VERSION 5.8 ;
BUSBITCHARS "[]" ;
DIVIDERCHAR "/" ;
UNITS
    DATABASE MICRONS 1000 ;
END UNITS

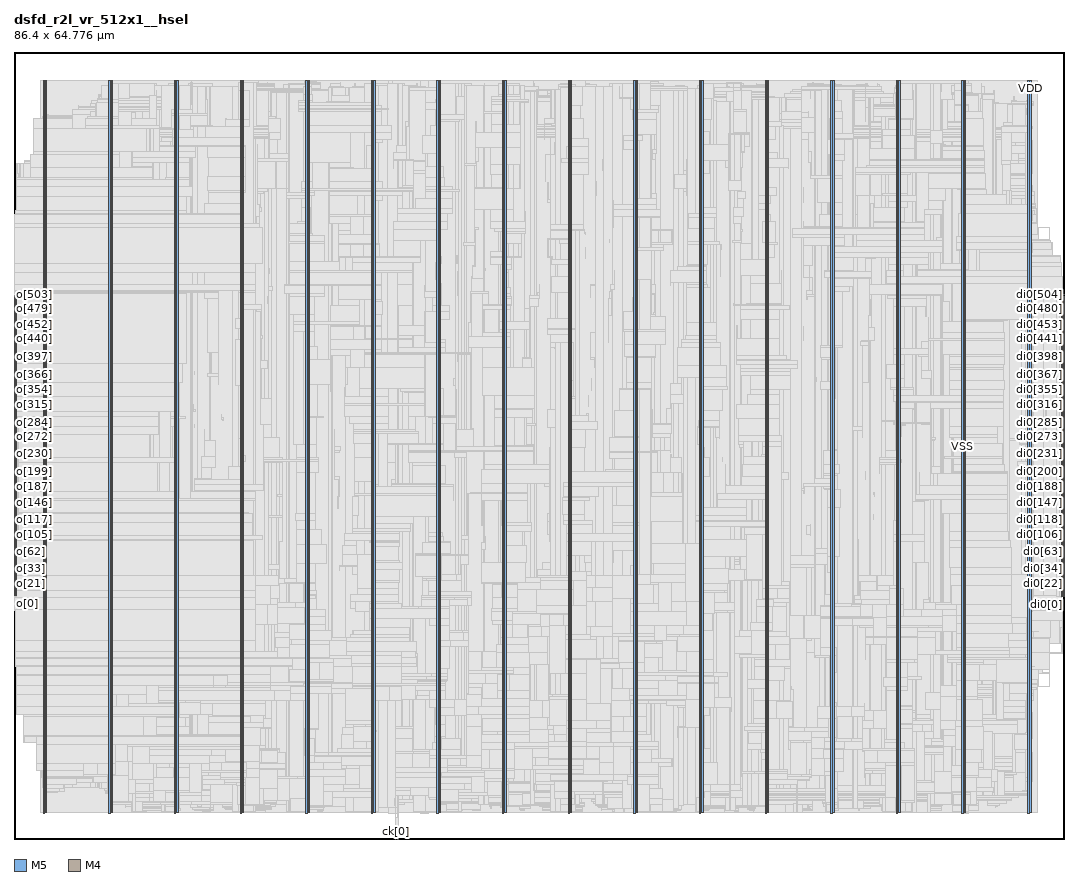
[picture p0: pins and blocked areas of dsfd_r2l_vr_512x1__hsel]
MACRO dsfd_r2l_vr_512x1__hsel
  FOREIGN dsfd_r2l_vr_512x1__hsel 0 0 ;
  CLASS BLOCK ;
  SIZE 86.4 BY 64.776 ;
  PIN ck[0]
    DIRECTION INPUT ;
    USE SIGNAL ;
    PORT
      LAYER M5 ;
        RECT  31.392 0 31.416 0.192 ;
    END
  END ck[0]
  PIN di0[0]
    DIRECTION INPUT ;
    USE SIGNAL ;
    PORT
      LAYER M4 ;
        RECT  86.208 19.968 86.4 19.992 ;
    END
  END di0[0]
  PIN di0[100]
    DIRECTION INPUT ;
    USE SIGNAL ;
    PORT
      LAYER M4 ;
        RECT  86.208 24.768 86.4 24.792 ;
    END
  END di0[100]
  PIN di0[101]
    DIRECTION INPUT ;
    USE SIGNAL ;
    PORT
      LAYER M4 ;
        RECT  86.208 24.816 86.4 24.84 ;
    END
  END di0[101]
  PIN di0[102]
    DIRECTION INPUT ;
    USE SIGNAL ;
    PORT
      LAYER M4 ;
        RECT  86.208 24.864 86.4 24.888 ;
    END
  END di0[102]
  PIN di0[103]
    DIRECTION INPUT ;
    USE SIGNAL ;
    PORT
      LAYER M4 ;
        RECT  86.208 24.912 86.4 24.936 ;
    END
  END di0[103]
  PIN di0[104]
    DIRECTION INPUT ;
    USE SIGNAL ;
    PORT
      LAYER M4 ;
        RECT  86.208 24.96 86.4 24.984 ;
    END
  END di0[104]
  PIN di0[105]
    DIRECTION INPUT ;
    USE SIGNAL ;
    PORT
      LAYER M4 ;
        RECT  86.208 25.008 86.4 25.032 ;
    END
  END di0[105]
  PIN di0[106]
    DIRECTION INPUT ;
    USE SIGNAL ;
    PORT
      LAYER M4 ;
        RECT  86.208 25.056 86.4 25.08 ;
    END
  END di0[106]
  PIN di0[107]
    DIRECTION INPUT ;
    USE SIGNAL ;
    PORT
      LAYER M4 ;
        RECT  86.208 25.104 86.4 25.128 ;
    END
  END di0[107]
  PIN di0[108]
    DIRECTION INPUT ;
    USE SIGNAL ;
    PORT
      LAYER M4 ;
        RECT  86.208 25.152 86.4 25.176 ;
    END
  END di0[108]
  PIN di0[109]
    DIRECTION INPUT ;
    USE SIGNAL ;
    PORT
      LAYER M4 ;
        RECT  86.208 25.2 86.4 25.224 ;
    END
  END di0[109]
  PIN di0[10]
    DIRECTION INPUT ;
    USE SIGNAL ;
    PORT
      LAYER M4 ;
        RECT  86.208 20.448 86.4 20.472 ;
    END
  END di0[10]
  PIN di0[110]
    DIRECTION INPUT ;
    USE SIGNAL ;
    PORT
      LAYER M4 ;
        RECT  86.208 25.248 86.4 25.272 ;
    END
  END di0[110]
  PIN di0[111]
    DIRECTION INPUT ;
    USE SIGNAL ;
    PORT
      LAYER M4 ;
        RECT  86.208 25.296 86.4 25.32 ;
    END
  END di0[111]
  PIN di0[112]
    DIRECTION INPUT ;
    USE SIGNAL ;
    PORT
      LAYER M4 ;
        RECT  86.208 25.344 86.4 25.368 ;
    END
  END di0[112]
  PIN di0[113]
    DIRECTION INPUT ;
    USE SIGNAL ;
    PORT
      LAYER M4 ;
        RECT  86.208 25.392 86.4 25.416 ;
    END
  END di0[113]
  PIN di0[114]
    DIRECTION INPUT ;
    USE SIGNAL ;
    PORT
      LAYER M4 ;
        RECT  86.208 25.44 86.4 25.464 ;
    END
  END di0[114]
  PIN di0[115]
    DIRECTION INPUT ;
    USE SIGNAL ;
    PORT
      LAYER M4 ;
        RECT  86.208 25.488 86.4 25.512 ;
    END
  END di0[115]
  PIN di0[116]
    DIRECTION INPUT ;
    USE SIGNAL ;
    PORT
      LAYER M4 ;
        RECT  86.208 25.536 86.4 25.56 ;
    END
  END di0[116]
  PIN di0[117]
    DIRECTION INPUT ;
    USE SIGNAL ;
    PORT
      LAYER M4 ;
        RECT  86.208 25.584 86.4 25.608 ;
    END
  END di0[117]
  PIN di0[118]
    DIRECTION INPUT ;
    USE SIGNAL ;
    PORT
      LAYER M4 ;
        RECT  86.208 25.632 86.4 25.656 ;
    END
  END di0[118]
  PIN di0[119]
    DIRECTION INPUT ;
    USE SIGNAL ;
    PORT
      LAYER M4 ;
        RECT  86.208 25.68 86.4 25.704 ;
    END
  END di0[119]
  PIN di0[11]
    DIRECTION INPUT ;
    USE SIGNAL ;
    PORT
      LAYER M4 ;
        RECT  86.208 20.496 86.4 20.52 ;
    END
  END di0[11]
  PIN di0[120]
    DIRECTION INPUT ;
    USE SIGNAL ;
    PORT
      LAYER M4 ;
        RECT  86.208 25.728 86.4 25.752 ;
    END
  END di0[120]
  PIN di0[121]
    DIRECTION INPUT ;
    USE SIGNAL ;
    PORT
      LAYER M4 ;
        RECT  86.208 25.776 86.4 25.8 ;
    END
  END di0[121]
  PIN di0[122]
    DIRECTION INPUT ;
    USE SIGNAL ;
    PORT
      LAYER M4 ;
        RECT  86.208 25.824 86.4 25.848 ;
    END
  END di0[122]
  PIN di0[123]
    DIRECTION INPUT ;
    USE SIGNAL ;
    PORT
      LAYER M4 ;
        RECT  86.208 25.872 86.4 25.896 ;
    END
  END di0[123]
  PIN di0[124]
    DIRECTION INPUT ;
    USE SIGNAL ;
    PORT
      LAYER M4 ;
        RECT  86.208 25.92 86.4 25.944 ;
    END
  END di0[124]
  PIN di0[125]
    DIRECTION INPUT ;
    USE SIGNAL ;
    PORT
      LAYER M4 ;
        RECT  86.208 25.968 86.4 25.992 ;
    END
  END di0[125]
  PIN di0[126]
    DIRECTION INPUT ;
    USE SIGNAL ;
    PORT
      LAYER M4 ;
        RECT  86.208 26.016 86.4 26.04 ;
    END
  END di0[126]
  PIN di0[127]
    DIRECTION INPUT ;
    USE SIGNAL ;
    PORT
      LAYER M4 ;
        RECT  86.208 26.064 86.4 26.088 ;
    END
  END di0[127]
  PIN di0[128]
    DIRECTION INPUT ;
    USE SIGNAL ;
    PORT
      LAYER M4 ;
        RECT  86.208 26.112 86.4 26.136 ;
    END
  END di0[128]
  PIN di0[129]
    DIRECTION INPUT ;
    USE SIGNAL ;
    PORT
      LAYER M4 ;
        RECT  86.208 26.16 86.4 26.184 ;
    END
  END di0[129]
  PIN di0[12]
    DIRECTION INPUT ;
    USE SIGNAL ;
    PORT
      LAYER M4 ;
        RECT  86.208 20.544 86.4 20.568 ;
    END
  END di0[12]
  PIN di0[130]
    DIRECTION INPUT ;
    USE SIGNAL ;
    PORT
      LAYER M4 ;
        RECT  86.208 26.208 86.4 26.232 ;
    END
  END di0[130]
  PIN di0[131]
    DIRECTION INPUT ;
    USE SIGNAL ;
    PORT
      LAYER M4 ;
        RECT  86.208 26.256 86.4 26.28 ;
    END
  END di0[131]
  PIN di0[132]
    DIRECTION INPUT ;
    USE SIGNAL ;
    PORT
      LAYER M4 ;
        RECT  86.208 26.304 86.4 26.328 ;
    END
  END di0[132]
  PIN di0[133]
    DIRECTION INPUT ;
    USE SIGNAL ;
    PORT
      LAYER M4 ;
        RECT  86.208 26.352 86.4 26.376 ;
    END
  END di0[133]
  PIN di0[134]
    DIRECTION INPUT ;
    USE SIGNAL ;
    PORT
      LAYER M4 ;
        RECT  86.208 26.4 86.4 26.424 ;
    END
  END di0[134]
  PIN di0[135]
    DIRECTION INPUT ;
    USE SIGNAL ;
    PORT
      LAYER M4 ;
        RECT  86.208 26.448 86.4 26.472 ;
    END
  END di0[135]
  PIN di0[136]
    DIRECTION INPUT ;
    USE SIGNAL ;
    PORT
      LAYER M4 ;
        RECT  86.208 26.496 86.4 26.52 ;
    END
  END di0[136]
  PIN di0[137]
    DIRECTION INPUT ;
    USE SIGNAL ;
    PORT
      LAYER M4 ;
        RECT  86.208 26.544 86.4 26.568 ;
    END
  END di0[137]
  PIN di0[138]
    DIRECTION INPUT ;
    USE SIGNAL ;
    PORT
      LAYER M4 ;
        RECT  86.208 26.592 86.4 26.616 ;
    END
  END di0[138]
  PIN di0[139]
    DIRECTION INPUT ;
    USE SIGNAL ;
    PORT
      LAYER M4 ;
        RECT  86.208 26.64 86.4 26.664 ;
    END
  END di0[139]
  PIN di0[13]
    DIRECTION INPUT ;
    USE SIGNAL ;
    PORT
      LAYER M4 ;
        RECT  86.208 20.592 86.4 20.616 ;
    END
  END di0[13]
  PIN di0[140]
    DIRECTION INPUT ;
    USE SIGNAL ;
    PORT
      LAYER M4 ;
        RECT  86.208 26.688 86.4 26.712 ;
    END
  END di0[140]
  PIN di0[141]
    DIRECTION INPUT ;
    USE SIGNAL ;
    PORT
      LAYER M4 ;
        RECT  86.208 26.736 86.4 26.76 ;
    END
  END di0[141]
  PIN di0[142]
    DIRECTION INPUT ;
    USE SIGNAL ;
    PORT
      LAYER M4 ;
        RECT  86.208 26.784 86.4 26.808 ;
    END
  END di0[142]
  PIN di0[143]
    DIRECTION INPUT ;
    USE SIGNAL ;
    PORT
      LAYER M4 ;
        RECT  86.208 26.832 86.4 26.856 ;
    END
  END di0[143]
  PIN di0[144]
    DIRECTION INPUT ;
    USE SIGNAL ;
    PORT
      LAYER M4 ;
        RECT  86.208 26.88 86.4 26.904 ;
    END
  END di0[144]
  PIN di0[145]
    DIRECTION INPUT ;
    USE SIGNAL ;
    PORT
      LAYER M4 ;
        RECT  86.208 26.928 86.4 26.952 ;
    END
  END di0[145]
  PIN di0[146]
    DIRECTION INPUT ;
    USE SIGNAL ;
    PORT
      LAYER M4 ;
        RECT  86.208 26.976 86.4 27 ;
    END
  END di0[146]
  PIN di0[147]
    DIRECTION INPUT ;
    USE SIGNAL ;
    PORT
      LAYER M4 ;
        RECT  86.208 27.024 86.4 27.048 ;
    END
  END di0[147]
  PIN di0[148]
    DIRECTION INPUT ;
    USE SIGNAL ;
    PORT
      LAYER M4 ;
        RECT  86.208 27.072 86.4 27.096 ;
    END
  END di0[148]
  PIN di0[149]
    DIRECTION INPUT ;
    USE SIGNAL ;
    PORT
      LAYER M4 ;
        RECT  86.208 27.12 86.4 27.144 ;
    END
  END di0[149]
  PIN di0[14]
    DIRECTION INPUT ;
    USE SIGNAL ;
    PORT
      LAYER M4 ;
        RECT  86.208 20.64 86.4 20.664 ;
    END
  END di0[14]
  PIN di0[150]
    DIRECTION INPUT ;
    USE SIGNAL ;
    PORT
      LAYER M4 ;
        RECT  86.208 27.168 86.4 27.192 ;
    END
  END di0[150]
  PIN di0[151]
    DIRECTION INPUT ;
    USE SIGNAL ;
    PORT
      LAYER M4 ;
        RECT  86.208 27.216 86.4 27.24 ;
    END
  END di0[151]
  PIN di0[152]
    DIRECTION INPUT ;
    USE SIGNAL ;
    PORT
      LAYER M4 ;
        RECT  86.208 27.264 86.4 27.288 ;
    END
  END di0[152]
  PIN di0[153]
    DIRECTION INPUT ;
    USE SIGNAL ;
    PORT
      LAYER M4 ;
        RECT  86.208 27.312 86.4 27.336 ;
    END
  END di0[153]
  PIN di0[154]
    DIRECTION INPUT ;
    USE SIGNAL ;
    PORT
      LAYER M4 ;
        RECT  86.208 27.36 86.4 27.384 ;
    END
  END di0[154]
  PIN di0[155]
    DIRECTION INPUT ;
    USE SIGNAL ;
    PORT
      LAYER M4 ;
        RECT  86.208 27.408 86.4 27.432 ;
    END
  END di0[155]
  PIN di0[156]
    DIRECTION INPUT ;
    USE SIGNAL ;
    PORT
      LAYER M4 ;
        RECT  86.208 27.456 86.4 27.48 ;
    END
  END di0[156]
  PIN di0[157]
    DIRECTION INPUT ;
    USE SIGNAL ;
    PORT
      LAYER M4 ;
        RECT  86.208 27.504 86.4 27.528 ;
    END
  END di0[157]
  PIN di0[158]
    DIRECTION INPUT ;
    USE SIGNAL ;
    PORT
      LAYER M4 ;
        RECT  86.208 27.552 86.4 27.576 ;
    END
  END di0[158]
  PIN di0[159]
    DIRECTION INPUT ;
    USE SIGNAL ;
    PORT
      LAYER M4 ;
        RECT  86.208 27.6 86.4 27.624 ;
    END
  END di0[159]
  PIN di0[15]
    DIRECTION INPUT ;
    USE SIGNAL ;
    PORT
      LAYER M4 ;
        RECT  86.208 20.688 86.4 20.712 ;
    END
  END di0[15]
  PIN di0[160]
    DIRECTION INPUT ;
    USE SIGNAL ;
    PORT
      LAYER M4 ;
        RECT  86.208 27.648 86.4 27.672 ;
    END
  END di0[160]
  PIN di0[161]
    DIRECTION INPUT ;
    USE SIGNAL ;
    PORT
      LAYER M4 ;
        RECT  86.208 27.696 86.4 27.72 ;
    END
  END di0[161]
  PIN di0[162]
    DIRECTION INPUT ;
    USE SIGNAL ;
    PORT
      LAYER M4 ;
        RECT  86.208 27.744 86.4 27.768 ;
    END
  END di0[162]
  PIN di0[163]
    DIRECTION INPUT ;
    USE SIGNAL ;
    PORT
      LAYER M4 ;
        RECT  86.208 27.792 86.4 27.816 ;
    END
  END di0[163]
  PIN di0[164]
    DIRECTION INPUT ;
    USE SIGNAL ;
    PORT
      LAYER M4 ;
        RECT  86.208 27.84 86.4 27.864 ;
    END
  END di0[164]
  PIN di0[165]
    DIRECTION INPUT ;
    USE SIGNAL ;
    PORT
      LAYER M4 ;
        RECT  86.208 27.888 86.4 27.912 ;
    END
  END di0[165]
  PIN di0[166]
    DIRECTION INPUT ;
    USE SIGNAL ;
    PORT
      LAYER M4 ;
        RECT  86.208 27.936 86.4 27.96 ;
    END
  END di0[166]
  PIN di0[167]
    DIRECTION INPUT ;
    USE SIGNAL ;
    PORT
      LAYER M4 ;
        RECT  86.208 27.984 86.4 28.008 ;
    END
  END di0[167]
  PIN di0[168]
    DIRECTION INPUT ;
    USE SIGNAL ;
    PORT
      LAYER M4 ;
        RECT  86.208 28.032 86.4 28.056 ;
    END
  END di0[168]
  PIN di0[169]
    DIRECTION INPUT ;
    USE SIGNAL ;
    PORT
      LAYER M4 ;
        RECT  86.208 28.08 86.4 28.104 ;
    END
  END di0[169]
  PIN di0[16]
    DIRECTION INPUT ;
    USE SIGNAL ;
    PORT
      LAYER M4 ;
        RECT  86.208 20.736 86.4 20.76 ;
    END
  END di0[16]
  PIN di0[170]
    DIRECTION INPUT ;
    USE SIGNAL ;
    PORT
      LAYER M4 ;
        RECT  86.208 28.128 86.4 28.152 ;
    END
  END di0[170]
  PIN di0[171]
    DIRECTION INPUT ;
    USE SIGNAL ;
    PORT
      LAYER M4 ;
        RECT  86.208 28.176 86.4 28.2 ;
    END
  END di0[171]
  PIN di0[172]
    DIRECTION INPUT ;
    USE SIGNAL ;
    PORT
      LAYER M4 ;
        RECT  86.208 28.224 86.4 28.248 ;
    END
  END di0[172]
  PIN di0[173]
    DIRECTION INPUT ;
    USE SIGNAL ;
    PORT
      LAYER M4 ;
        RECT  86.208 28.272 86.4 28.296 ;
    END
  END di0[173]
  PIN di0[174]
    DIRECTION INPUT ;
    USE SIGNAL ;
    PORT
      LAYER M4 ;
        RECT  86.208 28.32 86.4 28.344 ;
    END
  END di0[174]
  PIN di0[175]
    DIRECTION INPUT ;
    USE SIGNAL ;
    PORT
      LAYER M4 ;
        RECT  86.208 28.368 86.4 28.392 ;
    END
  END di0[175]
  PIN di0[176]
    DIRECTION INPUT ;
    USE SIGNAL ;
    PORT
      LAYER M4 ;
        RECT  86.208 28.416 86.4 28.44 ;
    END
  END di0[176]
  PIN di0[177]
    DIRECTION INPUT ;
    USE SIGNAL ;
    PORT
      LAYER M4 ;
        RECT  86.208 28.464 86.4 28.488 ;
    END
  END di0[177]
  PIN di0[178]
    DIRECTION INPUT ;
    USE SIGNAL ;
    PORT
      LAYER M4 ;
        RECT  86.208 28.512 86.4 28.536 ;
    END
  END di0[178]
  PIN di0[179]
    DIRECTION INPUT ;
    USE SIGNAL ;
    PORT
      LAYER M4 ;
        RECT  86.208 28.56 86.4 28.584 ;
    END
  END di0[179]
  PIN di0[17]
    DIRECTION INPUT ;
    USE SIGNAL ;
    PORT
      LAYER M4 ;
        RECT  86.208 20.784 86.4 20.808 ;
    END
  END di0[17]
  PIN di0[180]
    DIRECTION INPUT ;
    USE SIGNAL ;
    PORT
      LAYER M4 ;
        RECT  86.208 28.608 86.4 28.632 ;
    END
  END di0[180]
  PIN di0[181]
    DIRECTION INPUT ;
    USE SIGNAL ;
    PORT
      LAYER M4 ;
        RECT  86.208 28.656 86.4 28.68 ;
    END
  END di0[181]
  PIN di0[182]
    DIRECTION INPUT ;
    USE SIGNAL ;
    PORT
      LAYER M4 ;
        RECT  86.208 28.704 86.4 28.728 ;
    END
  END di0[182]
  PIN di0[183]
    DIRECTION INPUT ;
    USE SIGNAL ;
    PORT
      LAYER M4 ;
        RECT  86.208 28.752 86.4 28.776 ;
    END
  END di0[183]
  PIN di0[184]
    DIRECTION INPUT ;
    USE SIGNAL ;
    PORT
      LAYER M4 ;
        RECT  86.208 28.8 86.4 28.824 ;
    END
  END di0[184]
  PIN di0[185]
    DIRECTION INPUT ;
    USE SIGNAL ;
    PORT
      LAYER M4 ;
        RECT  86.208 28.848 86.4 28.872 ;
    END
  END di0[185]
  PIN di0[186]
    DIRECTION INPUT ;
    USE SIGNAL ;
    PORT
      LAYER M4 ;
        RECT  86.208 28.896 86.4 28.92 ;
    END
  END di0[186]
  PIN di0[187]
    DIRECTION INPUT ;
    USE SIGNAL ;
    PORT
      LAYER M4 ;
        RECT  86.208 28.944 86.4 28.968 ;
    END
  END di0[187]
  PIN di0[188]
    DIRECTION INPUT ;
    USE SIGNAL ;
    PORT
      LAYER M4 ;
        RECT  86.208 28.992 86.4 29.016 ;
    END
  END di0[188]
  PIN di0[189]
    DIRECTION INPUT ;
    USE SIGNAL ;
    PORT
      LAYER M4 ;
        RECT  86.208 29.04 86.4 29.064 ;
    END
  END di0[189]
  PIN di0[18]
    DIRECTION INPUT ;
    USE SIGNAL ;
    PORT
      LAYER M4 ;
        RECT  86.208 20.832 86.4 20.856 ;
    END
  END di0[18]
  PIN di0[190]
    DIRECTION INPUT ;
    USE SIGNAL ;
    PORT
      LAYER M4 ;
        RECT  86.208 29.088 86.4 29.112 ;
    END
  END di0[190]
  PIN di0[191]
    DIRECTION INPUT ;
    USE SIGNAL ;
    PORT
      LAYER M4 ;
        RECT  86.208 29.136 86.4 29.16 ;
    END
  END di0[191]
  PIN di0[192]
    DIRECTION INPUT ;
    USE SIGNAL ;
    PORT
      LAYER M4 ;
        RECT  86.208 29.184 86.4 29.208 ;
    END
  END di0[192]
  PIN di0[193]
    DIRECTION INPUT ;
    USE SIGNAL ;
    PORT
      LAYER M4 ;
        RECT  86.208 29.232 86.4 29.256 ;
    END
  END di0[193]
  PIN di0[194]
    DIRECTION INPUT ;
    USE SIGNAL ;
    PORT
      LAYER M4 ;
        RECT  86.208 29.28 86.4 29.304 ;
    END
  END di0[194]
  PIN di0[195]
    DIRECTION INPUT ;
    USE SIGNAL ;
    PORT
      LAYER M4 ;
        RECT  86.208 29.328 86.4 29.352 ;
    END
  END di0[195]
  PIN di0[196]
    DIRECTION INPUT ;
    USE SIGNAL ;
    PORT
      LAYER M4 ;
        RECT  86.208 29.376 86.4 29.4 ;
    END
  END di0[196]
  PIN di0[197]
    DIRECTION INPUT ;
    USE SIGNAL ;
    PORT
      LAYER M4 ;
        RECT  86.208 29.424 86.4 29.448 ;
    END
  END di0[197]
  PIN di0[198]
    DIRECTION INPUT ;
    USE SIGNAL ;
    PORT
      LAYER M4 ;
        RECT  86.208 29.472 86.4 29.496 ;
    END
  END di0[198]
  PIN di0[199]
    DIRECTION INPUT ;
    USE SIGNAL ;
    PORT
      LAYER M4 ;
        RECT  86.208 29.52 86.4 29.544 ;
    END
  END di0[199]
  PIN di0[19]
    DIRECTION INPUT ;
    USE SIGNAL ;
    PORT
      LAYER M4 ;
        RECT  86.208 20.88 86.4 20.904 ;
    END
  END di0[19]
  PIN di0[1]
    DIRECTION INPUT ;
    USE SIGNAL ;
    PORT
      LAYER M4 ;
        RECT  86.208 20.016 86.4 20.04 ;
    END
  END di0[1]
  PIN di0[200]
    DIRECTION INPUT ;
    USE SIGNAL ;
    PORT
      LAYER M4 ;
        RECT  86.208 29.568 86.4 29.592 ;
    END
  END di0[200]
  PIN di0[201]
    DIRECTION INPUT ;
    USE SIGNAL ;
    PORT
      LAYER M4 ;
        RECT  86.208 29.616 86.4 29.64 ;
    END
  END di0[201]
  PIN di0[202]
    DIRECTION INPUT ;
    USE SIGNAL ;
    PORT
      LAYER M4 ;
        RECT  86.208 29.664 86.4 29.688 ;
    END
  END di0[202]
  PIN di0[203]
    DIRECTION INPUT ;
    USE SIGNAL ;
    PORT
      LAYER M4 ;
        RECT  86.208 29.712 86.4 29.736 ;
    END
  END di0[203]
  PIN di0[204]
    DIRECTION INPUT ;
    USE SIGNAL ;
    PORT
      LAYER M4 ;
        RECT  86.208 29.76 86.4 29.784 ;
    END
  END di0[204]
  PIN di0[205]
    DIRECTION INPUT ;
    USE SIGNAL ;
    PORT
      LAYER M4 ;
        RECT  86.208 29.808 86.4 29.832 ;
    END
  END di0[205]
  PIN di0[206]
    DIRECTION INPUT ;
    USE SIGNAL ;
    PORT
      LAYER M4 ;
        RECT  86.208 29.856 86.4 29.88 ;
    END
  END di0[206]
  PIN di0[207]
    DIRECTION INPUT ;
    USE SIGNAL ;
    PORT
      LAYER M4 ;
        RECT  86.208 29.904 86.4 29.928 ;
    END
  END di0[207]
  PIN di0[208]
    DIRECTION INPUT ;
    USE SIGNAL ;
    PORT
      LAYER M4 ;
        RECT  86.208 29.952 86.4 29.976 ;
    END
  END di0[208]
  PIN di0[209]
    DIRECTION INPUT ;
    USE SIGNAL ;
    PORT
      LAYER M4 ;
        RECT  86.208 30 86.4 30.024 ;
    END
  END di0[209]
  PIN di0[20]
    DIRECTION INPUT ;
    USE SIGNAL ;
    PORT
      LAYER M4 ;
        RECT  86.208 20.928 86.4 20.952 ;
    END
  END di0[20]
  PIN di0[210]
    DIRECTION INPUT ;
    USE SIGNAL ;
    PORT
      LAYER M4 ;
        RECT  86.208 30.048 86.4 30.072 ;
    END
  END di0[210]
  PIN di0[211]
    DIRECTION INPUT ;
    USE SIGNAL ;
    PORT
      LAYER M4 ;
        RECT  86.208 30.096 86.4 30.12 ;
    END
  END di0[211]
  PIN di0[212]
    DIRECTION INPUT ;
    USE SIGNAL ;
    PORT
      LAYER M4 ;
        RECT  86.208 30.144 86.4 30.168 ;
    END
  END di0[212]
  PIN di0[213]
    DIRECTION INPUT ;
    USE SIGNAL ;
    PORT
      LAYER M4 ;
        RECT  86.208 30.192 86.4 30.216 ;
    END
  END di0[213]
  PIN di0[214]
    DIRECTION INPUT ;
    USE SIGNAL ;
    PORT
      LAYER M4 ;
        RECT  86.208 30.24 86.4 30.264 ;
    END
  END di0[214]
  PIN di0[215]
    DIRECTION INPUT ;
    USE SIGNAL ;
    PORT
      LAYER M4 ;
        RECT  86.208 30.288 86.4 30.312 ;
    END
  END di0[215]
  PIN di0[216]
    DIRECTION INPUT ;
    USE SIGNAL ;
    PORT
      LAYER M4 ;
        RECT  86.208 30.336 86.4 30.36 ;
    END
  END di0[216]
  PIN di0[217]
    DIRECTION INPUT ;
    USE SIGNAL ;
    PORT
      LAYER M4 ;
        RECT  86.208 30.384 86.4 30.408 ;
    END
  END di0[217]
  PIN di0[218]
    DIRECTION INPUT ;
    USE SIGNAL ;
    PORT
      LAYER M4 ;
        RECT  86.208 30.432 86.4 30.456 ;
    END
  END di0[218]
  PIN di0[219]
    DIRECTION INPUT ;
    USE SIGNAL ;
    PORT
      LAYER M4 ;
        RECT  86.208 30.48 86.4 30.504 ;
    END
  END di0[219]
  PIN di0[21]
    DIRECTION INPUT ;
    USE SIGNAL ;
    PORT
      LAYER M4 ;
        RECT  86.208 20.976 86.4 21 ;
    END
  END di0[21]
  PIN di0[220]
    DIRECTION INPUT ;
    USE SIGNAL ;
    PORT
      LAYER M4 ;
        RECT  86.208 30.528 86.4 30.552 ;
    END
  END di0[220]
  PIN di0[221]
    DIRECTION INPUT ;
    USE SIGNAL ;
    PORT
      LAYER M4 ;
        RECT  86.208 30.576 86.4 30.6 ;
    END
  END di0[221]
  PIN di0[222]
    DIRECTION INPUT ;
    USE SIGNAL ;
    PORT
      LAYER M4 ;
        RECT  86.208 30.624 86.4 30.648 ;
    END
  END di0[222]
  PIN di0[223]
    DIRECTION INPUT ;
    USE SIGNAL ;
    PORT
      LAYER M4 ;
        RECT  86.208 30.672 86.4 30.696 ;
    END
  END di0[223]
  PIN di0[224]
    DIRECTION INPUT ;
    USE SIGNAL ;
    PORT
      LAYER M4 ;
        RECT  86.208 30.72 86.4 30.744 ;
    END
  END di0[224]
  PIN di0[225]
    DIRECTION INPUT ;
    USE SIGNAL ;
    PORT
      LAYER M4 ;
        RECT  86.208 30.768 86.4 30.792 ;
    END
  END di0[225]
  PIN di0[226]
    DIRECTION INPUT ;
    USE SIGNAL ;
    PORT
      LAYER M4 ;
        RECT  86.208 30.816 86.4 30.84 ;
    END
  END di0[226]
  PIN di0[227]
    DIRECTION INPUT ;
    USE SIGNAL ;
    PORT
      LAYER M4 ;
        RECT  86.208 30.864 86.4 30.888 ;
    END
  END di0[227]
  PIN di0[228]
    DIRECTION INPUT ;
    USE SIGNAL ;
    PORT
      LAYER M4 ;
        RECT  86.208 30.912 86.4 30.936 ;
    END
  END di0[228]
  PIN di0[229]
    DIRECTION INPUT ;
    USE SIGNAL ;
    PORT
      LAYER M4 ;
        RECT  86.208 30.96 86.4 30.984 ;
    END
  END di0[229]
  PIN di0[22]
    DIRECTION INPUT ;
    USE SIGNAL ;
    PORT
      LAYER M4 ;
        RECT  86.208 21.024 86.4 21.048 ;
    END
  END di0[22]
  PIN di0[230]
    DIRECTION INPUT ;
    USE SIGNAL ;
    PORT
      LAYER M4 ;
        RECT  86.208 31.008 86.4 31.032 ;
    END
  END di0[230]
  PIN di0[231]
    DIRECTION INPUT ;
    USE SIGNAL ;
    PORT
      LAYER M4 ;
        RECT  86.208 31.056 86.4 31.08 ;
    END
  END di0[231]
  PIN di0[232]
    DIRECTION INPUT ;
    USE SIGNAL ;
    PORT
      LAYER M4 ;
        RECT  86.208 31.104 86.4 31.128 ;
    END
  END di0[232]
  PIN di0[233]
    DIRECTION INPUT ;
    USE SIGNAL ;
    PORT
      LAYER M4 ;
        RECT  86.208 31.152 86.4 31.176 ;
    END
  END di0[233]
  PIN di0[234]
    DIRECTION INPUT ;
    USE SIGNAL ;
    PORT
      LAYER M4 ;
        RECT  86.208 31.2 86.4 31.224 ;
    END
  END di0[234]
  PIN di0[235]
    DIRECTION INPUT ;
    USE SIGNAL ;
    PORT
      LAYER M4 ;
        RECT  86.208 31.248 86.4 31.272 ;
    END
  END di0[235]
  PIN di0[236]
    DIRECTION INPUT ;
    USE SIGNAL ;
    PORT
      LAYER M4 ;
        RECT  86.208 31.296 86.4 31.32 ;
    END
  END di0[236]
  PIN di0[237]
    DIRECTION INPUT ;
    USE SIGNAL ;
    PORT
      LAYER M4 ;
        RECT  86.208 31.344 86.4 31.368 ;
    END
  END di0[237]
  PIN di0[238]
    DIRECTION INPUT ;
    USE SIGNAL ;
    PORT
      LAYER M4 ;
        RECT  86.208 31.392 86.4 31.416 ;
    END
  END di0[238]
  PIN di0[239]
    DIRECTION INPUT ;
    USE SIGNAL ;
    PORT
      LAYER M4 ;
        RECT  86.208 31.44 86.4 31.464 ;
    END
  END di0[239]
  PIN di0[23]
    DIRECTION INPUT ;
    USE SIGNAL ;
    PORT
      LAYER M4 ;
        RECT  86.208 21.072 86.4 21.096 ;
    END
  END di0[23]
  PIN di0[240]
    DIRECTION INPUT ;
    USE SIGNAL ;
    PORT
      LAYER M4 ;
        RECT  86.208 31.488 86.4 31.512 ;
    END
  END di0[240]
  PIN di0[241]
    DIRECTION INPUT ;
    USE SIGNAL ;
    PORT
      LAYER M4 ;
        RECT  86.208 31.536 86.4 31.56 ;
    END
  END di0[241]
  PIN di0[242]
    DIRECTION INPUT ;
    USE SIGNAL ;
    PORT
      LAYER M4 ;
        RECT  86.208 31.584 86.4 31.608 ;
    END
  END di0[242]
  PIN di0[243]
    DIRECTION INPUT ;
    USE SIGNAL ;
    PORT
      LAYER M4 ;
        RECT  86.208 31.632 86.4 31.656 ;
    END
  END di0[243]
  PIN di0[244]
    DIRECTION INPUT ;
    USE SIGNAL ;
    PORT
      LAYER M4 ;
        RECT  86.208 31.68 86.4 31.704 ;
    END
  END di0[244]
  PIN di0[245]
    DIRECTION INPUT ;
    USE SIGNAL ;
    PORT
      LAYER M4 ;
        RECT  86.208 31.728 86.4 31.752 ;
    END
  END di0[245]
  PIN di0[246]
    DIRECTION INPUT ;
    USE SIGNAL ;
    PORT
      LAYER M4 ;
        RECT  86.208 31.776 86.4 31.8 ;
    END
  END di0[246]
  PIN di0[247]
    DIRECTION INPUT ;
    USE SIGNAL ;
    PORT
      LAYER M4 ;
        RECT  86.208 31.824 86.4 31.848 ;
    END
  END di0[247]
  PIN di0[248]
    DIRECTION INPUT ;
    USE SIGNAL ;
    PORT
      LAYER M4 ;
        RECT  86.208 31.872 86.4 31.896 ;
    END
  END di0[248]
  PIN di0[249]
    DIRECTION INPUT ;
    USE SIGNAL ;
    PORT
      LAYER M4 ;
        RECT  86.208 31.92 86.4 31.944 ;
    END
  END di0[249]
  PIN di0[24]
    DIRECTION INPUT ;
    USE SIGNAL ;
    PORT
      LAYER M4 ;
        RECT  86.208 21.12 86.4 21.144 ;
    END
  END di0[24]
  PIN di0[250]
    DIRECTION INPUT ;
    USE SIGNAL ;
    PORT
      LAYER M4 ;
        RECT  86.208 31.968 86.4 31.992 ;
    END
  END di0[250]
  PIN di0[251]
    DIRECTION INPUT ;
    USE SIGNAL ;
    PORT
      LAYER M4 ;
        RECT  86.208 32.016 86.4 32.04 ;
    END
  END di0[251]
  PIN di0[252]
    DIRECTION INPUT ;
    USE SIGNAL ;
    PORT
      LAYER M4 ;
        RECT  86.208 32.064 86.4 32.088 ;
    END
  END di0[252]
  PIN di0[253]
    DIRECTION INPUT ;
    USE SIGNAL ;
    PORT
      LAYER M4 ;
        RECT  86.208 32.112 86.4 32.136 ;
    END
  END di0[253]
  PIN di0[254]
    DIRECTION INPUT ;
    USE SIGNAL ;
    PORT
      LAYER M4 ;
        RECT  86.208 32.16 86.4 32.184 ;
    END
  END di0[254]
  PIN di0[255]
    DIRECTION INPUT ;
    USE SIGNAL ;
    PORT
      LAYER M4 ;
        RECT  86.208 32.208 86.4 32.232 ;
    END
  END di0[255]
  PIN di0[256]
    DIRECTION INPUT ;
    USE SIGNAL ;
    PORT
      LAYER M4 ;
        RECT  86.208 32.256 86.4 32.28 ;
    END
  END di0[256]
  PIN di0[257]
    DIRECTION INPUT ;
    USE SIGNAL ;
    PORT
      LAYER M4 ;
        RECT  86.208 32.304 86.4 32.328 ;
    END
  END di0[257]
  PIN di0[258]
    DIRECTION INPUT ;
    USE SIGNAL ;
    PORT
      LAYER M4 ;
        RECT  86.208 32.352 86.4 32.376 ;
    END
  END di0[258]
  PIN di0[259]
    DIRECTION INPUT ;
    USE SIGNAL ;
    PORT
      LAYER M4 ;
        RECT  86.208 32.4 86.4 32.424 ;
    END
  END di0[259]
  PIN di0[25]
    DIRECTION INPUT ;
    USE SIGNAL ;
    PORT
      LAYER M4 ;
        RECT  86.208 21.168 86.4 21.192 ;
    END
  END di0[25]
  PIN di0[260]
    DIRECTION INPUT ;
    USE SIGNAL ;
    PORT
      LAYER M4 ;
        RECT  86.208 32.448 86.4 32.472 ;
    END
  END di0[260]
  PIN di0[261]
    DIRECTION INPUT ;
    USE SIGNAL ;
    PORT
      LAYER M4 ;
        RECT  86.208 32.496 86.4 32.52 ;
    END
  END di0[261]
  PIN di0[262]
    DIRECTION INPUT ;
    USE SIGNAL ;
    PORT
      LAYER M4 ;
        RECT  86.208 32.544 86.4 32.568 ;
    END
  END di0[262]
  PIN di0[263]
    DIRECTION INPUT ;
    USE SIGNAL ;
    PORT
      LAYER M4 ;
        RECT  86.208 32.592 86.4 32.616 ;
    END
  END di0[263]
  PIN di0[264]
    DIRECTION INPUT ;
    USE SIGNAL ;
    PORT
      LAYER M4 ;
        RECT  86.208 32.64 86.4 32.664 ;
    END
  END di0[264]
  PIN di0[265]
    DIRECTION INPUT ;
    USE SIGNAL ;
    PORT
      LAYER M4 ;
        RECT  86.208 32.688 86.4 32.712 ;
    END
  END di0[265]
  PIN di0[266]
    DIRECTION INPUT ;
    USE SIGNAL ;
    PORT
      LAYER M4 ;
        RECT  86.208 32.736 86.4 32.76 ;
    END
  END di0[266]
  PIN di0[267]
    DIRECTION INPUT ;
    USE SIGNAL ;
    PORT
      LAYER M4 ;
        RECT  86.208 32.784 86.4 32.808 ;
    END
  END di0[267]
  PIN di0[268]
    DIRECTION INPUT ;
    USE SIGNAL ;
    PORT
      LAYER M4 ;
        RECT  86.208 32.832 86.4 32.856 ;
    END
  END di0[268]
  PIN di0[269]
    DIRECTION INPUT ;
    USE SIGNAL ;
    PORT
      LAYER M4 ;
        RECT  86.208 32.88 86.4 32.904 ;
    END
  END di0[269]
  PIN di0[26]
    DIRECTION INPUT ;
    USE SIGNAL ;
    PORT
      LAYER M4 ;
        RECT  86.208 21.216 86.4 21.24 ;
    END
  END di0[26]
  PIN di0[270]
    DIRECTION INPUT ;
    USE SIGNAL ;
    PORT
      LAYER M4 ;
        RECT  86.208 32.928 86.4 32.952 ;
    END
  END di0[270]
  PIN di0[271]
    DIRECTION INPUT ;
    USE SIGNAL ;
    PORT
      LAYER M4 ;
        RECT  86.208 32.976 86.4 33 ;
    END
  END di0[271]
  PIN di0[272]
    DIRECTION INPUT ;
    USE SIGNAL ;
    PORT
      LAYER M4 ;
        RECT  86.208 33.024 86.4 33.048 ;
    END
  END di0[272]
  PIN di0[273]
    DIRECTION INPUT ;
    USE SIGNAL ;
    PORT
      LAYER M4 ;
        RECT  86.208 33.072 86.4 33.096 ;
    END
  END di0[273]
  PIN di0[274]
    DIRECTION INPUT ;
    USE SIGNAL ;
    PORT
      LAYER M4 ;
        RECT  86.208 33.12 86.4 33.144 ;
    END
  END di0[274]
  PIN di0[275]
    DIRECTION INPUT ;
    USE SIGNAL ;
    PORT
      LAYER M4 ;
        RECT  86.208 33.168 86.4 33.192 ;
    END
  END di0[275]
  PIN di0[276]
    DIRECTION INPUT ;
    USE SIGNAL ;
    PORT
      LAYER M4 ;
        RECT  86.208 33.216 86.4 33.24 ;
    END
  END di0[276]
  PIN di0[277]
    DIRECTION INPUT ;
    USE SIGNAL ;
    PORT
      LAYER M4 ;
        RECT  86.208 33.264 86.4 33.288 ;
    END
  END di0[277]
  PIN di0[278]
    DIRECTION INPUT ;
    USE SIGNAL ;
    PORT
      LAYER M4 ;
        RECT  86.208 33.312 86.4 33.336 ;
    END
  END di0[278]
  PIN di0[279]
    DIRECTION INPUT ;
    USE SIGNAL ;
    PORT
      LAYER M4 ;
        RECT  86.208 33.36 86.4 33.384 ;
    END
  END di0[279]
  PIN di0[27]
    DIRECTION INPUT ;
    USE SIGNAL ;
    PORT
      LAYER M4 ;
        RECT  86.208 21.264 86.4 21.288 ;
    END
  END di0[27]
  PIN di0[280]
    DIRECTION INPUT ;
    USE SIGNAL ;
    PORT
      LAYER M4 ;
        RECT  86.208 33.408 86.4 33.432 ;
    END
  END di0[280]
  PIN di0[281]
    DIRECTION INPUT ;
    USE SIGNAL ;
    PORT
      LAYER M4 ;
        RECT  86.208 33.456 86.4 33.48 ;
    END
  END di0[281]
  PIN di0[282]
    DIRECTION INPUT ;
    USE SIGNAL ;
    PORT
      LAYER M4 ;
        RECT  86.208 33.504 86.4 33.528 ;
    END
  END di0[282]
  PIN di0[283]
    DIRECTION INPUT ;
    USE SIGNAL ;
    PORT
      LAYER M4 ;
        RECT  86.208 33.552 86.4 33.576 ;
    END
  END di0[283]
  PIN di0[284]
    DIRECTION INPUT ;
    USE SIGNAL ;
    PORT
      LAYER M4 ;
        RECT  86.208 33.6 86.4 33.624 ;
    END
  END di0[284]
  PIN di0[285]
    DIRECTION INPUT ;
    USE SIGNAL ;
    PORT
      LAYER M4 ;
        RECT  86.208 33.648 86.4 33.672 ;
    END
  END di0[285]
  PIN di0[286]
    DIRECTION INPUT ;
    USE SIGNAL ;
    PORT
      LAYER M4 ;
        RECT  86.208 33.696 86.4 33.72 ;
    END
  END di0[286]
  PIN di0[287]
    DIRECTION INPUT ;
    USE SIGNAL ;
    PORT
      LAYER M4 ;
        RECT  86.208 33.744 86.4 33.768 ;
    END
  END di0[287]
  PIN di0[288]
    DIRECTION INPUT ;
    USE SIGNAL ;
    PORT
      LAYER M4 ;
        RECT  86.208 33.792 86.4 33.816 ;
    END
  END di0[288]
  PIN di0[289]
    DIRECTION INPUT ;
    USE SIGNAL ;
    PORT
      LAYER M4 ;
        RECT  86.208 33.84 86.4 33.864 ;
    END
  END di0[289]
  PIN di0[28]
    DIRECTION INPUT ;
    USE SIGNAL ;
    PORT
      LAYER M4 ;
        RECT  86.208 21.312 86.4 21.336 ;
    END
  END di0[28]
  PIN di0[290]
    DIRECTION INPUT ;
    USE SIGNAL ;
    PORT
      LAYER M4 ;
        RECT  86.208 33.888 86.4 33.912 ;
    END
  END di0[290]
  PIN di0[291]
    DIRECTION INPUT ;
    USE SIGNAL ;
    PORT
      LAYER M4 ;
        RECT  86.208 33.936 86.4 33.96 ;
    END
  END di0[291]
  PIN di0[292]
    DIRECTION INPUT ;
    USE SIGNAL ;
    PORT
      LAYER M4 ;
        RECT  86.208 33.984 86.4 34.008 ;
    END
  END di0[292]
  PIN di0[293]
    DIRECTION INPUT ;
    USE SIGNAL ;
    PORT
      LAYER M4 ;
        RECT  86.208 34.032 86.4 34.056 ;
    END
  END di0[293]
  PIN di0[294]
    DIRECTION INPUT ;
    USE SIGNAL ;
    PORT
      LAYER M4 ;
        RECT  86.208 34.08 86.4 34.104 ;
    END
  END di0[294]
  PIN di0[295]
    DIRECTION INPUT ;
    USE SIGNAL ;
    PORT
      LAYER M4 ;
        RECT  86.208 34.128 86.4 34.152 ;
    END
  END di0[295]
  PIN di0[296]
    DIRECTION INPUT ;
    USE SIGNAL ;
    PORT
      LAYER M4 ;
        RECT  86.208 34.176 86.4 34.2 ;
    END
  END di0[296]
  PIN di0[297]
    DIRECTION INPUT ;
    USE SIGNAL ;
    PORT
      LAYER M4 ;
        RECT  86.208 34.224 86.4 34.248 ;
    END
  END di0[297]
  PIN di0[298]
    DIRECTION INPUT ;
    USE SIGNAL ;
    PORT
      LAYER M4 ;
        RECT  86.208 34.272 86.4 34.296 ;
    END
  END di0[298]
  PIN di0[299]
    DIRECTION INPUT ;
    USE SIGNAL ;
    PORT
      LAYER M4 ;
        RECT  86.208 34.32 86.4 34.344 ;
    END
  END di0[299]
  PIN di0[29]
    DIRECTION INPUT ;
    USE SIGNAL ;
    PORT
      LAYER M4 ;
        RECT  86.208 21.36 86.4 21.384 ;
    END
  END di0[29]
  PIN di0[2]
    DIRECTION INPUT ;
    USE SIGNAL ;
    PORT
      LAYER M4 ;
        RECT  86.208 20.064 86.4 20.088 ;
    END
  END di0[2]
  PIN di0[300]
    DIRECTION INPUT ;
    USE SIGNAL ;
    PORT
      LAYER M4 ;
        RECT  86.208 34.368 86.4 34.392 ;
    END
  END di0[300]
  PIN di0[301]
    DIRECTION INPUT ;
    USE SIGNAL ;
    PORT
      LAYER M4 ;
        RECT  86.208 34.416 86.4 34.44 ;
    END
  END di0[301]
  PIN di0[302]
    DIRECTION INPUT ;
    USE SIGNAL ;
    PORT
      LAYER M4 ;
        RECT  86.208 34.464 86.4 34.488 ;
    END
  END di0[302]
  PIN di0[303]
    DIRECTION INPUT ;
    USE SIGNAL ;
    PORT
      LAYER M4 ;
        RECT  86.208 34.512 86.4 34.536 ;
    END
  END di0[303]
  PIN di0[304]
    DIRECTION INPUT ;
    USE SIGNAL ;
    PORT
      LAYER M4 ;
        RECT  86.208 34.56 86.4 34.584 ;
    END
  END di0[304]
  PIN di0[305]
    DIRECTION INPUT ;
    USE SIGNAL ;
    PORT
      LAYER M4 ;
        RECT  86.208 34.608 86.4 34.632 ;
    END
  END di0[305]
  PIN di0[306]
    DIRECTION INPUT ;
    USE SIGNAL ;
    PORT
      LAYER M4 ;
        RECT  86.208 34.656 86.4 34.68 ;
    END
  END di0[306]
  PIN di0[307]
    DIRECTION INPUT ;
    USE SIGNAL ;
    PORT
      LAYER M4 ;
        RECT  86.208 34.704 86.4 34.728 ;
    END
  END di0[307]
  PIN di0[308]
    DIRECTION INPUT ;
    USE SIGNAL ;
    PORT
      LAYER M4 ;
        RECT  86.208 34.752 86.4 34.776 ;
    END
  END di0[308]
  PIN di0[309]
    DIRECTION INPUT ;
    USE SIGNAL ;
    PORT
      LAYER M4 ;
        RECT  86.208 34.8 86.4 34.824 ;
    END
  END di0[309]
  PIN di0[30]
    DIRECTION INPUT ;
    USE SIGNAL ;
    PORT
      LAYER M4 ;
        RECT  86.208 21.408 86.4 21.432 ;
    END
  END di0[30]
  PIN di0[310]
    DIRECTION INPUT ;
    USE SIGNAL ;
    PORT
      LAYER M4 ;
        RECT  86.208 34.848 86.4 34.872 ;
    END
  END di0[310]
  PIN di0[311]
    DIRECTION INPUT ;
    USE SIGNAL ;
    PORT
      LAYER M4 ;
        RECT  86.208 34.896 86.4 34.92 ;
    END
  END di0[311]
  PIN di0[312]
    DIRECTION INPUT ;
    USE SIGNAL ;
    PORT
      LAYER M4 ;
        RECT  86.208 34.944 86.4 34.968 ;
    END
  END di0[312]
  PIN di0[313]
    DIRECTION INPUT ;
    USE SIGNAL ;
    PORT
      LAYER M4 ;
        RECT  86.208 34.992 86.4 35.016 ;
    END
  END di0[313]
  PIN di0[314]
    DIRECTION INPUT ;
    USE SIGNAL ;
    PORT
      LAYER M4 ;
        RECT  86.208 35.04 86.4 35.064 ;
    END
  END di0[314]
  PIN di0[315]
    DIRECTION INPUT ;
    USE SIGNAL ;
    PORT
      LAYER M4 ;
        RECT  86.208 35.088 86.4 35.112 ;
    END
  END di0[315]
  PIN di0[316]
    DIRECTION INPUT ;
    USE SIGNAL ;
    PORT
      LAYER M4 ;
        RECT  86.208 35.136 86.4 35.16 ;
    END
  END di0[316]
  PIN di0[317]
    DIRECTION INPUT ;
    USE SIGNAL ;
    PORT
      LAYER M4 ;
        RECT  86.208 35.184 86.4 35.208 ;
    END
  END di0[317]
  PIN di0[318]
    DIRECTION INPUT ;
    USE SIGNAL ;
    PORT
      LAYER M4 ;
        RECT  86.208 35.232 86.4 35.256 ;
    END
  END di0[318]
  PIN di0[319]
    DIRECTION INPUT ;
    USE SIGNAL ;
    PORT
      LAYER M4 ;
        RECT  86.208 35.28 86.4 35.304 ;
    END
  END di0[319]
  PIN di0[31]
    DIRECTION INPUT ;
    USE SIGNAL ;
    PORT
      LAYER M4 ;
        RECT  86.208 21.456 86.4 21.48 ;
    END
  END di0[31]
  PIN di0[320]
    DIRECTION INPUT ;
    USE SIGNAL ;
    PORT
      LAYER M4 ;
        RECT  86.208 35.328 86.4 35.352 ;
    END
  END di0[320]
  PIN di0[321]
    DIRECTION INPUT ;
    USE SIGNAL ;
    PORT
      LAYER M4 ;
        RECT  86.208 35.376 86.4 35.4 ;
    END
  END di0[321]
  PIN di0[322]
    DIRECTION INPUT ;
    USE SIGNAL ;
    PORT
      LAYER M4 ;
        RECT  86.208 35.424 86.4 35.448 ;
    END
  END di0[322]
  PIN di0[323]
    DIRECTION INPUT ;
    USE SIGNAL ;
    PORT
      LAYER M4 ;
        RECT  86.208 35.472 86.4 35.496 ;
    END
  END di0[323]
  PIN di0[324]
    DIRECTION INPUT ;
    USE SIGNAL ;
    PORT
      LAYER M4 ;
        RECT  86.208 35.52 86.4 35.544 ;
    END
  END di0[324]
  PIN di0[325]
    DIRECTION INPUT ;
    USE SIGNAL ;
    PORT
      LAYER M4 ;
        RECT  86.208 35.568 86.4 35.592 ;
    END
  END di0[325]
  PIN di0[326]
    DIRECTION INPUT ;
    USE SIGNAL ;
    PORT
      LAYER M4 ;
        RECT  86.208 35.616 86.4 35.64 ;
    END
  END di0[326]
  PIN di0[327]
    DIRECTION INPUT ;
    USE SIGNAL ;
    PORT
      LAYER M4 ;
        RECT  86.208 35.664 86.4 35.688 ;
    END
  END di0[327]
  PIN di0[328]
    DIRECTION INPUT ;
    USE SIGNAL ;
    PORT
      LAYER M4 ;
        RECT  86.208 35.712 86.4 35.736 ;
    END
  END di0[328]
  PIN di0[329]
    DIRECTION INPUT ;
    USE SIGNAL ;
    PORT
      LAYER M4 ;
        RECT  86.208 35.76 86.4 35.784 ;
    END
  END di0[329]
  PIN di0[32]
    DIRECTION INPUT ;
    USE SIGNAL ;
    PORT
      LAYER M4 ;
        RECT  86.208 21.504 86.4 21.528 ;
    END
  END di0[32]
  PIN di0[330]
    DIRECTION INPUT ;
    USE SIGNAL ;
    PORT
      LAYER M4 ;
        RECT  86.208 35.808 86.4 35.832 ;
    END
  END di0[330]
  PIN di0[331]
    DIRECTION INPUT ;
    USE SIGNAL ;
    PORT
      LAYER M4 ;
        RECT  86.208 35.856 86.4 35.88 ;
    END
  END di0[331]
  PIN di0[332]
    DIRECTION INPUT ;
    USE SIGNAL ;
    PORT
      LAYER M4 ;
        RECT  86.208 35.904 86.4 35.928 ;
    END
  END di0[332]
  PIN di0[333]
    DIRECTION INPUT ;
    USE SIGNAL ;
    PORT
      LAYER M4 ;
        RECT  86.208 35.952 86.4 35.976 ;
    END
  END di0[333]
  PIN di0[334]
    DIRECTION INPUT ;
    USE SIGNAL ;
    PORT
      LAYER M4 ;
        RECT  86.208 36 86.4 36.024 ;
    END
  END di0[334]
  PIN di0[335]
    DIRECTION INPUT ;
    USE SIGNAL ;
    PORT
      LAYER M4 ;
        RECT  86.208 36.048 86.4 36.072 ;
    END
  END di0[335]
  PIN di0[336]
    DIRECTION INPUT ;
    USE SIGNAL ;
    PORT
      LAYER M4 ;
        RECT  86.208 36.096 86.4 36.12 ;
    END
  END di0[336]
  PIN di0[337]
    DIRECTION INPUT ;
    USE SIGNAL ;
    PORT
      LAYER M4 ;
        RECT  86.208 36.144 86.4 36.168 ;
    END
  END di0[337]
  PIN di0[338]
    DIRECTION INPUT ;
    USE SIGNAL ;
    PORT
      LAYER M4 ;
        RECT  86.208 36.192 86.4 36.216 ;
    END
  END di0[338]
  PIN di0[339]
    DIRECTION INPUT ;
    USE SIGNAL ;
    PORT
      LAYER M4 ;
        RECT  86.208 36.24 86.4 36.264 ;
    END
  END di0[339]
  PIN di0[33]
    DIRECTION INPUT ;
    USE SIGNAL ;
    PORT
      LAYER M4 ;
        RECT  86.208 21.552 86.4 21.576 ;
    END
  END di0[33]
  PIN di0[340]
    DIRECTION INPUT ;
    USE SIGNAL ;
    PORT
      LAYER M4 ;
        RECT  86.208 36.288 86.4 36.312 ;
    END
  END di0[340]
  PIN di0[341]
    DIRECTION INPUT ;
    USE SIGNAL ;
    PORT
      LAYER M4 ;
        RECT  86.208 36.336 86.4 36.36 ;
    END
  END di0[341]
  PIN di0[342]
    DIRECTION INPUT ;
    USE SIGNAL ;
    PORT
      LAYER M4 ;
        RECT  86.208 36.384 86.4 36.408 ;
    END
  END di0[342]
  PIN di0[343]
    DIRECTION INPUT ;
    USE SIGNAL ;
    PORT
      LAYER M4 ;
        RECT  86.208 36.432 86.4 36.456 ;
    END
  END di0[343]
  PIN di0[344]
    DIRECTION INPUT ;
    USE SIGNAL ;
    PORT
      LAYER M4 ;
        RECT  86.208 36.48 86.4 36.504 ;
    END
  END di0[344]
  PIN di0[345]
    DIRECTION INPUT ;
    USE SIGNAL ;
    PORT
      LAYER M4 ;
        RECT  86.208 36.528 86.4 36.552 ;
    END
  END di0[345]
  PIN di0[346]
    DIRECTION INPUT ;
    USE SIGNAL ;
    PORT
      LAYER M4 ;
        RECT  86.208 36.576 86.4 36.6 ;
    END
  END di0[346]
  PIN di0[347]
    DIRECTION INPUT ;
    USE SIGNAL ;
    PORT
      LAYER M4 ;
        RECT  86.208 36.624 86.4 36.648 ;
    END
  END di0[347]
  PIN di0[348]
    DIRECTION INPUT ;
    USE SIGNAL ;
    PORT
      LAYER M4 ;
        RECT  86.208 36.672 86.4 36.696 ;
    END
  END di0[348]
  PIN di0[349]
    DIRECTION INPUT ;
    USE SIGNAL ;
    PORT
      LAYER M4 ;
        RECT  86.208 36.72 86.4 36.744 ;
    END
  END di0[349]
  PIN di0[34]
    DIRECTION INPUT ;
    USE SIGNAL ;
    PORT
      LAYER M4 ;
        RECT  86.208 21.6 86.4 21.624 ;
    END
  END di0[34]
  PIN di0[350]
    DIRECTION INPUT ;
    USE SIGNAL ;
    PORT
      LAYER M4 ;
        RECT  86.208 36.768 86.4 36.792 ;
    END
  END di0[350]
  PIN di0[351]
    DIRECTION INPUT ;
    USE SIGNAL ;
    PORT
      LAYER M4 ;
        RECT  86.208 36.816 86.4 36.84 ;
    END
  END di0[351]
  PIN di0[352]
    DIRECTION INPUT ;
    USE SIGNAL ;
    PORT
      LAYER M4 ;
        RECT  86.208 36.864 86.4 36.888 ;
    END
  END di0[352]
  PIN di0[353]
    DIRECTION INPUT ;
    USE SIGNAL ;
    PORT
      LAYER M4 ;
        RECT  86.208 36.912 86.4 36.936 ;
    END
  END di0[353]
  PIN di0[354]
    DIRECTION INPUT ;
    USE SIGNAL ;
    PORT
      LAYER M4 ;
        RECT  86.208 36.96 86.4 36.984 ;
    END
  END di0[354]
  PIN di0[355]
    DIRECTION INPUT ;
    USE SIGNAL ;
    PORT
      LAYER M4 ;
        RECT  86.208 37.008 86.4 37.032 ;
    END
  END di0[355]
  PIN di0[356]
    DIRECTION INPUT ;
    USE SIGNAL ;
    PORT
      LAYER M4 ;
        RECT  86.208 37.056 86.4 37.08 ;
    END
  END di0[356]
  PIN di0[357]
    DIRECTION INPUT ;
    USE SIGNAL ;
    PORT
      LAYER M4 ;
        RECT  86.208 37.104 86.4 37.128 ;
    END
  END di0[357]
  PIN di0[358]
    DIRECTION INPUT ;
    USE SIGNAL ;
    PORT
      LAYER M4 ;
        RECT  86.208 37.152 86.4 37.176 ;
    END
  END di0[358]
  PIN di0[359]
    DIRECTION INPUT ;
    USE SIGNAL ;
    PORT
      LAYER M4 ;
        RECT  86.208 37.2 86.4 37.224 ;
    END
  END di0[359]
  PIN di0[35]
    DIRECTION INPUT ;
    USE SIGNAL ;
    PORT
      LAYER M4 ;
        RECT  86.208 21.648 86.4 21.672 ;
    END
  END di0[35]
  PIN di0[360]
    DIRECTION INPUT ;
    USE SIGNAL ;
    PORT
      LAYER M4 ;
        RECT  86.208 37.248 86.4 37.272 ;
    END
  END di0[360]
  PIN di0[361]
    DIRECTION INPUT ;
    USE SIGNAL ;
    PORT
      LAYER M4 ;
        RECT  86.208 37.296 86.4 37.32 ;
    END
  END di0[361]
  PIN di0[362]
    DIRECTION INPUT ;
    USE SIGNAL ;
    PORT
      LAYER M4 ;
        RECT  86.208 37.344 86.4 37.368 ;
    END
  END di0[362]
  PIN di0[363]
    DIRECTION INPUT ;
    USE SIGNAL ;
    PORT
      LAYER M4 ;
        RECT  86.208 37.392 86.4 37.416 ;
    END
  END di0[363]
  PIN di0[364]
    DIRECTION INPUT ;
    USE SIGNAL ;
    PORT
      LAYER M4 ;
        RECT  86.208 37.44 86.4 37.464 ;
    END
  END di0[364]
  PIN di0[365]
    DIRECTION INPUT ;
    USE SIGNAL ;
    PORT
      LAYER M4 ;
        RECT  86.208 37.488 86.4 37.512 ;
    END
  END di0[365]
  PIN di0[366]
    DIRECTION INPUT ;
    USE SIGNAL ;
    PORT
      LAYER M4 ;
        RECT  86.208 37.536 86.4 37.56 ;
    END
  END di0[366]
  PIN di0[367]
    DIRECTION INPUT ;
    USE SIGNAL ;
    PORT
      LAYER M4 ;
        RECT  86.208 37.584 86.4 37.608 ;
    END
  END di0[367]
  PIN di0[368]
    DIRECTION INPUT ;
    USE SIGNAL ;
    PORT
      LAYER M4 ;
        RECT  86.208 37.632 86.4 37.656 ;
    END
  END di0[368]
  PIN di0[369]
    DIRECTION INPUT ;
    USE SIGNAL ;
    PORT
      LAYER M4 ;
        RECT  86.208 37.68 86.4 37.704 ;
    END
  END di0[369]
  PIN di0[36]
    DIRECTION INPUT ;
    USE SIGNAL ;
    PORT
      LAYER M4 ;
        RECT  86.208 21.696 86.4 21.72 ;
    END
  END di0[36]
  PIN di0[370]
    DIRECTION INPUT ;
    USE SIGNAL ;
    PORT
      LAYER M4 ;
        RECT  86.208 37.728 86.4 37.752 ;
    END
  END di0[370]
  PIN di0[371]
    DIRECTION INPUT ;
    USE SIGNAL ;
    PORT
      LAYER M4 ;
        RECT  86.208 37.776 86.4 37.8 ;
    END
  END di0[371]
  PIN di0[372]
    DIRECTION INPUT ;
    USE SIGNAL ;
    PORT
      LAYER M4 ;
        RECT  86.208 37.824 86.4 37.848 ;
    END
  END di0[372]
  PIN di0[373]
    DIRECTION INPUT ;
    USE SIGNAL ;
    PORT
      LAYER M4 ;
        RECT  86.208 37.872 86.4 37.896 ;
    END
  END di0[373]
  PIN di0[374]
    DIRECTION INPUT ;
    USE SIGNAL ;
    PORT
      LAYER M4 ;
        RECT  86.208 37.92 86.4 37.944 ;
    END
  END di0[374]
  PIN di0[375]
    DIRECTION INPUT ;
    USE SIGNAL ;
    PORT
      LAYER M4 ;
        RECT  86.208 37.968 86.4 37.992 ;
    END
  END di0[375]
  PIN di0[376]
    DIRECTION INPUT ;
    USE SIGNAL ;
    PORT
      LAYER M4 ;
        RECT  86.208 38.016 86.4 38.04 ;
    END
  END di0[376]
  PIN di0[377]
    DIRECTION INPUT ;
    USE SIGNAL ;
    PORT
      LAYER M4 ;
        RECT  86.208 38.064 86.4 38.088 ;
    END
  END di0[377]
  PIN di0[378]
    DIRECTION INPUT ;
    USE SIGNAL ;
    PORT
      LAYER M4 ;
        RECT  86.208 38.112 86.4 38.136 ;
    END
  END di0[378]
  PIN di0[379]
    DIRECTION INPUT ;
    USE SIGNAL ;
    PORT
      LAYER M4 ;
        RECT  86.208 38.16 86.4 38.184 ;
    END
  END di0[379]
  PIN di0[37]
    DIRECTION INPUT ;
    USE SIGNAL ;
    PORT
      LAYER M4 ;
        RECT  86.208 21.744 86.4 21.768 ;
    END
  END di0[37]
  PIN di0[380]
    DIRECTION INPUT ;
    USE SIGNAL ;
    PORT
      LAYER M4 ;
        RECT  86.208 38.208 86.4 38.232 ;
    END
  END di0[380]
  PIN di0[381]
    DIRECTION INPUT ;
    USE SIGNAL ;
    PORT
      LAYER M4 ;
        RECT  86.208 38.256 86.4 38.28 ;
    END
  END di0[381]
  PIN di0[382]
    DIRECTION INPUT ;
    USE SIGNAL ;
    PORT
      LAYER M4 ;
        RECT  86.208 38.304 86.4 38.328 ;
    END
  END di0[382]
  PIN di0[383]
    DIRECTION INPUT ;
    USE SIGNAL ;
    PORT
      LAYER M4 ;
        RECT  86.208 38.352 86.4 38.376 ;
    END
  END di0[383]
  PIN di0[384]
    DIRECTION INPUT ;
    USE SIGNAL ;
    PORT
      LAYER M4 ;
        RECT  86.208 38.4 86.4 38.424 ;
    END
  END di0[384]
  PIN di0[385]
    DIRECTION INPUT ;
    USE SIGNAL ;
    PORT
      LAYER M4 ;
        RECT  86.208 38.448 86.4 38.472 ;
    END
  END di0[385]
  PIN di0[386]
    DIRECTION INPUT ;
    USE SIGNAL ;
    PORT
      LAYER M4 ;
        RECT  86.208 38.496 86.4 38.52 ;
    END
  END di0[386]
  PIN di0[387]
    DIRECTION INPUT ;
    USE SIGNAL ;
    PORT
      LAYER M4 ;
        RECT  86.208 38.544 86.4 38.568 ;
    END
  END di0[387]
  PIN di0[388]
    DIRECTION INPUT ;
    USE SIGNAL ;
    PORT
      LAYER M4 ;
        RECT  86.208 38.592 86.4 38.616 ;
    END
  END di0[388]
  PIN di0[389]
    DIRECTION INPUT ;
    USE SIGNAL ;
    PORT
      LAYER M4 ;
        RECT  86.208 38.64 86.4 38.664 ;
    END
  END di0[389]
  PIN di0[38]
    DIRECTION INPUT ;
    USE SIGNAL ;
    PORT
      LAYER M4 ;
        RECT  86.208 21.792 86.4 21.816 ;
    END
  END di0[38]
  PIN di0[390]
    DIRECTION INPUT ;
    USE SIGNAL ;
    PORT
      LAYER M4 ;
        RECT  86.208 38.688 86.4 38.712 ;
    END
  END di0[390]
  PIN di0[391]
    DIRECTION INPUT ;
    USE SIGNAL ;
    PORT
      LAYER M4 ;
        RECT  86.208 38.736 86.4 38.76 ;
    END
  END di0[391]
  PIN di0[392]
    DIRECTION INPUT ;
    USE SIGNAL ;
    PORT
      LAYER M4 ;
        RECT  86.208 38.784 86.4 38.808 ;
    END
  END di0[392]
  PIN di0[393]
    DIRECTION INPUT ;
    USE SIGNAL ;
    PORT
      LAYER M4 ;
        RECT  86.208 38.832 86.4 38.856 ;
    END
  END di0[393]
  PIN di0[394]
    DIRECTION INPUT ;
    USE SIGNAL ;
    PORT
      LAYER M4 ;
        RECT  86.208 38.88 86.4 38.904 ;
    END
  END di0[394]
  PIN di0[395]
    DIRECTION INPUT ;
    USE SIGNAL ;
    PORT
      LAYER M4 ;
        RECT  86.208 38.928 86.4 38.952 ;
    END
  END di0[395]
  PIN di0[396]
    DIRECTION INPUT ;
    USE SIGNAL ;
    PORT
      LAYER M4 ;
        RECT  86.208 38.976 86.4 39 ;
    END
  END di0[396]
  PIN di0[397]
    DIRECTION INPUT ;
    USE SIGNAL ;
    PORT
      LAYER M4 ;
        RECT  86.208 39.024 86.4 39.048 ;
    END
  END di0[397]
  PIN di0[398]
    DIRECTION INPUT ;
    USE SIGNAL ;
    PORT
      LAYER M4 ;
        RECT  86.208 39.072 86.4 39.096 ;
    END
  END di0[398]
  PIN di0[399]
    DIRECTION INPUT ;
    USE SIGNAL ;
    PORT
      LAYER M4 ;
        RECT  86.208 39.12 86.4 39.144 ;
    END
  END di0[399]
  PIN di0[39]
    DIRECTION INPUT ;
    USE SIGNAL ;
    PORT
      LAYER M4 ;
        RECT  86.208 21.84 86.4 21.864 ;
    END
  END di0[39]
  PIN di0[3]
    DIRECTION INPUT ;
    USE SIGNAL ;
    PORT
      LAYER M4 ;
        RECT  86.208 20.112 86.4 20.136 ;
    END
  END di0[3]
  PIN di0[400]
    DIRECTION INPUT ;
    USE SIGNAL ;
    PORT
      LAYER M4 ;
        RECT  86.208 39.168 86.4 39.192 ;
    END
  END di0[400]
  PIN di0[401]
    DIRECTION INPUT ;
    USE SIGNAL ;
    PORT
      LAYER M4 ;
        RECT  86.208 39.216 86.4 39.24 ;
    END
  END di0[401]
  PIN di0[402]
    DIRECTION INPUT ;
    USE SIGNAL ;
    PORT
      LAYER M4 ;
        RECT  86.208 39.264 86.4 39.288 ;
    END
  END di0[402]
  PIN di0[403]
    DIRECTION INPUT ;
    USE SIGNAL ;
    PORT
      LAYER M4 ;
        RECT  86.208 39.312 86.4 39.336 ;
    END
  END di0[403]
  PIN di0[404]
    DIRECTION INPUT ;
    USE SIGNAL ;
    PORT
      LAYER M4 ;
        RECT  86.208 39.36 86.4 39.384 ;
    END
  END di0[404]
  PIN di0[405]
    DIRECTION INPUT ;
    USE SIGNAL ;
    PORT
      LAYER M4 ;
        RECT  86.208 39.408 86.4 39.432 ;
    END
  END di0[405]
  PIN di0[406]
    DIRECTION INPUT ;
    USE SIGNAL ;
    PORT
      LAYER M4 ;
        RECT  86.208 39.456 86.4 39.48 ;
    END
  END di0[406]
  PIN di0[407]
    DIRECTION INPUT ;
    USE SIGNAL ;
    PORT
      LAYER M4 ;
        RECT  86.208 39.504 86.4 39.528 ;
    END
  END di0[407]
  PIN di0[408]
    DIRECTION INPUT ;
    USE SIGNAL ;
    PORT
      LAYER M4 ;
        RECT  86.208 39.552 86.4 39.576 ;
    END
  END di0[408]
  PIN di0[409]
    DIRECTION INPUT ;
    USE SIGNAL ;
    PORT
      LAYER M4 ;
        RECT  86.208 39.6 86.4 39.624 ;
    END
  END di0[409]
  PIN di0[40]
    DIRECTION INPUT ;
    USE SIGNAL ;
    PORT
      LAYER M4 ;
        RECT  86.208 21.888 86.4 21.912 ;
    END
  END di0[40]
  PIN di0[410]
    DIRECTION INPUT ;
    USE SIGNAL ;
    PORT
      LAYER M4 ;
        RECT  86.208 39.648 86.4 39.672 ;
    END
  END di0[410]
  PIN di0[411]
    DIRECTION INPUT ;
    USE SIGNAL ;
    PORT
      LAYER M4 ;
        RECT  86.208 39.696 86.4 39.72 ;
    END
  END di0[411]
  PIN di0[412]
    DIRECTION INPUT ;
    USE SIGNAL ;
    PORT
      LAYER M4 ;
        RECT  86.208 39.744 86.4 39.768 ;
    END
  END di0[412]
  PIN di0[413]
    DIRECTION INPUT ;
    USE SIGNAL ;
    PORT
      LAYER M4 ;
        RECT  86.208 39.792 86.4 39.816 ;
    END
  END di0[413]
  PIN di0[414]
    DIRECTION INPUT ;
    USE SIGNAL ;
    PORT
      LAYER M4 ;
        RECT  86.208 39.84 86.4 39.864 ;
    END
  END di0[414]
  PIN di0[415]
    DIRECTION INPUT ;
    USE SIGNAL ;
    PORT
      LAYER M4 ;
        RECT  86.208 39.888 86.4 39.912 ;
    END
  END di0[415]
  PIN di0[416]
    DIRECTION INPUT ;
    USE SIGNAL ;
    PORT
      LAYER M4 ;
        RECT  86.208 39.936 86.4 39.96 ;
    END
  END di0[416]
  PIN di0[417]
    DIRECTION INPUT ;
    USE SIGNAL ;
    PORT
      LAYER M4 ;
        RECT  86.208 39.984 86.4 40.008 ;
    END
  END di0[417]
  PIN di0[418]
    DIRECTION INPUT ;
    USE SIGNAL ;
    PORT
      LAYER M4 ;
        RECT  86.208 40.032 86.4 40.056 ;
    END
  END di0[418]
  PIN di0[419]
    DIRECTION INPUT ;
    USE SIGNAL ;
    PORT
      LAYER M4 ;
        RECT  86.208 40.08 86.4 40.104 ;
    END
  END di0[419]
  PIN di0[41]
    DIRECTION INPUT ;
    USE SIGNAL ;
    PORT
      LAYER M4 ;
        RECT  86.208 21.936 86.4 21.96 ;
    END
  END di0[41]
  PIN di0[420]
    DIRECTION INPUT ;
    USE SIGNAL ;
    PORT
      LAYER M4 ;
        RECT  86.208 40.128 86.4 40.152 ;
    END
  END di0[420]
  PIN di0[421]
    DIRECTION INPUT ;
    USE SIGNAL ;
    PORT
      LAYER M4 ;
        RECT  86.208 40.176 86.4 40.2 ;
    END
  END di0[421]
  PIN di0[422]
    DIRECTION INPUT ;
    USE SIGNAL ;
    PORT
      LAYER M4 ;
        RECT  86.208 40.224 86.4 40.248 ;
    END
  END di0[422]
  PIN di0[423]
    DIRECTION INPUT ;
    USE SIGNAL ;
    PORT
      LAYER M4 ;
        RECT  86.208 40.272 86.4 40.296 ;
    END
  END di0[423]
  PIN di0[424]
    DIRECTION INPUT ;
    USE SIGNAL ;
    PORT
      LAYER M4 ;
        RECT  86.208 40.32 86.4 40.344 ;
    END
  END di0[424]
  PIN di0[425]
    DIRECTION INPUT ;
    USE SIGNAL ;
    PORT
      LAYER M4 ;
        RECT  86.208 40.368 86.4 40.392 ;
    END
  END di0[425]
  PIN di0[426]
    DIRECTION INPUT ;
    USE SIGNAL ;
    PORT
      LAYER M4 ;
        RECT  86.208 40.416 86.4 40.44 ;
    END
  END di0[426]
  PIN di0[427]
    DIRECTION INPUT ;
    USE SIGNAL ;
    PORT
      LAYER M4 ;
        RECT  86.208 40.464 86.4 40.488 ;
    END
  END di0[427]
  PIN di0[428]
    DIRECTION INPUT ;
    USE SIGNAL ;
    PORT
      LAYER M4 ;
        RECT  86.208 40.512 86.4 40.536 ;
    END
  END di0[428]
  PIN di0[429]
    DIRECTION INPUT ;
    USE SIGNAL ;
    PORT
      LAYER M4 ;
        RECT  86.208 40.56 86.4 40.584 ;
    END
  END di0[429]
  PIN di0[42]
    DIRECTION INPUT ;
    USE SIGNAL ;
    PORT
      LAYER M4 ;
        RECT  86.208 21.984 86.4 22.008 ;
    END
  END di0[42]
  PIN di0[430]
    DIRECTION INPUT ;
    USE SIGNAL ;
    PORT
      LAYER M4 ;
        RECT  86.208 40.608 86.4 40.632 ;
    END
  END di0[430]
  PIN di0[431]
    DIRECTION INPUT ;
    USE SIGNAL ;
    PORT
      LAYER M4 ;
        RECT  86.208 40.656 86.4 40.68 ;
    END
  END di0[431]
  PIN di0[432]
    DIRECTION INPUT ;
    USE SIGNAL ;
    PORT
      LAYER M4 ;
        RECT  86.208 40.704 86.4 40.728 ;
    END
  END di0[432]
  PIN di0[433]
    DIRECTION INPUT ;
    USE SIGNAL ;
    PORT
      LAYER M4 ;
        RECT  86.208 40.752 86.4 40.776 ;
    END
  END di0[433]
  PIN di0[434]
    DIRECTION INPUT ;
    USE SIGNAL ;
    PORT
      LAYER M4 ;
        RECT  86.208 40.8 86.4 40.824 ;
    END
  END di0[434]
  PIN di0[435]
    DIRECTION INPUT ;
    USE SIGNAL ;
    PORT
      LAYER M4 ;
        RECT  86.208 40.848 86.4 40.872 ;
    END
  END di0[435]
  PIN di0[436]
    DIRECTION INPUT ;
    USE SIGNAL ;
    PORT
      LAYER M4 ;
        RECT  86.208 40.896 86.4 40.92 ;
    END
  END di0[436]
  PIN di0[437]
    DIRECTION INPUT ;
    USE SIGNAL ;
    PORT
      LAYER M4 ;
        RECT  86.208 40.944 86.4 40.968 ;
    END
  END di0[437]
  PIN di0[438]
    DIRECTION INPUT ;
    USE SIGNAL ;
    PORT
      LAYER M4 ;
        RECT  86.208 40.992 86.4 41.016 ;
    END
  END di0[438]
  PIN di0[439]
    DIRECTION INPUT ;
    USE SIGNAL ;
    PORT
      LAYER M4 ;
        RECT  86.208 41.04 86.4 41.064 ;
    END
  END di0[439]
  PIN di0[43]
    DIRECTION INPUT ;
    USE SIGNAL ;
    PORT
      LAYER M4 ;
        RECT  86.208 22.032 86.4 22.056 ;
    END
  END di0[43]
  PIN di0[440]
    DIRECTION INPUT ;
    USE SIGNAL ;
    PORT
      LAYER M4 ;
        RECT  86.208 41.088 86.4 41.112 ;
    END
  END di0[440]
  PIN di0[441]
    DIRECTION INPUT ;
    USE SIGNAL ;
    PORT
      LAYER M4 ;
        RECT  86.208 41.136 86.4 41.16 ;
    END
  END di0[441]
  PIN di0[442]
    DIRECTION INPUT ;
    USE SIGNAL ;
    PORT
      LAYER M4 ;
        RECT  86.208 41.184 86.4 41.208 ;
    END
  END di0[442]
  PIN di0[443]
    DIRECTION INPUT ;
    USE SIGNAL ;
    PORT
      LAYER M4 ;
        RECT  86.208 41.232 86.4 41.256 ;
    END
  END di0[443]
  PIN di0[444]
    DIRECTION INPUT ;
    USE SIGNAL ;
    PORT
      LAYER M4 ;
        RECT  86.208 41.28 86.4 41.304 ;
    END
  END di0[444]
  PIN di0[445]
    DIRECTION INPUT ;
    USE SIGNAL ;
    PORT
      LAYER M4 ;
        RECT  86.208 41.328 86.4 41.352 ;
    END
  END di0[445]
  PIN di0[446]
    DIRECTION INPUT ;
    USE SIGNAL ;
    PORT
      LAYER M4 ;
        RECT  86.208 41.376 86.4 41.4 ;
    END
  END di0[446]
  PIN di0[447]
    DIRECTION INPUT ;
    USE SIGNAL ;
    PORT
      LAYER M4 ;
        RECT  86.208 41.424 86.4 41.448 ;
    END
  END di0[447]
  PIN di0[448]
    DIRECTION INPUT ;
    USE SIGNAL ;
    PORT
      LAYER M4 ;
        RECT  86.208 41.472 86.4 41.496 ;
    END
  END di0[448]
  PIN di0[449]
    DIRECTION INPUT ;
    USE SIGNAL ;
    PORT
      LAYER M4 ;
        RECT  86.208 41.52 86.4 41.544 ;
    END
  END di0[449]
  PIN di0[44]
    DIRECTION INPUT ;
    USE SIGNAL ;
    PORT
      LAYER M4 ;
        RECT  86.208 22.08 86.4 22.104 ;
    END
  END di0[44]
  PIN di0[450]
    DIRECTION INPUT ;
    USE SIGNAL ;
    PORT
      LAYER M4 ;
        RECT  86.208 41.568 86.4 41.592 ;
    END
  END di0[450]
  PIN di0[451]
    DIRECTION INPUT ;
    USE SIGNAL ;
    PORT
      LAYER M4 ;
        RECT  86.208 41.616 86.4 41.64 ;
    END
  END di0[451]
  PIN di0[452]
    DIRECTION INPUT ;
    USE SIGNAL ;
    PORT
      LAYER M4 ;
        RECT  86.208 41.664 86.4 41.688 ;
    END
  END di0[452]
  PIN di0[453]
    DIRECTION INPUT ;
    USE SIGNAL ;
    PORT
      LAYER M4 ;
        RECT  86.208 41.712 86.4 41.736 ;
    END
  END di0[453]
  PIN di0[454]
    DIRECTION INPUT ;
    USE SIGNAL ;
    PORT
      LAYER M4 ;
        RECT  86.208 41.76 86.4 41.784 ;
    END
  END di0[454]
  PIN di0[455]
    DIRECTION INPUT ;
    USE SIGNAL ;
    PORT
      LAYER M4 ;
        RECT  86.208 41.808 86.4 41.832 ;
    END
  END di0[455]
  PIN di0[456]
    DIRECTION INPUT ;
    USE SIGNAL ;
    PORT
      LAYER M4 ;
        RECT  86.208 41.856 86.4 41.88 ;
    END
  END di0[456]
  PIN di0[457]
    DIRECTION INPUT ;
    USE SIGNAL ;
    PORT
      LAYER M4 ;
        RECT  86.208 41.904 86.4 41.928 ;
    END
  END di0[457]
  PIN di0[458]
    DIRECTION INPUT ;
    USE SIGNAL ;
    PORT
      LAYER M4 ;
        RECT  86.208 41.952 86.4 41.976 ;
    END
  END di0[458]
  PIN di0[459]
    DIRECTION INPUT ;
    USE SIGNAL ;
    PORT
      LAYER M4 ;
        RECT  86.208 42 86.4 42.024 ;
    END
  END di0[459]
  PIN di0[45]
    DIRECTION INPUT ;
    USE SIGNAL ;
    PORT
      LAYER M4 ;
        RECT  86.208 22.128 86.4 22.152 ;
    END
  END di0[45]
  PIN di0[460]
    DIRECTION INPUT ;
    USE SIGNAL ;
    PORT
      LAYER M4 ;
        RECT  86.208 42.048 86.4 42.072 ;
    END
  END di0[460]
  PIN di0[461]
    DIRECTION INPUT ;
    USE SIGNAL ;
    PORT
      LAYER M4 ;
        RECT  86.208 42.096 86.4 42.12 ;
    END
  END di0[461]
  PIN di0[462]
    DIRECTION INPUT ;
    USE SIGNAL ;
    PORT
      LAYER M4 ;
        RECT  86.208 42.144 86.4 42.168 ;
    END
  END di0[462]
  PIN di0[463]
    DIRECTION INPUT ;
    USE SIGNAL ;
    PORT
      LAYER M4 ;
        RECT  86.208 42.192 86.4 42.216 ;
    END
  END di0[463]
  PIN di0[464]
    DIRECTION INPUT ;
    USE SIGNAL ;
    PORT
      LAYER M4 ;
        RECT  86.208 42.24 86.4 42.264 ;
    END
  END di0[464]
  PIN di0[465]
    DIRECTION INPUT ;
    USE SIGNAL ;
    PORT
      LAYER M4 ;
        RECT  86.208 42.288 86.4 42.312 ;
    END
  END di0[465]
  PIN di0[466]
    DIRECTION INPUT ;
    USE SIGNAL ;
    PORT
      LAYER M4 ;
        RECT  86.208 42.336 86.4 42.36 ;
    END
  END di0[466]
  PIN di0[467]
    DIRECTION INPUT ;
    USE SIGNAL ;
    PORT
      LAYER M4 ;
        RECT  86.208 42.384 86.4 42.408 ;
    END
  END di0[467]
  PIN di0[468]
    DIRECTION INPUT ;
    USE SIGNAL ;
    PORT
      LAYER M4 ;
        RECT  86.208 42.432 86.4 42.456 ;
    END
  END di0[468]
  PIN di0[469]
    DIRECTION INPUT ;
    USE SIGNAL ;
    PORT
      LAYER M4 ;
        RECT  86.208 42.48 86.4 42.504 ;
    END
  END di0[469]
  PIN di0[46]
    DIRECTION INPUT ;
    USE SIGNAL ;
    PORT
      LAYER M4 ;
        RECT  86.208 22.176 86.4 22.2 ;
    END
  END di0[46]
  PIN di0[470]
    DIRECTION INPUT ;
    USE SIGNAL ;
    PORT
      LAYER M4 ;
        RECT  86.208 42.528 86.4 42.552 ;
    END
  END di0[470]
  PIN di0[471]
    DIRECTION INPUT ;
    USE SIGNAL ;
    PORT
      LAYER M4 ;
        RECT  86.208 42.576 86.4 42.6 ;
    END
  END di0[471]
  PIN di0[472]
    DIRECTION INPUT ;
    USE SIGNAL ;
    PORT
      LAYER M4 ;
        RECT  86.208 42.624 86.4 42.648 ;
    END
  END di0[472]
  PIN di0[473]
    DIRECTION INPUT ;
    USE SIGNAL ;
    PORT
      LAYER M4 ;
        RECT  86.208 42.672 86.4 42.696 ;
    END
  END di0[473]
  PIN di0[474]
    DIRECTION INPUT ;
    USE SIGNAL ;
    PORT
      LAYER M4 ;
        RECT  86.208 42.72 86.4 42.744 ;
    END
  END di0[474]
  PIN di0[475]
    DIRECTION INPUT ;
    USE SIGNAL ;
    PORT
      LAYER M4 ;
        RECT  86.208 42.768 86.4 42.792 ;
    END
  END di0[475]
  PIN di0[476]
    DIRECTION INPUT ;
    USE SIGNAL ;
    PORT
      LAYER M4 ;
        RECT  86.208 42.816 86.4 42.84 ;
    END
  END di0[476]
  PIN di0[477]
    DIRECTION INPUT ;
    USE SIGNAL ;
    PORT
      LAYER M4 ;
        RECT  86.208 42.864 86.4 42.888 ;
    END
  END di0[477]
  PIN di0[478]
    DIRECTION INPUT ;
    USE SIGNAL ;
    PORT
      LAYER M4 ;
        RECT  86.208 42.912 86.4 42.936 ;
    END
  END di0[478]
  PIN di0[479]
    DIRECTION INPUT ;
    USE SIGNAL ;
    PORT
      LAYER M4 ;
        RECT  86.208 42.96 86.4 42.984 ;
    END
  END di0[479]
  PIN di0[47]
    DIRECTION INPUT ;
    USE SIGNAL ;
    PORT
      LAYER M4 ;
        RECT  86.208 22.224 86.4 22.248 ;
    END
  END di0[47]
  PIN di0[480]
    DIRECTION INPUT ;
    USE SIGNAL ;
    PORT
      LAYER M4 ;
        RECT  86.208 43.008 86.4 43.032 ;
    END
  END di0[480]
  PIN di0[481]
    DIRECTION INPUT ;
    USE SIGNAL ;
    PORT
      LAYER M4 ;
        RECT  86.208 43.056 86.4 43.08 ;
    END
  END di0[481]
  PIN di0[482]
    DIRECTION INPUT ;
    USE SIGNAL ;
    PORT
      LAYER M4 ;
        RECT  86.208 43.104 86.4 43.128 ;
    END
  END di0[482]
  PIN di0[483]
    DIRECTION INPUT ;
    USE SIGNAL ;
    PORT
      LAYER M4 ;
        RECT  86.208 43.152 86.4 43.176 ;
    END
  END di0[483]
  PIN di0[484]
    DIRECTION INPUT ;
    USE SIGNAL ;
    PORT
      LAYER M4 ;
        RECT  86.208 43.2 86.4 43.224 ;
    END
  END di0[484]
  PIN di0[485]
    DIRECTION INPUT ;
    USE SIGNAL ;
    PORT
      LAYER M4 ;
        RECT  86.208 43.248 86.4 43.272 ;
    END
  END di0[485]
  PIN di0[486]
    DIRECTION INPUT ;
    USE SIGNAL ;
    PORT
      LAYER M4 ;
        RECT  86.208 43.296 86.4 43.32 ;
    END
  END di0[486]
  PIN di0[487]
    DIRECTION INPUT ;
    USE SIGNAL ;
    PORT
      LAYER M4 ;
        RECT  86.208 43.344 86.4 43.368 ;
    END
  END di0[487]
  PIN di0[488]
    DIRECTION INPUT ;
    USE SIGNAL ;
    PORT
      LAYER M4 ;
        RECT  86.208 43.392 86.4 43.416 ;
    END
  END di0[488]
  PIN di0[489]
    DIRECTION INPUT ;
    USE SIGNAL ;
    PORT
      LAYER M4 ;
        RECT  86.208 43.44 86.4 43.464 ;
    END
  END di0[489]
  PIN di0[48]
    DIRECTION INPUT ;
    USE SIGNAL ;
    PORT
      LAYER M4 ;
        RECT  86.208 22.272 86.4 22.296 ;
    END
  END di0[48]
  PIN di0[490]
    DIRECTION INPUT ;
    USE SIGNAL ;
    PORT
      LAYER M4 ;
        RECT  86.208 43.488 86.4 43.512 ;
    END
  END di0[490]
  PIN di0[491]
    DIRECTION INPUT ;
    USE SIGNAL ;
    PORT
      LAYER M4 ;
        RECT  86.208 43.536 86.4 43.56 ;
    END
  END di0[491]
  PIN di0[492]
    DIRECTION INPUT ;
    USE SIGNAL ;
    PORT
      LAYER M4 ;
        RECT  86.208 43.584 86.4 43.608 ;
    END
  END di0[492]
  PIN di0[493]
    DIRECTION INPUT ;
    USE SIGNAL ;
    PORT
      LAYER M4 ;
        RECT  86.208 43.632 86.4 43.656 ;
    END
  END di0[493]
  PIN di0[494]
    DIRECTION INPUT ;
    USE SIGNAL ;
    PORT
      LAYER M4 ;
        RECT  86.208 43.68 86.4 43.704 ;
    END
  END di0[494]
  PIN di0[495]
    DIRECTION INPUT ;
    USE SIGNAL ;
    PORT
      LAYER M4 ;
        RECT  86.208 43.728 86.4 43.752 ;
    END
  END di0[495]
  PIN di0[496]
    DIRECTION INPUT ;
    USE SIGNAL ;
    PORT
      LAYER M4 ;
        RECT  86.208 43.776 86.4 43.8 ;
    END
  END di0[496]
  PIN di0[497]
    DIRECTION INPUT ;
    USE SIGNAL ;
    PORT
      LAYER M4 ;
        RECT  86.208 43.824 86.4 43.848 ;
    END
  END di0[497]
  PIN di0[498]
    DIRECTION INPUT ;
    USE SIGNAL ;
    PORT
      LAYER M4 ;
        RECT  86.208 43.872 86.4 43.896 ;
    END
  END di0[498]
  PIN di0[499]
    DIRECTION INPUT ;
    USE SIGNAL ;
    PORT
      LAYER M4 ;
        RECT  86.208 43.92 86.4 43.944 ;
    END
  END di0[499]
  PIN di0[49]
    DIRECTION INPUT ;
    USE SIGNAL ;
    PORT
      LAYER M4 ;
        RECT  86.208 22.32 86.4 22.344 ;
    END
  END di0[49]
  PIN di0[4]
    DIRECTION INPUT ;
    USE SIGNAL ;
    PORT
      LAYER M4 ;
        RECT  86.208 20.16 86.4 20.184 ;
    END
  END di0[4]
  PIN di0[500]
    DIRECTION INPUT ;
    USE SIGNAL ;
    PORT
      LAYER M4 ;
        RECT  86.208 43.968 86.4 43.992 ;
    END
  END di0[500]
  PIN di0[501]
    DIRECTION INPUT ;
    USE SIGNAL ;
    PORT
      LAYER M4 ;
        RECT  86.208 44.016 86.4 44.04 ;
    END
  END di0[501]
  PIN di0[502]
    DIRECTION INPUT ;
    USE SIGNAL ;
    PORT
      LAYER M4 ;
        RECT  86.208 44.064 86.4 44.088 ;
    END
  END di0[502]
  PIN di0[503]
    DIRECTION INPUT ;
    USE SIGNAL ;
    PORT
      LAYER M4 ;
        RECT  86.208 44.112 86.4 44.136 ;
    END
  END di0[503]
  PIN di0[504]
    DIRECTION INPUT ;
    USE SIGNAL ;
    PORT
      LAYER M4 ;
        RECT  86.208 44.16 86.4 44.184 ;
    END
  END di0[504]
  PIN di0[505]
    DIRECTION INPUT ;
    USE SIGNAL ;
    PORT
      LAYER M4 ;
        RECT  86.208 44.208 86.4 44.232 ;
    END
  END di0[505]
  PIN di0[506]
    DIRECTION INPUT ;
    USE SIGNAL ;
    PORT
      LAYER M4 ;
        RECT  86.208 44.256 86.4 44.28 ;
    END
  END di0[506]
  PIN di0[507]
    DIRECTION INPUT ;
    USE SIGNAL ;
    PORT
      LAYER M4 ;
        RECT  86.208 44.304 86.4 44.328 ;
    END
  END di0[507]
  PIN di0[508]
    DIRECTION INPUT ;
    USE SIGNAL ;
    PORT
      LAYER M4 ;
        RECT  86.208 44.352 86.4 44.376 ;
    END
  END di0[508]
  PIN di0[509]
    DIRECTION INPUT ;
    USE SIGNAL ;
    PORT
      LAYER M4 ;
        RECT  86.208 44.4 86.4 44.424 ;
    END
  END di0[509]
  PIN di0[50]
    DIRECTION INPUT ;
    USE SIGNAL ;
    PORT
      LAYER M4 ;
        RECT  86.208 22.368 86.4 22.392 ;
    END
  END di0[50]
  PIN di0[510]
    DIRECTION INPUT ;
    USE SIGNAL ;
    PORT
      LAYER M4 ;
        RECT  86.208 44.448 86.4 44.472 ;
    END
  END di0[510]
  PIN di0[511]
    DIRECTION INPUT ;
    USE SIGNAL ;
    PORT
      LAYER M4 ;
        RECT  86.208 44.496 86.4 44.52 ;
    END
  END di0[511]
  PIN di0[512]
    DIRECTION INPUT ;
    USE SIGNAL ;
    PORT
      LAYER M4 ;
        RECT  86.208 44.544 86.4 44.568 ;
    END
  END di0[512]
  PIN di0[513]
    DIRECTION INPUT ;
    USE SIGNAL ;
    PORT
      LAYER M4 ;
        RECT  86.208 44.592 86.4 44.616 ;
    END
  END di0[513]
  PIN di0[51]
    DIRECTION INPUT ;
    USE SIGNAL ;
    PORT
      LAYER M4 ;
        RECT  86.208 22.416 86.4 22.44 ;
    END
  END di0[51]
  PIN di0[52]
    DIRECTION INPUT ;
    USE SIGNAL ;
    PORT
      LAYER M4 ;
        RECT  86.208 22.464 86.4 22.488 ;
    END
  END di0[52]
  PIN di0[53]
    DIRECTION INPUT ;
    USE SIGNAL ;
    PORT
      LAYER M4 ;
        RECT  86.208 22.512 86.4 22.536 ;
    END
  END di0[53]
  PIN di0[54]
    DIRECTION INPUT ;
    USE SIGNAL ;
    PORT
      LAYER M4 ;
        RECT  86.208 22.56 86.4 22.584 ;
    END
  END di0[54]
  PIN di0[55]
    DIRECTION INPUT ;
    USE SIGNAL ;
    PORT
      LAYER M4 ;
        RECT  86.208 22.608 86.4 22.632 ;
    END
  END di0[55]
  PIN di0[56]
    DIRECTION INPUT ;
    USE SIGNAL ;
    PORT
      LAYER M4 ;
        RECT  86.208 22.656 86.4 22.68 ;
    END
  END di0[56]
  PIN di0[57]
    DIRECTION INPUT ;
    USE SIGNAL ;
    PORT
      LAYER M4 ;
        RECT  86.208 22.704 86.4 22.728 ;
    END
  END di0[57]
  PIN di0[58]
    DIRECTION INPUT ;
    USE SIGNAL ;
    PORT
      LAYER M4 ;
        RECT  86.208 22.752 86.4 22.776 ;
    END
  END di0[58]
  PIN di0[59]
    DIRECTION INPUT ;
    USE SIGNAL ;
    PORT
      LAYER M4 ;
        RECT  86.208 22.8 86.4 22.824 ;
    END
  END di0[59]
  PIN di0[5]
    DIRECTION INPUT ;
    USE SIGNAL ;
    PORT
      LAYER M4 ;
        RECT  86.208 20.208 86.4 20.232 ;
    END
  END di0[5]
  PIN di0[60]
    DIRECTION INPUT ;
    USE SIGNAL ;
    PORT
      LAYER M4 ;
        RECT  86.208 22.848 86.4 22.872 ;
    END
  END di0[60]
  PIN di0[61]
    DIRECTION INPUT ;
    USE SIGNAL ;
    PORT
      LAYER M4 ;
        RECT  86.208 22.896 86.4 22.92 ;
    END
  END di0[61]
  PIN di0[62]
    DIRECTION INPUT ;
    USE SIGNAL ;
    PORT
      LAYER M4 ;
        RECT  86.208 22.944 86.4 22.968 ;
    END
  END di0[62]
  PIN di0[63]
    DIRECTION INPUT ;
    USE SIGNAL ;
    PORT
      LAYER M4 ;
        RECT  86.208 22.992 86.4 23.016 ;
    END
  END di0[63]
  PIN di0[64]
    DIRECTION INPUT ;
    USE SIGNAL ;
    PORT
      LAYER M4 ;
        RECT  86.208 23.04 86.4 23.064 ;
    END
  END di0[64]
  PIN di0[65]
    DIRECTION INPUT ;
    USE SIGNAL ;
    PORT
      LAYER M4 ;
        RECT  86.208 23.088 86.4 23.112 ;
    END
  END di0[65]
  PIN di0[66]
    DIRECTION INPUT ;
    USE SIGNAL ;
    PORT
      LAYER M4 ;
        RECT  86.208 23.136 86.4 23.16 ;
    END
  END di0[66]
  PIN di0[67]
    DIRECTION INPUT ;
    USE SIGNAL ;
    PORT
      LAYER M4 ;
        RECT  86.208 23.184 86.4 23.208 ;
    END
  END di0[67]
  PIN di0[68]
    DIRECTION INPUT ;
    USE SIGNAL ;
    PORT
      LAYER M4 ;
        RECT  86.208 23.232 86.4 23.256 ;
    END
  END di0[68]
  PIN di0[69]
    DIRECTION INPUT ;
    USE SIGNAL ;
    PORT
      LAYER M4 ;
        RECT  86.208 23.28 86.4 23.304 ;
    END
  END di0[69]
  PIN di0[6]
    DIRECTION INPUT ;
    USE SIGNAL ;
    PORT
      LAYER M4 ;
        RECT  86.208 20.256 86.4 20.28 ;
    END
  END di0[6]
  PIN di0[70]
    DIRECTION INPUT ;
    USE SIGNAL ;
    PORT
      LAYER M4 ;
        RECT  86.208 23.328 86.4 23.352 ;
    END
  END di0[70]
  PIN di0[71]
    DIRECTION INPUT ;
    USE SIGNAL ;
    PORT
      LAYER M4 ;
        RECT  86.208 23.376 86.4 23.4 ;
    END
  END di0[71]
  PIN di0[72]
    DIRECTION INPUT ;
    USE SIGNAL ;
    PORT
      LAYER M4 ;
        RECT  86.208 23.424 86.4 23.448 ;
    END
  END di0[72]
  PIN di0[73]
    DIRECTION INPUT ;
    USE SIGNAL ;
    PORT
      LAYER M4 ;
        RECT  86.208 23.472 86.4 23.496 ;
    END
  END di0[73]
  PIN di0[74]
    DIRECTION INPUT ;
    USE SIGNAL ;
    PORT
      LAYER M4 ;
        RECT  86.208 23.52 86.4 23.544 ;
    END
  END di0[74]
  PIN di0[75]
    DIRECTION INPUT ;
    USE SIGNAL ;
    PORT
      LAYER M4 ;
        RECT  86.208 23.568 86.4 23.592 ;
    END
  END di0[75]
  PIN di0[76]
    DIRECTION INPUT ;
    USE SIGNAL ;
    PORT
      LAYER M4 ;
        RECT  86.208 23.616 86.4 23.64 ;
    END
  END di0[76]
  PIN di0[77]
    DIRECTION INPUT ;
    USE SIGNAL ;
    PORT
      LAYER M4 ;
        RECT  86.208 23.664 86.4 23.688 ;
    END
  END di0[77]
  PIN di0[78]
    DIRECTION INPUT ;
    USE SIGNAL ;
    PORT
      LAYER M4 ;
        RECT  86.208 23.712 86.4 23.736 ;
    END
  END di0[78]
  PIN di0[79]
    DIRECTION INPUT ;
    USE SIGNAL ;
    PORT
      LAYER M4 ;
        RECT  86.208 23.76 86.4 23.784 ;
    END
  END di0[79]
  PIN di0[7]
    DIRECTION INPUT ;
    USE SIGNAL ;
    PORT
      LAYER M4 ;
        RECT  86.208 20.304 86.4 20.328 ;
    END
  END di0[7]
  PIN di0[80]
    DIRECTION INPUT ;
    USE SIGNAL ;
    PORT
      LAYER M4 ;
        RECT  86.208 23.808 86.4 23.832 ;
    END
  END di0[80]
  PIN di0[81]
    DIRECTION INPUT ;
    USE SIGNAL ;
    PORT
      LAYER M4 ;
        RECT  86.208 23.856 86.4 23.88 ;
    END
  END di0[81]
  PIN di0[82]
    DIRECTION INPUT ;
    USE SIGNAL ;
    PORT
      LAYER M4 ;
        RECT  86.208 23.904 86.4 23.928 ;
    END
  END di0[82]
  PIN di0[83]
    DIRECTION INPUT ;
    USE SIGNAL ;
    PORT
      LAYER M4 ;
        RECT  86.208 23.952 86.4 23.976 ;
    END
  END di0[83]
  PIN di0[84]
    DIRECTION INPUT ;
    USE SIGNAL ;
    PORT
      LAYER M4 ;
        RECT  86.208 24 86.4 24.024 ;
    END
  END di0[84]
  PIN di0[85]
    DIRECTION INPUT ;
    USE SIGNAL ;
    PORT
      LAYER M4 ;
        RECT  86.208 24.048 86.4 24.072 ;
    END
  END di0[85]
  PIN di0[86]
    DIRECTION INPUT ;
    USE SIGNAL ;
    PORT
      LAYER M4 ;
        RECT  86.208 24.096 86.4 24.12 ;
    END
  END di0[86]
  PIN di0[87]
    DIRECTION INPUT ;
    USE SIGNAL ;
    PORT
      LAYER M4 ;
        RECT  86.208 24.144 86.4 24.168 ;
    END
  END di0[87]
  PIN di0[88]
    DIRECTION INPUT ;
    USE SIGNAL ;
    PORT
      LAYER M4 ;
        RECT  86.208 24.192 86.4 24.216 ;
    END
  END di0[88]
  PIN di0[89]
    DIRECTION INPUT ;
    USE SIGNAL ;
    PORT
      LAYER M4 ;
        RECT  86.208 24.24 86.4 24.264 ;
    END
  END di0[89]
  PIN di0[8]
    DIRECTION INPUT ;
    USE SIGNAL ;
    PORT
      LAYER M4 ;
        RECT  86.208 20.352 86.4 20.376 ;
    END
  END di0[8]
  PIN di0[90]
    DIRECTION INPUT ;
    USE SIGNAL ;
    PORT
      LAYER M4 ;
        RECT  86.208 24.288 86.4 24.312 ;
    END
  END di0[90]
  PIN di0[91]
    DIRECTION INPUT ;
    USE SIGNAL ;
    PORT
      LAYER M4 ;
        RECT  86.208 24.336 86.4 24.36 ;
    END
  END di0[91]
  PIN di0[92]
    DIRECTION INPUT ;
    USE SIGNAL ;
    PORT
      LAYER M4 ;
        RECT  86.208 24.384 86.4 24.408 ;
    END
  END di0[92]
  PIN di0[93]
    DIRECTION INPUT ;
    USE SIGNAL ;
    PORT
      LAYER M4 ;
        RECT  86.208 24.432 86.4 24.456 ;
    END
  END di0[93]
  PIN di0[94]
    DIRECTION INPUT ;
    USE SIGNAL ;
    PORT
      LAYER M4 ;
        RECT  86.208 24.48 86.4 24.504 ;
    END
  END di0[94]
  PIN di0[95]
    DIRECTION INPUT ;
    USE SIGNAL ;
    PORT
      LAYER M4 ;
        RECT  86.208 24.528 86.4 24.552 ;
    END
  END di0[95]
  PIN di0[96]
    DIRECTION INPUT ;
    USE SIGNAL ;
    PORT
      LAYER M4 ;
        RECT  86.208 24.576 86.4 24.6 ;
    END
  END di0[96]
  PIN di0[97]
    DIRECTION INPUT ;
    USE SIGNAL ;
    PORT
      LAYER M4 ;
        RECT  86.208 24.624 86.4 24.648 ;
    END
  END di0[97]
  PIN di0[98]
    DIRECTION INPUT ;
    USE SIGNAL ;
    PORT
      LAYER M4 ;
        RECT  86.208 24.672 86.4 24.696 ;
    END
  END di0[98]
  PIN di0[99]
    DIRECTION INPUT ;
    USE SIGNAL ;
    PORT
      LAYER M4 ;
        RECT  86.208 24.72 86.4 24.744 ;
    END
  END di0[99]
  PIN di0[9]
    DIRECTION INPUT ;
    USE SIGNAL ;
    PORT
      LAYER M4 ;
        RECT  86.208 20.4 86.4 20.424 ;
    END
  END di0[9]
  PIN fi0[0]
    DIRECTION INPUT ;
    USE SIGNAL ;
    PORT
      LAYER M4 ;
        RECT  86.208 44.784 86.4 44.808 ;
    END
  END fi0[0]
  PIN o[0]
    DIRECTION OUTPUT ;
    USE SIGNAL ;
    PORT
      LAYER M4 ;
        RECT  0 20.016 0.192 20.04 ;
    END
  END o[0]
  PIN o[100]
    DIRECTION OUTPUT ;
    USE SIGNAL ;
    PORT
      LAYER M4 ;
        RECT  0 24.816 0.192 24.84 ;
    END
  END o[100]
  PIN o[101]
    DIRECTION OUTPUT ;
    USE SIGNAL ;
    PORT
      LAYER M4 ;
        RECT  0 24.864 0.192 24.888 ;
    END
  END o[101]
  PIN o[102]
    DIRECTION OUTPUT ;
    USE SIGNAL ;
    PORT
      LAYER M4 ;
        RECT  0 24.912 0.192 24.936 ;
    END
  END o[102]
  PIN o[103]
    DIRECTION OUTPUT ;
    USE SIGNAL ;
    PORT
      LAYER M4 ;
        RECT  0 24.96 0.192 24.984 ;
    END
  END o[103]
  PIN o[104]
    DIRECTION OUTPUT ;
    USE SIGNAL ;
    PORT
      LAYER M4 ;
        RECT  0 25.008 0.192 25.032 ;
    END
  END o[104]
  PIN o[105]
    DIRECTION OUTPUT ;
    USE SIGNAL ;
    PORT
      LAYER M4 ;
        RECT  0 25.056 0.192 25.08 ;
    END
  END o[105]
  PIN o[106]
    DIRECTION OUTPUT ;
    USE SIGNAL ;
    PORT
      LAYER M4 ;
        RECT  0 25.104 0.192 25.128 ;
    END
  END o[106]
  PIN o[107]
    DIRECTION OUTPUT ;
    USE SIGNAL ;
    PORT
      LAYER M4 ;
        RECT  0 25.152 0.192 25.176 ;
    END
  END o[107]
  PIN o[108]
    DIRECTION OUTPUT ;
    USE SIGNAL ;
    PORT
      LAYER M4 ;
        RECT  0 25.2 0.192 25.224 ;
    END
  END o[108]
  PIN o[109]
    DIRECTION OUTPUT ;
    USE SIGNAL ;
    PORT
      LAYER M4 ;
        RECT  0 25.248 0.192 25.272 ;
    END
  END o[109]
  PIN o[10]
    DIRECTION OUTPUT ;
    USE SIGNAL ;
    PORT
      LAYER M4 ;
        RECT  0 20.496 0.192 20.52 ;
    END
  END o[10]
  PIN o[110]
    DIRECTION OUTPUT ;
    USE SIGNAL ;
    PORT
      LAYER M4 ;
        RECT  0 25.296 0.192 25.32 ;
    END
  END o[110]
  PIN o[111]
    DIRECTION OUTPUT ;
    USE SIGNAL ;
    PORT
      LAYER M4 ;
        RECT  0 25.344 0.192 25.368 ;
    END
  END o[111]
  PIN o[112]
    DIRECTION OUTPUT ;
    USE SIGNAL ;
    PORT
      LAYER M4 ;
        RECT  0 25.392 0.192 25.416 ;
    END
  END o[112]
  PIN o[113]
    DIRECTION OUTPUT ;
    USE SIGNAL ;
    PORT
      LAYER M4 ;
        RECT  0 25.44 0.192 25.464 ;
    END
  END o[113]
  PIN o[114]
    DIRECTION OUTPUT ;
    USE SIGNAL ;
    PORT
      LAYER M4 ;
        RECT  0 25.488 0.192 25.512 ;
    END
  END o[114]
  PIN o[115]
    DIRECTION OUTPUT ;
    USE SIGNAL ;
    PORT
      LAYER M4 ;
        RECT  0 25.536 0.192 25.56 ;
    END
  END o[115]
  PIN o[116]
    DIRECTION OUTPUT ;
    USE SIGNAL ;
    PORT
      LAYER M4 ;
        RECT  0 25.584 0.192 25.608 ;
    END
  END o[116]
  PIN o[117]
    DIRECTION OUTPUT ;
    USE SIGNAL ;
    PORT
      LAYER M4 ;
        RECT  0 25.632 0.192 25.656 ;
    END
  END o[117]
  PIN o[118]
    DIRECTION OUTPUT ;
    USE SIGNAL ;
    PORT
      LAYER M4 ;
        RECT  0 25.68 0.192 25.704 ;
    END
  END o[118]
  PIN o[119]
    DIRECTION OUTPUT ;
    USE SIGNAL ;
    PORT
      LAYER M4 ;
        RECT  0 25.728 0.192 25.752 ;
    END
  END o[119]
  PIN o[11]
    DIRECTION OUTPUT ;
    USE SIGNAL ;
    PORT
      LAYER M4 ;
        RECT  0 20.544 0.192 20.568 ;
    END
  END o[11]
  PIN o[120]
    DIRECTION OUTPUT ;
    USE SIGNAL ;
    PORT
      LAYER M4 ;
        RECT  0 25.776 0.192 25.8 ;
    END
  END o[120]
  PIN o[121]
    DIRECTION OUTPUT ;
    USE SIGNAL ;
    PORT
      LAYER M4 ;
        RECT  0 25.824 0.192 25.848 ;
    END
  END o[121]
  PIN o[122]
    DIRECTION OUTPUT ;
    USE SIGNAL ;
    PORT
      LAYER M4 ;
        RECT  0 25.872 0.192 25.896 ;
    END
  END o[122]
  PIN o[123]
    DIRECTION OUTPUT ;
    USE SIGNAL ;
    PORT
      LAYER M4 ;
        RECT  0 25.92 0.192 25.944 ;
    END
  END o[123]
  PIN o[124]
    DIRECTION OUTPUT ;
    USE SIGNAL ;
    PORT
      LAYER M4 ;
        RECT  0 25.968 0.192 25.992 ;
    END
  END o[124]
  PIN o[125]
    DIRECTION OUTPUT ;
    USE SIGNAL ;
    PORT
      LAYER M4 ;
        RECT  0 26.016 0.192 26.04 ;
    END
  END o[125]
  PIN o[126]
    DIRECTION OUTPUT ;
    USE SIGNAL ;
    PORT
      LAYER M4 ;
        RECT  0 26.064 0.192 26.088 ;
    END
  END o[126]
  PIN o[127]
    DIRECTION OUTPUT ;
    USE SIGNAL ;
    PORT
      LAYER M4 ;
        RECT  0 26.112 0.192 26.136 ;
    END
  END o[127]
  PIN o[128]
    DIRECTION OUTPUT ;
    USE SIGNAL ;
    PORT
      LAYER M4 ;
        RECT  0 26.16 0.192 26.184 ;
    END
  END o[128]
  PIN o[129]
    DIRECTION OUTPUT ;
    USE SIGNAL ;
    PORT
      LAYER M4 ;
        RECT  0 26.208 0.192 26.232 ;
    END
  END o[129]
  PIN o[12]
    DIRECTION OUTPUT ;
    USE SIGNAL ;
    PORT
      LAYER M4 ;
        RECT  0 20.592 0.192 20.616 ;
    END
  END o[12]
  PIN o[130]
    DIRECTION OUTPUT ;
    USE SIGNAL ;
    PORT
      LAYER M4 ;
        RECT  0 26.256 0.192 26.28 ;
    END
  END o[130]
  PIN o[131]
    DIRECTION OUTPUT ;
    USE SIGNAL ;
    PORT
      LAYER M4 ;
        RECT  0 26.304 0.192 26.328 ;
    END
  END o[131]
  PIN o[132]
    DIRECTION OUTPUT ;
    USE SIGNAL ;
    PORT
      LAYER M4 ;
        RECT  0 26.352 0.192 26.376 ;
    END
  END o[132]
  PIN o[133]
    DIRECTION OUTPUT ;
    USE SIGNAL ;
    PORT
      LAYER M4 ;
        RECT  0 26.4 0.192 26.424 ;
    END
  END o[133]
  PIN o[134]
    DIRECTION OUTPUT ;
    USE SIGNAL ;
    PORT
      LAYER M4 ;
        RECT  0 26.448 0.192 26.472 ;
    END
  END o[134]
  PIN o[135]
    DIRECTION OUTPUT ;
    USE SIGNAL ;
    PORT
      LAYER M4 ;
        RECT  0 26.496 0.192 26.52 ;
    END
  END o[135]
  PIN o[136]
    DIRECTION OUTPUT ;
    USE SIGNAL ;
    PORT
      LAYER M4 ;
        RECT  0 26.544 0.192 26.568 ;
    END
  END o[136]
  PIN o[137]
    DIRECTION OUTPUT ;
    USE SIGNAL ;
    PORT
      LAYER M4 ;
        RECT  0 26.592 0.192 26.616 ;
    END
  END o[137]
  PIN o[138]
    DIRECTION OUTPUT ;
    USE SIGNAL ;
    PORT
      LAYER M4 ;
        RECT  0 26.64 0.192 26.664 ;
    END
  END o[138]
  PIN o[139]
    DIRECTION OUTPUT ;
    USE SIGNAL ;
    PORT
      LAYER M4 ;
        RECT  0 26.688 0.192 26.712 ;
    END
  END o[139]
  PIN o[13]
    DIRECTION OUTPUT ;
    USE SIGNAL ;
    PORT
      LAYER M4 ;
        RECT  0 20.64 0.192 20.664 ;
    END
  END o[13]
  PIN o[140]
    DIRECTION OUTPUT ;
    USE SIGNAL ;
    PORT
      LAYER M4 ;
        RECT  0 26.736 0.192 26.76 ;
    END
  END o[140]
  PIN o[141]
    DIRECTION OUTPUT ;
    USE SIGNAL ;
    PORT
      LAYER M4 ;
        RECT  0 26.784 0.192 26.808 ;
    END
  END o[141]
  PIN o[142]
    DIRECTION OUTPUT ;
    USE SIGNAL ;
    PORT
      LAYER M4 ;
        RECT  0 26.832 0.192 26.856 ;
    END
  END o[142]
  PIN o[143]
    DIRECTION OUTPUT ;
    USE SIGNAL ;
    PORT
      LAYER M4 ;
        RECT  0 26.88 0.192 26.904 ;
    END
  END o[143]
  PIN o[144]
    DIRECTION OUTPUT ;
    USE SIGNAL ;
    PORT
      LAYER M4 ;
        RECT  0 26.928 0.192 26.952 ;
    END
  END o[144]
  PIN o[145]
    DIRECTION OUTPUT ;
    USE SIGNAL ;
    PORT
      LAYER M4 ;
        RECT  0 26.976 0.192 27 ;
    END
  END o[145]
  PIN o[146]
    DIRECTION OUTPUT ;
    USE SIGNAL ;
    PORT
      LAYER M4 ;
        RECT  0 27.024 0.192 27.048 ;
    END
  END o[146]
  PIN o[147]
    DIRECTION OUTPUT ;
    USE SIGNAL ;
    PORT
      LAYER M4 ;
        RECT  0 27.072 0.192 27.096 ;
    END
  END o[147]
  PIN o[148]
    DIRECTION OUTPUT ;
    USE SIGNAL ;
    PORT
      LAYER M4 ;
        RECT  0 27.12 0.192 27.144 ;
    END
  END o[148]
  PIN o[149]
    DIRECTION OUTPUT ;
    USE SIGNAL ;
    PORT
      LAYER M4 ;
        RECT  0 27.168 0.192 27.192 ;
    END
  END o[149]
  PIN o[14]
    DIRECTION OUTPUT ;
    USE SIGNAL ;
    PORT
      LAYER M4 ;
        RECT  0 20.688 0.192 20.712 ;
    END
  END o[14]
  PIN o[150]
    DIRECTION OUTPUT ;
    USE SIGNAL ;
    PORT
      LAYER M4 ;
        RECT  0 27.216 0.192 27.24 ;
    END
  END o[150]
  PIN o[151]
    DIRECTION OUTPUT ;
    USE SIGNAL ;
    PORT
      LAYER M4 ;
        RECT  0 27.264 0.192 27.288 ;
    END
  END o[151]
  PIN o[152]
    DIRECTION OUTPUT ;
    USE SIGNAL ;
    PORT
      LAYER M4 ;
        RECT  0 27.312 0.192 27.336 ;
    END
  END o[152]
  PIN o[153]
    DIRECTION OUTPUT ;
    USE SIGNAL ;
    PORT
      LAYER M4 ;
        RECT  0 27.36 0.192 27.384 ;
    END
  END o[153]
  PIN o[154]
    DIRECTION OUTPUT ;
    USE SIGNAL ;
    PORT
      LAYER M4 ;
        RECT  0 27.408 0.192 27.432 ;
    END
  END o[154]
  PIN o[155]
    DIRECTION OUTPUT ;
    USE SIGNAL ;
    PORT
      LAYER M4 ;
        RECT  0 27.456 0.192 27.48 ;
    END
  END o[155]
  PIN o[156]
    DIRECTION OUTPUT ;
    USE SIGNAL ;
    PORT
      LAYER M4 ;
        RECT  0 27.504 0.192 27.528 ;
    END
  END o[156]
  PIN o[157]
    DIRECTION OUTPUT ;
    USE SIGNAL ;
    PORT
      LAYER M4 ;
        RECT  0 27.552 0.192 27.576 ;
    END
  END o[157]
  PIN o[158]
    DIRECTION OUTPUT ;
    USE SIGNAL ;
    PORT
      LAYER M4 ;
        RECT  0 27.6 0.192 27.624 ;
    END
  END o[158]
  PIN o[159]
    DIRECTION OUTPUT ;
    USE SIGNAL ;
    PORT
      LAYER M4 ;
        RECT  0 27.648 0.192 27.672 ;
    END
  END o[159]
  PIN o[15]
    DIRECTION OUTPUT ;
    USE SIGNAL ;
    PORT
      LAYER M4 ;
        RECT  0 20.736 0.192 20.76 ;
    END
  END o[15]
  PIN o[160]
    DIRECTION OUTPUT ;
    USE SIGNAL ;
    PORT
      LAYER M4 ;
        RECT  0 27.696 0.192 27.72 ;
    END
  END o[160]
  PIN o[161]
    DIRECTION OUTPUT ;
    USE SIGNAL ;
    PORT
      LAYER M4 ;
        RECT  0 27.744 0.192 27.768 ;
    END
  END o[161]
  PIN o[162]
    DIRECTION OUTPUT ;
    USE SIGNAL ;
    PORT
      LAYER M4 ;
        RECT  0 27.792 0.192 27.816 ;
    END
  END o[162]
  PIN o[163]
    DIRECTION OUTPUT ;
    USE SIGNAL ;
    PORT
      LAYER M4 ;
        RECT  0 27.84 0.192 27.864 ;
    END
  END o[163]
  PIN o[164]
    DIRECTION OUTPUT ;
    USE SIGNAL ;
    PORT
      LAYER M4 ;
        RECT  0 27.888 0.192 27.912 ;
    END
  END o[164]
  PIN o[165]
    DIRECTION OUTPUT ;
    USE SIGNAL ;
    PORT
      LAYER M4 ;
        RECT  0 27.936 0.192 27.96 ;
    END
  END o[165]
  PIN o[166]
    DIRECTION OUTPUT ;
    USE SIGNAL ;
    PORT
      LAYER M4 ;
        RECT  0 27.984 0.192 28.008 ;
    END
  END o[166]
  PIN o[167]
    DIRECTION OUTPUT ;
    USE SIGNAL ;
    PORT
      LAYER M4 ;
        RECT  0 28.032 0.192 28.056 ;
    END
  END o[167]
  PIN o[168]
    DIRECTION OUTPUT ;
    USE SIGNAL ;
    PORT
      LAYER M4 ;
        RECT  0 28.08 0.192 28.104 ;
    END
  END o[168]
  PIN o[169]
    DIRECTION OUTPUT ;
    USE SIGNAL ;
    PORT
      LAYER M4 ;
        RECT  0 28.128 0.192 28.152 ;
    END
  END o[169]
  PIN o[16]
    DIRECTION OUTPUT ;
    USE SIGNAL ;
    PORT
      LAYER M4 ;
        RECT  0 20.784 0.192 20.808 ;
    END
  END o[16]
  PIN o[170]
    DIRECTION OUTPUT ;
    USE SIGNAL ;
    PORT
      LAYER M4 ;
        RECT  0 28.176 0.192 28.2 ;
    END
  END o[170]
  PIN o[171]
    DIRECTION OUTPUT ;
    USE SIGNAL ;
    PORT
      LAYER M4 ;
        RECT  0 28.224 0.192 28.248 ;
    END
  END o[171]
  PIN o[172]
    DIRECTION OUTPUT ;
    USE SIGNAL ;
    PORT
      LAYER M4 ;
        RECT  0 28.272 0.192 28.296 ;
    END
  END o[172]
  PIN o[173]
    DIRECTION OUTPUT ;
    USE SIGNAL ;
    PORT
      LAYER M4 ;
        RECT  0 28.32 0.192 28.344 ;
    END
  END o[173]
  PIN o[174]
    DIRECTION OUTPUT ;
    USE SIGNAL ;
    PORT
      LAYER M4 ;
        RECT  0 28.368 0.192 28.392 ;
    END
  END o[174]
  PIN o[175]
    DIRECTION OUTPUT ;
    USE SIGNAL ;
    PORT
      LAYER M4 ;
        RECT  0 28.416 0.192 28.44 ;
    END
  END o[175]
  PIN o[176]
    DIRECTION OUTPUT ;
    USE SIGNAL ;
    PORT
      LAYER M4 ;
        RECT  0 28.464 0.192 28.488 ;
    END
  END o[176]
  PIN o[177]
    DIRECTION OUTPUT ;
    USE SIGNAL ;
    PORT
      LAYER M4 ;
        RECT  0 28.512 0.192 28.536 ;
    END
  END o[177]
  PIN o[178]
    DIRECTION OUTPUT ;
    USE SIGNAL ;
    PORT
      LAYER M4 ;
        RECT  0 28.56 0.192 28.584 ;
    END
  END o[178]
  PIN o[179]
    DIRECTION OUTPUT ;
    USE SIGNAL ;
    PORT
      LAYER M4 ;
        RECT  0 28.608 0.192 28.632 ;
    END
  END o[179]
  PIN o[17]
    DIRECTION OUTPUT ;
    USE SIGNAL ;
    PORT
      LAYER M4 ;
        RECT  0 20.832 0.192 20.856 ;
    END
  END o[17]
  PIN o[180]
    DIRECTION OUTPUT ;
    USE SIGNAL ;
    PORT
      LAYER M4 ;
        RECT  0 28.656 0.192 28.68 ;
    END
  END o[180]
  PIN o[181]
    DIRECTION OUTPUT ;
    USE SIGNAL ;
    PORT
      LAYER M4 ;
        RECT  0 28.704 0.192 28.728 ;
    END
  END o[181]
  PIN o[182]
    DIRECTION OUTPUT ;
    USE SIGNAL ;
    PORT
      LAYER M4 ;
        RECT  0 28.752 0.192 28.776 ;
    END
  END o[182]
  PIN o[183]
    DIRECTION OUTPUT ;
    USE SIGNAL ;
    PORT
      LAYER M4 ;
        RECT  0 28.8 0.192 28.824 ;
    END
  END o[183]
  PIN o[184]
    DIRECTION OUTPUT ;
    USE SIGNAL ;
    PORT
      LAYER M4 ;
        RECT  0 28.848 0.192 28.872 ;
    END
  END o[184]
  PIN o[185]
    DIRECTION OUTPUT ;
    USE SIGNAL ;
    PORT
      LAYER M4 ;
        RECT  0 28.896 0.192 28.92 ;
    END
  END o[185]
  PIN o[186]
    DIRECTION OUTPUT ;
    USE SIGNAL ;
    PORT
      LAYER M4 ;
        RECT  0 28.944 0.192 28.968 ;
    END
  END o[186]
  PIN o[187]
    DIRECTION OUTPUT ;
    USE SIGNAL ;
    PORT
      LAYER M4 ;
        RECT  0 28.992 0.192 29.016 ;
    END
  END o[187]
  PIN o[188]
    DIRECTION OUTPUT ;
    USE SIGNAL ;
    PORT
      LAYER M4 ;
        RECT  0 29.04 0.192 29.064 ;
    END
  END o[188]
  PIN o[189]
    DIRECTION OUTPUT ;
    USE SIGNAL ;
    PORT
      LAYER M4 ;
        RECT  0 29.088 0.192 29.112 ;
    END
  END o[189]
  PIN o[18]
    DIRECTION OUTPUT ;
    USE SIGNAL ;
    PORT
      LAYER M4 ;
        RECT  0 20.88 0.192 20.904 ;
    END
  END o[18]
  PIN o[190]
    DIRECTION OUTPUT ;
    USE SIGNAL ;
    PORT
      LAYER M4 ;
        RECT  0 29.136 0.192 29.16 ;
    END
  END o[190]
  PIN o[191]
    DIRECTION OUTPUT ;
    USE SIGNAL ;
    PORT
      LAYER M4 ;
        RECT  0 29.184 0.192 29.208 ;
    END
  END o[191]
  PIN o[192]
    DIRECTION OUTPUT ;
    USE SIGNAL ;
    PORT
      LAYER M4 ;
        RECT  0 29.232 0.192 29.256 ;
    END
  END o[192]
  PIN o[193]
    DIRECTION OUTPUT ;
    USE SIGNAL ;
    PORT
      LAYER M4 ;
        RECT  0 29.28 0.192 29.304 ;
    END
  END o[193]
  PIN o[194]
    DIRECTION OUTPUT ;
    USE SIGNAL ;
    PORT
      LAYER M4 ;
        RECT  0 29.328 0.192 29.352 ;
    END
  END o[194]
  PIN o[195]
    DIRECTION OUTPUT ;
    USE SIGNAL ;
    PORT
      LAYER M4 ;
        RECT  0 29.376 0.192 29.4 ;
    END
  END o[195]
  PIN o[196]
    DIRECTION OUTPUT ;
    USE SIGNAL ;
    PORT
      LAYER M4 ;
        RECT  0 29.424 0.192 29.448 ;
    END
  END o[196]
  PIN o[197]
    DIRECTION OUTPUT ;
    USE SIGNAL ;
    PORT
      LAYER M4 ;
        RECT  0 29.472 0.192 29.496 ;
    END
  END o[197]
  PIN o[198]
    DIRECTION OUTPUT ;
    USE SIGNAL ;
    PORT
      LAYER M4 ;
        RECT  0 29.52 0.192 29.544 ;
    END
  END o[198]
  PIN o[199]
    DIRECTION OUTPUT ;
    USE SIGNAL ;
    PORT
      LAYER M4 ;
        RECT  0 29.568 0.192 29.592 ;
    END
  END o[199]
  PIN o[19]
    DIRECTION OUTPUT ;
    USE SIGNAL ;
    PORT
      LAYER M4 ;
        RECT  0 20.928 0.192 20.952 ;
    END
  END o[19]
  PIN o[1]
    DIRECTION OUTPUT ;
    USE SIGNAL ;
    PORT
      LAYER M4 ;
        RECT  0 20.064 0.192 20.088 ;
    END
  END o[1]
  PIN o[200]
    DIRECTION OUTPUT ;
    USE SIGNAL ;
    PORT
      LAYER M4 ;
        RECT  0 29.616 0.192 29.64 ;
    END
  END o[200]
  PIN o[201]
    DIRECTION OUTPUT ;
    USE SIGNAL ;
    PORT
      LAYER M4 ;
        RECT  0 29.664 0.192 29.688 ;
    END
  END o[201]
  PIN o[202]
    DIRECTION OUTPUT ;
    USE SIGNAL ;
    PORT
      LAYER M4 ;
        RECT  0 29.712 0.192 29.736 ;
    END
  END o[202]
  PIN o[203]
    DIRECTION OUTPUT ;
    USE SIGNAL ;
    PORT
      LAYER M4 ;
        RECT  0 29.76 0.192 29.784 ;
    END
  END o[203]
  PIN o[204]
    DIRECTION OUTPUT ;
    USE SIGNAL ;
    PORT
      LAYER M4 ;
        RECT  0 29.808 0.192 29.832 ;
    END
  END o[204]
  PIN o[205]
    DIRECTION OUTPUT ;
    USE SIGNAL ;
    PORT
      LAYER M4 ;
        RECT  0 29.856 0.192 29.88 ;
    END
  END o[205]
  PIN o[206]
    DIRECTION OUTPUT ;
    USE SIGNAL ;
    PORT
      LAYER M4 ;
        RECT  0 29.904 0.192 29.928 ;
    END
  END o[206]
  PIN o[207]
    DIRECTION OUTPUT ;
    USE SIGNAL ;
    PORT
      LAYER M4 ;
        RECT  0 29.952 0.192 29.976 ;
    END
  END o[207]
  PIN o[208]
    DIRECTION OUTPUT ;
    USE SIGNAL ;
    PORT
      LAYER M4 ;
        RECT  0 30 0.192 30.024 ;
    END
  END o[208]
  PIN o[209]
    DIRECTION OUTPUT ;
    USE SIGNAL ;
    PORT
      LAYER M4 ;
        RECT  0 30.048 0.192 30.072 ;
    END
  END o[209]
  PIN o[20]
    DIRECTION OUTPUT ;
    USE SIGNAL ;
    PORT
      LAYER M4 ;
        RECT  0 20.976 0.192 21 ;
    END
  END o[20]
  PIN o[210]
    DIRECTION OUTPUT ;
    USE SIGNAL ;
    PORT
      LAYER M4 ;
        RECT  0 30.096 0.192 30.12 ;
    END
  END o[210]
  PIN o[211]
    DIRECTION OUTPUT ;
    USE SIGNAL ;
    PORT
      LAYER M4 ;
        RECT  0 30.144 0.192 30.168 ;
    END
  END o[211]
  PIN o[212]
    DIRECTION OUTPUT ;
    USE SIGNAL ;
    PORT
      LAYER M4 ;
        RECT  0 30.192 0.192 30.216 ;
    END
  END o[212]
  PIN o[213]
    DIRECTION OUTPUT ;
    USE SIGNAL ;
    PORT
      LAYER M4 ;
        RECT  0 30.24 0.192 30.264 ;
    END
  END o[213]
  PIN o[214]
    DIRECTION OUTPUT ;
    USE SIGNAL ;
    PORT
      LAYER M4 ;
        RECT  0 30.288 0.192 30.312 ;
    END
  END o[214]
  PIN o[215]
    DIRECTION OUTPUT ;
    USE SIGNAL ;
    PORT
      LAYER M4 ;
        RECT  0 30.336 0.192 30.36 ;
    END
  END o[215]
  PIN o[216]
    DIRECTION OUTPUT ;
    USE SIGNAL ;
    PORT
      LAYER M4 ;
        RECT  0 30.384 0.192 30.408 ;
    END
  END o[216]
  PIN o[217]
    DIRECTION OUTPUT ;
    USE SIGNAL ;
    PORT
      LAYER M4 ;
        RECT  0 30.432 0.192 30.456 ;
    END
  END o[217]
  PIN o[218]
    DIRECTION OUTPUT ;
    USE SIGNAL ;
    PORT
      LAYER M4 ;
        RECT  0 30.48 0.192 30.504 ;
    END
  END o[218]
  PIN o[219]
    DIRECTION OUTPUT ;
    USE SIGNAL ;
    PORT
      LAYER M4 ;
        RECT  0 30.528 0.192 30.552 ;
    END
  END o[219]
  PIN o[21]
    DIRECTION OUTPUT ;
    USE SIGNAL ;
    PORT
      LAYER M4 ;
        RECT  0 21.024 0.192 21.048 ;
    END
  END o[21]
  PIN o[220]
    DIRECTION OUTPUT ;
    USE SIGNAL ;
    PORT
      LAYER M4 ;
        RECT  0 30.576 0.192 30.6 ;
    END
  END o[220]
  PIN o[221]
    DIRECTION OUTPUT ;
    USE SIGNAL ;
    PORT
      LAYER M4 ;
        RECT  0 30.624 0.192 30.648 ;
    END
  END o[221]
  PIN o[222]
    DIRECTION OUTPUT ;
    USE SIGNAL ;
    PORT
      LAYER M4 ;
        RECT  0 30.672 0.192 30.696 ;
    END
  END o[222]
  PIN o[223]
    DIRECTION OUTPUT ;
    USE SIGNAL ;
    PORT
      LAYER M4 ;
        RECT  0 30.72 0.192 30.744 ;
    END
  END o[223]
  PIN o[224]
    DIRECTION OUTPUT ;
    USE SIGNAL ;
    PORT
      LAYER M4 ;
        RECT  0 30.768 0.192 30.792 ;
    END
  END o[224]
  PIN o[225]
    DIRECTION OUTPUT ;
    USE SIGNAL ;
    PORT
      LAYER M4 ;
        RECT  0 30.816 0.192 30.84 ;
    END
  END o[225]
  PIN o[226]
    DIRECTION OUTPUT ;
    USE SIGNAL ;
    PORT
      LAYER M4 ;
        RECT  0 30.864 0.192 30.888 ;
    END
  END o[226]
  PIN o[227]
    DIRECTION OUTPUT ;
    USE SIGNAL ;
    PORT
      LAYER M4 ;
        RECT  0 30.912 0.192 30.936 ;
    END
  END o[227]
  PIN o[228]
    DIRECTION OUTPUT ;
    USE SIGNAL ;
    PORT
      LAYER M4 ;
        RECT  0 30.96 0.192 30.984 ;
    END
  END o[228]
  PIN o[229]
    DIRECTION OUTPUT ;
    USE SIGNAL ;
    PORT
      LAYER M4 ;
        RECT  0 31.008 0.192 31.032 ;
    END
  END o[229]
  PIN o[22]
    DIRECTION OUTPUT ;
    USE SIGNAL ;
    PORT
      LAYER M4 ;
        RECT  0 21.072 0.192 21.096 ;
    END
  END o[22]
  PIN o[230]
    DIRECTION OUTPUT ;
    USE SIGNAL ;
    PORT
      LAYER M4 ;
        RECT  0 31.056 0.192 31.08 ;
    END
  END o[230]
  PIN o[231]
    DIRECTION OUTPUT ;
    USE SIGNAL ;
    PORT
      LAYER M4 ;
        RECT  0 31.104 0.192 31.128 ;
    END
  END o[231]
  PIN o[232]
    DIRECTION OUTPUT ;
    USE SIGNAL ;
    PORT
      LAYER M4 ;
        RECT  0 31.152 0.192 31.176 ;
    END
  END o[232]
  PIN o[233]
    DIRECTION OUTPUT ;
    USE SIGNAL ;
    PORT
      LAYER M4 ;
        RECT  0 31.2 0.192 31.224 ;
    END
  END o[233]
  PIN o[234]
    DIRECTION OUTPUT ;
    USE SIGNAL ;
    PORT
      LAYER M4 ;
        RECT  0 31.248 0.192 31.272 ;
    END
  END o[234]
  PIN o[235]
    DIRECTION OUTPUT ;
    USE SIGNAL ;
    PORT
      LAYER M4 ;
        RECT  0 31.296 0.192 31.32 ;
    END
  END o[235]
  PIN o[236]
    DIRECTION OUTPUT ;
    USE SIGNAL ;
    PORT
      LAYER M4 ;
        RECT  0 31.344 0.192 31.368 ;
    END
  END o[236]
  PIN o[237]
    DIRECTION OUTPUT ;
    USE SIGNAL ;
    PORT
      LAYER M4 ;
        RECT  0 31.392 0.192 31.416 ;
    END
  END o[237]
  PIN o[238]
    DIRECTION OUTPUT ;
    USE SIGNAL ;
    PORT
      LAYER M4 ;
        RECT  0 31.44 0.192 31.464 ;
    END
  END o[238]
  PIN o[239]
    DIRECTION OUTPUT ;
    USE SIGNAL ;
    PORT
      LAYER M4 ;
        RECT  0 31.488 0.192 31.512 ;
    END
  END o[239]
  PIN o[23]
    DIRECTION OUTPUT ;
    USE SIGNAL ;
    PORT
      LAYER M4 ;
        RECT  0 21.12 0.192 21.144 ;
    END
  END o[23]
  PIN o[240]
    DIRECTION OUTPUT ;
    USE SIGNAL ;
    PORT
      LAYER M4 ;
        RECT  0 31.536 0.192 31.56 ;
    END
  END o[240]
  PIN o[241]
    DIRECTION OUTPUT ;
    USE SIGNAL ;
    PORT
      LAYER M4 ;
        RECT  0 31.584 0.192 31.608 ;
    END
  END o[241]
  PIN o[242]
    DIRECTION OUTPUT ;
    USE SIGNAL ;
    PORT
      LAYER M4 ;
        RECT  0 31.632 0.192 31.656 ;
    END
  END o[242]
  PIN o[243]
    DIRECTION OUTPUT ;
    USE SIGNAL ;
    PORT
      LAYER M4 ;
        RECT  0 31.68 0.192 31.704 ;
    END
  END o[243]
  PIN o[244]
    DIRECTION OUTPUT ;
    USE SIGNAL ;
    PORT
      LAYER M4 ;
        RECT  0 31.728 0.192 31.752 ;
    END
  END o[244]
  PIN o[245]
    DIRECTION OUTPUT ;
    USE SIGNAL ;
    PORT
      LAYER M4 ;
        RECT  0 31.776 0.192 31.8 ;
    END
  END o[245]
  PIN o[246]
    DIRECTION OUTPUT ;
    USE SIGNAL ;
    PORT
      LAYER M4 ;
        RECT  0 31.824 0.192 31.848 ;
    END
  END o[246]
  PIN o[247]
    DIRECTION OUTPUT ;
    USE SIGNAL ;
    PORT
      LAYER M4 ;
        RECT  0 31.872 0.192 31.896 ;
    END
  END o[247]
  PIN o[248]
    DIRECTION OUTPUT ;
    USE SIGNAL ;
    PORT
      LAYER M4 ;
        RECT  0 31.92 0.192 31.944 ;
    END
  END o[248]
  PIN o[249]
    DIRECTION OUTPUT ;
    USE SIGNAL ;
    PORT
      LAYER M4 ;
        RECT  0 31.968 0.192 31.992 ;
    END
  END o[249]
  PIN o[24]
    DIRECTION OUTPUT ;
    USE SIGNAL ;
    PORT
      LAYER M4 ;
        RECT  0 21.168 0.192 21.192 ;
    END
  END o[24]
  PIN o[250]
    DIRECTION OUTPUT ;
    USE SIGNAL ;
    PORT
      LAYER M4 ;
        RECT  0 32.016 0.192 32.04 ;
    END
  END o[250]
  PIN o[251]
    DIRECTION OUTPUT ;
    USE SIGNAL ;
    PORT
      LAYER M4 ;
        RECT  0 32.064 0.192 32.088 ;
    END
  END o[251]
  PIN o[252]
    DIRECTION OUTPUT ;
    USE SIGNAL ;
    PORT
      LAYER M4 ;
        RECT  0 32.112 0.192 32.136 ;
    END
  END o[252]
  PIN o[253]
    DIRECTION OUTPUT ;
    USE SIGNAL ;
    PORT
      LAYER M4 ;
        RECT  0 32.16 0.192 32.184 ;
    END
  END o[253]
  PIN o[254]
    DIRECTION OUTPUT ;
    USE SIGNAL ;
    PORT
      LAYER M4 ;
        RECT  0 32.208 0.192 32.232 ;
    END
  END o[254]
  PIN o[255]
    DIRECTION OUTPUT ;
    USE SIGNAL ;
    PORT
      LAYER M4 ;
        RECT  0 32.256 0.192 32.28 ;
    END
  END o[255]
  PIN o[256]
    DIRECTION OUTPUT ;
    USE SIGNAL ;
    PORT
      LAYER M4 ;
        RECT  0 32.304 0.192 32.328 ;
    END
  END o[256]
  PIN o[257]
    DIRECTION OUTPUT ;
    USE SIGNAL ;
    PORT
      LAYER M4 ;
        RECT  0 32.352 0.192 32.376 ;
    END
  END o[257]
  PIN o[258]
    DIRECTION OUTPUT ;
    USE SIGNAL ;
    PORT
      LAYER M4 ;
        RECT  0 32.4 0.192 32.424 ;
    END
  END o[258]
  PIN o[259]
    DIRECTION OUTPUT ;
    USE SIGNAL ;
    PORT
      LAYER M4 ;
        RECT  0 32.448 0.192 32.472 ;
    END
  END o[259]
  PIN o[25]
    DIRECTION OUTPUT ;
    USE SIGNAL ;
    PORT
      LAYER M4 ;
        RECT  0 21.216 0.192 21.24 ;
    END
  END o[25]
  PIN o[260]
    DIRECTION OUTPUT ;
    USE SIGNAL ;
    PORT
      LAYER M4 ;
        RECT  0 32.496 0.192 32.52 ;
    END
  END o[260]
  PIN o[261]
    DIRECTION OUTPUT ;
    USE SIGNAL ;
    PORT
      LAYER M4 ;
        RECT  0 32.544 0.192 32.568 ;
    END
  END o[261]
  PIN o[262]
    DIRECTION OUTPUT ;
    USE SIGNAL ;
    PORT
      LAYER M4 ;
        RECT  0 32.592 0.192 32.616 ;
    END
  END o[262]
  PIN o[263]
    DIRECTION OUTPUT ;
    USE SIGNAL ;
    PORT
      LAYER M4 ;
        RECT  0 32.64 0.192 32.664 ;
    END
  END o[263]
  PIN o[264]
    DIRECTION OUTPUT ;
    USE SIGNAL ;
    PORT
      LAYER M4 ;
        RECT  0 32.688 0.192 32.712 ;
    END
  END o[264]
  PIN o[265]
    DIRECTION OUTPUT ;
    USE SIGNAL ;
    PORT
      LAYER M4 ;
        RECT  0 32.736 0.192 32.76 ;
    END
  END o[265]
  PIN o[266]
    DIRECTION OUTPUT ;
    USE SIGNAL ;
    PORT
      LAYER M4 ;
        RECT  0 32.784 0.192 32.808 ;
    END
  END o[266]
  PIN o[267]
    DIRECTION OUTPUT ;
    USE SIGNAL ;
    PORT
      LAYER M4 ;
        RECT  0 32.832 0.192 32.856 ;
    END
  END o[267]
  PIN o[268]
    DIRECTION OUTPUT ;
    USE SIGNAL ;
    PORT
      LAYER M4 ;
        RECT  0 32.88 0.192 32.904 ;
    END
  END o[268]
  PIN o[269]
    DIRECTION OUTPUT ;
    USE SIGNAL ;
    PORT
      LAYER M4 ;
        RECT  0 32.928 0.192 32.952 ;
    END
  END o[269]
  PIN o[26]
    DIRECTION OUTPUT ;
    USE SIGNAL ;
    PORT
      LAYER M4 ;
        RECT  0 21.264 0.192 21.288 ;
    END
  END o[26]
  PIN o[270]
    DIRECTION OUTPUT ;
    USE SIGNAL ;
    PORT
      LAYER M4 ;
        RECT  0 32.976 0.192 33 ;
    END
  END o[270]
  PIN o[271]
    DIRECTION OUTPUT ;
    USE SIGNAL ;
    PORT
      LAYER M4 ;
        RECT  0 33.024 0.192 33.048 ;
    END
  END o[271]
  PIN o[272]
    DIRECTION OUTPUT ;
    USE SIGNAL ;
    PORT
      LAYER M4 ;
        RECT  0 33.072 0.192 33.096 ;
    END
  END o[272]
  PIN o[273]
    DIRECTION OUTPUT ;
    USE SIGNAL ;
    PORT
      LAYER M4 ;
        RECT  0 33.12 0.192 33.144 ;
    END
  END o[273]
  PIN o[274]
    DIRECTION OUTPUT ;
    USE SIGNAL ;
    PORT
      LAYER M4 ;
        RECT  0 33.168 0.192 33.192 ;
    END
  END o[274]
  PIN o[275]
    DIRECTION OUTPUT ;
    USE SIGNAL ;
    PORT
      LAYER M4 ;
        RECT  0 33.216 0.192 33.24 ;
    END
  END o[275]
  PIN o[276]
    DIRECTION OUTPUT ;
    USE SIGNAL ;
    PORT
      LAYER M4 ;
        RECT  0 33.264 0.192 33.288 ;
    END
  END o[276]
  PIN o[277]
    DIRECTION OUTPUT ;
    USE SIGNAL ;
    PORT
      LAYER M4 ;
        RECT  0 33.312 0.192 33.336 ;
    END
  END o[277]
  PIN o[278]
    DIRECTION OUTPUT ;
    USE SIGNAL ;
    PORT
      LAYER M4 ;
        RECT  0 33.36 0.192 33.384 ;
    END
  END o[278]
  PIN o[279]
    DIRECTION OUTPUT ;
    USE SIGNAL ;
    PORT
      LAYER M4 ;
        RECT  0 33.408 0.192 33.432 ;
    END
  END o[279]
  PIN o[27]
    DIRECTION OUTPUT ;
    USE SIGNAL ;
    PORT
      LAYER M4 ;
        RECT  0 21.312 0.192 21.336 ;
    END
  END o[27]
  PIN o[280]
    DIRECTION OUTPUT ;
    USE SIGNAL ;
    PORT
      LAYER M4 ;
        RECT  0 33.456 0.192 33.48 ;
    END
  END o[280]
  PIN o[281]
    DIRECTION OUTPUT ;
    USE SIGNAL ;
    PORT
      LAYER M4 ;
        RECT  0 33.504 0.192 33.528 ;
    END
  END o[281]
  PIN o[282]
    DIRECTION OUTPUT ;
    USE SIGNAL ;
    PORT
      LAYER M4 ;
        RECT  0 33.552 0.192 33.576 ;
    END
  END o[282]
  PIN o[283]
    DIRECTION OUTPUT ;
    USE SIGNAL ;
    PORT
      LAYER M4 ;
        RECT  0 33.6 0.192 33.624 ;
    END
  END o[283]
  PIN o[284]
    DIRECTION OUTPUT ;
    USE SIGNAL ;
    PORT
      LAYER M4 ;
        RECT  0 33.648 0.192 33.672 ;
    END
  END o[284]
  PIN o[285]
    DIRECTION OUTPUT ;
    USE SIGNAL ;
    PORT
      LAYER M4 ;
        RECT  0 33.696 0.192 33.72 ;
    END
  END o[285]
  PIN o[286]
    DIRECTION OUTPUT ;
    USE SIGNAL ;
    PORT
      LAYER M4 ;
        RECT  0 33.744 0.192 33.768 ;
    END
  END o[286]
  PIN o[287]
    DIRECTION OUTPUT ;
    USE SIGNAL ;
    PORT
      LAYER M4 ;
        RECT  0 33.792 0.192 33.816 ;
    END
  END o[287]
  PIN o[288]
    DIRECTION OUTPUT ;
    USE SIGNAL ;
    PORT
      LAYER M4 ;
        RECT  0 33.84 0.192 33.864 ;
    END
  END o[288]
  PIN o[289]
    DIRECTION OUTPUT ;
    USE SIGNAL ;
    PORT
      LAYER M4 ;
        RECT  0 33.888 0.192 33.912 ;
    END
  END o[289]
  PIN o[28]
    DIRECTION OUTPUT ;
    USE SIGNAL ;
    PORT
      LAYER M4 ;
        RECT  0 21.36 0.192 21.384 ;
    END
  END o[28]
  PIN o[290]
    DIRECTION OUTPUT ;
    USE SIGNAL ;
    PORT
      LAYER M4 ;
        RECT  0 33.936 0.192 33.96 ;
    END
  END o[290]
  PIN o[291]
    DIRECTION OUTPUT ;
    USE SIGNAL ;
    PORT
      LAYER M4 ;
        RECT  0 33.984 0.192 34.008 ;
    END
  END o[291]
  PIN o[292]
    DIRECTION OUTPUT ;
    USE SIGNAL ;
    PORT
      LAYER M4 ;
        RECT  0 34.032 0.192 34.056 ;
    END
  END o[292]
  PIN o[293]
    DIRECTION OUTPUT ;
    USE SIGNAL ;
    PORT
      LAYER M4 ;
        RECT  0 34.08 0.192 34.104 ;
    END
  END o[293]
  PIN o[294]
    DIRECTION OUTPUT ;
    USE SIGNAL ;
    PORT
      LAYER M4 ;
        RECT  0 34.128 0.192 34.152 ;
    END
  END o[294]
  PIN o[295]
    DIRECTION OUTPUT ;
    USE SIGNAL ;
    PORT
      LAYER M4 ;
        RECT  0 34.176 0.192 34.2 ;
    END
  END o[295]
  PIN o[296]
    DIRECTION OUTPUT ;
    USE SIGNAL ;
    PORT
      LAYER M4 ;
        RECT  0 34.224 0.192 34.248 ;
    END
  END o[296]
  PIN o[297]
    DIRECTION OUTPUT ;
    USE SIGNAL ;
    PORT
      LAYER M4 ;
        RECT  0 34.272 0.192 34.296 ;
    END
  END o[297]
  PIN o[298]
    DIRECTION OUTPUT ;
    USE SIGNAL ;
    PORT
      LAYER M4 ;
        RECT  0 34.32 0.192 34.344 ;
    END
  END o[298]
  PIN o[299]
    DIRECTION OUTPUT ;
    USE SIGNAL ;
    PORT
      LAYER M4 ;
        RECT  0 34.368 0.192 34.392 ;
    END
  END o[299]
  PIN o[29]
    DIRECTION OUTPUT ;
    USE SIGNAL ;
    PORT
      LAYER M4 ;
        RECT  0 21.408 0.192 21.432 ;
    END
  END o[29]
  PIN o[2]
    DIRECTION OUTPUT ;
    USE SIGNAL ;
    PORT
      LAYER M4 ;
        RECT  0 20.112 0.192 20.136 ;
    END
  END o[2]
  PIN o[300]
    DIRECTION OUTPUT ;
    USE SIGNAL ;
    PORT
      LAYER M4 ;
        RECT  0 34.416 0.192 34.44 ;
    END
  END o[300]
  PIN o[301]
    DIRECTION OUTPUT ;
    USE SIGNAL ;
    PORT
      LAYER M4 ;
        RECT  0 34.464 0.192 34.488 ;
    END
  END o[301]
  PIN o[302]
    DIRECTION OUTPUT ;
    USE SIGNAL ;
    PORT
      LAYER M4 ;
        RECT  0 34.512 0.192 34.536 ;
    END
  END o[302]
  PIN o[303]
    DIRECTION OUTPUT ;
    USE SIGNAL ;
    PORT
      LAYER M4 ;
        RECT  0 34.56 0.192 34.584 ;
    END
  END o[303]
  PIN o[304]
    DIRECTION OUTPUT ;
    USE SIGNAL ;
    PORT
      LAYER M4 ;
        RECT  0 34.608 0.192 34.632 ;
    END
  END o[304]
  PIN o[305]
    DIRECTION OUTPUT ;
    USE SIGNAL ;
    PORT
      LAYER M4 ;
        RECT  0 34.656 0.192 34.68 ;
    END
  END o[305]
  PIN o[306]
    DIRECTION OUTPUT ;
    USE SIGNAL ;
    PORT
      LAYER M4 ;
        RECT  0 34.704 0.192 34.728 ;
    END
  END o[306]
  PIN o[307]
    DIRECTION OUTPUT ;
    USE SIGNAL ;
    PORT
      LAYER M4 ;
        RECT  0 34.752 0.192 34.776 ;
    END
  END o[307]
  PIN o[308]
    DIRECTION OUTPUT ;
    USE SIGNAL ;
    PORT
      LAYER M4 ;
        RECT  0 34.8 0.192 34.824 ;
    END
  END o[308]
  PIN o[309]
    DIRECTION OUTPUT ;
    USE SIGNAL ;
    PORT
      LAYER M4 ;
        RECT  0 34.848 0.192 34.872 ;
    END
  END o[309]
  PIN o[30]
    DIRECTION OUTPUT ;
    USE SIGNAL ;
    PORT
      LAYER M4 ;
        RECT  0 21.456 0.192 21.48 ;
    END
  END o[30]
  PIN o[310]
    DIRECTION OUTPUT ;
    USE SIGNAL ;
    PORT
      LAYER M4 ;
        RECT  0 34.896 0.192 34.92 ;
    END
  END o[310]
  PIN o[311]
    DIRECTION OUTPUT ;
    USE SIGNAL ;
    PORT
      LAYER M4 ;
        RECT  0 34.944 0.192 34.968 ;
    END
  END o[311]
  PIN o[312]
    DIRECTION OUTPUT ;
    USE SIGNAL ;
    PORT
      LAYER M4 ;
        RECT  0 34.992 0.192 35.016 ;
    END
  END o[312]
  PIN o[313]
    DIRECTION OUTPUT ;
    USE SIGNAL ;
    PORT
      LAYER M4 ;
        RECT  0 35.04 0.192 35.064 ;
    END
  END o[313]
  PIN o[314]
    DIRECTION OUTPUT ;
    USE SIGNAL ;
    PORT
      LAYER M4 ;
        RECT  0 35.088 0.192 35.112 ;
    END
  END o[314]
  PIN o[315]
    DIRECTION OUTPUT ;
    USE SIGNAL ;
    PORT
      LAYER M4 ;
        RECT  0 35.136 0.192 35.16 ;
    END
  END o[315]
  PIN o[316]
    DIRECTION OUTPUT ;
    USE SIGNAL ;
    PORT
      LAYER M4 ;
        RECT  0 35.184 0.192 35.208 ;
    END
  END o[316]
  PIN o[317]
    DIRECTION OUTPUT ;
    USE SIGNAL ;
    PORT
      LAYER M4 ;
        RECT  0 35.232 0.192 35.256 ;
    END
  END o[317]
  PIN o[318]
    DIRECTION OUTPUT ;
    USE SIGNAL ;
    PORT
      LAYER M4 ;
        RECT  0 35.28 0.192 35.304 ;
    END
  END o[318]
  PIN o[319]
    DIRECTION OUTPUT ;
    USE SIGNAL ;
    PORT
      LAYER M4 ;
        RECT  0 35.328 0.192 35.352 ;
    END
  END o[319]
  PIN o[31]
    DIRECTION OUTPUT ;
    USE SIGNAL ;
    PORT
      LAYER M4 ;
        RECT  0 21.504 0.192 21.528 ;
    END
  END o[31]
  PIN o[320]
    DIRECTION OUTPUT ;
    USE SIGNAL ;
    PORT
      LAYER M4 ;
        RECT  0 35.376 0.192 35.4 ;
    END
  END o[320]
  PIN o[321]
    DIRECTION OUTPUT ;
    USE SIGNAL ;
    PORT
      LAYER M4 ;
        RECT  0 35.424 0.192 35.448 ;
    END
  END o[321]
  PIN o[322]
    DIRECTION OUTPUT ;
    USE SIGNAL ;
    PORT
      LAYER M4 ;
        RECT  0 35.472 0.192 35.496 ;
    END
  END o[322]
  PIN o[323]
    DIRECTION OUTPUT ;
    USE SIGNAL ;
    PORT
      LAYER M4 ;
        RECT  0 35.52 0.192 35.544 ;
    END
  END o[323]
  PIN o[324]
    DIRECTION OUTPUT ;
    USE SIGNAL ;
    PORT
      LAYER M4 ;
        RECT  0 35.568 0.192 35.592 ;
    END
  END o[324]
  PIN o[325]
    DIRECTION OUTPUT ;
    USE SIGNAL ;
    PORT
      LAYER M4 ;
        RECT  0 35.616 0.192 35.64 ;
    END
  END o[325]
  PIN o[326]
    DIRECTION OUTPUT ;
    USE SIGNAL ;
    PORT
      LAYER M4 ;
        RECT  0 35.664 0.192 35.688 ;
    END
  END o[326]
  PIN o[327]
    DIRECTION OUTPUT ;
    USE SIGNAL ;
    PORT
      LAYER M4 ;
        RECT  0 35.712 0.192 35.736 ;
    END
  END o[327]
  PIN o[328]
    DIRECTION OUTPUT ;
    USE SIGNAL ;
    PORT
      LAYER M4 ;
        RECT  0 35.76 0.192 35.784 ;
    END
  END o[328]
  PIN o[329]
    DIRECTION OUTPUT ;
    USE SIGNAL ;
    PORT
      LAYER M4 ;
        RECT  0 35.808 0.192 35.832 ;
    END
  END o[329]
  PIN o[32]
    DIRECTION OUTPUT ;
    USE SIGNAL ;
    PORT
      LAYER M4 ;
        RECT  0 21.552 0.192 21.576 ;
    END
  END o[32]
  PIN o[330]
    DIRECTION OUTPUT ;
    USE SIGNAL ;
    PORT
      LAYER M4 ;
        RECT  0 35.856 0.192 35.88 ;
    END
  END o[330]
  PIN o[331]
    DIRECTION OUTPUT ;
    USE SIGNAL ;
    PORT
      LAYER M4 ;
        RECT  0 35.904 0.192 35.928 ;
    END
  END o[331]
  PIN o[332]
    DIRECTION OUTPUT ;
    USE SIGNAL ;
    PORT
      LAYER M4 ;
        RECT  0 35.952 0.192 35.976 ;
    END
  END o[332]
  PIN o[333]
    DIRECTION OUTPUT ;
    USE SIGNAL ;
    PORT
      LAYER M4 ;
        RECT  0 36 0.192 36.024 ;
    END
  END o[333]
  PIN o[334]
    DIRECTION OUTPUT ;
    USE SIGNAL ;
    PORT
      LAYER M4 ;
        RECT  0 36.048 0.192 36.072 ;
    END
  END o[334]
  PIN o[335]
    DIRECTION OUTPUT ;
    USE SIGNAL ;
    PORT
      LAYER M4 ;
        RECT  0 36.096 0.192 36.12 ;
    END
  END o[335]
  PIN o[336]
    DIRECTION OUTPUT ;
    USE SIGNAL ;
    PORT
      LAYER M4 ;
        RECT  0 36.144 0.192 36.168 ;
    END
  END o[336]
  PIN o[337]
    DIRECTION OUTPUT ;
    USE SIGNAL ;
    PORT
      LAYER M4 ;
        RECT  0 36.192 0.192 36.216 ;
    END
  END o[337]
  PIN o[338]
    DIRECTION OUTPUT ;
    USE SIGNAL ;
    PORT
      LAYER M4 ;
        RECT  0 36.24 0.192 36.264 ;
    END
  END o[338]
  PIN o[339]
    DIRECTION OUTPUT ;
    USE SIGNAL ;
    PORT
      LAYER M4 ;
        RECT  0 36.288 0.192 36.312 ;
    END
  END o[339]
  PIN o[33]
    DIRECTION OUTPUT ;
    USE SIGNAL ;
    PORT
      LAYER M4 ;
        RECT  0 21.6 0.192 21.624 ;
    END
  END o[33]
  PIN o[340]
    DIRECTION OUTPUT ;
    USE SIGNAL ;
    PORT
      LAYER M4 ;
        RECT  0 36.336 0.192 36.36 ;
    END
  END o[340]
  PIN o[341]
    DIRECTION OUTPUT ;
    USE SIGNAL ;
    PORT
      LAYER M4 ;
        RECT  0 36.384 0.192 36.408 ;
    END
  END o[341]
  PIN o[342]
    DIRECTION OUTPUT ;
    USE SIGNAL ;
    PORT
      LAYER M4 ;
        RECT  0 36.432 0.192 36.456 ;
    END
  END o[342]
  PIN o[343]
    DIRECTION OUTPUT ;
    USE SIGNAL ;
    PORT
      LAYER M4 ;
        RECT  0 36.48 0.192 36.504 ;
    END
  END o[343]
  PIN o[344]
    DIRECTION OUTPUT ;
    USE SIGNAL ;
    PORT
      LAYER M4 ;
        RECT  0 36.528 0.192 36.552 ;
    END
  END o[344]
  PIN o[345]
    DIRECTION OUTPUT ;
    USE SIGNAL ;
    PORT
      LAYER M4 ;
        RECT  0 36.576 0.192 36.6 ;
    END
  END o[345]
  PIN o[346]
    DIRECTION OUTPUT ;
    USE SIGNAL ;
    PORT
      LAYER M4 ;
        RECT  0 36.624 0.192 36.648 ;
    END
  END o[346]
  PIN o[347]
    DIRECTION OUTPUT ;
    USE SIGNAL ;
    PORT
      LAYER M4 ;
        RECT  0 36.672 0.192 36.696 ;
    END
  END o[347]
  PIN o[348]
    DIRECTION OUTPUT ;
    USE SIGNAL ;
    PORT
      LAYER M4 ;
        RECT  0 36.72 0.192 36.744 ;
    END
  END o[348]
  PIN o[349]
    DIRECTION OUTPUT ;
    USE SIGNAL ;
    PORT
      LAYER M4 ;
        RECT  0 36.768 0.192 36.792 ;
    END
  END o[349]
  PIN o[34]
    DIRECTION OUTPUT ;
    USE SIGNAL ;
    PORT
      LAYER M4 ;
        RECT  0 21.648 0.192 21.672 ;
    END
  END o[34]
  PIN o[350]
    DIRECTION OUTPUT ;
    USE SIGNAL ;
    PORT
      LAYER M4 ;
        RECT  0 36.816 0.192 36.84 ;
    END
  END o[350]
  PIN o[351]
    DIRECTION OUTPUT ;
    USE SIGNAL ;
    PORT
      LAYER M4 ;
        RECT  0 36.864 0.192 36.888 ;
    END
  END o[351]
  PIN o[352]
    DIRECTION OUTPUT ;
    USE SIGNAL ;
    PORT
      LAYER M4 ;
        RECT  0 36.912 0.192 36.936 ;
    END
  END o[352]
  PIN o[353]
    DIRECTION OUTPUT ;
    USE SIGNAL ;
    PORT
      LAYER M4 ;
        RECT  0 36.96 0.192 36.984 ;
    END
  END o[353]
  PIN o[354]
    DIRECTION OUTPUT ;
    USE SIGNAL ;
    PORT
      LAYER M4 ;
        RECT  0 37.008 0.192 37.032 ;
    END
  END o[354]
  PIN o[355]
    DIRECTION OUTPUT ;
    USE SIGNAL ;
    PORT
      LAYER M4 ;
        RECT  0 37.056 0.192 37.08 ;
    END
  END o[355]
  PIN o[356]
    DIRECTION OUTPUT ;
    USE SIGNAL ;
    PORT
      LAYER M4 ;
        RECT  0 37.104 0.192 37.128 ;
    END
  END o[356]
  PIN o[357]
    DIRECTION OUTPUT ;
    USE SIGNAL ;
    PORT
      LAYER M4 ;
        RECT  0 37.152 0.192 37.176 ;
    END
  END o[357]
  PIN o[358]
    DIRECTION OUTPUT ;
    USE SIGNAL ;
    PORT
      LAYER M4 ;
        RECT  0 37.2 0.192 37.224 ;
    END
  END o[358]
  PIN o[359]
    DIRECTION OUTPUT ;
    USE SIGNAL ;
    PORT
      LAYER M4 ;
        RECT  0 37.248 0.192 37.272 ;
    END
  END o[359]
  PIN o[35]
    DIRECTION OUTPUT ;
    USE SIGNAL ;
    PORT
      LAYER M4 ;
        RECT  0 21.696 0.192 21.72 ;
    END
  END o[35]
  PIN o[360]
    DIRECTION OUTPUT ;
    USE SIGNAL ;
    PORT
      LAYER M4 ;
        RECT  0 37.296 0.192 37.32 ;
    END
  END o[360]
  PIN o[361]
    DIRECTION OUTPUT ;
    USE SIGNAL ;
    PORT
      LAYER M4 ;
        RECT  0 37.344 0.192 37.368 ;
    END
  END o[361]
  PIN o[362]
    DIRECTION OUTPUT ;
    USE SIGNAL ;
    PORT
      LAYER M4 ;
        RECT  0 37.392 0.192 37.416 ;
    END
  END o[362]
  PIN o[363]
    DIRECTION OUTPUT ;
    USE SIGNAL ;
    PORT
      LAYER M4 ;
        RECT  0 37.44 0.192 37.464 ;
    END
  END o[363]
  PIN o[364]
    DIRECTION OUTPUT ;
    USE SIGNAL ;
    PORT
      LAYER M4 ;
        RECT  0 37.488 0.192 37.512 ;
    END
  END o[364]
  PIN o[365]
    DIRECTION OUTPUT ;
    USE SIGNAL ;
    PORT
      LAYER M4 ;
        RECT  0 37.536 0.192 37.56 ;
    END
  END o[365]
  PIN o[366]
    DIRECTION OUTPUT ;
    USE SIGNAL ;
    PORT
      LAYER M4 ;
        RECT  0 37.584 0.192 37.608 ;
    END
  END o[366]
  PIN o[367]
    DIRECTION OUTPUT ;
    USE SIGNAL ;
    PORT
      LAYER M4 ;
        RECT  0 37.632 0.192 37.656 ;
    END
  END o[367]
  PIN o[368]
    DIRECTION OUTPUT ;
    USE SIGNAL ;
    PORT
      LAYER M4 ;
        RECT  0 37.68 0.192 37.704 ;
    END
  END o[368]
  PIN o[369]
    DIRECTION OUTPUT ;
    USE SIGNAL ;
    PORT
      LAYER M4 ;
        RECT  0 37.728 0.192 37.752 ;
    END
  END o[369]
  PIN o[36]
    DIRECTION OUTPUT ;
    USE SIGNAL ;
    PORT
      LAYER M4 ;
        RECT  0 21.744 0.192 21.768 ;
    END
  END o[36]
  PIN o[370]
    DIRECTION OUTPUT ;
    USE SIGNAL ;
    PORT
      LAYER M4 ;
        RECT  0 37.776 0.192 37.8 ;
    END
  END o[370]
  PIN o[371]
    DIRECTION OUTPUT ;
    USE SIGNAL ;
    PORT
      LAYER M4 ;
        RECT  0 37.824 0.192 37.848 ;
    END
  END o[371]
  PIN o[372]
    DIRECTION OUTPUT ;
    USE SIGNAL ;
    PORT
      LAYER M4 ;
        RECT  0 37.872 0.192 37.896 ;
    END
  END o[372]
  PIN o[373]
    DIRECTION OUTPUT ;
    USE SIGNAL ;
    PORT
      LAYER M4 ;
        RECT  0 37.92 0.192 37.944 ;
    END
  END o[373]
  PIN o[374]
    DIRECTION OUTPUT ;
    USE SIGNAL ;
    PORT
      LAYER M4 ;
        RECT  0 37.968 0.192 37.992 ;
    END
  END o[374]
  PIN o[375]
    DIRECTION OUTPUT ;
    USE SIGNAL ;
    PORT
      LAYER M4 ;
        RECT  0 38.016 0.192 38.04 ;
    END
  END o[375]
  PIN o[376]
    DIRECTION OUTPUT ;
    USE SIGNAL ;
    PORT
      LAYER M4 ;
        RECT  0 38.064 0.192 38.088 ;
    END
  END o[376]
  PIN o[377]
    DIRECTION OUTPUT ;
    USE SIGNAL ;
    PORT
      LAYER M4 ;
        RECT  0 38.112 0.192 38.136 ;
    END
  END o[377]
  PIN o[378]
    DIRECTION OUTPUT ;
    USE SIGNAL ;
    PORT
      LAYER M4 ;
        RECT  0 38.16 0.192 38.184 ;
    END
  END o[378]
  PIN o[379]
    DIRECTION OUTPUT ;
    USE SIGNAL ;
    PORT
      LAYER M4 ;
        RECT  0 38.208 0.192 38.232 ;
    END
  END o[379]
  PIN o[37]
    DIRECTION OUTPUT ;
    USE SIGNAL ;
    PORT
      LAYER M4 ;
        RECT  0 21.792 0.192 21.816 ;
    END
  END o[37]
  PIN o[380]
    DIRECTION OUTPUT ;
    USE SIGNAL ;
    PORT
      LAYER M4 ;
        RECT  0 38.256 0.192 38.28 ;
    END
  END o[380]
  PIN o[381]
    DIRECTION OUTPUT ;
    USE SIGNAL ;
    PORT
      LAYER M4 ;
        RECT  0 38.304 0.192 38.328 ;
    END
  END o[381]
  PIN o[382]
    DIRECTION OUTPUT ;
    USE SIGNAL ;
    PORT
      LAYER M4 ;
        RECT  0 38.352 0.192 38.376 ;
    END
  END o[382]
  PIN o[383]
    DIRECTION OUTPUT ;
    USE SIGNAL ;
    PORT
      LAYER M4 ;
        RECT  0 38.4 0.192 38.424 ;
    END
  END o[383]
  PIN o[384]
    DIRECTION OUTPUT ;
    USE SIGNAL ;
    PORT
      LAYER M4 ;
        RECT  0 38.448 0.192 38.472 ;
    END
  END o[384]
  PIN o[385]
    DIRECTION OUTPUT ;
    USE SIGNAL ;
    PORT
      LAYER M4 ;
        RECT  0 38.496 0.192 38.52 ;
    END
  END o[385]
  PIN o[386]
    DIRECTION OUTPUT ;
    USE SIGNAL ;
    PORT
      LAYER M4 ;
        RECT  0 38.544 0.192 38.568 ;
    END
  END o[386]
  PIN o[387]
    DIRECTION OUTPUT ;
    USE SIGNAL ;
    PORT
      LAYER M4 ;
        RECT  0 38.592 0.192 38.616 ;
    END
  END o[387]
  PIN o[388]
    DIRECTION OUTPUT ;
    USE SIGNAL ;
    PORT
      LAYER M4 ;
        RECT  0 38.64 0.192 38.664 ;
    END
  END o[388]
  PIN o[389]
    DIRECTION OUTPUT ;
    USE SIGNAL ;
    PORT
      LAYER M4 ;
        RECT  0 38.688 0.192 38.712 ;
    END
  END o[389]
  PIN o[38]
    DIRECTION OUTPUT ;
    USE SIGNAL ;
    PORT
      LAYER M4 ;
        RECT  0 21.84 0.192 21.864 ;
    END
  END o[38]
  PIN o[390]
    DIRECTION OUTPUT ;
    USE SIGNAL ;
    PORT
      LAYER M4 ;
        RECT  0 38.736 0.192 38.76 ;
    END
  END o[390]
  PIN o[391]
    DIRECTION OUTPUT ;
    USE SIGNAL ;
    PORT
      LAYER M4 ;
        RECT  0 38.784 0.192 38.808 ;
    END
  END o[391]
  PIN o[392]
    DIRECTION OUTPUT ;
    USE SIGNAL ;
    PORT
      LAYER M4 ;
        RECT  0 38.832 0.192 38.856 ;
    END
  END o[392]
  PIN o[393]
    DIRECTION OUTPUT ;
    USE SIGNAL ;
    PORT
      LAYER M4 ;
        RECT  0 38.88 0.192 38.904 ;
    END
  END o[393]
  PIN o[394]
    DIRECTION OUTPUT ;
    USE SIGNAL ;
    PORT
      LAYER M4 ;
        RECT  0 38.928 0.192 38.952 ;
    END
  END o[394]
  PIN o[395]
    DIRECTION OUTPUT ;
    USE SIGNAL ;
    PORT
      LAYER M4 ;
        RECT  0 38.976 0.192 39 ;
    END
  END o[395]
  PIN o[396]
    DIRECTION OUTPUT ;
    USE SIGNAL ;
    PORT
      LAYER M4 ;
        RECT  0 39.024 0.192 39.048 ;
    END
  END o[396]
  PIN o[397]
    DIRECTION OUTPUT ;
    USE SIGNAL ;
    PORT
      LAYER M4 ;
        RECT  0 39.072 0.192 39.096 ;
    END
  END o[397]
  PIN o[398]
    DIRECTION OUTPUT ;
    USE SIGNAL ;
    PORT
      LAYER M4 ;
        RECT  0 39.12 0.192 39.144 ;
    END
  END o[398]
  PIN o[399]
    DIRECTION OUTPUT ;
    USE SIGNAL ;
    PORT
      LAYER M4 ;
        RECT  0 39.168 0.192 39.192 ;
    END
  END o[399]
  PIN o[39]
    DIRECTION OUTPUT ;
    USE SIGNAL ;
    PORT
      LAYER M4 ;
        RECT  0 21.888 0.192 21.912 ;
    END
  END o[39]
  PIN o[3]
    DIRECTION OUTPUT ;
    USE SIGNAL ;
    PORT
      LAYER M4 ;
        RECT  0 20.16 0.192 20.184 ;
    END
  END o[3]
  PIN o[400]
    DIRECTION OUTPUT ;
    USE SIGNAL ;
    PORT
      LAYER M4 ;
        RECT  0 39.216 0.192 39.24 ;
    END
  END o[400]
  PIN o[401]
    DIRECTION OUTPUT ;
    USE SIGNAL ;
    PORT
      LAYER M4 ;
        RECT  0 39.264 0.192 39.288 ;
    END
  END o[401]
  PIN o[402]
    DIRECTION OUTPUT ;
    USE SIGNAL ;
    PORT
      LAYER M4 ;
        RECT  0 39.312 0.192 39.336 ;
    END
  END o[402]
  PIN o[403]
    DIRECTION OUTPUT ;
    USE SIGNAL ;
    PORT
      LAYER M4 ;
        RECT  0 39.36 0.192 39.384 ;
    END
  END o[403]
  PIN o[404]
    DIRECTION OUTPUT ;
    USE SIGNAL ;
    PORT
      LAYER M4 ;
        RECT  0 39.408 0.192 39.432 ;
    END
  END o[404]
  PIN o[405]
    DIRECTION OUTPUT ;
    USE SIGNAL ;
    PORT
      LAYER M4 ;
        RECT  0 39.456 0.192 39.48 ;
    END
  END o[405]
  PIN o[406]
    DIRECTION OUTPUT ;
    USE SIGNAL ;
    PORT
      LAYER M4 ;
        RECT  0 39.504 0.192 39.528 ;
    END
  END o[406]
  PIN o[407]
    DIRECTION OUTPUT ;
    USE SIGNAL ;
    PORT
      LAYER M4 ;
        RECT  0 39.552 0.192 39.576 ;
    END
  END o[407]
  PIN o[408]
    DIRECTION OUTPUT ;
    USE SIGNAL ;
    PORT
      LAYER M4 ;
        RECT  0 39.6 0.192 39.624 ;
    END
  END o[408]
  PIN o[409]
    DIRECTION OUTPUT ;
    USE SIGNAL ;
    PORT
      LAYER M4 ;
        RECT  0 39.648 0.192 39.672 ;
    END
  END o[409]
  PIN o[40]
    DIRECTION OUTPUT ;
    USE SIGNAL ;
    PORT
      LAYER M4 ;
        RECT  0 21.936 0.192 21.96 ;
    END
  END o[40]
  PIN o[410]
    DIRECTION OUTPUT ;
    USE SIGNAL ;
    PORT
      LAYER M4 ;
        RECT  0 39.696 0.192 39.72 ;
    END
  END o[410]
  PIN o[411]
    DIRECTION OUTPUT ;
    USE SIGNAL ;
    PORT
      LAYER M4 ;
        RECT  0 39.744 0.192 39.768 ;
    END
  END o[411]
  PIN o[412]
    DIRECTION OUTPUT ;
    USE SIGNAL ;
    PORT
      LAYER M4 ;
        RECT  0 39.792 0.192 39.816 ;
    END
  END o[412]
  PIN o[413]
    DIRECTION OUTPUT ;
    USE SIGNAL ;
    PORT
      LAYER M4 ;
        RECT  0 39.84 0.192 39.864 ;
    END
  END o[413]
  PIN o[414]
    DIRECTION OUTPUT ;
    USE SIGNAL ;
    PORT
      LAYER M4 ;
        RECT  0 39.888 0.192 39.912 ;
    END
  END o[414]
  PIN o[415]
    DIRECTION OUTPUT ;
    USE SIGNAL ;
    PORT
      LAYER M4 ;
        RECT  0 39.936 0.192 39.96 ;
    END
  END o[415]
  PIN o[416]
    DIRECTION OUTPUT ;
    USE SIGNAL ;
    PORT
      LAYER M4 ;
        RECT  0 39.984 0.192 40.008 ;
    END
  END o[416]
  PIN o[417]
    DIRECTION OUTPUT ;
    USE SIGNAL ;
    PORT
      LAYER M4 ;
        RECT  0 40.032 0.192 40.056 ;
    END
  END o[417]
  PIN o[418]
    DIRECTION OUTPUT ;
    USE SIGNAL ;
    PORT
      LAYER M4 ;
        RECT  0 40.08 0.192 40.104 ;
    END
  END o[418]
  PIN o[419]
    DIRECTION OUTPUT ;
    USE SIGNAL ;
    PORT
      LAYER M4 ;
        RECT  0 40.128 0.192 40.152 ;
    END
  END o[419]
  PIN o[41]
    DIRECTION OUTPUT ;
    USE SIGNAL ;
    PORT
      LAYER M4 ;
        RECT  0 21.984 0.192 22.008 ;
    END
  END o[41]
  PIN o[420]
    DIRECTION OUTPUT ;
    USE SIGNAL ;
    PORT
      LAYER M4 ;
        RECT  0 40.176 0.192 40.2 ;
    END
  END o[420]
  PIN o[421]
    DIRECTION OUTPUT ;
    USE SIGNAL ;
    PORT
      LAYER M4 ;
        RECT  0 40.224 0.192 40.248 ;
    END
  END o[421]
  PIN o[422]
    DIRECTION OUTPUT ;
    USE SIGNAL ;
    PORT
      LAYER M4 ;
        RECT  0 40.272 0.192 40.296 ;
    END
  END o[422]
  PIN o[423]
    DIRECTION OUTPUT ;
    USE SIGNAL ;
    PORT
      LAYER M4 ;
        RECT  0 40.32 0.192 40.344 ;
    END
  END o[423]
  PIN o[424]
    DIRECTION OUTPUT ;
    USE SIGNAL ;
    PORT
      LAYER M4 ;
        RECT  0 40.368 0.192 40.392 ;
    END
  END o[424]
  PIN o[425]
    DIRECTION OUTPUT ;
    USE SIGNAL ;
    PORT
      LAYER M4 ;
        RECT  0 40.416 0.192 40.44 ;
    END
  END o[425]
  PIN o[426]
    DIRECTION OUTPUT ;
    USE SIGNAL ;
    PORT
      LAYER M4 ;
        RECT  0 40.464 0.192 40.488 ;
    END
  END o[426]
  PIN o[427]
    DIRECTION OUTPUT ;
    USE SIGNAL ;
    PORT
      LAYER M4 ;
        RECT  0 40.512 0.192 40.536 ;
    END
  END o[427]
  PIN o[428]
    DIRECTION OUTPUT ;
    USE SIGNAL ;
    PORT
      LAYER M4 ;
        RECT  0 40.56 0.192 40.584 ;
    END
  END o[428]
  PIN o[429]
    DIRECTION OUTPUT ;
    USE SIGNAL ;
    PORT
      LAYER M4 ;
        RECT  0 40.608 0.192 40.632 ;
    END
  END o[429]
  PIN o[42]
    DIRECTION OUTPUT ;
    USE SIGNAL ;
    PORT
      LAYER M4 ;
        RECT  0 22.032 0.192 22.056 ;
    END
  END o[42]
  PIN o[430]
    DIRECTION OUTPUT ;
    USE SIGNAL ;
    PORT
      LAYER M4 ;
        RECT  0 40.656 0.192 40.68 ;
    END
  END o[430]
  PIN o[431]
    DIRECTION OUTPUT ;
    USE SIGNAL ;
    PORT
      LAYER M4 ;
        RECT  0 40.704 0.192 40.728 ;
    END
  END o[431]
  PIN o[432]
    DIRECTION OUTPUT ;
    USE SIGNAL ;
    PORT
      LAYER M4 ;
        RECT  0 40.752 0.192 40.776 ;
    END
  END o[432]
  PIN o[433]
    DIRECTION OUTPUT ;
    USE SIGNAL ;
    PORT
      LAYER M4 ;
        RECT  0 40.8 0.192 40.824 ;
    END
  END o[433]
  PIN o[434]
    DIRECTION OUTPUT ;
    USE SIGNAL ;
    PORT
      LAYER M4 ;
        RECT  0 40.848 0.192 40.872 ;
    END
  END o[434]
  PIN o[435]
    DIRECTION OUTPUT ;
    USE SIGNAL ;
    PORT
      LAYER M4 ;
        RECT  0 40.896 0.192 40.92 ;
    END
  END o[435]
  PIN o[436]
    DIRECTION OUTPUT ;
    USE SIGNAL ;
    PORT
      LAYER M4 ;
        RECT  0 40.944 0.192 40.968 ;
    END
  END o[436]
  PIN o[437]
    DIRECTION OUTPUT ;
    USE SIGNAL ;
    PORT
      LAYER M4 ;
        RECT  0 40.992 0.192 41.016 ;
    END
  END o[437]
  PIN o[438]
    DIRECTION OUTPUT ;
    USE SIGNAL ;
    PORT
      LAYER M4 ;
        RECT  0 41.04 0.192 41.064 ;
    END
  END o[438]
  PIN o[439]
    DIRECTION OUTPUT ;
    USE SIGNAL ;
    PORT
      LAYER M4 ;
        RECT  0 41.088 0.192 41.112 ;
    END
  END o[439]
  PIN o[43]
    DIRECTION OUTPUT ;
    USE SIGNAL ;
    PORT
      LAYER M4 ;
        RECT  0 22.08 0.192 22.104 ;
    END
  END o[43]
  PIN o[440]
    DIRECTION OUTPUT ;
    USE SIGNAL ;
    PORT
      LAYER M4 ;
        RECT  0 41.136 0.192 41.16 ;
    END
  END o[440]
  PIN o[441]
    DIRECTION OUTPUT ;
    USE SIGNAL ;
    PORT
      LAYER M4 ;
        RECT  0 41.184 0.192 41.208 ;
    END
  END o[441]
  PIN o[442]
    DIRECTION OUTPUT ;
    USE SIGNAL ;
    PORT
      LAYER M4 ;
        RECT  0 41.232 0.192 41.256 ;
    END
  END o[442]
  PIN o[443]
    DIRECTION OUTPUT ;
    USE SIGNAL ;
    PORT
      LAYER M4 ;
        RECT  0 41.28 0.192 41.304 ;
    END
  END o[443]
  PIN o[444]
    DIRECTION OUTPUT ;
    USE SIGNAL ;
    PORT
      LAYER M4 ;
        RECT  0 41.328 0.192 41.352 ;
    END
  END o[444]
  PIN o[445]
    DIRECTION OUTPUT ;
    USE SIGNAL ;
    PORT
      LAYER M4 ;
        RECT  0 41.376 0.192 41.4 ;
    END
  END o[445]
  PIN o[446]
    DIRECTION OUTPUT ;
    USE SIGNAL ;
    PORT
      LAYER M4 ;
        RECT  0 41.424 0.192 41.448 ;
    END
  END o[446]
  PIN o[447]
    DIRECTION OUTPUT ;
    USE SIGNAL ;
    PORT
      LAYER M4 ;
        RECT  0 41.472 0.192 41.496 ;
    END
  END o[447]
  PIN o[448]
    DIRECTION OUTPUT ;
    USE SIGNAL ;
    PORT
      LAYER M4 ;
        RECT  0 41.52 0.192 41.544 ;
    END
  END o[448]
  PIN o[449]
    DIRECTION OUTPUT ;
    USE SIGNAL ;
    PORT
      LAYER M4 ;
        RECT  0 41.568 0.192 41.592 ;
    END
  END o[449]
  PIN o[44]
    DIRECTION OUTPUT ;
    USE SIGNAL ;
    PORT
      LAYER M4 ;
        RECT  0 22.128 0.192 22.152 ;
    END
  END o[44]
  PIN o[450]
    DIRECTION OUTPUT ;
    USE SIGNAL ;
    PORT
      LAYER M4 ;
        RECT  0 41.616 0.192 41.64 ;
    END
  END o[450]
  PIN o[451]
    DIRECTION OUTPUT ;
    USE SIGNAL ;
    PORT
      LAYER M4 ;
        RECT  0 41.664 0.192 41.688 ;
    END
  END o[451]
  PIN o[452]
    DIRECTION OUTPUT ;
    USE SIGNAL ;
    PORT
      LAYER M4 ;
        RECT  0 41.712 0.192 41.736 ;
    END
  END o[452]
  PIN o[453]
    DIRECTION OUTPUT ;
    USE SIGNAL ;
    PORT
      LAYER M4 ;
        RECT  0 41.76 0.192 41.784 ;
    END
  END o[453]
  PIN o[454]
    DIRECTION OUTPUT ;
    USE SIGNAL ;
    PORT
      LAYER M4 ;
        RECT  0 41.808 0.192 41.832 ;
    END
  END o[454]
  PIN o[455]
    DIRECTION OUTPUT ;
    USE SIGNAL ;
    PORT
      LAYER M4 ;
        RECT  0 41.856 0.192 41.88 ;
    END
  END o[455]
  PIN o[456]
    DIRECTION OUTPUT ;
    USE SIGNAL ;
    PORT
      LAYER M4 ;
        RECT  0 41.904 0.192 41.928 ;
    END
  END o[456]
  PIN o[457]
    DIRECTION OUTPUT ;
    USE SIGNAL ;
    PORT
      LAYER M4 ;
        RECT  0 41.952 0.192 41.976 ;
    END
  END o[457]
  PIN o[458]
    DIRECTION OUTPUT ;
    USE SIGNAL ;
    PORT
      LAYER M4 ;
        RECT  0 42 0.192 42.024 ;
    END
  END o[458]
  PIN o[459]
    DIRECTION OUTPUT ;
    USE SIGNAL ;
    PORT
      LAYER M4 ;
        RECT  0 42.048 0.192 42.072 ;
    END
  END o[459]
  PIN o[45]
    DIRECTION OUTPUT ;
    USE SIGNAL ;
    PORT
      LAYER M4 ;
        RECT  0 22.176 0.192 22.2 ;
    END
  END o[45]
  PIN o[460]
    DIRECTION OUTPUT ;
    USE SIGNAL ;
    PORT
      LAYER M4 ;
        RECT  0 42.096 0.192 42.12 ;
    END
  END o[460]
  PIN o[461]
    DIRECTION OUTPUT ;
    USE SIGNAL ;
    PORT
      LAYER M4 ;
        RECT  0 42.144 0.192 42.168 ;
    END
  END o[461]
  PIN o[462]
    DIRECTION OUTPUT ;
    USE SIGNAL ;
    PORT
      LAYER M4 ;
        RECT  0 42.192 0.192 42.216 ;
    END
  END o[462]
  PIN o[463]
    DIRECTION OUTPUT ;
    USE SIGNAL ;
    PORT
      LAYER M4 ;
        RECT  0 42.24 0.192 42.264 ;
    END
  END o[463]
  PIN o[464]
    DIRECTION OUTPUT ;
    USE SIGNAL ;
    PORT
      LAYER M4 ;
        RECT  0 42.288 0.192 42.312 ;
    END
  END o[464]
  PIN o[465]
    DIRECTION OUTPUT ;
    USE SIGNAL ;
    PORT
      LAYER M4 ;
        RECT  0 42.336 0.192 42.36 ;
    END
  END o[465]
  PIN o[466]
    DIRECTION OUTPUT ;
    USE SIGNAL ;
    PORT
      LAYER M4 ;
        RECT  0 42.384 0.192 42.408 ;
    END
  END o[466]
  PIN o[467]
    DIRECTION OUTPUT ;
    USE SIGNAL ;
    PORT
      LAYER M4 ;
        RECT  0 42.432 0.192 42.456 ;
    END
  END o[467]
  PIN o[468]
    DIRECTION OUTPUT ;
    USE SIGNAL ;
    PORT
      LAYER M4 ;
        RECT  0 42.48 0.192 42.504 ;
    END
  END o[468]
  PIN o[469]
    DIRECTION OUTPUT ;
    USE SIGNAL ;
    PORT
      LAYER M4 ;
        RECT  0 42.528 0.192 42.552 ;
    END
  END o[469]
  PIN o[46]
    DIRECTION OUTPUT ;
    USE SIGNAL ;
    PORT
      LAYER M4 ;
        RECT  0 22.224 0.192 22.248 ;
    END
  END o[46]
  PIN o[470]
    DIRECTION OUTPUT ;
    USE SIGNAL ;
    PORT
      LAYER M4 ;
        RECT  0 42.576 0.192 42.6 ;
    END
  END o[470]
  PIN o[471]
    DIRECTION OUTPUT ;
    USE SIGNAL ;
    PORT
      LAYER M4 ;
        RECT  0 42.624 0.192 42.648 ;
    END
  END o[471]
  PIN o[472]
    DIRECTION OUTPUT ;
    USE SIGNAL ;
    PORT
      LAYER M4 ;
        RECT  0 42.672 0.192 42.696 ;
    END
  END o[472]
  PIN o[473]
    DIRECTION OUTPUT ;
    USE SIGNAL ;
    PORT
      LAYER M4 ;
        RECT  0 42.72 0.192 42.744 ;
    END
  END o[473]
  PIN o[474]
    DIRECTION OUTPUT ;
    USE SIGNAL ;
    PORT
      LAYER M4 ;
        RECT  0 42.768 0.192 42.792 ;
    END
  END o[474]
  PIN o[475]
    DIRECTION OUTPUT ;
    USE SIGNAL ;
    PORT
      LAYER M4 ;
        RECT  0 42.816 0.192 42.84 ;
    END
  END o[475]
  PIN o[476]
    DIRECTION OUTPUT ;
    USE SIGNAL ;
    PORT
      LAYER M4 ;
        RECT  0 42.864 0.192 42.888 ;
    END
  END o[476]
  PIN o[477]
    DIRECTION OUTPUT ;
    USE SIGNAL ;
    PORT
      LAYER M4 ;
        RECT  0 42.912 0.192 42.936 ;
    END
  END o[477]
  PIN o[478]
    DIRECTION OUTPUT ;
    USE SIGNAL ;
    PORT
      LAYER M4 ;
        RECT  0 42.96 0.192 42.984 ;
    END
  END o[478]
  PIN o[479]
    DIRECTION OUTPUT ;
    USE SIGNAL ;
    PORT
      LAYER M4 ;
        RECT  0 43.008 0.192 43.032 ;
    END
  END o[479]
  PIN o[47]
    DIRECTION OUTPUT ;
    USE SIGNAL ;
    PORT
      LAYER M4 ;
        RECT  0 22.272 0.192 22.296 ;
    END
  END o[47]
  PIN o[480]
    DIRECTION OUTPUT ;
    USE SIGNAL ;
    PORT
      LAYER M4 ;
        RECT  0 43.056 0.192 43.08 ;
    END
  END o[480]
  PIN o[481]
    DIRECTION OUTPUT ;
    USE SIGNAL ;
    PORT
      LAYER M4 ;
        RECT  0 43.104 0.192 43.128 ;
    END
  END o[481]
  PIN o[482]
    DIRECTION OUTPUT ;
    USE SIGNAL ;
    PORT
      LAYER M4 ;
        RECT  0 43.152 0.192 43.176 ;
    END
  END o[482]
  PIN o[483]
    DIRECTION OUTPUT ;
    USE SIGNAL ;
    PORT
      LAYER M4 ;
        RECT  0 43.2 0.192 43.224 ;
    END
  END o[483]
  PIN o[484]
    DIRECTION OUTPUT ;
    USE SIGNAL ;
    PORT
      LAYER M4 ;
        RECT  0 43.248 0.192 43.272 ;
    END
  END o[484]
  PIN o[485]
    DIRECTION OUTPUT ;
    USE SIGNAL ;
    PORT
      LAYER M4 ;
        RECT  0 43.296 0.192 43.32 ;
    END
  END o[485]
  PIN o[486]
    DIRECTION OUTPUT ;
    USE SIGNAL ;
    PORT
      LAYER M4 ;
        RECT  0 43.344 0.192 43.368 ;
    END
  END o[486]
  PIN o[487]
    DIRECTION OUTPUT ;
    USE SIGNAL ;
    PORT
      LAYER M4 ;
        RECT  0 43.392 0.192 43.416 ;
    END
  END o[487]
  PIN o[488]
    DIRECTION OUTPUT ;
    USE SIGNAL ;
    PORT
      LAYER M4 ;
        RECT  0 43.44 0.192 43.464 ;
    END
  END o[488]
  PIN o[489]
    DIRECTION OUTPUT ;
    USE SIGNAL ;
    PORT
      LAYER M4 ;
        RECT  0 43.488 0.192 43.512 ;
    END
  END o[489]
  PIN o[48]
    DIRECTION OUTPUT ;
    USE SIGNAL ;
    PORT
      LAYER M4 ;
        RECT  0 22.32 0.192 22.344 ;
    END
  END o[48]
  PIN o[490]
    DIRECTION OUTPUT ;
    USE SIGNAL ;
    PORT
      LAYER M4 ;
        RECT  0 43.536 0.192 43.56 ;
    END
  END o[490]
  PIN o[491]
    DIRECTION OUTPUT ;
    USE SIGNAL ;
    PORT
      LAYER M4 ;
        RECT  0 43.584 0.192 43.608 ;
    END
  END o[491]
  PIN o[492]
    DIRECTION OUTPUT ;
    USE SIGNAL ;
    PORT
      LAYER M4 ;
        RECT  0 43.632 0.192 43.656 ;
    END
  END o[492]
  PIN o[493]
    DIRECTION OUTPUT ;
    USE SIGNAL ;
    PORT
      LAYER M4 ;
        RECT  0 43.68 0.192 43.704 ;
    END
  END o[493]
  PIN o[494]
    DIRECTION OUTPUT ;
    USE SIGNAL ;
    PORT
      LAYER M4 ;
        RECT  0 43.728 0.192 43.752 ;
    END
  END o[494]
  PIN o[495]
    DIRECTION OUTPUT ;
    USE SIGNAL ;
    PORT
      LAYER M4 ;
        RECT  0 43.776 0.192 43.8 ;
    END
  END o[495]
  PIN o[496]
    DIRECTION OUTPUT ;
    USE SIGNAL ;
    PORT
      LAYER M4 ;
        RECT  0 43.824 0.192 43.848 ;
    END
  END o[496]
  PIN o[497]
    DIRECTION OUTPUT ;
    USE SIGNAL ;
    PORT
      LAYER M4 ;
        RECT  0 43.872 0.192 43.896 ;
    END
  END o[497]
  PIN o[498]
    DIRECTION OUTPUT ;
    USE SIGNAL ;
    PORT
      LAYER M4 ;
        RECT  0 43.92 0.192 43.944 ;
    END
  END o[498]
  PIN o[499]
    DIRECTION OUTPUT ;
    USE SIGNAL ;
    PORT
      LAYER M4 ;
        RECT  0 43.968 0.192 43.992 ;
    END
  END o[499]
  PIN o[49]
    DIRECTION OUTPUT ;
    USE SIGNAL ;
    PORT
      LAYER M4 ;
        RECT  0 22.368 0.192 22.392 ;
    END
  END o[49]
  PIN o[4]
    DIRECTION OUTPUT ;
    USE SIGNAL ;
    PORT
      LAYER M4 ;
        RECT  0 20.208 0.192 20.232 ;
    END
  END o[4]
  PIN o[500]
    DIRECTION OUTPUT ;
    USE SIGNAL ;
    PORT
      LAYER M4 ;
        RECT  0 44.016 0.192 44.04 ;
    END
  END o[500]
  PIN o[501]
    DIRECTION OUTPUT ;
    USE SIGNAL ;
    PORT
      LAYER M4 ;
        RECT  0 44.064 0.192 44.088 ;
    END
  END o[501]
  PIN o[502]
    DIRECTION OUTPUT ;
    USE SIGNAL ;
    PORT
      LAYER M4 ;
        RECT  0 44.112 0.192 44.136 ;
    END
  END o[502]
  PIN o[503]
    DIRECTION OUTPUT ;
    USE SIGNAL ;
    PORT
      LAYER M4 ;
        RECT  0 44.16 0.192 44.184 ;
    END
  END o[503]
  PIN o[504]
    DIRECTION OUTPUT ;
    USE SIGNAL ;
    PORT
      LAYER M4 ;
        RECT  0 44.208 0.192 44.232 ;
    END
  END o[504]
  PIN o[505]
    DIRECTION OUTPUT ;
    USE SIGNAL ;
    PORT
      LAYER M4 ;
        RECT  0 44.256 0.192 44.28 ;
    END
  END o[505]
  PIN o[506]
    DIRECTION OUTPUT ;
    USE SIGNAL ;
    PORT
      LAYER M4 ;
        RECT  0 44.304 0.192 44.328 ;
    END
  END o[506]
  PIN o[507]
    DIRECTION OUTPUT ;
    USE SIGNAL ;
    PORT
      LAYER M4 ;
        RECT  0 44.352 0.192 44.376 ;
    END
  END o[507]
  PIN o[508]
    DIRECTION OUTPUT ;
    USE SIGNAL ;
    PORT
      LAYER M4 ;
        RECT  0 44.4 0.192 44.424 ;
    END
  END o[508]
  PIN o[509]
    DIRECTION OUTPUT ;
    USE SIGNAL ;
    PORT
      LAYER M4 ;
        RECT  0 44.448 0.192 44.472 ;
    END
  END o[509]
  PIN o[50]
    DIRECTION OUTPUT ;
    USE SIGNAL ;
    PORT
      LAYER M4 ;
        RECT  0 22.416 0.192 22.44 ;
    END
  END o[50]
  PIN o[510]
    DIRECTION OUTPUT ;
    USE SIGNAL ;
    PORT
      LAYER M4 ;
        RECT  0 44.496 0.192 44.52 ;
    END
  END o[510]
  PIN o[511]
    DIRECTION OUTPUT ;
    USE SIGNAL ;
    PORT
      LAYER M4 ;
        RECT  0 44.544 0.192 44.568 ;
    END
  END o[511]
  PIN o[512]
    DIRECTION OUTPUT ;
    USE SIGNAL ;
    PORT
      LAYER M4 ;
        RECT  0 44.592 0.192 44.616 ;
    END
  END o[512]
  PIN o[513]
    DIRECTION OUTPUT ;
    USE SIGNAL ;
    PORT
      LAYER M4 ;
        RECT  0 44.64 0.192 44.664 ;
    END
  END o[513]
  PIN o[514]
    DIRECTION OUTPUT ;
    USE SIGNAL ;
    PORT
      LAYER M4 ;
        RECT  0 44.688 0.192 44.712 ;
    END
  END o[514]
  PIN o[51]
    DIRECTION OUTPUT ;
    USE SIGNAL ;
    PORT
      LAYER M4 ;
        RECT  0 22.464 0.192 22.488 ;
    END
  END o[51]
  PIN o[52]
    DIRECTION OUTPUT ;
    USE SIGNAL ;
    PORT
      LAYER M4 ;
        RECT  0 22.512 0.192 22.536 ;
    END
  END o[52]
  PIN o[53]
    DIRECTION OUTPUT ;
    USE SIGNAL ;
    PORT
      LAYER M4 ;
        RECT  0 22.56 0.192 22.584 ;
    END
  END o[53]
  PIN o[54]
    DIRECTION OUTPUT ;
    USE SIGNAL ;
    PORT
      LAYER M4 ;
        RECT  0 22.608 0.192 22.632 ;
    END
  END o[54]
  PIN o[55]
    DIRECTION OUTPUT ;
    USE SIGNAL ;
    PORT
      LAYER M4 ;
        RECT  0 22.656 0.192 22.68 ;
    END
  END o[55]
  PIN o[56]
    DIRECTION OUTPUT ;
    USE SIGNAL ;
    PORT
      LAYER M4 ;
        RECT  0 22.704 0.192 22.728 ;
    END
  END o[56]
  PIN o[57]
    DIRECTION OUTPUT ;
    USE SIGNAL ;
    PORT
      LAYER M4 ;
        RECT  0 22.752 0.192 22.776 ;
    END
  END o[57]
  PIN o[58]
    DIRECTION OUTPUT ;
    USE SIGNAL ;
    PORT
      LAYER M4 ;
        RECT  0 22.8 0.192 22.824 ;
    END
  END o[58]
  PIN o[59]
    DIRECTION OUTPUT ;
    USE SIGNAL ;
    PORT
      LAYER M4 ;
        RECT  0 22.848 0.192 22.872 ;
    END
  END o[59]
  PIN o[5]
    DIRECTION OUTPUT ;
    USE SIGNAL ;
    PORT
      LAYER M4 ;
        RECT  0 20.256 0.192 20.28 ;
    END
  END o[5]
  PIN o[60]
    DIRECTION OUTPUT ;
    USE SIGNAL ;
    PORT
      LAYER M4 ;
        RECT  0 22.896 0.192 22.92 ;
    END
  END o[60]
  PIN o[61]
    DIRECTION OUTPUT ;
    USE SIGNAL ;
    PORT
      LAYER M4 ;
        RECT  0 22.944 0.192 22.968 ;
    END
  END o[61]
  PIN o[62]
    DIRECTION OUTPUT ;
    USE SIGNAL ;
    PORT
      LAYER M4 ;
        RECT  0 22.992 0.192 23.016 ;
    END
  END o[62]
  PIN o[63]
    DIRECTION OUTPUT ;
    USE SIGNAL ;
    PORT
      LAYER M4 ;
        RECT  0 23.04 0.192 23.064 ;
    END
  END o[63]
  PIN o[64]
    DIRECTION OUTPUT ;
    USE SIGNAL ;
    PORT
      LAYER M4 ;
        RECT  0 23.088 0.192 23.112 ;
    END
  END o[64]
  PIN o[65]
    DIRECTION OUTPUT ;
    USE SIGNAL ;
    PORT
      LAYER M4 ;
        RECT  0 23.136 0.192 23.16 ;
    END
  END o[65]
  PIN o[66]
    DIRECTION OUTPUT ;
    USE SIGNAL ;
    PORT
      LAYER M4 ;
        RECT  0 23.184 0.192 23.208 ;
    END
  END o[66]
  PIN o[67]
    DIRECTION OUTPUT ;
    USE SIGNAL ;
    PORT
      LAYER M4 ;
        RECT  0 23.232 0.192 23.256 ;
    END
  END o[67]
  PIN o[68]
    DIRECTION OUTPUT ;
    USE SIGNAL ;
    PORT
      LAYER M4 ;
        RECT  0 23.28 0.192 23.304 ;
    END
  END o[68]
  PIN o[69]
    DIRECTION OUTPUT ;
    USE SIGNAL ;
    PORT
      LAYER M4 ;
        RECT  0 23.328 0.192 23.352 ;
    END
  END o[69]
  PIN o[6]
    DIRECTION OUTPUT ;
    USE SIGNAL ;
    PORT
      LAYER M4 ;
        RECT  0 20.304 0.192 20.328 ;
    END
  END o[6]
  PIN o[70]
    DIRECTION OUTPUT ;
    USE SIGNAL ;
    PORT
      LAYER M4 ;
        RECT  0 23.376 0.192 23.4 ;
    END
  END o[70]
  PIN o[71]
    DIRECTION OUTPUT ;
    USE SIGNAL ;
    PORT
      LAYER M4 ;
        RECT  0 23.424 0.192 23.448 ;
    END
  END o[71]
  PIN o[72]
    DIRECTION OUTPUT ;
    USE SIGNAL ;
    PORT
      LAYER M4 ;
        RECT  0 23.472 0.192 23.496 ;
    END
  END o[72]
  PIN o[73]
    DIRECTION OUTPUT ;
    USE SIGNAL ;
    PORT
      LAYER M4 ;
        RECT  0 23.52 0.192 23.544 ;
    END
  END o[73]
  PIN o[74]
    DIRECTION OUTPUT ;
    USE SIGNAL ;
    PORT
      LAYER M4 ;
        RECT  0 23.568 0.192 23.592 ;
    END
  END o[74]
  PIN o[75]
    DIRECTION OUTPUT ;
    USE SIGNAL ;
    PORT
      LAYER M4 ;
        RECT  0 23.616 0.192 23.64 ;
    END
  END o[75]
  PIN o[76]
    DIRECTION OUTPUT ;
    USE SIGNAL ;
    PORT
      LAYER M4 ;
        RECT  0 23.664 0.192 23.688 ;
    END
  END o[76]
  PIN o[77]
    DIRECTION OUTPUT ;
    USE SIGNAL ;
    PORT
      LAYER M4 ;
        RECT  0 23.712 0.192 23.736 ;
    END
  END o[77]
  PIN o[78]
    DIRECTION OUTPUT ;
    USE SIGNAL ;
    PORT
      LAYER M4 ;
        RECT  0 23.76 0.192 23.784 ;
    END
  END o[78]
  PIN o[79]
    DIRECTION OUTPUT ;
    USE SIGNAL ;
    PORT
      LAYER M4 ;
        RECT  0 23.808 0.192 23.832 ;
    END
  END o[79]
  PIN o[7]
    DIRECTION OUTPUT ;
    USE SIGNAL ;
    PORT
      LAYER M4 ;
        RECT  0 20.352 0.192 20.376 ;
    END
  END o[7]
  PIN o[80]
    DIRECTION OUTPUT ;
    USE SIGNAL ;
    PORT
      LAYER M4 ;
        RECT  0 23.856 0.192 23.88 ;
    END
  END o[80]
  PIN o[81]
    DIRECTION OUTPUT ;
    USE SIGNAL ;
    PORT
      LAYER M4 ;
        RECT  0 23.904 0.192 23.928 ;
    END
  END o[81]
  PIN o[82]
    DIRECTION OUTPUT ;
    USE SIGNAL ;
    PORT
      LAYER M4 ;
        RECT  0 23.952 0.192 23.976 ;
    END
  END o[82]
  PIN o[83]
    DIRECTION OUTPUT ;
    USE SIGNAL ;
    PORT
      LAYER M4 ;
        RECT  0 24 0.192 24.024 ;
    END
  END o[83]
  PIN o[84]
    DIRECTION OUTPUT ;
    USE SIGNAL ;
    PORT
      LAYER M4 ;
        RECT  0 24.048 0.192 24.072 ;
    END
  END o[84]
  PIN o[85]
    DIRECTION OUTPUT ;
    USE SIGNAL ;
    PORT
      LAYER M4 ;
        RECT  0 24.096 0.192 24.12 ;
    END
  END o[85]
  PIN o[86]
    DIRECTION OUTPUT ;
    USE SIGNAL ;
    PORT
      LAYER M4 ;
        RECT  0 24.144 0.192 24.168 ;
    END
  END o[86]
  PIN o[87]
    DIRECTION OUTPUT ;
    USE SIGNAL ;
    PORT
      LAYER M4 ;
        RECT  0 24.192 0.192 24.216 ;
    END
  END o[87]
  PIN o[88]
    DIRECTION OUTPUT ;
    USE SIGNAL ;
    PORT
      LAYER M4 ;
        RECT  0 24.24 0.192 24.264 ;
    END
  END o[88]
  PIN o[89]
    DIRECTION OUTPUT ;
    USE SIGNAL ;
    PORT
      LAYER M4 ;
        RECT  0 24.288 0.192 24.312 ;
    END
  END o[89]
  PIN o[8]
    DIRECTION OUTPUT ;
    USE SIGNAL ;
    PORT
      LAYER M4 ;
        RECT  0 20.4 0.192 20.424 ;
    END
  END o[8]
  PIN o[90]
    DIRECTION OUTPUT ;
    USE SIGNAL ;
    PORT
      LAYER M4 ;
        RECT  0 24.336 0.192 24.36 ;
    END
  END o[90]
  PIN o[91]
    DIRECTION OUTPUT ;
    USE SIGNAL ;
    PORT
      LAYER M4 ;
        RECT  0 24.384 0.192 24.408 ;
    END
  END o[91]
  PIN o[92]
    DIRECTION OUTPUT ;
    USE SIGNAL ;
    PORT
      LAYER M4 ;
        RECT  0 24.432 0.192 24.456 ;
    END
  END o[92]
  PIN o[93]
    DIRECTION OUTPUT ;
    USE SIGNAL ;
    PORT
      LAYER M4 ;
        RECT  0 24.48 0.192 24.504 ;
    END
  END o[93]
  PIN o[94]
    DIRECTION OUTPUT ;
    USE SIGNAL ;
    PORT
      LAYER M4 ;
        RECT  0 24.528 0.192 24.552 ;
    END
  END o[94]
  PIN o[95]
    DIRECTION OUTPUT ;
    USE SIGNAL ;
    PORT
      LAYER M4 ;
        RECT  0 24.576 0.192 24.6 ;
    END
  END o[95]
  PIN o[96]
    DIRECTION OUTPUT ;
    USE SIGNAL ;
    PORT
      LAYER M4 ;
        RECT  0 24.624 0.192 24.648 ;
    END
  END o[96]
  PIN o[97]
    DIRECTION OUTPUT ;
    USE SIGNAL ;
    PORT
      LAYER M4 ;
        RECT  0 24.672 0.192 24.696 ;
    END
  END o[97]
  PIN o[98]
    DIRECTION OUTPUT ;
    USE SIGNAL ;
    PORT
      LAYER M4 ;
        RECT  0 24.72 0.192 24.744 ;
    END
  END o[98]
  PIN o[99]
    DIRECTION OUTPUT ;
    USE SIGNAL ;
    PORT
      LAYER M4 ;
        RECT  0 24.768 0.192 24.792 ;
    END
  END o[99]
  PIN o[9]
    DIRECTION OUTPUT ;
    USE SIGNAL ;
    PORT
      LAYER M4 ;
        RECT  0 20.448 0.192 20.472 ;
    END
  END o[9]
  PIN rs[0]
    DIRECTION INPUT ;
    USE SIGNAL ;
    PORT
      LAYER M5 ;
        RECT  31.584 0 31.608 0.192 ;
    END
  END rs[0]
  PIN VDD
    DIRECTION INOUT ;
    USE POWER ;
    PORT
      LAYER M5 ;
        RECT  83.592 2.151 83.712 62.393 ;
        RECT  78.192 2.151 78.312 62.393 ;
        RECT  72.792 2.151 72.912 62.393 ;
        RECT  67.392 2.151 67.512 62.393 ;
        RECT  61.992 2.151 62.112 62.393 ;
        RECT  56.592 2.151 56.712 62.393 ;
        RECT  51.192 2.151 51.312 62.393 ;
        RECT  45.792 2.151 45.912 62.393 ;
        RECT  40.392 2.151 40.512 62.393 ;
        RECT  34.992 2.151 35.112 62.393 ;
        RECT  29.592 2.151 29.712 62.393 ;
        RECT  24.192 2.151 24.312 62.393 ;
        RECT  18.792 2.151 18.912 62.393 ;
        RECT  13.392 2.151 13.512 62.393 ;
        RECT  7.992 2.151 8.112 62.393 ;
        RECT  2.592 2.151 2.712 62.393 ;
    END
  END VDD
  PIN VSS
    DIRECTION INOUT ;
    USE GROUND ;
    PORT
      LAYER M5 ;
        RECT  83.4 2.137 83.52 62.379 ;
        RECT  78 2.137 78.12 62.379 ;
        RECT  72.6 2.137 72.72 62.379 ;
        RECT  67.2 2.137 67.32 62.379 ;
        RECT  61.8 2.137 61.92 62.379 ;
        RECT  56.4 2.137 56.52 62.379 ;
        RECT  51 2.137 51.12 62.379 ;
        RECT  45.6 2.137 45.72 62.379 ;
        RECT  40.2 2.137 40.32 62.379 ;
        RECT  34.8 2.137 34.92 62.379 ;
        RECT  29.4 2.137 29.52 62.379 ;
        RECT  24 2.137 24.12 62.379 ;
        RECT  18.6 2.137 18.72 62.379 ;
        RECT  13.2 2.137 13.32 62.379 ;
        RECT  7.8 2.137 7.92 62.379 ;
        RECT  2.4 2.137 2.52 62.379 ;
    END
  END VSS
  # OT_OBS_CLOSED layer=M5 d_um=1.536 added=1042
  OBS
    LAYER RVTN ;
     RECT  2.16 2.16 84.24 2.295 ;
     RECT  2.16 2.565 84.24 2.835 ;
     RECT  2.16 3.105 84.24 3.375 ;
     RECT  2.16 3.645 84.24 3.915 ;
     RECT  2.16 4.185 84.24 4.455 ;
     RECT  2.16 4.725 84.24 4.995 ;
     RECT  2.16 5.265 84.24 5.535 ;
     RECT  2.16 5.805 84.24 6.075 ;
     RECT  2.16 6.345 84.24 6.615 ;
     RECT  2.16 6.885 84.24 7.155 ;
     RECT  2.16 7.425 84.24 7.695 ;
     RECT  2.16 7.965 84.24 8.235 ;
     RECT  2.16 8.505 84.24 8.775 ;
     RECT  2.16 9.045 84.24 9.315 ;
     RECT  2.16 9.585 84.24 9.855 ;
     RECT  2.16 10.125 84.24 10.395 ;
     RECT  2.16 10.665 84.24 10.935 ;
     RECT  2.16 11.205 84.24 11.475 ;
     RECT  2.16 11.745 84.24 12.015 ;
     RECT  2.16 12.285 84.24 12.555 ;
     RECT  2.16 12.825 84.24 13.095 ;
     RECT  2.16 13.365 84.24 13.635 ;
     RECT  2.16 13.905 84.24 14.175 ;
     RECT  2.16 14.445 84.24 14.715 ;
     RECT  2.16 14.985 84.24 15.255 ;
     RECT  2.16 15.525 84.24 15.795 ;
     RECT  2.16 16.065 84.24 16.335 ;
     RECT  2.16 16.605 84.24 16.875 ;
     RECT  2.16 17.145 84.24 17.415 ;
     RECT  2.16 17.685 84.24 17.955 ;
     RECT  2.16 18.225 84.24 18.495 ;
     RECT  2.16 18.765 84.24 19.035 ;
     RECT  2.16 19.305 84.24 19.575 ;
     RECT  2.16 19.845 84.24 20.115 ;
     RECT  2.16 20.385 84.24 20.655 ;
     RECT  2.16 20.925 84.24 21.195 ;
     RECT  2.16 21.465 84.24 21.735 ;
     RECT  2.16 22.005 84.24 22.275 ;
     RECT  2.16 22.545 84.24 22.815 ;
     RECT  2.16 23.085 84.24 23.355 ;
     RECT  2.16 23.625 84.24 23.895 ;
     RECT  2.16 24.165 84.24 24.435 ;
     RECT  2.16 24.705 84.24 24.975 ;
     RECT  2.16 25.245 84.24 25.515 ;
     RECT  2.16 25.785 84.24 26.055 ;
     RECT  2.16 26.325 84.24 26.595 ;
     RECT  2.16 26.865 84.24 27.135 ;
     RECT  2.16 27.405 84.24 27.675 ;
     RECT  2.16 27.945 84.24 28.215 ;
     RECT  2.16 28.485 84.24 28.755 ;
     RECT  2.16 29.025 84.24 29.295 ;
     RECT  2.16 29.565 84.24 29.835 ;
     RECT  2.16 30.105 84.24 30.375 ;
     RECT  2.16 30.645 84.24 30.915 ;
     RECT  2.16 31.185 84.24 31.455 ;
     RECT  2.16 31.725 84.24 31.995 ;
     RECT  2.16 32.265 84.24 32.535 ;
     RECT  2.16 32.805 84.24 33.075 ;
     RECT  2.16 33.345 84.24 33.615 ;
     RECT  2.16 33.885 84.24 34.155 ;
     RECT  2.16 34.425 84.24 34.695 ;
     RECT  2.16 34.965 84.24 35.235 ;
     RECT  2.16 35.505 84.24 35.775 ;
     RECT  2.16 36.045 84.24 36.315 ;
     RECT  2.16 36.585 84.24 36.855 ;
     RECT  2.16 37.125 84.24 37.395 ;
     RECT  2.16 37.665 84.24 37.935 ;
     RECT  2.16 38.205 84.24 38.475 ;
     RECT  2.16 38.745 84.24 39.015 ;
     RECT  2.16 39.285 84.24 39.555 ;
     RECT  2.16 39.825 84.24 40.095 ;
     RECT  2.16 40.365 84.24 40.635 ;
     RECT  2.16 40.905 84.24 41.175 ;
     RECT  2.16 41.445 84.24 41.715 ;
     RECT  2.16 41.985 84.24 42.255 ;
     RECT  2.16 42.525 84.24 42.795 ;
     RECT  2.16 43.065 84.24 43.335 ;
     RECT  2.16 43.605 84.24 43.875 ;
     RECT  2.16 44.145 84.24 44.415 ;
     RECT  2.16 44.685 84.24 44.955 ;
     RECT  2.16 45.225 84.24 45.495 ;
     RECT  2.16 45.765 84.24 46.035 ;
     RECT  2.16 46.305 84.24 46.575 ;
     RECT  2.16 46.845 84.24 47.115 ;
     RECT  2.16 47.385 84.24 47.655 ;
     RECT  2.16 47.925 84.24 48.195 ;
     RECT  2.16 48.465 84.24 48.735 ;
     RECT  2.16 49.005 84.24 49.275 ;
     RECT  2.16 49.545 84.24 49.815 ;
     RECT  2.16 50.085 84.24 50.355 ;
     RECT  2.16 50.625 84.24 50.895 ;
     RECT  2.16 51.165 84.24 51.435 ;
     RECT  2.16 51.705 84.24 51.975 ;
     RECT  2.16 52.245 84.24 52.515 ;
     RECT  2.16 52.785 84.24 53.055 ;
     RECT  2.16 53.325 84.24 53.595 ;
     RECT  2.16 53.865 84.24 54.135 ;
     RECT  2.16 54.405 84.24 54.675 ;
     RECT  2.16 54.945 84.24 55.215 ;
     RECT  2.16 55.485 84.24 55.755 ;
     RECT  2.16 56.025 84.24 56.295 ;
     RECT  2.16 56.565 84.24 56.835 ;
     RECT  2.16 57.105 84.24 57.375 ;
     RECT  2.16 57.645 84.24 57.915 ;
     RECT  2.16 58.185 84.24 58.455 ;
     RECT  2.16 58.725 84.24 58.995 ;
     RECT  2.16 59.265 84.24 59.535 ;
     RECT  2.16 59.805 84.24 60.075 ;
     RECT  2.16 60.345 84.24 60.615 ;
     RECT  2.16 60.885 84.24 61.155 ;
     RECT  2.16 61.425 84.24 61.695 ;
     RECT  2.16 61.965 84.24 62.235 ;
    LAYER RVTP ;
     RECT  2.16 2.295 84.24 2.565 ;
     RECT  2.16 2.835 84.24 3.105 ;
     RECT  2.16 3.375 84.24 3.645 ;
     RECT  2.16 3.915 84.24 4.185 ;
     RECT  2.16 4.455 84.24 4.725 ;
     RECT  2.16 4.995 84.24 5.265 ;
     RECT  2.16 5.535 84.24 5.805 ;
     RECT  2.16 6.075 84.24 6.345 ;
     RECT  2.16 6.615 84.24 6.885 ;
     RECT  2.16 7.155 84.24 7.425 ;
     RECT  2.16 7.695 84.24 7.965 ;
     RECT  2.16 8.235 84.24 8.505 ;
     RECT  2.16 8.775 84.24 9.045 ;
     RECT  2.16 9.315 84.24 9.585 ;
     RECT  2.16 9.855 84.24 10.125 ;
     RECT  2.16 10.395 84.24 10.665 ;
     RECT  2.16 10.935 84.24 11.205 ;
     RECT  2.16 11.475 84.24 11.745 ;
     RECT  2.16 12.015 84.24 12.285 ;
     RECT  2.16 12.555 84.24 12.825 ;
     RECT  2.16 13.095 84.24 13.365 ;
     RECT  2.16 13.635 84.24 13.905 ;
     RECT  2.16 14.175 84.24 14.445 ;
     RECT  2.16 14.715 84.24 14.985 ;
     RECT  2.16 15.255 84.24 15.525 ;
     RECT  2.16 15.795 84.24 16.065 ;
     RECT  2.16 16.335 84.24 16.605 ;
     RECT  2.16 16.875 84.24 17.145 ;
     RECT  2.16 17.415 84.24 17.685 ;
     RECT  2.16 17.955 84.24 18.225 ;
     RECT  2.16 18.495 84.24 18.765 ;
     RECT  2.16 19.035 84.24 19.305 ;
     RECT  2.16 19.575 84.24 19.845 ;
     RECT  2.16 20.115 84.24 20.385 ;
     RECT  2.16 20.655 84.24 20.925 ;
     RECT  2.16 21.195 84.24 21.465 ;
     RECT  2.16 21.735 84.24 22.005 ;
     RECT  2.16 22.275 84.24 22.545 ;
     RECT  2.16 22.815 84.24 23.085 ;
     RECT  2.16 23.355 84.24 23.625 ;
     RECT  2.16 23.895 84.24 24.165 ;
     RECT  2.16 24.435 84.24 24.705 ;
     RECT  2.16 24.975 84.24 25.245 ;
     RECT  2.16 25.515 84.24 25.785 ;
     RECT  2.16 26.055 84.24 26.325 ;
     RECT  2.16 26.595 84.24 26.865 ;
     RECT  2.16 27.135 84.24 27.405 ;
     RECT  2.16 27.675 84.24 27.945 ;
     RECT  2.16 28.215 84.24 28.485 ;
     RECT  2.16 28.755 84.24 29.025 ;
     RECT  2.16 29.295 84.24 29.565 ;
     RECT  2.16 29.835 84.24 30.105 ;
     RECT  2.16 30.375 84.24 30.645 ;
     RECT  2.16 30.915 84.24 31.185 ;
     RECT  2.16 31.455 84.24 31.725 ;
     RECT  2.16 31.995 84.24 32.265 ;
     RECT  2.16 32.535 84.24 32.805 ;
     RECT  2.16 33.075 84.24 33.345 ;
     RECT  2.16 33.615 84.24 33.885 ;
     RECT  2.16 34.155 84.24 34.425 ;
     RECT  2.16 34.695 84.24 34.965 ;
     RECT  2.16 35.235 84.24 35.505 ;
     RECT  2.16 35.775 84.24 36.045 ;
     RECT  2.16 36.315 84.24 36.585 ;
     RECT  2.16 36.855 84.24 37.125 ;
     RECT  2.16 37.395 84.24 37.665 ;
     RECT  2.16 37.935 84.24 38.205 ;
     RECT  2.16 38.475 84.24 38.745 ;
     RECT  2.16 39.015 84.24 39.285 ;
     RECT  2.16 39.555 84.24 39.825 ;
     RECT  2.16 40.095 84.24 40.365 ;
     RECT  2.16 40.635 84.24 40.905 ;
     RECT  2.16 41.175 84.24 41.445 ;
     RECT  2.16 41.715 84.24 41.985 ;
     RECT  2.16 42.255 84.24 42.525 ;
     RECT  2.16 42.795 84.24 43.065 ;
     RECT  2.16 43.335 84.24 43.605 ;
     RECT  2.16 43.875 84.24 44.145 ;
     RECT  2.16 44.415 84.24 44.685 ;
     RECT  2.16 44.955 84.24 45.225 ;
     RECT  2.16 45.495 84.24 45.765 ;
     RECT  2.16 46.035 84.24 46.305 ;
     RECT  2.16 46.575 84.24 46.845 ;
     RECT  2.16 47.115 84.24 47.385 ;
     RECT  2.16 47.655 84.24 47.925 ;
     RECT  2.16 48.195 84.24 48.465 ;
     RECT  2.16 48.735 84.24 49.005 ;
     RECT  2.16 49.275 84.24 49.545 ;
     RECT  2.16 49.815 84.24 50.085 ;
     RECT  2.16 50.355 84.24 50.625 ;
     RECT  2.16 50.895 84.24 51.165 ;
     RECT  2.16 51.435 84.24 51.705 ;
     RECT  2.16 51.975 84.24 52.245 ;
     RECT  2.16 52.515 84.24 52.785 ;
     RECT  2.16 53.055 84.24 53.325 ;
     RECT  2.16 53.595 84.24 53.865 ;
     RECT  2.16 54.135 84.24 54.405 ;
     RECT  2.16 54.675 84.24 54.945 ;
     RECT  2.16 55.215 84.24 55.485 ;
     RECT  2.16 55.755 84.24 56.025 ;
     RECT  2.16 56.295 84.24 56.565 ;
     RECT  2.16 56.835 84.24 57.105 ;
     RECT  2.16 57.375 84.24 57.645 ;
     RECT  2.16 57.915 84.24 58.185 ;
     RECT  2.16 58.455 84.24 58.725 ;
     RECT  2.16 58.995 84.24 59.265 ;
     RECT  2.16 59.535 84.24 59.805 ;
     RECT  2.16 60.075 84.24 60.345 ;
     RECT  2.16 60.615 84.24 60.885 ;
     RECT  2.16 61.155 84.24 61.425 ;
     RECT  2.16 61.695 84.24 61.965 ;
     RECT  2.16 62.235 84.24 62.37 ;
    LAYER M1 ;
     RECT  2.16 2.151 84.24 62.379 ;
    LAYER M2 ;
     RECT  0.031 22.788 0.067 22.806 ;
     RECT  0.031 43.65 0.067 43.668 ;
     RECT  0.067 19.854 0.103 19.872 ;
     RECT  0.067 22.788 0.103 22.959 ;
     RECT  0.067 43.65 0.103 44.874 ;
     RECT  0.031 18.81 0.131 18.828 ;
     RECT  0.103 19.854 0.139 20.106 ;
     RECT  0.103 23.796 0.139 23.814 ;
     RECT  0.103 43.506 0.139 44.874 ;
     RECT  0.139 19.854 0.175 20.259 ;
     RECT  0.103 21.096 0.175 21.114 ;
     RECT  0.103 22.086 0.175 22.959 ;
     RECT  0.139 23.796 0.175 24.39 ;
     RECT  0.139 25.182 0.175 25.2 ;
     RECT  0.067 41.184 0.175 41.202 ;
     RECT  0.175 22.086 0.211 24.39 ;
     RECT  0.175 25.182 0.211 25.389 ;
     RECT  0.175 26.676 0.211 26.694 ;
     RECT  0.175 40.986 0.211 41.202 ;
     RECT  0.175 41.994 0.211 42.714 ;
     RECT  0.139 43.506 0.211 44.946 ;
     RECT  0.103 50.364 0.211 50.382 ;
     RECT  0.175 19.854 0.247 21.114 ;
     RECT  0.211 22.086 0.247 25.389 ;
     RECT  0.211 26.676 0.247 27.054 ;
     RECT  0.175 27.918 0.247 27.936 ;
     RECT  0.211 30.69 0.247 30.708 ;
     RECT  0.211 33.471 0.247 33.489 ;
     RECT  0.211 35.784 0.247 35.964 ;
     RECT  0.211 39.636 0.247 39.654 ;
     RECT  0.211 40.986 0.247 44.946 ;
     RECT  0.247 19.854 0.283 25.389 ;
     RECT  0.247 26.64 0.283 27.054 ;
     RECT  0.247 27.801 0.283 27.936 ;
     RECT  0.211 38.826 0.283 38.844 ;
     RECT  0.247 39.636 0.283 44.946 ;
     RECT  0.283 19.854 0.319 27.936 ;
     RECT  0.247 29.034 0.319 30.708 ;
     RECT  0.247 31.734 0.319 31.752 ;
     RECT  0.247 32.616 0.319 33.759 ;
     RECT  0.247 35.316 0.319 36.999 ;
     RECT  0.283 38.826 0.319 44.946 ;
     RECT  0.283 15.336 0.355 15.354 ;
     RECT  0.319 19.854 0.355 28.278 ;
     RECT  0.319 29.034 0.355 34.524 ;
     RECT  0.319 35.316 0.355 37.314 ;
     RECT  0.319 38.061 0.355 44.946 ;
     RECT  0.355 19.854 0.391 44.946 ;
     RECT  0.391 19.62 0.455 44.946 ;
     RECT  0.455 19.62 0.491 31.752 ;
     RECT  0.355 15.336 0.499 15.624 ;
     RECT  0.211 50.364 0.527 50.724 ;
     RECT  0.491 19.62 0.599 31.554 ;
     RECT  0.455 32.508 0.599 44.946 ;
     RECT  0.599 19.62 0.607 27.774 ;
     RECT  0.571 46.701 0.671 46.719 ;
     RECT  0.607 19.278 0.707 27.774 ;
     RECT  0.599 38.061 0.707 44.946 ;
     RECT  0.499 15.264 0.715 15.624 ;
     RECT  0.103 16.506 0.715 16.524 ;
     RECT  0.599 32.508 0.779 37.314 ;
     RECT  0.707 38.376 0.779 44.946 ;
     RECT  0.599 28.566 0.815 31.554 ;
     RECT  0.779 32.508 0.815 36.504 ;
     RECT  0.283 47.7 0.823 47.718 ;
     RECT  0.815 32.508 0.851 36.342 ;
     RECT  0.427 13.914 0.859 13.932 ;
     RECT  0.823 12.366 0.895 12.384 ;
     RECT  0.319 45.891 0.895 45.909 ;
     RECT  0.851 32.508 0.923 36.189 ;
     RECT  0.859 13.644 0.967 13.932 ;
     RECT  0.815 28.656 0.995 31.554 ;
     RECT  0.895 45.846 1.003 45.909 ;
     RECT  1.003 45.774 1.075 45.909 ;
     RECT  0.779 38.79 1.111 44.946 ;
     RECT  1.075 45.774 1.111 46.062 ;
     RECT  0.995 28.656 1.139 29.934 ;
     RECT  0.859 52.056 1.147 52.074 ;
     RECT  0.823 55.836 1.147 55.854 ;
     RECT  1.147 51.984 1.175 52.074 ;
     RECT  0.923 32.508 1.283 35.874 ;
     RECT  1.075 19.044 1.327 19.062 ;
     RECT  0.779 37.296 1.435 37.314 ;
     RECT  0.715 15.264 1.543 16.524 ;
     RECT  0.527 50.364 1.579 50.382 ;
     RECT  0.823 47.016 1.687 47.718 ;
     RECT  0.175 48.744 1.687 48.762 ;
     RECT  1.147 55.764 1.687 55.854 ;
     RECT  1.579 50.292 1.723 50.382 ;
     RECT  1.687 47.016 1.759 48.762 ;
     RECT  1.111 38.79 1.795 46.062 ;
     RECT  0.211 53.136 1.831 53.154 ;
     RECT  1.795 38.79 1.867 46.134 ;
     RECT  1.759 47.016 1.867 48.798 ;
     RECT  0.895 11.826 1.903 12.384 ;
     RECT  0.967 13.644 1.903 14.004 ;
     RECT  1.327 18.774 1.903 19.062 ;
     RECT  1.543 15.066 1.975 16.524 ;
     RECT  1.867 38.79 1.975 49.302 ;
     RECT  1.723 50.292 1.975 51.084 ;
     RECT  1.687 55.764 2.011 55.944 ;
     RECT  1.975 15.066 2.047 16.974 ;
     RECT  1.147 9.666 2.083 9.684 ;
     RECT  2.047 10.908 2.083 10.926 ;
     RECT  1.903 11.826 2.083 14.004 ;
     RECT  1.435 37.296 2.083 38.034 ;
     RECT  2.083 9.666 2.155 9.774 ;
     RECT  1.283 32.616 2.155 35.874 ;
     RECT  2.083 36.864 2.155 38.034 ;
     RECT  2.119 8.316 2.16 8.334 ;
     RECT  2.155 9.666 2.16 10.044 ;
     RECT  2.083 10.908 2.16 14.004 ;
     RECT  2.047 15.066 2.16 17.172 ;
     RECT  1.903 18.198 2.16 19.062 ;
     RECT  0.707 19.854 2.16 27.774 ;
     RECT  1.139 29.574 2.16 29.934 ;
     RECT  0.995 30.924 2.16 31.554 ;
     RECT  2.155 32.616 2.16 38.034 ;
     RECT  1.975 38.79 2.16 51.084 ;
     RECT  1.175 51.984 2.16 52.002 ;
     RECT  1.831 52.758 2.16 53.154 ;
     RECT  2.155 54.648 2.16 54.666 ;
     RECT  2.011 55.764 2.16 56.484 ;
     RECT  2.16 2.151 30.775 62.379 ;
     RECT  30.775 2.106 31.127 62.379 ;
     RECT  31.127 2.151 33.475 62.379 ;
     RECT  33.475 2.106 34.115 62.379 ;
     RECT  34.115 2.151 78.187 62.379 ;
     RECT  78.187 2.106 78.539 62.379 ;
     RECT  78.539 2.151 84.24 62.379 ;
     RECT  84.24 12.528 84.335 13.968 ;
     RECT  84.24 15.228 84.335 50.346 ;
     RECT  84.335 15.228 84.515 49.302 ;
     RECT  84.335 13.644 84.659 13.968 ;
     RECT  84.515 15.228 84.695 18.216 ;
     RECT  84.515 19.008 84.695 49.302 ;
     RECT  84.695 15.3 84.731 18.216 ;
     RECT  84.731 16.11 84.911 18.216 ;
     RECT  84.695 19.008 84.983 49.266 ;
     RECT  84.983 19.008 85.055 34.416 ;
     RECT  84.335 12.528 85.199 12.546 ;
     RECT  84.659 13.644 85.235 13.662 ;
     RECT  84.335 50.328 85.235 50.346 ;
     RECT  84.983 35.244 85.307 49.266 ;
     RECT  85.307 35.244 85.415 49.104 ;
     RECT  85.415 35.244 85.487 48.492 ;
     RECT  85.055 19.008 85.523 34.074 ;
     RECT  85.487 35.244 85.523 48.024 ;
     RECT  85.523 25.911 85.559 26.856 ;
     RECT  85.523 27.648 85.559 34.074 ;
     RECT  85.523 35.514 85.559 48.024 ;
     RECT  85.559 25.911 85.595 26.388 ;
     RECT  85.559 27.648 85.595 30.096 ;
     RECT  85.559 30.852 85.595 33.264 ;
     RECT  85.559 35.55 85.595 37.926 ;
     RECT  85.559 40.14 85.595 48.024 ;
     RECT  85.523 19.008 85.631 25.164 ;
     RECT  85.595 25.911 85.631 26.352 ;
     RECT  85.595 35.55 85.631 37.764 ;
     RECT  85.559 38.826 85.631 38.844 ;
     RECT  85.595 40.14 85.631 46.368 ;
     RECT  85.631 23.706 85.667 25.164 ;
     RECT  85.631 26.028 85.667 26.352 ;
     RECT  85.595 27.648 85.667 29.826 ;
     RECT  85.595 30.852 85.667 32.328 ;
     RECT  85.595 33.246 85.667 33.264 ;
     RECT  85.667 23.706 85.703 23.814 ;
     RECT  85.667 24.75 85.703 25.164 ;
     RECT  85.667 26.028 85.703 26.199 ;
     RECT  85.667 27.882 85.703 28.629 ;
     RECT  85.667 29.466 85.703 29.484 ;
     RECT  85.667 31.194 85.703 31.716 ;
     RECT  85.631 35.856 85.703 35.874 ;
     RECT  85.631 36.936 85.703 37.764 ;
     RECT  85.631 42.03 85.703 46.368 ;
     RECT  85.631 19.008 85.739 22.959 ;
     RECT  85.703 26.028 85.739 26.046 ;
     RECT  85.703 36.936 85.739 36.954 ;
     RECT  85.703 28.494 85.775 28.629 ;
     RECT  85.739 19.746 85.811 22.959 ;
     RECT  85.775 28.611 85.811 28.629 ;
     RECT  85.703 42.966 85.811 46.296 ;
     RECT  85.703 23.706 85.847 23.724 ;
     RECT  85.703 37.746 85.847 37.764 ;
     RECT  85.811 42.966 85.847 42.984 ;
     RECT  85.811 44.001 85.847 46.296 ;
     RECT  85.811 20.556 85.883 22.959 ;
     RECT  85.847 45.036 85.883 46.296 ;
     RECT  85.847 44.001 85.919 44.019 ;
     RECT  85.811 19.746 85.955 19.764 ;
     RECT  85.631 40.14 85.955 41.274 ;
     RECT  85.883 45.738 85.955 46.296 ;
     RECT  84.911 16.11 86.027 18.054 ;
     RECT  85.955 45.81 86.027 46.296 ;
     RECT  85.703 42.03 86.063 42.048 ;
     RECT  86.027 16.11 86.099 17.514 ;
     RECT  85.955 40.68 86.099 41.274 ;
     RECT  86.099 16.65 86.135 17.514 ;
     RECT  85.963 18.81 86.135 18.909 ;
     RECT  85.703 31.194 86.135 31.212 ;
     RECT  86.099 40.68 86.135 41.238 ;
     RECT  85.595 47.124 86.135 48.024 ;
     RECT  86.135 17.082 86.171 17.514 ;
     RECT  85.883 20.556 86.171 20.844 ;
     RECT  85.883 22.05 86.171 22.959 ;
     RECT  86.135 41.076 86.171 41.238 ;
     RECT  86.135 47.124 86.171 47.448 ;
     RECT  86.171 17.082 86.207 17.1 ;
     RECT  86.171 20.628 86.207 20.646 ;
     RECT  86.171 22.05 86.207 22.914 ;
     RECT  86.171 41.076 86.207 41.166 ;
     RECT  86.171 47.124 86.207 47.142 ;
     RECT  84.731 15.3 86.243 15.318 ;
     RECT  86.135 18.891 86.243 18.909 ;
     RECT  86.207 22.05 86.243 22.068 ;
     RECT  85.703 25.146 86.243 25.164 ;
     RECT  86.207 41.076 86.243 41.094 ;
     RECT  86.027 46.278 86.243 46.296 ;
    LAYER M3 ;
     RECT  31.608 1.723 31.626 2.101 ;
     RECT  33.48 2.101 34.11 2.143 ;
     RECT  78.192 2.101 78.534 2.143 ;
     RECT  18.615 2.143 18.705 2.191 ;
     RECT  61.815 2.143 61.905 2.191 ;
     RECT  24.015 2.143 24.105 2.227 ;
     RECT  61.815 2.191 62.838 2.227 ;
     RECT  67.215 2.143 67.305 2.227 ;
     RECT  73.872 2.203 73.89 2.227 ;
     RECT  18.396 2.191 18.705 2.251 ;
     RECT  27.252 2.191 27.27 2.251 ;
     RECT  28.332 2.191 28.35 2.251 ;
     RECT  29.415 2.143 29.505 2.251 ;
     RECT  33.48 2.143 34.905 2.251 ;
     RECT  45.615 2.143 45.705 2.251 ;
     RECT  56.415 2.143 56.505 2.251 ;
     RECT  71.856 2.191 71.874 2.251 ;
     RECT  10.512 2.227 10.53 2.263 ;
     RECT  12.132 2.227 12.15 2.263 ;
     RECT  16.092 2.191 16.11 2.263 ;
     RECT  24.948 2.227 24.966 2.263 ;
     RECT  33.48 2.251 35.55 2.263 ;
     RECT  45.615 2.251 46.17 2.263 ;
     RECT  49.392 2.191 49.41 2.263 ;
     RECT  54.036 2.227 54.054 2.263 ;
     RECT  59.256 2.227 59.274 2.263 ;
     RECT  73.8 2.227 73.89 2.263 ;
     RECT  54.036 2.263 54.486 2.285 ;
     RECT  51.015 2.143 51.105 2.299 ;
     RECT  52.308 2.227 52.326 2.299 ;
     RECT  13.215 2.143 13.305 2.335 ;
     RECT  15.48 2.263 16.11 2.335 ;
     RECT  18 2.251 18.705 2.335 ;
     RECT  24.948 2.263 25.362 2.335 ;
     RECT  61.815 2.227 63.342 2.335 ;
     RECT  64.836 2.203 64.854 2.335 ;
     RECT  71.46 2.251 71.874 2.335 ;
     RECT  58.464 2.227 58.482 2.347 ;
     RECT  59.256 2.263 59.598 2.347 ;
     RECT  10.512 2.263 10.926 2.371 ;
     RECT  12.132 2.263 12.294 2.371 ;
     RECT  13.215 2.335 13.662 2.371 ;
     RECT  15.12 2.335 16.182 2.371 ;
     RECT  18 2.335 19.098 2.371 ;
     RECT  19.836 2.251 19.854 2.371 ;
     RECT  20.664 2.227 20.682 2.371 ;
     RECT  22.428 2.251 23.13 2.371 ;
     RECT  24.015 2.227 24.138 2.371 ;
     RECT  36.756 2.227 36.774 2.371 ;
     RECT  38.376 2.335 38.394 2.371 ;
     RECT  44.136 2.251 44.154 2.371 ;
     RECT  45.615 2.263 46.746 2.371 ;
     RECT  51.015 2.299 52.326 2.371 ;
     RECT  54.288 2.285 54.486 2.371 ;
     RECT  56.124 2.251 56.505 2.371 ;
     RECT  60.84 2.299 60.858 2.371 ;
     RECT  64.62 2.335 64.854 2.371 ;
     RECT  66.78 2.227 67.305 2.371 ;
     RECT  69.516 2.335 69.534 2.371 ;
     RECT  71.352 2.335 71.874 2.371 ;
     RECT  72.615 2.143 72.705 2.371 ;
     RECT  73.8 2.263 74.142 2.371 ;
     RECT  75.42 2.203 75.438 2.371 ;
     RECT  77.256 2.251 77.274 2.371 ;
     RECT  78.015 2.143 78.534 2.371 ;
     RECT  2.415 2.143 2.505 2.413 ;
     RECT  7.815 2.143 7.905 2.413 ;
     RECT  22.428 2.371 24.138 2.413 ;
     RECT  24.948 2.335 25.506 2.413 ;
     RECT  40.215 2.143 40.305 2.413 ;
     RECT  71.352 2.371 72.705 2.413 ;
     RECT  83.415 2.143 83.505 2.413 ;
     RECT  14.832 2.371 16.398 2.461 ;
     RECT  18 2.371 20.682 2.461 ;
     RECT  32.904 2.263 35.55 2.461 ;
     RECT  36.756 2.371 36.918 2.461 ;
     RECT  37.692 2.371 38.394 2.461 ;
     RECT  41.688 2.335 41.994 2.461 ;
     RECT  43.488 2.371 44.37 2.461 ;
     RECT  45.108 2.371 46.818 2.461 ;
     RECT  48.312 2.371 48.33 2.461 ;
     RECT  49.212 2.263 49.41 2.461 ;
     RECT  51.015 2.371 53.082 2.461 ;
     RECT  54.288 2.371 54.81 2.461 ;
     RECT  56.124 2.371 57.114 2.461 ;
     RECT  60.552 2.371 60.93 2.461 ;
     RECT  61.815 2.335 63.414 2.461 ;
     RECT  64.62 2.371 65.682 2.461 ;
     RECT  71.352 2.413 72.897 2.461 ;
     RECT  10.512 2.371 13.662 2.489 ;
     RECT  51.015 2.461 53.226 2.491 ;
     RECT  69.516 2.371 69.606 2.491 ;
     RECT  17.424 2.461 21.186 2.497 ;
     RECT  41.616 2.461 41.994 2.497 ;
     RECT  50.184 2.227 50.202 2.497 ;
     RECT  60.336 2.461 60.93 2.497 ;
     RECT  71.352 2.461 73.026 2.497 ;
     RECT  73.8 2.371 76.302 2.497 ;
     RECT  56.124 2.461 57.222 2.533 ;
     RECT  58.464 2.347 59.598 2.533 ;
     RECT  17.352 2.497 21.186 2.569 ;
     RECT  22.428 2.413 25.506 2.569 ;
     RECT  40.215 2.413 40.497 2.569 ;
     RECT  43.488 2.461 46.818 2.569 ;
     RECT  48.312 2.461 49.41 2.569 ;
     RECT  56.124 2.533 59.598 2.569 ;
     RECT  60.336 2.497 61.038 2.569 ;
     RECT  10.512 2.489 13.59 2.605 ;
     RECT  14.652 2.461 16.398 2.605 ;
     RECT  9.144 2.605 9.162 2.641 ;
     RECT  10.368 2.605 13.59 2.641 ;
     RECT  17.136 2.569 21.186 2.641 ;
     RECT  22.428 2.569 25.578 2.641 ;
     RECT  27.252 2.251 30.006 2.641 ;
     RECT  39.24 2.497 39.258 2.641 ;
     RECT  40.032 2.569 40.497 2.641 ;
     RECT  41.616 2.497 42.498 2.641 ;
     RECT  43.452 2.569 46.818 2.641 ;
     RECT  48.096 2.569 49.41 2.641 ;
     RECT  50.148 2.497 50.202 2.641 ;
     RECT  56.124 2.569 61.038 2.641 ;
     RECT  61.815 2.461 65.682 2.641 ;
     RECT  66.78 2.371 67.806 2.641 ;
     RECT  69.372 2.491 69.606 2.641 ;
     RECT  70.452 2.491 70.47 2.641 ;
     RECT  71.352 2.497 76.302 2.641 ;
     RECT  80.748 2.569 80.766 2.641 ;
     RECT  39.168 2.641 39.258 2.731 ;
     RECT  40.032 2.641 42.498 2.731 ;
     RECT  54.288 2.461 54.918 2.731 ;
     RECT  69.372 2.641 76.302 2.731 ;
     RECT  77.256 2.371 79.326 2.731 ;
     RECT  80.748 2.641 80.946 2.731 ;
     RECT  39.168 2.731 42.498 2.767 ;
     RECT  43.272 2.641 46.926 2.767 ;
     RECT  48.024 2.641 50.202 2.767 ;
     RECT  80.136 2.731 80.946 2.767 ;
     RECT  54.288 2.731 54.99 2.779 ;
     RECT  22.428 2.641 30.006 2.803 ;
     RECT  30.78 2.101 31.626 2.803 ;
     RECT  54.288 2.779 55.062 2.803 ;
     RECT  56.124 2.641 65.682 2.803 ;
     RECT  7.815 2.413 8.097 2.839 ;
     RECT  9.144 2.641 13.59 2.839 ;
     RECT  47.88 2.767 50.202 2.839 ;
     RECT  50.976 2.491 53.226 2.839 ;
     RECT  14.508 2.605 16.398 2.875 ;
     RECT  17.136 2.641 21.546 2.875 ;
     RECT  22.428 2.803 31.626 2.875 ;
     RECT  32.904 2.461 38.394 2.911 ;
     RECT  39.168 2.767 46.926 2.911 ;
     RECT  47.88 2.839 53.226 2.911 ;
     RECT  66.6 2.641 67.914 2.911 ;
     RECT  69.372 2.731 76.374 2.911 ;
     RECT  77.22 2.731 79.326 2.911 ;
     RECT  80.136 2.767 81.054 2.911 ;
     RECT  14.508 2.875 21.546 3.001 ;
     RECT  22.32 2.875 32.13 3.001 ;
     RECT  32.904 2.911 46.926 3.001 ;
     RECT  66.492 2.911 67.914 3.001 ;
     RECT  68.652 2.911 76.374 3.001 ;
     RECT  7.815 2.839 13.59 3.029 ;
     RECT  14.508 3.001 46.926 3.029 ;
     RECT  47.7 2.911 53.226 3.073 ;
     RECT  66.492 3.001 76.374 3.145 ;
     RECT  77.22 2.911 79.362 3.145 ;
     RECT  54.288 2.803 65.682 3.181 ;
     RECT  66.492 3.145 79.362 3.181 ;
     RECT  80.136 2.911 81.63 3.181 ;
     RECT  47.484 3.073 53.226 3.259 ;
     RECT  54.288 3.181 82.098 3.271 ;
     RECT  54.072 3.271 82.098 3.379 ;
     RECT  8.964 3.029 13.59 3.403 ;
     RECT  14.508 3.029 46.71 3.403 ;
     RECT  8.964 3.403 46.71 3.407 ;
     RECT  54.072 3.379 82.674 3.541 ;
     RECT  83.415 2.413 83.697 3.541 ;
     RECT  47.484 3.259 53.334 3.649 ;
     RECT  54.072 3.541 83.697 3.649 ;
     RECT  47.484 3.649 83.697 3.677 ;
     RECT  7.815 3.029 8.097 3.721 ;
     RECT  55.692 3.677 83.697 3.725 ;
     RECT  7.56 3.721 8.097 3.811 ;
     RECT  2.415 2.413 2.697 3.835 ;
     RECT  32.364 3.407 46.71 3.839 ;
     RECT  47.484 3.677 54.954 3.839 ;
     RECT  2.415 3.835 3.006 3.847 ;
     RECT  55.692 3.725 75.906 3.875 ;
     RECT  7.56 3.811 8.154 3.883 ;
     RECT  76.716 3.725 83.697 3.917 ;
     RECT  7.56 3.883 8.19 3.919 ;
     RECT  38.592 3.839 46.71 3.931 ;
     RECT  47.484 3.839 51.462 3.931 ;
     RECT  82.98 3.917 83.697 3.965 ;
     RECT  83.016 3.965 83.697 3.983 ;
     RECT  7.488 3.919 8.19 3.991 ;
     RECT  8.964 3.407 31.59 3.991 ;
     RECT  2.415 3.847 3.33 4.117 ;
     RECT  4.14 3.931 4.158 4.117 ;
     RECT  7.416 3.991 31.59 4.117 ;
     RECT  52.2 3.839 54.954 4.181 ;
     RECT  7.056 4.117 31.59 4.189 ;
     RECT  32.364 3.839 37.638 4.189 ;
     RECT  2.415 4.117 4.158 4.225 ;
     RECT  7.056 4.189 37.638 4.267 ;
     RECT  52.2 4.181 53.154 4.379 ;
     RECT  2.34 4.225 4.158 4.531 ;
     RECT  5.112 4.261 5.13 4.531 ;
     RECT  53.928 4.181 54.954 4.531 ;
     RECT  55.692 3.875 58.95 4.531 ;
     RECT  38.592 3.931 51.462 4.541 ;
     RECT  39.024 4.541 51.462 4.621 ;
     RECT  52.2 4.379 53.082 4.621 ;
     RECT  2.34 4.531 5.13 4.651 ;
     RECT  53.928 4.531 58.95 4.651 ;
     RECT  59.796 3.875 75.906 4.651 ;
     RECT  83.232 3.983 83.697 4.729 ;
     RECT  2.34 4.651 5.346 4.801 ;
     RECT  6.444 4.267 37.638 4.801 ;
     RECT  53.928 4.651 75.906 4.829 ;
     RECT  2.34 4.801 5.49 4.927 ;
     RECT  6.264 4.801 37.638 4.927 ;
     RECT  2.34 4.927 37.638 5.035 ;
     RECT  54.072 4.829 75.906 5.071 ;
     RECT  76.716 3.917 82.242 5.071 ;
     RECT  39.024 4.621 53.082 5.161 ;
     RECT  54.072 5.071 82.242 5.225 ;
     RECT  2.34 5.035 38.178 5.269 ;
     RECT  39.024 5.161 53.19 5.269 ;
     RECT  54.288 5.225 82.242 5.305 ;
     RECT  54.288 5.305 82.278 5.341 ;
     RECT  2.34 5.269 53.19 5.431 ;
     RECT  54.288 5.341 82.458 5.467 ;
     RECT  83.232 4.729 83.79 5.467 ;
     RECT  2.304 5.431 53.334 5.549 ;
     RECT  54.288 5.467 83.79 5.645 ;
     RECT  2.34 5.549 53.334 5.873 ;
     RECT  2.376 5.873 53.334 5.881 ;
     RECT  2.376 5.881 53.442 5.971 ;
     RECT  54.288 5.645 82.494 5.971 ;
     RECT  2.376 5.971 82.494 6.269 ;
     RECT  83.34 5.645 83.79 6.385 ;
     RECT  83.304 6.385 83.79 6.539 ;
     RECT  83.34 6.539 83.79 6.611 ;
     RECT  2.376 6.269 82.278 6.619 ;
     RECT  2.34 6.619 82.278 7.123 ;
     RECT  83.415 6.611 83.79 7.151 ;
     RECT  2.34 7.123 82.386 7.501 ;
     RECT  2.34 7.501 82.422 7.627 ;
     RECT  2.304 7.627 82.422 7.655 ;
     RECT  83.415 7.151 83.754 7.969 ;
     RECT  75.528 7.655 82.422 8.041 ;
     RECT  83.34 7.969 83.754 8.041 ;
     RECT  75.528 8.041 83.754 8.239 ;
     RECT  2.304 7.655 74.646 8.311 ;
     RECT  75.528 8.239 83.79 8.509 ;
     RECT  75.492 8.509 83.79 8.573 ;
     RECT  2.124 8.311 74.646 8.587 ;
     RECT  75.492 8.573 82.638 8.669 ;
     RECT  2.124 8.587 74.682 8.851 ;
     RECT  2.124 8.851 74.718 9.391 ;
     RECT  75.492 8.669 82.566 9.391 ;
     RECT  83.415 8.573 83.79 9.661 ;
     RECT  2.124 9.391 82.602 9.751 ;
     RECT  83.415 9.661 83.826 9.835 ;
     RECT  83.376 9.835 83.826 9.923 ;
     RECT  2.088 9.751 82.602 9.931 ;
     RECT  83.376 9.923 83.79 9.931 ;
     RECT  1.152 9.661 1.17 10.253 ;
     RECT  2.088 9.931 83.79 10.391 ;
     RECT  2.088 10.391 83.754 10.903 ;
     RECT  2.052 10.903 83.754 11.371 ;
     RECT  2.052 11.371 83.898 11.813 ;
     RECT  0.9 11.821 0.918 11.911 ;
     RECT  2.052 11.813 47.106 11.911 ;
     RECT  47.88 11.813 83.898 11.939 ;
     RECT  50.436 11.939 83.898 11.975 ;
     RECT  60.66 11.975 83.898 12.325 ;
     RECT  0.9 11.911 47.106 12.361 ;
     RECT  60.66 12.325 84.114 12.487 ;
     RECT  50.436 11.975 59.886 12.721 ;
     RECT  60.66 12.487 84.222 12.721 ;
     RECT  50.436 12.721 84.222 12.821 ;
     RECT  0.828 12.361 47.106 12.865 ;
     RECT  47.88 11.939 49.662 12.865 ;
     RECT  50.472 12.821 84.222 13.135 ;
     RECT  85.176 12.523 85.194 13.639 ;
     RECT  0.828 12.865 49.662 13.837 ;
     RECT  0.828 13.837 49.734 13.909 ;
     RECT  50.472 13.135 84.33 13.909 ;
     RECT  0.432 13.909 84.33 13.945 ;
     RECT  85.176 13.639 85.23 13.945 ;
     RECT  0.432 13.945 85.23 15.331 ;
     RECT  0.288 15.331 85.23 15.341 ;
     RECT  86.22 15.295 86.238 16.105 ;
     RECT  0.288 15.341 53.802 16.363 ;
     RECT  0.288 16.363 53.838 16.501 ;
     RECT  0.108 16.501 53.838 16.537 ;
     RECT  54.684 15.341 85.23 16.537 ;
     RECT  0.108 16.537 85.23 16.573 ;
     RECT  86.076 16.105 86.238 17.383 ;
     RECT  0.108 16.573 85.302 17.995 ;
     RECT  86.04 17.383 86.238 17.995 ;
     RECT  0.108 17.995 86.238 18.805 ;
     RECT  0.036 18.805 86.238 18.914 ;
     RECT  0.036 18.914 86.202 20.651 ;
     RECT  0.036 20.651 86.166 22.045 ;
     RECT  0.036 22.045 86.238 22.589 ;
     RECT  0.036 22.589 59.67 22.811 ;
     RECT  0.072 22.811 59.67 22.964 ;
     RECT  0.108 22.964 59.67 23.309 ;
     RECT  30.744 23.309 59.67 23.521 ;
     RECT  60.444 22.589 86.238 23.521 ;
     RECT  0.108 23.309 30.006 23.819 ;
     RECT  0.144 23.819 30.006 24.205 ;
     RECT  30.744 23.521 86.238 24.205 ;
     RECT  0.144 24.205 86.238 25.169 ;
     RECT  0.144 25.169 86.13 25.205 ;
     RECT  0.18 25.205 86.13 25.394 ;
     RECT  0.216 25.394 86.13 25.421 ;
     RECT  0.216 25.421 85.734 26.671 ;
     RECT  0.18 26.671 85.734 27.437 ;
     RECT  0.18 27.437 37.494 27.941 ;
     RECT  0.216 27.941 37.494 28.139 ;
     RECT  38.304 27.437 85.698 28.255 ;
     RECT  16.812 28.139 37.494 28.291 ;
     RECT  38.268 28.255 85.698 28.291 ;
     RECT  0.216 28.139 16.038 28.349 ;
     RECT  16.812 28.291 85.698 28.489 ;
     RECT  16.812 28.489 85.77 28.606 ;
     RECT  16.812 28.606 85.806 28.679 ;
     RECT  17.784 28.679 85.806 28.715 ;
     RECT  16.812 28.679 17.046 28.891 ;
     RECT  0.216 28.349 1.278 28.925 ;
     RECT  2.232 28.349 16.038 29.065 ;
     RECT  16.776 28.891 17.046 29.065 ;
     RECT  20.736 28.715 85.806 29.261 ;
     RECT  17.784 28.715 19.926 29.461 ;
     RECT  20.736 29.261 85.77 29.461 ;
     RECT  17.784 29.461 85.77 29.501 ;
     RECT  2.232 29.065 17.046 29.731 ;
     RECT  17.784 29.501 85.698 29.731 ;
     RECT  0.216 28.925 1.242 30.077 ;
     RECT  2.232 29.731 85.698 30.137 ;
     RECT  2.232 30.137 70.794 30.221 ;
     RECT  0.216 30.077 1.134 30.317 ;
     RECT  2.232 30.221 24.822 30.569 ;
     RECT  2.232 30.569 15.534 30.605 ;
     RECT  0.216 30.317 0.558 30.713 ;
     RECT  16.524 30.569 24.822 30.713 ;
     RECT  71.712 30.137 85.698 30.763 ;
     RECT  2.232 30.605 15.498 30.797 ;
     RECT  25.668 30.221 70.794 30.859 ;
     RECT  71.712 30.763 85.986 30.859 ;
     RECT  71.712 30.859 86.13 30.991 ;
     RECT  18.036 30.713 24.822 31.109 ;
     RECT  25.668 30.859 70.866 31.133 ;
     RECT  66.024 31.133 70.866 31.147 ;
     RECT  0.324 30.713 0.558 31.153 ;
     RECT  18.108 31.109 24.822 31.189 ;
     RECT  25.668 31.133 65.25 31.189 ;
     RECT  71.676 30.991 86.13 31.217 ;
     RECT  71.676 31.217 85.698 31.325 ;
     RECT  66.024 31.147 70.938 31.339 ;
     RECT  71.676 31.325 73.242 31.339 ;
     RECT  18.108 31.189 65.25 31.379 ;
     RECT  18.108 31.379 23.13 31.415 ;
     RECT  0.324 31.153 0.63 31.423 ;
     RECT  16.524 30.713 17.19 31.423 ;
     RECT  0.324 31.423 0.666 31.435 ;
     RECT  2.304 30.797 15.498 31.483 ;
     RECT  16.344 31.423 17.19 31.483 ;
     RECT  25.02 31.379 65.25 31.523 ;
     RECT  0.252 31.435 0.666 31.757 ;
     RECT  65.232 31.523 65.25 31.891 ;
     RECT  66.024 31.339 73.242 31.891 ;
     RECT  65.232 31.891 73.242 31.919 ;
     RECT  18.216 31.415 23.13 31.949 ;
     RECT  18.216 31.949 20.682 31.997 ;
     RECT  65.304 31.919 73.242 31.997 ;
     RECT  2.304 31.483 17.19 32.071 ;
     RECT  2.304 32.071 17.334 32.107 ;
     RECT  24.015 31.379 24.297 32.107 ;
     RECT  25.02 31.523 64.062 32.107 ;
     RECT  18.216 31.997 20.538 32.197 ;
     RECT  0.324 31.757 0.666 32.203 ;
     RECT  1.728 32.107 17.334 32.203 ;
     RECT  65.448 31.997 73.242 32.233 ;
     RECT  73.98 31.325 85.698 32.233 ;
     RECT  18.18 32.197 20.538 32.341 ;
     RECT  21.456 31.949 23.13 32.431 ;
     RECT  24.015 32.107 64.062 32.431 ;
     RECT  0.324 32.203 17.334 32.443 ;
     RECT  18.072 32.341 20.538 32.443 ;
     RECT  0.324 32.443 20.538 32.459 ;
     RECT  0.324 32.459 17.118 32.495 ;
     RECT  17.856 32.459 20.538 32.495 ;
     RECT  0.324 32.495 15.462 32.539 ;
     RECT  65.448 32.233 85.698 32.573 ;
     RECT  18.18 32.495 20.538 32.737 ;
     RECT  18.18 32.737 20.718 32.809 ;
     RECT  21.456 32.431 64.062 32.809 ;
     RECT  65.448 32.573 85.662 32.809 ;
     RECT  0.252 32.539 15.462 32.837 ;
     RECT  18.18 32.809 64.062 32.971 ;
     RECT  65.124 32.809 85.662 32.971 ;
     RECT  18.18 32.971 85.662 32.999 ;
     RECT  18.18 32.999 74.466 33.053 ;
     RECT  64.944 33.053 74.466 33.071 ;
     RECT  70.668 33.071 74.466 33.107 ;
     RECT  18.18 33.053 64.026 33.149 ;
     RECT  18.18 33.149 21.258 33.269 ;
     RECT  75.42 32.999 85.662 33.269 ;
     RECT  18.18 33.269 21.114 33.349 ;
     RECT  17.64 33.349 21.114 33.421 ;
     RECT  0.252 32.837 15.426 33.466 ;
     RECT  16.344 32.495 16.506 33.511 ;
     RECT  22.104 33.149 64.026 33.539 ;
     RECT  16.272 33.511 16.506 33.583 ;
     RECT  17.352 33.421 21.114 33.583 ;
     RECT  0.216 33.466 15.426 33.629 ;
     RECT  0.252 33.629 15.426 33.643 ;
     RECT  16.272 33.583 21.114 33.643 ;
     RECT  0.252 33.643 21.114 33.764 ;
     RECT  75.42 33.269 85.554 33.781 ;
     RECT  25.668 33.539 64.026 33.835 ;
     RECT  64.944 33.071 69.822 33.835 ;
     RECT  0.324 33.764 21.114 33.881 ;
     RECT  25.668 33.835 69.822 33.925 ;
     RECT  70.668 33.107 74.43 33.925 ;
     RECT  75.204 33.781 85.554 33.925 ;
     RECT  2.232 33.881 21.114 34.051 ;
     RECT  22.104 33.539 24.93 34.051 ;
     RECT  25.668 33.925 85.554 34.349 ;
     RECT  65.556 34.349 85.554 34.411 ;
     RECT  2.232 34.051 24.93 34.457 ;
     RECT  0.324 33.881 1.458 34.529 ;
     RECT  15.84 34.457 24.93 34.529 ;
     RECT  15.84 34.529 17.298 34.619 ;
     RECT  18.144 34.529 24.93 34.627 ;
     RECT  25.668 34.349 64.71 34.627 ;
     RECT  65.556 34.411 86.13 34.691 ;
     RECT  0.36 34.529 1.458 34.735 ;
     RECT  2.232 34.457 15.102 34.735 ;
     RECT  0.36 34.735 15.102 35.275 ;
     RECT  18.144 34.627 64.71 35.311 ;
     RECT  65.556 34.691 74.574 35.357 ;
     RECT  15.84 34.619 17.19 35.401 ;
     RECT  18.108 35.311 64.746 35.401 ;
     RECT  65.556 35.357 65.682 35.401 ;
     RECT  0.252 35.275 15.102 35.509 ;
     RECT  15.84 35.401 65.682 35.509 ;
     RECT  0.252 35.509 65.682 35.707 ;
     RECT  66.6 35.357 74.574 35.851 ;
     RECT  75.636 34.691 86.13 35.899 ;
     RECT  0.216 35.707 65.682 35.969 ;
     RECT  0.252 35.969 65.682 36.085 ;
     RECT  66.6 35.851 74.646 36.085 ;
     RECT  0.252 36.085 74.646 36.121 ;
     RECT  75.6 35.899 86.13 36.121 ;
     RECT  0.252 36.121 86.13 37.049 ;
     RECT  0.252 37.049 76.122 37.579 ;
     RECT  0.216 37.579 76.122 37.661 ;
     RECT  0.216 37.661 76.014 38.237 ;
     RECT  76.968 37.049 86.13 38.641 ;
     RECT  76.788 38.641 86.13 38.683 ;
     RECT  0.216 38.237 75.798 38.983 ;
     RECT  76.572 38.683 86.13 38.983 ;
     RECT  0.216 38.983 86.13 40.981 ;
     RECT  0.18 40.981 86.13 41.071 ;
     RECT  0.18 41.071 86.238 41.179 ;
     RECT  0.072 41.179 86.238 43.645 ;
     RECT  0.036 43.645 86.238 44.909 ;
     RECT  0.072 44.909 86.238 46.301 ;
     RECT  0.072 46.301 86.202 47.147 ;
     RECT  0.072 47.147 86.166 47.453 ;
     RECT  0.072 47.453 86.13 47.933 ;
     RECT  0.108 47.933 86.13 48.029 ;
     RECT  0.108 48.029 85.482 48.497 ;
     RECT  0.108 48.497 85.41 49.109 ;
     RECT  0.108 49.109 85.302 49.271 ;
     RECT  0.108 49.271 85.23 49.307 ;
     RECT  0.108 49.307 84.33 49.739 ;
     RECT  85.212 49.307 85.23 50.351 ;
     RECT  0.108 49.739 47.898 50.387 ;
     RECT  0.216 50.387 47.898 50.665 ;
     RECT  48.636 49.739 84.186 50.665 ;
     RECT  0.216 50.665 84.186 50.717 ;
     RECT  1.692 50.717 84.186 50.729 ;
     RECT  1.692 50.729 84.15 51.899 ;
     RECT  0.216 50.717 0.882 51.979 ;
     RECT  1.692 51.899 84.078 51.979 ;
     RECT  0.216 51.979 84.078 52.079 ;
     RECT  1.692 52.079 84.078 52.241 ;
     RECT  80.064 52.241 84.042 52.313 ;
     RECT  1.692 52.241 79.326 52.987 ;
     RECT  80.064 52.313 83.934 52.987 ;
     RECT  0.216 52.079 0.846 53.159 ;
     RECT  1.692 52.987 83.934 53.249 ;
     RECT  1.692 53.249 83.826 53.555 ;
     RECT  65.952 53.555 83.826 53.789 ;
     RECT  1.692 53.555 65.214 53.897 ;
     RECT  12.312 53.897 65.214 54.331 ;
     RECT  65.952 53.789 83.754 54.331 ;
     RECT  12.312 54.331 83.754 54.599 ;
     RECT  0.828 53.159 0.846 54.715 ;
     RECT  1.692 53.897 11.574 54.715 ;
     RECT  43.452 54.599 83.754 54.751 ;
     RECT  0.828 54.715 11.574 54.985 ;
     RECT  12.312 54.599 42.714 54.985 ;
     RECT  43.452 54.751 83.79 55.565 ;
     RECT  43.452 55.565 81.882 55.679 ;
     RECT  0.828 54.985 42.714 55.787 ;
     RECT  1.692 55.787 42.714 55.795 ;
     RECT  43.452 55.679 49.374 55.795 ;
     RECT  82.692 55.565 83.79 55.831 ;
     RECT  0.828 55.787 0.846 55.859 ;
     RECT  1.692 55.795 49.374 55.949 ;
     RECT  82.692 55.831 83.826 56.021 ;
     RECT  2.016 55.949 49.374 56.057 ;
     RECT  50.148 55.679 81.882 56.219 ;
     RECT  52.308 56.219 81.882 56.327 ;
     RECT  52.344 56.327 81.882 56.371 ;
     RECT  82.692 56.021 83.79 56.371 ;
     RECT  11.988 56.057 49.374 56.429 ;
     RECT  50.148 56.219 51.57 56.443 ;
     RECT  17.208 56.429 49.374 56.461 ;
     RECT  50.112 56.443 51.57 56.461 ;
     RECT  2.016 56.057 11.214 56.489 ;
     RECT  2.232 56.489 11.214 56.759 ;
     RECT  17.208 56.461 51.57 56.765 ;
     RECT  2.268 56.759 11.214 56.911 ;
     RECT  11.988 56.429 16.47 56.911 ;
     RECT  50.292 56.765 51.57 57.001 ;
     RECT  52.344 56.371 83.79 57.029 ;
     RECT  2.268 56.911 16.47 57.065 ;
     RECT  50.292 57.001 51.606 57.067 ;
     RECT  52.344 57.029 82.386 57.067 ;
     RECT  83.232 57.029 83.79 57.181 ;
     RECT  12.168 57.065 16.47 57.259 ;
     RECT  17.208 56.765 49.446 57.259 ;
     RECT  2.268 57.065 11.358 57.335 ;
     RECT  2.34 57.335 11.358 57.443 ;
     RECT  83.232 57.181 83.826 57.443 ;
     RECT  12.168 57.259 49.446 57.685 ;
     RECT  50.292 57.067 82.386 57.685 ;
     RECT  2.376 57.443 11.358 57.787 ;
     RECT  12.168 57.685 82.386 57.787 ;
     RECT  2.376 57.787 82.386 57.983 ;
     RECT  10.836 57.983 82.386 58.157 ;
     RECT  10.908 58.157 82.386 58.387 ;
     RECT  83.232 57.443 83.754 58.387 ;
     RECT  10.908 58.387 83.754 58.495 ;
     RECT  10.908 58.495 83.826 58.649 ;
     RECT  2.376 57.983 10.098 58.801 ;
     RECT  2.34 58.801 10.098 58.927 ;
     RECT  10.908 58.649 83.754 58.927 ;
     RECT  2.34 58.927 83.754 58.991 ;
     RECT  2.34 58.991 45.897 59.189 ;
     RECT  46.728 58.991 83.754 59.225 ;
     RECT  2.34 59.189 44.046 59.275 ;
     RECT  2.304 59.275 44.046 59.405 ;
     RECT  2.304 59.405 44.01 59.459 ;
     RECT  2.415 59.459 44.01 59.531 ;
     RECT  2.415 59.531 3.438 59.567 ;
     RECT  2.415 59.567 2.862 59.603 ;
     RECT  4.788 59.531 44.01 59.999 ;
     RECT  46.836 59.225 82.35 60.079 ;
     RECT  83.34 59.225 83.754 60.079 ;
     RECT  5.328 59.999 44.01 60.151 ;
     RECT  45.036 59.189 45.897 60.151 ;
     RECT  5.328 60.151 45.897 60.277 ;
     RECT  46.836 60.079 83.754 60.277 ;
     RECT  5.328 60.277 83.754 60.305 ;
     RECT  5.328 60.305 5.346 60.377 ;
     RECT  59.4 60.305 83.754 60.385 ;
     RECT  59.4 60.385 83.898 60.413 ;
     RECT  59.688 60.413 83.898 60.509 ;
     RECT  6.264 60.305 35.19 60.539 ;
     RECT  77.256 60.509 83.898 60.539 ;
     RECT  35.928 60.305 58.662 60.575 ;
     RECT  77.256 60.539 80.982 60.611 ;
     RECT  82.08 60.539 83.898 60.647 ;
     RECT  82.08 60.647 83.697 60.683 ;
     RECT  6.408 60.539 35.19 60.809 ;
     RECT  82.08 60.683 82.494 60.809 ;
     RECT  83.304 60.683 83.697 60.809 ;
     RECT  82.224 60.809 82.35 60.953 ;
     RECT  59.688 60.509 76.266 60.989 ;
     RECT  59.688 60.989 73.674 61.037 ;
     RECT  6.948 60.809 35.19 61.051 ;
     RECT  35.928 60.575 58.59 61.051 ;
     RECT  59.688 61.037 62.55 61.079 ;
     RECT  82.224 60.953 82.314 61.079 ;
     RECT  6.948 61.051 58.59 61.115 ;
     RECT  82.224 61.079 82.242 61.115 ;
     RECT  6.948 61.115 56.826 61.151 ;
     RECT  43.92 61.151 56.826 61.187 ;
     RECT  6.948 61.151 43.182 61.223 ;
     RECT  57.6 61.115 58.59 61.223 ;
     RECT  59.688 61.079 62.097 61.231 ;
     RECT  77.256 60.611 80.658 61.231 ;
     RECT  7.344 61.223 43.182 61.349 ;
     RECT  77.112 61.231 80.658 61.349 ;
     RECT  43.92 61.187 56.697 61.385 ;
     RECT  63.396 61.037 73.674 61.385 ;
     RECT  77.148 61.349 79.866 61.385 ;
     RECT  77.148 61.385 78.858 61.421 ;
     RECT  59.58 61.231 62.097 61.465 ;
     RECT  7.815 61.349 43.146 61.469 ;
     RECT  27.828 61.469 43.146 61.493 ;
     RECT  63.864 61.385 71.55 61.493 ;
     RECT  57.672 61.223 58.59 61.501 ;
     RECT  59.508 61.465 62.097 61.501 ;
     RECT  74.484 60.989 76.266 61.501 ;
     RECT  27.828 61.493 38.754 61.529 ;
     RECT  64.08 61.493 71.55 61.529 ;
     RECT  74.484 61.501 76.338 61.529 ;
     RECT  7.815 61.469 27.09 61.619 ;
     RECT  27.828 61.529 30.87 61.619 ;
     RECT  39.528 61.493 43.146 61.619 ;
     RECT  43.92 61.385 49.41 61.619 ;
     RECT  50.184 61.385 56.697 61.619 ;
     RECT  74.484 61.529 74.61 61.619 ;
     RECT  80.64 61.349 80.658 61.619 ;
     RECT  11.52 61.619 27.09 61.655 ;
     RECT  64.08 61.529 71.406 61.655 ;
     RECT  18.108 61.655 25.182 61.763 ;
     RECT  50.292 61.619 56.697 61.763 ;
     RECT  72.432 61.385 73.674 61.771 ;
     RECT  31.644 61.529 38.754 61.799 ;
     RECT  57.672 61.501 62.097 61.799 ;
     RECT  72.432 61.771 74.214 61.799 ;
     RECT  11.52 61.655 16.722 61.889 ;
     RECT  25.92 61.655 27.09 61.889 ;
     RECT  27.828 61.619 30.726 61.889 ;
     RECT  31.644 61.799 33.858 61.889 ;
     RECT  40.104 61.619 43.146 61.889 ;
     RECT  44.82 61.619 49.41 61.889 ;
     RECT  50.292 61.763 55.458 61.889 ;
     RECT  57.672 61.799 58.842 61.889 ;
     RECT  59.76 61.799 62.097 61.889 ;
     RECT  64.8 61.655 71.406 61.889 ;
     RECT  79.596 61.385 79.866 61.889 ;
     RECT  11.52 61.889 16.362 61.901 ;
     RECT  18.108 61.763 21.402 61.901 ;
     RECT  44.82 61.889 48.15 61.901 ;
     RECT  57.672 61.889 58.698 61.901 ;
     RECT  7.815 61.619 10.602 61.925 ;
     RECT  28.044 61.889 30.726 61.925 ;
     RECT  31.644 61.889 33.174 61.925 ;
     RECT  42.732 61.889 42.858 61.925 ;
     RECT  47.016 61.901 48.15 61.925 ;
     RECT  50.292 61.889 53.658 61.925 ;
     RECT  54.468 61.889 55.458 61.925 ;
     RECT  8.892 61.925 10.602 61.997 ;
     RECT  11.52 61.901 13.497 61.997 ;
     RECT  18.576 61.901 21.402 61.997 ;
     RECT  31.932 61.925 33.174 61.997 ;
     RECT  34.815 61.799 38.754 61.997 ;
     RECT  40.104 61.889 41.958 61.997 ;
     RECT  54.468 61.925 55.17 61.997 ;
     RECT  59.868 61.889 62.097 61.997 ;
     RECT  65.268 61.889 70.29 61.997 ;
     RECT  72.504 61.799 74.214 61.997 ;
     RECT  75.348 61.529 76.338 61.997 ;
     RECT  36.504 61.997 38.754 62.033 ;
     RECT  50.292 61.925 53.478 62.033 ;
     RECT  56.232 61.763 56.697 62.033 ;
     RECT  69.3 61.997 70.29 62.033 ;
     RECT  72.615 61.997 74.214 62.033 ;
     RECT  77.148 61.421 78.822 62.033 ;
     RECT  22.176 61.763 25.182 62.069 ;
     RECT  44.82 61.901 46.242 62.069 ;
     RECT  47.016 61.925 47.97 62.069 ;
     RECT  50.292 62.033 51.498 62.069 ;
     RECT  65.268 61.997 68.094 62.069 ;
     RECT  69.3 62.033 70.254 62.069 ;
     RECT  71.028 61.889 71.226 62.069 ;
     RECT  2.415 59.603 2.697 62.117 ;
     RECT  7.815 61.925 8.097 62.117 ;
     RECT  18.615 61.997 21.402 62.117 ;
     RECT  34.815 61.997 35.73 62.117 ;
     RECT  56.415 62.033 56.697 62.117 ;
     RECT  61.092 61.997 62.097 62.117 ;
     RECT  65.268 62.069 67.626 62.117 ;
     RECT  72.615 62.033 73.422 62.117 ;
     RECT  83.415 60.809 83.697 62.117 ;
     RECT  9.648 61.997 10.602 62.159 ;
     RECT  11.52 61.997 11.718 62.159 ;
     RECT  12.744 61.997 13.497 62.159 ;
     RECT  14.328 61.901 16.362 62.159 ;
     RECT  18.807 62.117 21.402 62.159 ;
     RECT  22.608 62.069 25.182 62.159 ;
     RECT  26.028 61.889 26.874 62.159 ;
     RECT  28.044 61.925 28.134 62.159 ;
     RECT  31.932 61.997 32.13 62.159 ;
     RECT  33.156 61.997 33.174 62.159 ;
     RECT  35.007 62.117 35.73 62.159 ;
     RECT  36.504 62.033 37.674 62.159 ;
     RECT  38.736 62.033 38.754 62.159 ;
     RECT  40.104 61.997 41.562 62.159 ;
     RECT  45 62.069 45.897 62.159 ;
     RECT  48.996 61.889 49.41 62.159 ;
     RECT  50.328 62.069 51.297 62.159 ;
     RECT  52.272 62.033 53.478 62.159 ;
     RECT  57.852 61.901 58.698 62.159 ;
     RECT  59.868 61.997 60.03 62.159 ;
     RECT  61.092 62.117 61.11 62.159 ;
     RECT  65.268 62.117 66.582 62.159 ;
     RECT  67.407 62.117 67.626 62.159 ;
     RECT  70.092 62.069 70.254 62.159 ;
     RECT  71.028 62.069 71.046 62.159 ;
     RECT  72.807 62.117 73.422 62.159 ;
     RECT  74.196 62.033 74.214 62.159 ;
     RECT  75.348 61.997 75.546 62.159 ;
     RECT  76.32 61.997 76.338 62.159 ;
     RECT  77.4 62.033 78.822 62.159 ;
     RECT  79.596 61.889 79.614 62.159 ;
     RECT  8.892 61.997 8.91 62.189 ;
     RECT  29.232 61.925 30.726 62.189 ;
     RECT  49.248 62.159 49.266 62.189 ;
     RECT  50.364 62.159 50.382 62.189 ;
     RECT  52.272 62.159 53.298 62.189 ;
     RECT  70.092 62.159 70.11 62.189 ;
     RECT  9.648 62.159 9.666 62.195 ;
     RECT  11.52 62.159 11.538 62.195 ;
     RECT  14.508 62.159 15.21 62.195 ;
     RECT  16.272 62.159 16.29 62.195 ;
     RECT  20.844 62.159 21.222 62.195 ;
     RECT  22.608 62.159 22.626 62.195 ;
     RECT  26.028 62.159 26.046 62.195 ;
     RECT  28.044 62.159 28.062 62.195 ;
     RECT  29.232 62.189 30.33 62.195 ;
     RECT  31.932 62.159 31.95 62.195 ;
     RECT  35.007 62.159 35.586 62.195 ;
     RECT  37.08 62.159 37.098 62.195 ;
     RECT  40.104 62.159 40.497 62.195 ;
     RECT  41.256 62.159 41.274 62.195 ;
     RECT  42.732 61.925 42.822 62.195 ;
     RECT  45.072 62.159 45.897 62.195 ;
     RECT  47.016 62.069 47.358 62.195 ;
     RECT  52.344 62.189 53.298 62.195 ;
     RECT  56.556 62.117 56.697 62.195 ;
     RECT  57.852 62.159 57.87 62.195 ;
     RECT  72.807 62.159 73.278 62.195 ;
     RECT  75.348 62.159 75.366 62.195 ;
     RECT  77.4 62.159 77.418 62.195 ;
     RECT  78.207 62.159 78.678 62.195 ;
     RECT  14.508 62.195 14.67 62.231 ;
     RECT  26.856 62.159 26.874 62.231 ;
     RECT  65.736 62.159 65.754 62.231 ;
     RECT  19.944 62.159 20.106 62.237 ;
     RECT  58.68 62.159 58.698 62.237 ;
     RECT  59.868 62.159 59.886 62.237 ;
     RECT  20.844 62.195 20.862 62.267 ;
     RECT  23.94 62.159 25.182 62.267 ;
     RECT  14.58 62.231 14.598 62.303 ;
     RECT  20.088 62.237 20.106 62.303 ;
     RECT  23.94 62.267 24.93 62.303 ;
     RECT  52.344 62.195 53.046 62.303 ;
     RECT  23.94 62.303 24.297 62.339 ;
     RECT  42.732 62.195 42.75 62.339 ;
     RECT  47.016 62.195 47.034 62.339 ;
     RECT  52.344 62.303 52.362 62.339 ;
     RECT  2.607 62.117 2.697 62.387 ;
     RECT  8.007 62.117 8.097 62.387 ;
     RECT  13.407 62.159 13.497 62.387 ;
     RECT  18.807 62.159 18.897 62.387 ;
     RECT  24.207 62.339 24.297 62.387 ;
     RECT  29.607 62.195 29.697 62.387 ;
     RECT  35.007 62.195 35.097 62.387 ;
     RECT  40.407 62.195 40.497 62.387 ;
     RECT  45.807 62.195 45.897 62.387 ;
     RECT  51.207 62.159 51.297 62.387 ;
     RECT  56.607 62.195 56.697 62.387 ;
     RECT  62.007 62.117 62.097 62.387 ;
     RECT  67.407 62.159 67.497 62.387 ;
     RECT  72.807 62.195 72.897 62.387 ;
     RECT  78.207 62.195 78.297 62.387 ;
     RECT  83.607 62.117 83.697 62.387 ;
    LAYER M4 ;
     RECT  0.025 44.88 0.037 44.904 ;
     RECT  0.037 18.864 0.085 19.848 ;
     RECT  0.085 46.416 0.133 46.872 ;
     RECT  0.061 47.904 0.133 47.928 ;
     RECT  0.085 49.2 0.133 49.224 ;
     RECT  0.037 51.312 0.133 51.336 ;
     RECT  0.085 18.768 0.156 19.848 ;
     RECT  0.037 44.88 0.156 45.096 ;
     RECT  0.085 16.32 0.169 16.344 ;
     RECT  0.133 46.416 0.181 49.224 ;
     RECT  0.133 17.616 0.205 17.64 ;
     RECT  0.156 18.768 0.205 45.096 ;
     RECT  0.169 16.32 0.229 16.536 ;
     RECT  0.133 14.208 0.277 14.232 ;
     RECT  0.133 51.312 0.277 51.672 ;
     RECT  0.205 17.616 0.313 45.096 ;
     RECT  0.181 46.416 0.313 49.608 ;
     RECT  0.229 15.792 0.325 16.536 ;
     RECT  0.313 17.616 0.325 49.608 ;
     RECT  0.229 55.536 0.325 55.56 ;
     RECT  0.277 50.832 0.373 51.672 ;
     RECT  0.277 14.208 0.421 14.76 ;
     RECT  0.325 54.72 0.421 55.56 ;
     RECT  0.325 12.432 0.469 12.456 ;
     RECT  0.325 15.792 0.515 49.608 ;
     RECT  0.421 53.904 0.517 55.56 ;
     RECT  0.515 19.344 0.565 49.608 ;
     RECT  0.469 12.432 0.661 13.08 ;
     RECT  0.565 19.344 0.709 49.656 ;
     RECT  0.373 50.832 0.709 51.768 ;
     RECT  0.709 19.344 0.757 51.768 ;
     RECT  0.517 53.04 0.757 55.56 ;
     RECT  0.181 10.224 0.853 10.248 ;
     RECT  0.853 10.224 0.949 10.68 ;
     RECT  0.421 14.16 0.997 14.76 ;
     RECT  0.515 15.792 0.997 18.216 ;
     RECT  0.661 12.336 1.045 13.08 ;
     RECT  0.997 14.16 1.045 18.216 ;
     RECT  0.949 10.224 1.093 10.728 ;
     RECT  1.093 10.176 1.381 10.728 ;
     RECT  0.757 19.344 1.381 55.56 ;
     RECT  0.805 7.968 1.477 7.992 ;
     RECT  1.381 10.176 1.525 11.256 ;
     RECT  1.045 12.336 1.525 18.216 ;
     RECT  1.525 10.176 1.717 18.216 ;
     RECT  1.381 19.344 1.717 56.28 ;
     RECT  1.477 7.968 1.813 8.472 ;
     RECT  1.717 10.176 1.813 56.28 ;
     RECT  1.813 7.968 2.053 9.048 ;
     RECT  1.813 10.176 2.053 56.52 ;
     RECT  2.053 7.968 2.149 56.52 ;
     RECT  1.861 5.616 2.293 5.64 ;
     RECT  2.149 7.968 2.293 57.336 ;
     RECT  1.621 59.28 2.293 59.304 ;
     RECT  2.293 5.04 2.329 5.64 ;
     RECT  2.293 7.632 2.329 57.336 ;
     RECT  2.329 6.624 2.365 6.648 ;
     RECT  2.329 7.632 2.365 57.432 ;
     RECT  2.329 4.416 2.408 5.64 ;
     RECT  2.365 6.624 2.408 57.432 ;
     RECT  2.293 58.944 2.408 59.304 ;
     RECT  2.408 2.148 2.512 62.112 ;
     RECT  2.512 2.418 2.6 62.112 ;
     RECT  2.6 2.418 2.704 62.382 ;
     RECT  2.704 3.84 3.587 59.4 ;
     RECT  3.587 3.888 3.731 59.4 ;
     RECT  3.731 3.936 4.169 59.4 ;
     RECT  4.169 4.272 4.777 59.4 ;
     RECT  4.777 4.272 4.835 59.88 ;
     RECT  4.835 4.272 6.289 59.64 ;
     RECT  6.289 4.272 6.685 59.832 ;
     RECT  6.685 4.272 6.853 60.552 ;
     RECT  6.853 4.272 6.973 60.936 ;
     RECT  6.973 4.272 7.045 61.128 ;
     RECT  7.045 4.128 7.189 61.128 ;
     RECT  7.189 4.128 7.669 61.992 ;
     RECT  7.669 3.936 7.808 61.992 ;
     RECT  7.808 2.148 7.912 62.112 ;
     RECT  7.912 2.418 8 62.112 ;
     RECT  8 2.418 8.104 62.382 ;
     RECT  8.104 4.128 8.579 62.184 ;
     RECT  8.579 60.912 9.497 62.184 ;
     RECT  9.445 3.072 9.637 3.096 ;
     RECT  8.579 4.128 9.637 59.88 ;
     RECT  9.637 3.072 9.641 59.88 ;
     RECT  9.641 3.072 9.685 7.704 ;
     RECT  9.685 2.256 9.971 7.704 ;
     RECT  9.971 2.256 10.541 3.096 ;
     RECT  9.971 4.464 10.609 7.704 ;
     RECT  9.641 8.736 10.609 59.88 ;
     RECT  10.541 3.024 11.125 3.096 ;
     RECT  10.609 4.464 11.125 59.88 ;
     RECT  11.125 3.024 11.189 59.88 ;
     RECT  11.189 4.224 11.221 59.88 ;
     RECT  11.221 4.224 11.513 60.024 ;
     RECT  9.497 61.104 11.549 62.184 ;
     RECT  11.513 5.088 11.987 60.024 ;
     RECT  11.189 3.024 12.037 3.096 ;
     RECT  12.037 2.88 12.121 3.096 ;
     RECT  11.987 58.512 12.121 60.024 ;
     RECT  11.549 61.104 12.121 61.992 ;
     RECT  12.121 2.256 12.409 3.096 ;
     RECT  12.409 2.256 12.877 4.008 ;
     RECT  11.987 5.088 12.877 57.432 ;
     RECT  12.877 2.256 13.021 57.432 ;
     RECT  13.021 2.256 13.208 57.48 ;
     RECT  12.121 58.512 13.208 61.992 ;
     RECT  13.208 2.148 13.312 62.112 ;
     RECT  13.312 2.418 13.4 62.112 ;
     RECT  13.4 2.418 13.504 62.382 ;
     RECT  13.504 2.688 13.619 61.992 ;
     RECT  13.619 3.024 14.497 61.992 ;
     RECT  14.497 3.024 14.629 62.184 ;
     RECT  14.629 2.832 14.723 62.184 ;
     RECT  14.723 2.832 15.109 61.896 ;
     RECT  15.109 2.64 16.081 61.896 ;
     RECT  16.081 2.208 16.163 61.896 ;
     RECT  16.163 3.024 17.989 61.896 ;
     RECT  17.989 2.256 18.469 61.896 ;
     RECT  18.469 2.256 18.608 62.232 ;
     RECT  18.608 2.148 18.712 62.232 ;
     RECT  18.712 2.256 18.8 62.232 ;
     RECT  18.8 2.256 18.904 62.382 ;
     RECT  18.904 2.256 19.721 62.232 ;
     RECT  19.721 2.256 19.865 57.624 ;
     RECT  19.721 58.656 19.937 62.232 ;
     RECT  19.937 58.752 19.973 62.232 ;
     RECT  19.865 2.736 20.579 57.624 ;
     RECT  20.579 4.128 20.905 57.624 ;
     RECT  19.973 58.752 20.905 61.56 ;
     RECT  20.579 2.736 21.089 2.904 ;
     RECT  20.905 4.128 21.155 61.56 ;
     RECT  21.089 2.832 21.625 2.904 ;
     RECT  21.155 4.128 21.625 61.464 ;
     RECT  21.625 2.832 22.417 61.464 ;
     RECT  22.417 2.256 22.597 61.464 ;
     RECT  22.597 2.256 22.691 62.184 ;
     RECT  22.691 2.256 23.785 61.464 ;
     RECT  23.785 2.256 24.008 61.896 ;
     RECT  24.008 2.148 24.112 62.112 ;
     RECT  24.112 2.256 24.149 62.112 ;
     RECT  24.149 2.418 24.2 62.112 ;
     RECT  24.2 2.418 24.304 62.382 ;
     RECT  24.304 2.736 24.515 62.184 ;
     RECT  24.515 2.736 25.909 61.608 ;
     RECT  25.909 2.736 26.125 61.848 ;
     RECT  26.125 2.688 26.195 61.848 ;
     RECT  26.195 2.736 27.241 61.848 ;
     RECT  27.241 2.256 28.837 61.848 ;
     RECT  28.837 2.256 29.408 62.184 ;
     RECT  29.408 2.148 29.512 62.184 ;
     RECT  29.512 2.256 29.6 62.184 ;
     RECT  29.6 2.256 29.704 62.382 ;
     RECT  29.704 2.256 30.017 61.992 ;
     RECT  30.017 2.592 30.697 61.992 ;
     RECT  30.697 2.592 31.573 62.184 ;
     RECT  31.573 1.728 31.601 62.184 ;
     RECT  31.601 1.728 31.637 1.752 ;
     RECT  31.601 3.264 31.961 62.184 ;
     RECT  31.961 3.264 32.537 61.992 ;
     RECT  32.537 3.264 32.789 54.792 ;
     RECT  32.789 3.264 32.893 54.744 ;
     RECT  32.893 2.304 33.877 54.744 ;
     RECT  32.537 55.872 33.877 61.608 ;
     RECT  33.877 2.304 34.808 61.608 ;
     RECT  34.808 2.148 34.912 62.112 ;
     RECT  34.912 2.256 35 62.112 ;
     RECT  35 2.256 35.104 62.382 ;
     RECT  35.104 2.256 35.561 2.856 ;
     RECT  35.104 3.936 36.349 62.184 ;
     RECT  35.561 2.256 36.565 2.28 ;
     RECT  36.349 3.456 36.565 62.184 ;
     RECT  36.565 2.256 36.785 62.184 ;
     RECT  36.785 2.976 37.109 62.184 ;
     RECT  37.109 2.976 37.235 61.992 ;
     RECT  37.235 2.976 38.185 5.64 ;
     RECT  38.185 2.832 38.653 5.64 ;
     RECT  37.235 6.624 38.653 61.992 ;
     RECT  38.653 2.832 38.729 61.992 ;
     RECT  38.729 2.832 39.011 3.576 ;
     RECT  38.729 4.656 39.877 61.992 ;
     RECT  39.877 4.656 40.069 62.184 ;
     RECT  39.011 2.832 40.093 2.856 ;
     RECT  40.093 2.832 40.208 2.904 ;
     RECT  40.069 4.08 40.208 62.184 ;
     RECT  40.208 2.148 40.312 62.184 ;
     RECT  40.312 2.418 40.4 62.184 ;
     RECT  40.4 2.418 40.504 62.382 ;
     RECT  40.504 2.736 40.709 61.992 ;
     RECT  40.709 4.704 41.105 61.992 ;
     RECT  40.709 2.736 41.821 3.624 ;
     RECT  41.821 2.736 41.861 3.768 ;
     RECT  41.105 4.752 41.969 61.992 ;
     RECT  41.861 2.832 42.515 3.768 ;
     RECT  42.515 2.88 42.541 3.768 ;
     RECT  41.969 4.752 42.541 61.512 ;
     RECT  42.541 2.88 42.797 61.512 ;
     RECT  42.797 3.984 42.973 61.512 ;
     RECT  42.973 3.984 42.977 61.656 ;
     RECT  42.977 58.8 43.085 61.656 ;
     RECT  42.797 2.88 44.125 2.904 ;
     RECT  42.977 3.984 44.125 57.72 ;
     RECT  43.085 58.8 44.161 60.648 ;
     RECT  43.085 61.632 44.161 61.656 ;
     RECT  44.161 58.8 44.233 61.656 ;
     RECT  44.125 2.256 44.557 57.72 ;
     RECT  44.233 58.704 44.557 61.656 ;
     RECT  44.557 2.256 44.989 61.656 ;
     RECT  44.989 2.256 45.608 61.8 ;
     RECT  45.608 2.148 45.712 62.112 ;
     RECT  45.712 2.256 45.8 62.112 ;
     RECT  45.8 2.256 45.904 62.382 ;
     RECT  45.904 2.256 46.181 61.896 ;
     RECT  46.181 2.88 46.541 61.896 ;
     RECT  46.541 3.36 47.869 61.896 ;
     RECT  47.869 2.832 48.467 61.896 ;
     RECT  48.467 2.832 48.557 3.576 ;
     RECT  48.557 2.832 48.805 3.432 ;
     RECT  48.467 4.608 49.237 61.896 ;
     RECT  48.805 2.496 50.101 3.432 ;
     RECT  49.237 4.608 50.101 62.184 ;
     RECT  50.101 2.496 51.008 62.184 ;
     RECT  51.008 2.148 51.112 62.184 ;
     RECT  51.112 2.418 51.2 62.184 ;
     RECT  51.2 2.418 51.304 62.382 ;
     RECT  51.304 3.024 51.473 62.184 ;
     RECT  51.473 3.024 52.297 3.336 ;
     RECT  52.297 2.256 52.355 3.336 ;
     RECT  51.473 4.464 52.403 62.184 ;
     RECT  52.403 4.464 52.451 61.608 ;
     RECT  52.355 2.544 52.693 3.336 ;
     RECT  52.451 4.464 52.693 61.56 ;
     RECT  52.693 2.544 53.165 61.56 ;
     RECT  53.365 2.256 54.065 2.28 ;
     RECT  53.165 3.264 54.277 61.56 ;
     RECT  54.277 2.544 54.641 61.56 ;
     RECT  54.641 2.784 55.073 61.56 ;
     RECT  55.073 2.832 55.381 61.56 ;
     RECT  55.381 2.832 56.113 61.752 ;
     RECT  56.113 2.256 56.408 61.752 ;
     RECT  56.408 2.148 56.512 62.112 ;
     RECT  56.512 2.418 56.6 62.112 ;
     RECT  56.6 2.418 56.704 62.382 ;
     RECT  56.704 2.784 57.347 62.184 ;
     RECT  57.347 4.464 57.539 62.184 ;
     RECT  57.539 4.464 57.773 60.744 ;
     RECT  57.347 2.784 58.525 3.432 ;
     RECT  57.539 61.872 58.669 62.184 ;
     RECT  58.669 61.872 58.709 62.232 ;
     RECT  58.525 2.352 58.849 3.432 ;
     RECT  57.773 4.464 58.849 60.648 ;
     RECT  58.849 2.352 58.931 60.648 ;
     RECT  58.931 4.464 59.321 60.648 ;
     RECT  58.931 2.352 59.357 3.48 ;
     RECT  59.321 23.616 59.749 60.648 ;
     RECT  58.709 62.208 59.749 62.232 ;
     RECT  59.321 4.464 59.753 22.584 ;
     RECT  59.753 4.464 59.825 22.536 ;
     RECT  59.749 23.616 59.897 62.232 ;
     RECT  59.357 2.784 59.929 3.48 ;
     RECT  59.825 4.464 59.929 22.344 ;
     RECT  59.929 2.784 60.325 22.344 ;
     RECT  60.325 2.736 60.653 22.344 ;
     RECT  59.897 23.616 60.689 61.608 ;
     RECT  60.689 23.616 60.793 60.84 ;
     RECT  60.653 2.784 61.225 22.344 ;
     RECT  60.793 23.568 61.225 60.84 ;
     RECT  61.225 2.784 61.808 60.84 ;
     RECT  61.808 2.148 61.912 62.112 ;
     RECT  61.912 2.208 62 62.112 ;
     RECT  62 2.208 62.104 62.382 ;
     RECT  62.104 4.176 63.029 61.032 ;
     RECT  63.029 59.712 63.155 61.032 ;
     RECT  63.029 4.176 63.317 58.68 ;
     RECT  62.104 2.208 63.493 2.808 ;
     RECT  63.155 59.904 63.497 61.032 ;
     RECT  63.497 59.904 63.605 60.984 ;
     RECT  63.317 4.176 63.893 58.44 ;
     RECT  63.493 2.208 64.105 2.856 ;
     RECT  64.105 2.208 64.393 2.904 ;
     RECT  64.393 2.208 64.451 3.096 ;
     RECT  63.893 23.328 64.789 58.44 ;
     RECT  63.605 59.904 64.789 60.888 ;
     RECT  64.451 2.208 64.865 2.856 ;
     RECT  63.893 4.176 65.189 22.344 ;
     RECT  64.865 2.496 65.261 2.856 ;
     RECT  65.261 2.496 65.405 2.808 ;
     RECT  65.405 2.496 65.441 2.616 ;
     RECT  65.441 2.496 65.549 2.52 ;
     RECT  65.189 16.368 65.585 22.344 ;
     RECT  65.585 16.464 65.833 22.344 ;
     RECT  64.789 23.328 65.833 61.608 ;
     RECT  65.833 16.464 65.945 61.608 ;
     RECT  65.189 4.176 66.301 15.336 ;
     RECT  65.945 23.904 66.409 61.608 ;
     RECT  66.301 4.176 66.661 15.432 ;
     RECT  65.945 16.464 66.661 22.584 ;
     RECT  66.769 2.256 66.805 2.28 ;
     RECT  66.661 4.176 66.805 22.584 ;
     RECT  66.409 23.904 66.949 61.656 ;
     RECT  66.949 23.664 67.021 61.656 ;
     RECT  66.805 2.256 67.208 22.584 ;
     RECT  67.021 23.616 67.208 61.656 ;
     RECT  67.208 2.148 67.312 62.112 ;
     RECT  67.312 2.418 67.4 62.112 ;
     RECT  67.4 2.418 67.504 62.382 ;
     RECT  67.504 2.496 67.763 61.656 ;
     RECT  67.763 2.496 67.853 3.336 ;
     RECT  67.853 2.496 69.001 3.144 ;
     RECT  67.763 4.416 69.001 61.656 ;
     RECT  69.001 2.496 69.059 61.656 ;
     RECT  69.059 58.704 69.185 61.656 ;
     RECT  69.059 2.496 69.443 57.624 ;
     RECT  69.443 2.496 69.869 3.144 ;
     RECT  70.069 62.16 70.121 62.184 ;
     RECT  69.185 58.704 70.297 60.792 ;
     RECT  70.297 58.704 70.355 61.032 ;
     RECT  69.443 4.416 70.369 57.624 ;
     RECT  70.355 58.704 70.369 60.984 ;
     RECT  70.369 4.416 70.451 60.984 ;
     RECT  69.869 2.496 70.481 2.52 ;
     RECT  70.451 59.04 70.733 60.984 ;
     RECT  70.733 60.48 71.309 60.984 ;
     RECT  70.451 4.416 71.413 57.432 ;
     RECT  70.733 59.04 71.413 59.448 ;
     RECT  71.197 2.832 71.449 3.432 ;
     RECT  71.449 2.256 71.701 3.432 ;
     RECT  71.413 4.416 71.701 59.448 ;
     RECT  71.309 60.48 72.385 60.6 ;
     RECT  71.701 2.256 72.529 59.448 ;
     RECT  72.385 60.48 72.529 61.368 ;
     RECT  72.529 2.256 72.565 61.368 ;
     RECT  72.565 2.256 72.608 61.464 ;
     RECT  72.608 2.148 72.712 62.112 ;
     RECT  72.712 2.256 72.8 62.112 ;
     RECT  72.8 2.256 72.904 62.382 ;
     RECT  72.904 2.256 73.861 3.192 ;
     RECT  73.861 2.208 73.897 3.192 ;
     RECT  72.904 4.512 73.897 9.096 ;
     RECT  72.904 10.992 73.909 62.184 ;
     RECT  73.897 2.208 73.955 9.576 ;
     RECT  73.909 10.608 74.185 62.184 ;
     RECT  73.955 2.208 74.225 8.856 ;
     RECT  74.185 9.84 74.225 62.184 ;
     RECT  74.225 9.84 74.297 57.432 ;
     RECT  74.225 4.8 74.909 8.856 ;
     RECT  74.225 2.208 75.193 3.048 ;
     RECT  74.297 10.272 75.397 57.432 ;
     RECT  74.225 58.416 75.397 62.184 ;
     RECT  75.397 10.272 75.445 62.184 ;
     RECT  75.193 2.208 75.449 3.72 ;
     RECT  74.909 4.8 75.481 6.936 ;
     RECT  74.909 8.256 75.625 8.856 ;
     RECT  75.445 9.84 75.625 62.184 ;
     RECT  75.449 2.832 75.733 3.72 ;
     RECT  75.481 4.704 75.733 6.936 ;
     RECT  75.733 2.832 75.779 6.936 ;
     RECT  75.625 8.256 76.205 62.184 ;
     RECT  76.205 8.256 76.345 60.84 ;
     RECT  76.345 8.16 76.403 60.84 ;
     RECT  75.779 4.704 76.453 6.936 ;
     RECT  76.403 8.16 76.453 57.432 ;
     RECT  76.403 58.416 76.817 60.84 ;
     RECT  75.779 2.832 77.125 3.72 ;
     RECT  76.453 4.704 77.125 57.432 ;
     RECT  77.125 2.832 77.245 57.432 ;
     RECT  76.817 59.04 77.353 60.84 ;
     RECT  76.205 62.16 77.353 62.184 ;
     RECT  77.353 59.04 78.001 62.184 ;
     RECT  77.245 2.256 78.008 57.432 ;
     RECT  78.001 58.944 78.008 62.184 ;
     RECT  78.008 2.148 78.112 62.184 ;
     RECT  78.112 2.256 78.2 62.184 ;
     RECT  78.2 2.256 78.304 62.382 ;
     RECT  78.304 2.256 78.509 9.096 ;
     RECT  78.304 10.272 78.515 52.584 ;
     RECT  78.304 62.16 78.689 62.184 ;
     RECT  78.509 2.832 79.229 9.096 ;
     RECT  78.515 10.272 79.235 52.536 ;
     RECT  79.235 10.272 79.301 11.688 ;
     RECT  78.304 53.568 79.405 61.176 ;
     RECT  79.235 12.72 79.621 52.536 ;
     RECT  79.405 53.568 79.621 61.368 ;
     RECT  79.229 3.6 79.717 9.096 ;
     RECT  79.621 12.72 79.733 61.368 ;
     RECT  79.717 3.6 79.769 9.24 ;
     RECT  79.301 10.272 80.485 11.64 ;
     RECT  79.733 12.72 80.485 60.84 ;
     RECT  79.769 3.6 80.525 8.856 ;
     RECT  80.485 10.272 80.633 60.84 ;
     RECT  80.525 3.6 80.705 8.664 ;
     RECT  80.633 10.272 80.777 60.504 ;
     RECT  80.777 10.272 80.881 57.528 ;
     RECT  80.705 3.6 80.963 5.736 ;
     RECT  80.881 9.84 81.425 57.528 ;
     RECT  81.425 9.84 81.461 10.296 ;
     RECT  80.963 3.6 81.533 5.544 ;
     RECT  80.777 58.56 81.827 60.504 ;
     RECT  81.425 11.376 81.889 57.528 ;
     RECT  81.827 58.56 81.889 60.408 ;
     RECT  81.889 11.376 81.923 60.408 ;
     RECT  81.923 11.52 81.929 60.408 ;
     RECT  81.929 54.672 82.019 60.408 ;
     RECT  81.929 51.312 82.109 53.4 ;
     RECT  82.019 55.824 82.115 60.408 ;
     RECT  81.533 5.472 82.141 5.544 ;
     RECT  80.705 6.768 82.141 8.664 ;
     RECT  82.141 5.472 82.403 8.664 ;
     RECT  81.929 11.52 82.933 50.184 ;
     RECT  82.109 51.312 82.933 52.728 ;
     RECT  81.533 3.888 82.969 3.912 ;
     RECT  82.403 5.472 83.221 7.128 ;
     RECT  82.403 8.16 83.221 8.664 ;
     RECT  82.933 11.52 83.221 52.728 ;
     RECT  82.115 55.824 83.221 55.848 ;
     RECT  82.115 57.312 83.221 60.408 ;
     RECT  81.461 9.84 83.269 9.864 ;
     RECT  83.221 11.52 83.269 53.4 ;
     RECT  82.019 54.672 83.269 54.696 ;
     RECT  83.221 55.824 83.269 55.992 ;
     RECT  83.221 57.024 83.269 60.408 ;
     RECT  82.969 3.888 83.408 3.96 ;
     RECT  83.221 5.04 83.408 7.128 ;
     RECT  83.221 8.16 83.408 8.76 ;
     RECT  83.269 9.84 83.408 53.4 ;
     RECT  83.269 54.528 83.408 54.696 ;
     RECT  83.269 55.824 83.408 60.408 ;
     RECT  83.408 2.148 83.512 62.112 ;
     RECT  83.512 2.418 83.6 62.112 ;
     RECT  83.6 2.418 83.704 62.382 ;
     RECT  83.704 53.376 83.729 53.4 ;
     RECT  83.704 56.016 83.729 56.04 ;
     RECT  83.704 11.952 83.765 11.976 ;
     RECT  83.704 50.928 83.801 51.72 ;
     RECT  83.704 18.72 83.837 44.808 ;
     RECT  83.704 48.24 83.843 49.032 ;
     RECT  83.704 16.56 83.873 17.112 ;
     RECT  83.837 18.96 83.873 44.808 ;
     RECT  83.704 14.16 83.945 14.184 ;
     RECT  83.873 18.96 83.945 18.984 ;
     RECT  83.801 51.36 83.945 51.72 ;
     RECT  83.945 51.36 84.053 51.384 ;
     RECT  83.873 17.088 84.341 17.112 ;
     RECT  83.873 20.016 84.733 44.808 ;
     RECT  84.733 20.016 85.777 45 ;
     RECT  85.777 19.968 86.069 45 ;
     RECT  86.069 19.968 86.22 44.808 ;
    LAYER M5 ;
     RECT  31.392 0.144 31.608 1.763 ;
     RECT  2.4 2.137 2.52 2.151 ;
     RECT  7.8 2.137 7.92 2.151 ;
     RECT  13.2 2.137 13.32 2.151 ;
     RECT  18.6 2.137 18.72 2.151 ;
     RECT  24 2.137 24.12 2.151 ;
     RECT  29.4 2.137 29.52 2.151 ;
     RECT  34.8 2.137 34.92 2.151 ;
     RECT  40.2 2.137 40.32 2.151 ;
     RECT  45.6 2.137 45.72 2.151 ;
     RECT  51 2.137 51.12 2.151 ;
     RECT  56.4 2.137 56.52 2.151 ;
     RECT  61.8 2.137 61.92 2.151 ;
     RECT  67.2 2.137 67.32 2.151 ;
     RECT  72.6 2.137 72.72 2.151 ;
     RECT  78 2.137 78.12 2.151 ;
     RECT  83.4 2.137 83.52 2.151 ;
     RECT  13.2 2.151 13.512 2.245 ;
     RECT  18.6 2.151 18.912 2.245 ;
     RECT  56.4 2.151 56.712 2.245 ;
     RECT  67.2 2.151 67.512 2.245 ;
     RECT  72.6 2.151 72.912 2.245 ;
     RECT  51 2.151 51.312 2.485 ;
     RECT  16.128 2.197 16.152 2.629 ;
     RECT  12.432 2.245 13.512 2.677 ;
     RECT  26.16 2.677 26.184 2.773 ;
     RECT  31.392 1.763 31.416 2.773 ;
     RECT  78 2.151 78.312 2.773 ;
     RECT  15.408 2.629 16.152 2.821 ;
     RECT  18.48 2.245 18.912 2.821 ;
     RECT  20.016 2.725 20.04 2.821 ;
     RECT  40.2 2.151 40.512 2.821 ;
     RECT  45.6 2.151 45.912 2.821 ;
     RECT  52.32 2.245 52.344 2.821 ;
     RECT  53.376 2.245 53.4 2.821 ;
     RECT  66.816 2.245 67.512 2.821 ;
     RECT  77.28 2.773 78.312 2.821 ;
     RECT  20.016 2.821 20.568 2.867 ;
     RECT  12.432 2.677 13.608 2.869 ;
     RECT  18.384 2.821 18.912 2.869 ;
     RECT  45.6 2.821 46.152 2.869 ;
     RECT  66.816 2.821 67.752 3.011 ;
     RECT  12.048 2.869 13.608 3.013 ;
     RECT  72.6 2.245 73.32 3.013 ;
     RECT  14.64 2.821 16.152 3.059 ;
     RECT  9.696 2.245 9.72 3.061 ;
     RECT  38.208 2.821 38.232 3.061 ;
     RECT  11.472 3.013 13.608 3.107 ;
     RECT  72.6 3.013 74.136 3.203 ;
     RECT  34.8 2.151 35.112 3.253 ;
     RECT  31.296 2.773 31.416 3.299 ;
     RECT  52.32 2.821 53.4 3.299 ;
     RECT  22.704 2.245 22.728 3.349 ;
     RECT  24 2.151 24.312 3.349 ;
     RECT  36.576 3.109 36.6 3.349 ;
     RECT  37.632 3.061 38.232 3.349 ;
     RECT  44.976 2.869 46.152 3.349 ;
     RECT  34.224 3.253 35.112 3.397 ;
     RECT  56.16 2.245 56.712 3.397 ;
     RECT  72.6 3.203 73.032 3.397 ;
     RECT  27.264 2.245 27.912 3.443 ;
     RECT  56.16 3.397 56.808 3.443 ;
     RECT  36.576 3.349 38.232 3.541 ;
     RECT  15.408 3.059 16.152 3.587 ;
     RECT  48.432 2.821 48.456 3.637 ;
     RECT  77.28 2.821 78.696 3.685 ;
     RECT  9.456 3.061 9.72 3.733 ;
     RECT  42.48 2.821 42.504 3.779 ;
     RECT  36.576 3.541 39 3.827 ;
     RECT  2.4 2.151 2.712 3.829 ;
     RECT  12.48 3.107 13.608 3.829 ;
     RECT  77.232 3.685 78.696 3.829 ;
     RECT  2.4 3.829 3.576 3.877 ;
     RECT  77.136 3.829 78.696 3.877 ;
     RECT  7.8 2.151 8.112 3.925 ;
     RECT  11.472 3.107 11.496 3.925 ;
     RECT  25.44 2.773 26.184 3.925 ;
     RECT  44.448 3.349 46.152 3.925 ;
     RECT  47.664 3.637 48.456 3.925 ;
     RECT  56.4 3.443 56.808 3.925 ;
     RECT  12.48 3.829 14.424 4.019 ;
     RECT  15.456 3.587 16.152 4.019 ;
     RECT  58.896 3.445 58.92 4.019 ;
     RECT  69.408 2.485 69.432 4.019 ;
     RECT  31.392 3.299 31.416 4.021 ;
     RECT  32.64 3.541 32.664 4.021 ;
     RECT  15.456 4.019 15.96 4.067 ;
     RECT  36.576 3.827 37.656 4.067 ;
     RECT  59.952 3.301 59.976 4.115 ;
     RECT  67.2 3.011 67.752 4.115 ;
     RECT  2.4 3.877 3.72 4.117 ;
     RECT  20.16 2.867 20.568 4.117 ;
     RECT  21.648 3.157 21.672 4.117 ;
     RECT  29.4 2.151 29.712 4.117 ;
     RECT  52.32 3.299 53.352 4.163 ;
     RECT  61.8 2.151 62.112 4.165 ;
     RECT  31.392 4.021 32.664 4.213 ;
     RECT  34.128 3.397 35.112 4.213 ;
     RECT  80.64 3.829 80.664 4.261 ;
     RECT  18.384 2.869 19.08 4.405 ;
     RECT  40.08 2.821 40.512 4.453 ;
     RECT  50.832 2.485 51.312 4.453 ;
     RECT  56.4 3.925 57.336 4.453 ;
     RECT  2.4 4.117 4.104 4.501 ;
     RECT  25.44 3.925 27.096 4.501 ;
     RECT  42.768 3.973 42.792 4.501 ;
     RECT  50.496 4.453 51.312 4.501 ;
     RECT  52.32 4.163 53.064 4.501 ;
     RECT  61.8 4.165 62.76 4.501 ;
     RECT  64.416 2.197 64.44 4.501 ;
     RECT  70.032 4.405 70.056 4.501 ;
     RECT  11.136 3.925 11.496 4.547 ;
     RECT  42.768 4.501 42.936 4.547 ;
     RECT  37.056 4.067 37.656 4.595 ;
     RECT  17.28 4.453 17.304 4.645 ;
     RECT  18.336 4.405 19.08 4.645 ;
     RECT  38.688 3.827 39 4.693 ;
     RECT  40.08 4.453 40.68 4.693 ;
     RECT  44.448 3.925 48.456 4.693 ;
     RECT  44.448 4.693 48.84 4.741 ;
     RECT  80.4 4.261 80.664 4.741 ;
     RECT  44.112 4.741 48.84 4.837 ;
     RECT  61.8 4.501 64.44 4.883 ;
     RECT  9.456 3.733 9.96 4.931 ;
     RECT  17.28 4.645 19.08 4.933 ;
     RECT  22.704 3.349 24.312 4.979 ;
     RECT  2.4 4.501 5.112 4.981 ;
     RECT  6.48 4.645 6.504 4.981 ;
     RECT  38.688 4.693 40.68 4.981 ;
     RECT  2.4 4.981 6.504 5.029 ;
     RECT  13.2 4.019 14.424 5.029 ;
     RECT  16.992 4.933 19.08 5.029 ;
     RECT  70.032 4.501 70.104 5.029 ;
     RECT  83.4 2.151 83.712 5.029 ;
     RECT  11.472 4.547 11.496 5.077 ;
     RECT  31.392 4.213 35.112 5.077 ;
     RECT  65.472 4.837 65.496 5.077 ;
     RECT  77.136 3.877 79.224 5.077 ;
     RECT  37.632 4.595 37.656 5.123 ;
     RECT  23.328 4.979 24.312 5.125 ;
     RECT  25.44 4.501 27.288 5.125 ;
     RECT  65.472 5.077 65.64 5.125 ;
     RECT  2.304 5.029 6.504 5.171 ;
     RECT  23.328 5.125 27.288 5.171 ;
     RECT  50.496 4.501 53.064 5.171 ;
     RECT  77.136 5.077 79.368 5.219 ;
     RECT  7.68 3.925 8.112 5.221 ;
     RECT  15.456 4.067 15.48 5.221 ;
     RECT  67.2 4.115 67.512 5.221 ;
     RECT  44.112 4.837 49.32 5.267 ;
     RECT  50.496 5.171 53.016 5.267 ;
     RECT  64.8 5.125 65.64 5.267 ;
     RECT  7.68 5.221 8.376 5.269 ;
     RECT  42.912 4.547 42.936 5.365 ;
     RECT  44.112 5.267 46.872 5.365 ;
     RECT  69.984 5.029 70.104 5.365 ;
     RECT  61.8 4.883 63.624 5.413 ;
     RECT  15.456 5.221 16.008 5.509 ;
     RECT  16.992 5.029 19.128 5.509 ;
     RECT  31.392 5.077 35.208 5.509 ;
     RECT  59.856 5.125 59.88 5.509 ;
     RECT  60.96 5.413 63.624 5.555 ;
     RECT  75.744 3.733 75.768 5.555 ;
     RECT  66.672 5.221 67.512 5.557 ;
     RECT  69.984 5.365 70.68 5.603 ;
     RECT  2.304 5.171 5.736 5.605 ;
     RECT  38.688 4.981 41.208 5.605 ;
     RECT  15.456 5.509 19.128 5.651 ;
     RECT  24 5.171 27.288 5.747 ;
     RECT  61.8 5.555 63.624 5.747 ;
     RECT  65.472 5.267 65.64 5.747 ;
     RECT  80.4 4.741 80.952 5.747 ;
     RECT  20.16 4.117 21.672 5.749 ;
     RECT  42.912 5.365 46.872 5.749 ;
     RECT  20.16 5.749 22.344 5.795 ;
     RECT  38.496 5.605 41.208 5.795 ;
     RECT  69.984 5.603 70.104 5.795 ;
     RECT  26.928 5.747 27.288 5.797 ;
     RECT  79.344 5.219 79.368 5.845 ;
     RECT  31.392 5.509 35.64 5.891 ;
     RECT  13.104 5.029 14.424 5.893 ;
     RECT  42.624 5.749 46.872 6.035 ;
     RECT  77.136 5.219 78.312 6.035 ;
     RECT  26.928 5.797 27.336 6.037 ;
     RECT  28.464 4.117 29.712 6.037 ;
     RECT  37.2 5.845 37.224 6.037 ;
     RECT  71.712 3.397 73.032 6.037 ;
     RECT  74.112 3.203 74.136 6.037 ;
     RECT  20.208 5.795 22.344 6.179 ;
     RECT  12.816 5.893 14.424 6.181 ;
     RECT  15.456 5.651 16.056 6.181 ;
     RECT  1.872 5.605 5.736 6.229 ;
     RECT  6.864 5.269 8.376 6.229 ;
     RECT  11.472 5.077 11.736 6.229 ;
     RECT  12.816 6.181 16.056 6.229 ;
     RECT  17.04 5.651 19.128 6.323 ;
     RECT  20.208 6.179 20.568 6.323 ;
     RECT  24 5.747 25.464 6.323 ;
     RECT  48.192 5.267 49.32 6.323 ;
     RECT  50.688 5.267 53.016 6.323 ;
     RECT  56.4 4.453 57.912 6.323 ;
     RECT  59.808 5.509 59.88 6.323 ;
     RECT  79.344 5.845 79.752 6.323 ;
     RECT  71.712 6.037 74.136 6.325 ;
     RECT  17.376 6.323 19.128 6.371 ;
     RECT  9.456 4.931 9.72 6.373 ;
     RECT  43.968 6.035 46.872 6.517 ;
     RECT  48.192 6.323 48.216 6.517 ;
     RECT  61.8 5.747 62.112 6.565 ;
     RECT  54.144 5.989 54.168 6.611 ;
     RECT  66.672 5.557 68.232 6.613 ;
     RECT  43.968 6.517 48.216 6.659 ;
     RECT  34.224 5.891 35.64 6.661 ;
     RECT  36.72 6.037 37.224 6.661 ;
     RECT  42.624 6.035 42.936 6.707 ;
     RECT  26.928 6.037 29.712 6.805 ;
     RECT  59.856 6.323 59.88 6.851 ;
     RECT  11.136 6.229 16.056 6.853 ;
     RECT  24 6.323 24.696 6.853 ;
     RECT  34.224 6.661 37.224 6.899 ;
     RECT  26.64 6.805 29.712 6.901 ;
     RECT  31.392 5.891 32.76 7.045 ;
     RECT  21.648 6.179 22.344 7.091 ;
     RECT  25.872 6.901 29.712 7.091 ;
     RECT  61.536 6.565 62.112 7.093 ;
     RECT  31.392 7.045 32.904 7.187 ;
     RECT  69.984 5.795 70.008 7.189 ;
     RECT  20.208 6.323 20.328 7.285 ;
     RECT  69.792 7.189 70.008 7.285 ;
     RECT  71.088 6.325 74.136 7.285 ;
     RECT  34.224 6.899 36.744 7.331 ;
     RECT  11.136 6.853 16.248 7.333 ;
     RECT  17.376 6.371 18.912 7.333 ;
     RECT  20.208 7.285 20.568 7.333 ;
     RECT  21.648 7.091 21.864 7.333 ;
     RECT  66.624 6.613 68.232 7.333 ;
     RECT  34.224 7.331 35.208 7.379 ;
     RECT  61.44 7.093 62.112 7.379 ;
     RECT  38.496 5.795 39.144 7.381 ;
     RECT  40.2 5.795 41.208 7.381 ;
     RECT  50.688 6.323 52.44 7.381 ;
     RECT  63.84 7.333 63.864 7.381 ;
     RECT  77.472 6.035 78.312 7.381 ;
     RECT  79.632 6.323 79.752 7.381 ;
     RECT  83.232 5.029 83.712 7.381 ;
     RECT  20.208 7.333 21.864 7.427 ;
     RECT  66.624 7.333 68.376 7.427 ;
     RECT  69.792 7.285 74.136 7.427 ;
     RECT  20.208 7.427 21.672 7.475 ;
     RECT  26.64 7.091 29.712 7.475 ;
     RECT  42.624 6.707 42.648 7.475 ;
     RECT  56.4 6.323 57.336 7.475 ;
     RECT  43.968 6.659 47.112 7.619 ;
     RECT  48.192 6.659 48.216 7.619 ;
     RECT  50.688 7.381 53.016 7.619 ;
     RECT  9.36 6.373 9.72 7.621 ;
     RECT  11.136 7.333 18.912 7.621 ;
     RECT  20.208 7.475 20.712 7.715 ;
     RECT  1.872 6.229 8.376 7.765 ;
     RECT  9.36 7.621 18.912 7.765 ;
     RECT  60.336 7.381 60.36 7.861 ;
     RECT  71.616 7.427 73.272 7.907 ;
     RECT  38.496 7.381 41.208 7.909 ;
     RECT  49.296 6.323 49.32 7.909 ;
     RECT  65.616 5.747 65.64 7.909 ;
     RECT  34.464 7.379 35.208 7.955 ;
     RECT  49.056 7.909 49.32 7.955 ;
     RECT  28.992 7.475 29.712 8.003 ;
     RECT  44.016 7.619 47.112 8.003 ;
     RECT  51 7.619 53.016 8.003 ;
     RECT  66.672 7.427 68.376 8.003 ;
     RECT  69.792 7.427 69.816 8.005 ;
     RECT  63.744 7.381 63.864 8.101 ;
     RECT  64.992 7.909 65.64 8.101 ;
     RECT  71.616 7.907 72.912 8.195 ;
     RECT  68.928 8.005 69.816 8.243 ;
     RECT  23.904 6.853 24.696 8.245 ;
     RECT  36.72 7.331 36.744 8.291 ;
     RECT  31.392 7.187 32.76 8.293 ;
     RECT  66.672 8.003 67.704 8.339 ;
     RECT  0.816 7.957 0.84 8.437 ;
     RECT  1.872 7.765 18.912 8.437 ;
     RECT  34.608 7.955 35.208 8.437 ;
     RECT  56.4 7.475 56.712 8.437 ;
     RECT  0.816 8.437 18.912 8.483 ;
     RECT  76.464 7.621 76.488 8.531 ;
     RECT  11.712 8.483 18.912 8.579 ;
     RECT  26.928 7.475 27.912 8.579 ;
     RECT  38.496 7.909 42.456 8.579 ;
     RECT  44.016 8.003 44.472 8.579 ;
     RECT  51 8.003 52.44 8.579 ;
     RECT  82.368 7.381 83.712 8.627 ;
     RECT  60.336 7.861 60.408 8.725 ;
     RECT  61.536 7.379 62.112 8.725 ;
     RECT  49.056 7.955 49.128 8.771 ;
     RECT  83.232 8.627 83.712 8.771 ;
     RECT  29.4 8.003 29.712 8.821 ;
     RECT  51 8.579 52.056 8.821 ;
     RECT  39.792 8.579 42.456 8.867 ;
     RECT  63.744 8.101 65.64 8.867 ;
     RECT  29.4 8.821 29.832 8.963 ;
     RECT  60.336 8.725 62.112 8.965 ;
     RECT  23.904 8.245 24.792 9.013 ;
     RECT  44.016 8.579 44.376 9.013 ;
     RECT  23.904 9.013 25.08 9.059 ;
     RECT  69.792 8.243 69.816 9.061 ;
     RECT  20.304 7.715 20.712 9.109 ;
     RECT  31.392 8.293 32.808 9.109 ;
     RECT  45.504 8.003 47.112 9.109 ;
     RECT  69.792 9.061 70.008 9.109 ;
     RECT  20.304 9.109 21.192 9.155 ;
     RECT  27.072 8.579 27.912 9.155 ;
     RECT  63.744 8.867 65.016 9.155 ;
     RECT  54.624 8.341 54.648 9.205 ;
     RECT  11.712 8.579 14.424 9.251 ;
     RECT  31.392 9.109 32.904 9.251 ;
     RECT  54.624 9.205 55.272 9.251 ;
     RECT  60.096 8.965 62.112 9.251 ;
     RECT  63.744 9.155 64.104 9.251 ;
     RECT  77.472 7.381 79.752 9.251 ;
     RECT  29.4 8.963 29.712 9.253 ;
     RECT  43.92 9.013 44.376 9.347 ;
     RECT  27.264 9.155 27.912 9.397 ;
     RECT  28.896 9.253 29.712 9.397 ;
     RECT  34.608 8.437 35.544 9.443 ;
     RECT  60.384 9.251 62.112 9.539 ;
     RECT  16.032 8.579 18.912 9.589 ;
     RECT  77.472 9.251 79.656 9.731 ;
     RECT  27.264 9.397 29.712 9.779 ;
     RECT  45.504 9.109 47.928 9.779 ;
     RECT  69.792 9.109 70.728 9.779 ;
     RECT  20.544 9.155 21.192 9.875 ;
     RECT  38.496 8.579 38.52 9.925 ;
     RECT  40.2 8.867 42.456 9.925 ;
     RECT  60.816 9.539 62.112 9.925 ;
     RECT  67.008 8.339 67.704 9.925 ;
     RECT  11.712 9.251 14.088 9.971 ;
     RECT  43.92 9.347 44.04 9.973 ;
     RECT  50.112 8.821 52.056 10.067 ;
     RECT  0.816 8.483 10.68 10.069 ;
     RECT  11.712 9.971 13.656 10.069 ;
     RECT  16.032 9.589 19.464 10.115 ;
     RECT  16.368 10.115 19.464 10.165 ;
     RECT  20.544 9.875 20.712 10.165 ;
     RECT  34.704 9.443 35.544 10.165 ;
     RECT  56.4 8.437 56.808 10.165 ;
     RECT  0.816 10.069 13.656 10.213 ;
     RECT  38.496 9.925 42.456 10.213 ;
     RECT  69.984 9.779 70.728 10.595 ;
     RECT  73.92 9.541 73.944 10.643 ;
     RECT  34.704 10.165 36.264 10.789 ;
     RECT  55.248 9.251 55.272 10.789 ;
     RECT  56.4 10.165 57.24 10.789 ;
     RECT  38.256 10.213 42.456 10.883 ;
     RECT  66.144 9.925 67.704 10.883 ;
     RECT  68.928 10.117 68.952 10.883 ;
     RECT  0.192 10.213 13.656 10.931 ;
     RECT  54.576 10.789 55.272 10.981 ;
     RECT  69.984 10.595 70.008 11.123 ;
     RECT  15.36 10.213 15.384 11.125 ;
     RECT  16.368 10.165 20.712 11.125 ;
     RECT  49.104 8.771 49.128 11.125 ;
     RECT  50.688 10.067 52.056 11.125 ;
     RECT  9.456 10.931 13.656 11.171 ;
     RECT  67.104 10.883 67.704 11.221 ;
     RECT  11.856 11.171 13.656 11.269 ;
     RECT  64.08 9.251 64.104 11.317 ;
     RECT  11.856 11.269 14.136 11.365 ;
     RECT  15.36 11.125 20.712 11.365 ;
     RECT  31.392 9.251 31.896 11.365 ;
     RECT  50.688 11.125 52.248 11.365 ;
     RECT  43.488 9.973 44.04 11.411 ;
     RECT  60.816 9.925 62.712 11.411 ;
     RECT  50.64 11.365 52.248 11.413 ;
     RECT  53.712 10.981 55.272 11.413 ;
     RECT  34.224 10.789 36.264 11.459 ;
     RECT  45.504 9.779 47.112 11.459 ;
     RECT  77.52 9.731 79.656 11.459 ;
     RECT  50.64 11.413 55.272 11.509 ;
     RECT  38.496 10.883 42.456 11.555 ;
     RECT  59.04 10.453 59.064 11.651 ;
     RECT  77.52 11.459 79.272 11.699 ;
     RECT  44.016 11.411 44.04 11.701 ;
     RECT  33.072 11.461 33.096 11.797 ;
     RECT  50.64 11.509 55.32 11.843 ;
     RECT  44.016 11.701 44.328 11.891 ;
     RECT  0.192 10.931 8.424 11.893 ;
     RECT  9.456 11.171 10.872 11.893 ;
     RECT  37.248 9.253 37.272 11.893 ;
     RECT  37.248 11.893 37.416 11.939 ;
     RECT  22.752 11.365 22.776 11.941 ;
     RECT  24 9.059 25.08 11.941 ;
     RECT  81.888 11.365 81.912 11.941 ;
     RECT  83.28 8.771 83.712 11.941 ;
     RECT  74.976 10.645 75 12.035 ;
     RECT  33.072 11.797 33.192 12.181 ;
     RECT  34.224 11.459 35.544 12.181 ;
     RECT  71.76 8.195 72.912 12.181 ;
     RECT  11.856 11.365 21.432 12.227 ;
     RECT  39.792 11.555 42.456 12.227 ;
     RECT  63.936 11.317 64.104 12.323 ;
     RECT  27.312 9.779 29.712 12.371 ;
     RECT  50.64 11.843 53.064 12.371 ;
     RECT  60.816 11.411 62.112 12.373 ;
     RECT  11.856 12.227 21.144 12.467 ;
     RECT  37.392 11.939 37.416 12.469 ;
     RECT  38.496 11.555 38.52 12.469 ;
     RECT  27.888 12.371 29.712 12.517 ;
     RECT  30.912 11.365 31.896 12.517 ;
     RECT  71.76 12.181 73.512 12.517 ;
     RECT  22.752 11.941 26.088 12.563 ;
     RECT  63.936 12.323 63.96 12.563 ;
     RECT  17.424 12.467 21.144 12.611 ;
     RECT  76.224 9.013 76.248 12.611 ;
     RECT  0.192 11.893 10.872 12.613 ;
     RECT  11.856 12.467 16.392 12.613 ;
     RECT  27.888 12.517 31.896 12.613 ;
     RECT  33.072 12.181 35.544 12.613 ;
     RECT  22.752 12.563 22.776 12.659 ;
     RECT  27.888 12.613 35.544 12.755 ;
     RECT  23.856 12.563 26.088 12.757 ;
     RECT  54.576 11.843 55.32 12.757 ;
     RECT  56.4 10.789 57.624 12.757 ;
     RECT  37.392 12.469 38.52 12.805 ;
     RECT  81.888 11.941 83.712 12.805 ;
     RECT  81.36 12.805 83.712 12.853 ;
     RECT  17.568 12.611 21.144 12.899 ;
     RECT  23.856 12.757 26.424 12.899 ;
     RECT  54.576 12.757 58.008 12.899 ;
     RECT  23.856 12.899 26.328 12.995 ;
     RECT  33.168 12.755 35.544 12.997 ;
     RECT  33.168 12.997 35.592 13.045 ;
     RECT  51 12.371 53.064 13.045 ;
     RECT  77.568 11.699 79.272 13.045 ;
     RECT  24 12.995 26.328 13.091 ;
     RECT  33.168 13.045 35.688 13.091 ;
     RECT  60.384 12.373 62.112 13.091 ;
     RECT  71.52 12.517 73.512 13.283 ;
     RECT  33.936 13.091 35.688 13.331 ;
     RECT  54.576 12.899 57.624 13.331 ;
     RECT  74.688 13.093 74.712 13.379 ;
     RECT  0.192 12.613 16.392 13.429 ;
     RECT  51 13.045 53.592 13.429 ;
     RECT  54.576 13.331 57.528 13.429 ;
     RECT  39.792 12.227 40.776 13.525 ;
     RECT  0.192 13.429 16.44 13.573 ;
     RECT  17.568 12.899 21.096 13.573 ;
     RECT  34.32 13.331 35.688 13.619 ;
     RECT  37.392 12.805 38.76 13.621 ;
     RECT  39.792 13.525 41.064 13.621 ;
     RECT  45.6 11.459 47.112 13.621 ;
     RECT  51 13.429 57.528 13.667 ;
     RECT  58.704 13.333 58.728 13.667 ;
     RECT  51 13.667 55.32 13.715 ;
     RECT  67.104 11.221 67.8 13.715 ;
     RECT  37.392 13.621 41.064 13.859 ;
     RECT  53.04 13.715 55.32 13.859 ;
     RECT  22.608 12.853 22.632 13.909 ;
     RECT  34.8 13.619 35.688 14.005 ;
     RECT  48.24 11.125 49.128 14.005 ;
     RECT  63.408 13.045 63.432 14.005 ;
     RECT  38.496 13.859 41.064 14.101 ;
     RECT  42.432 12.227 42.456 14.101 ;
     RECT  38.496 14.101 42.456 14.147 ;
     RECT  0.192 13.573 21.096 14.197 ;
     RECT  22.608 13.909 22.92 14.197 ;
     RECT  27.888 12.755 31.896 14.197 ;
     RECT  60.912 13.091 62.112 14.197 ;
     RECT  63.408 14.005 63.912 14.197 ;
     RECT  0.144 14.197 21.096 14.245 ;
     RECT  22.512 14.197 22.92 14.245 ;
     RECT  44.016 11.891 44.04 14.389 ;
     RECT  77.568 13.045 79.464 14.389 ;
     RECT  27.744 14.197 31.896 14.435 ;
     RECT  48.24 14.005 49.8 14.435 ;
     RECT  24 13.091 25.176 14.485 ;
     RECT  26.304 13.091 26.328 14.485 ;
     RECT  49.776 14.435 49.8 14.485 ;
     RECT  51 13.715 51.864 14.485 ;
     RECT  71.76 13.283 73.512 14.485 ;
     RECT  48.24 14.435 48.648 14.531 ;
     RECT  77.568 14.389 79.8 14.533 ;
     RECT  60.912 14.197 63.912 14.771 ;
     RECT  45.36 13.621 47.112 14.773 ;
     RECT  48.24 14.531 48.264 14.773 ;
     RECT  56.4 13.667 57.528 14.773 ;
     RECT  71.76 14.485 74.136 14.773 ;
     RECT  76.8 14.533 79.8 14.773 ;
     RECT  80.832 12.853 83.712 14.773 ;
     RECT  0.144 14.245 22.92 14.821 ;
     RECT  24 14.485 26.328 14.821 ;
     RECT  0.144 14.821 26.328 14.867 ;
     RECT  45.36 14.773 48.264 14.867 ;
     RECT  0.144 14.867 25.944 14.915 ;
     RECT  53.04 13.859 53.4 14.915 ;
     RECT  76.8 14.773 83.712 14.915 ;
     RECT  33.12 14.197 33.144 14.917 ;
     RECT  33.072 14.917 33.144 15.013 ;
     RECT  27.744 14.435 31.848 15.061 ;
     RECT  65.904 14.965 65.928 15.061 ;
     RECT  67.104 13.715 67.704 15.061 ;
     RECT  65.904 15.061 67.704 15.107 ;
     RECT  83.232 14.915 83.712 15.155 ;
     RECT  59.664 14.917 59.688 15.157 ;
     RECT  76.8 14.915 81.912 15.157 ;
     RECT  33.072 15.013 33.24 15.251 ;
     RECT  59.664 15.157 60.648 15.253 ;
     RECT  39.696 14.147 42.456 15.347 ;
     RECT  63.792 14.771 63.912 15.395 ;
     RECT  0.144 14.915 21.672 15.443 ;
     RECT  38.496 14.147 38.52 15.443 ;
     RECT  54.528 13.859 55.32 15.443 ;
     RECT  27.36 15.061 31.848 15.445 ;
     RECT  33.072 15.251 33.096 15.445 ;
     RECT  75.84 15.157 81.912 15.491 ;
     RECT  21.456 15.443 21.672 15.731 ;
     RECT  66.336 15.107 67.704 15.731 ;
     RECT  77.568 15.491 81.912 15.779 ;
     RECT  34.8 14.005 35.832 15.829 ;
     RECT  22.656 14.915 25.944 16.019 ;
     RECT  39.696 15.347 42.312 16.019 ;
     RECT  61.8 14.771 62.664 16.019 ;
     RECT  70.08 14.773 70.104 16.021 ;
     RECT  53.376 14.915 53.4 16.117 ;
     RECT  27.36 15.445 33.096 16.211 ;
     RECT  49.776 14.485 51.864 16.261 ;
     RECT  52.896 16.117 53.4 16.261 ;
     RECT  49.776 16.261 53.4 16.307 ;
     RECT  0.144 15.443 19.848 16.309 ;
     RECT  24 16.019 25.944 16.309 ;
     RECT  83.4 15.155 83.712 16.309 ;
     RECT  34.8 15.829 35.88 16.355 ;
     RECT  37.392 13.859 37.416 16.357 ;
     RECT  54.528 15.443 54.6 16.357 ;
     RECT  22.656 16.019 22.824 16.403 ;
     RECT  45.36 14.867 47.928 16.403 ;
     RECT  70.08 16.021 70.728 16.549 ;
     RECT  71.76 14.773 74.376 16.549 ;
     RECT  21.456 15.731 21.48 16.595 ;
     RECT  27.36 16.211 32.52 16.595 ;
     RECT  40.032 16.019 42.312 16.595 ;
     RECT  75.84 15.491 75.864 16.595 ;
     RECT  59.28 15.253 60.648 16.643 ;
     RECT  43.92 14.389 44.04 16.645 ;
     RECT  49.776 16.307 52.68 16.645 ;
     RECT  63.792 15.395 63.816 16.645 ;
     RECT  70.08 16.549 74.376 16.691 ;
     RECT  53.712 16.357 54.6 16.693 ;
     RECT  27.696 16.595 32.52 16.787 ;
     RECT  53.712 16.693 54.744 16.789 ;
     RECT  27.696 16.787 27.912 16.835 ;
     RECT  45.36 16.403 47.448 16.835 ;
     RECT  49.248 16.645 52.68 16.931 ;
     RECT  77.568 15.779 81.816 16.933 ;
     RECT  36.96 16.357 37.416 16.981 ;
     RECT  61.8 16.019 62.112 17.077 ;
     RECT  36.912 16.981 37.416 17.123 ;
     RECT  56.4 14.773 57.576 17.123 ;
     RECT  59.712 16.643 60.648 17.123 ;
     RECT  60.624 17.123 60.648 17.125 ;
     RECT  61.8 17.077 62.376 17.125 ;
     RECT  24 16.309 26.136 17.171 ;
     RECT  27.888 16.835 27.912 17.171 ;
     RECT  71.76 16.691 74.376 17.365 ;
     RECT  29.4 16.787 32.52 17.413 ;
     RECT  70.08 16.691 70.728 17.413 ;
     RECT  43.44 16.645 44.04 17.509 ;
     RECT  47.088 16.835 47.448 17.509 ;
     RECT  34.8 16.355 35.832 17.605 ;
     RECT  45.36 16.835 45.912 17.605 ;
     RECT  50.736 16.931 52.68 17.605 ;
     RECT  53.712 16.789 55.08 17.605 ;
     RECT  69.6 17.413 70.728 17.605 ;
     RECT  71.76 17.365 75.288 17.605 ;
     RECT  76.368 17.077 76.392 17.605 ;
     RECT  42.288 16.595 42.312 17.651 ;
     RECT  21.648 16.981 21.672 17.653 ;
     RECT  24 17.171 25.656 17.653 ;
     RECT  40.032 16.595 41.016 17.653 ;
     RECT  22.656 16.403 22.68 17.699 ;
     RECT  77.568 16.933 82.152 17.747 ;
     RECT  60.624 17.125 62.376 17.795 ;
     RECT  39.36 17.653 41.016 17.989 ;
     RECT  29.4 17.413 32.664 18.181 ;
     RECT  34.224 17.605 35.832 18.181 ;
     RECT  66.336 15.731 67.512 18.181 ;
     RECT  69.024 17.605 70.728 18.181 ;
     RECT  66.336 18.181 70.728 18.227 ;
     RECT  83.28 16.309 83.712 18.227 ;
     RECT  66.336 18.227 70.68 18.275 ;
     RECT  23.904 17.653 25.656 18.323 ;
     RECT  71.76 17.605 76.392 18.323 ;
     RECT  64.992 16.501 65.016 18.419 ;
     RECT  77.568 17.747 82.104 18.421 ;
     RECT  43.296 17.509 44.04 18.469 ;
     RECT  45.216 17.605 45.912 18.469 ;
     RECT  56.4 17.123 57.48 18.517 ;
     RECT  43.296 18.469 45.912 18.565 ;
     RECT  59.28 18.181 59.304 18.613 ;
     RECT  50.736 17.605 55.32 18.707 ;
     RECT  39.264 17.989 41.016 18.709 ;
     RECT  39.264 18.709 41.064 18.757 ;
     RECT  58.704 18.613 59.304 18.803 ;
     RECT  25.632 18.323 25.656 18.851 ;
     RECT  74.688 18.323 76.392 18.851 ;
     RECT  0.096 16.309 19.848 18.853 ;
     RECT  74.88 18.851 76.392 18.899 ;
     RECT  28.08 18.709 28.104 18.949 ;
     RECT  29.28 18.181 35.832 18.995 ;
     RECT  39.264 18.757 41.448 18.995 ;
     RECT  23.904 18.323 24.312 19.045 ;
     RECT  61.104 17.795 62.376 19.093 ;
     RECT  33.312 18.995 35.832 19.139 ;
     RECT  66.336 18.275 69.624 19.139 ;
     RECT  66.336 19.139 67.512 19.187 ;
     RECT  37.392 17.123 37.416 19.237 ;
     RECT  42.96 18.565 45.912 19.237 ;
     RECT  20.88 17.653 21.672 19.283 ;
     RECT  71.76 18.323 73.224 19.283 ;
     RECT  68.88 19.139 69.624 19.285 ;
     RECT  70.656 18.275 70.68 19.285 ;
     RECT  77.52 18.421 82.104 19.285 ;
     RECT  68.88 19.285 70.68 19.331 ;
     RECT  29.28 18.995 31.848 19.379 ;
     RECT  50.736 18.707 53.064 19.379 ;
     RECT  68.88 19.331 69.72 19.379 ;
     RECT  59.28 18.803 59.304 19.427 ;
     RECT  63.552 16.645 63.816 19.427 ;
     RECT  74.88 18.899 75.816 19.427 ;
     RECT  23.136 19.045 24.312 19.475 ;
     RECT  47.088 17.509 47.88 19.523 ;
     RECT  54.144 18.707 55.32 19.523 ;
     RECT  27.696 18.949 28.104 19.525 ;
     RECT  29.28 19.379 31.608 19.525 ;
     RECT  61.104 19.093 62.52 19.667 ;
     RECT  69.168 19.379 69.72 19.715 ;
     RECT  74.88 19.427 75.336 19.715 ;
     RECT  33.504 19.139 35.832 19.717 ;
     RECT  23.904 19.475 24.312 19.765 ;
     RECT  21.072 19.283 21.672 19.813 ;
     RECT  49.248 16.931 49.272 19.813 ;
     RECT  50.736 19.379 51.312 19.813 ;
     RECT  61.587 19.667 62.52 19.813 ;
     RECT  0.048 18.853 19.848 19.859 ;
     RECT  39.36 18.995 41.448 19.859 ;
     RECT  75.216 19.715 75.336 19.907 ;
     RECT  33.504 19.717 36.216 19.909 ;
     RECT  37.296 19.237 37.608 19.909 ;
     RECT  23.904 19.765 24.792 20.003 ;
     RECT  33.504 19.909 37.608 20.003 ;
     RECT  69.168 19.715 69.624 20.051 ;
     RECT  27.696 19.525 31.608 20.099 ;
     RECT  66.672 19.187 67.512 20.147 ;
     RECT  24 20.003 24.792 20.149 ;
     RECT  56.4 18.517 57.624 20.293 ;
     RECT  34.08 20.003 37.608 20.387 ;
     RECT  24 20.149 24.888 20.435 ;
     RECT  0.192 19.859 19.848 20.483 ;
     RECT  56.4 20.293 58.44 20.485 ;
     RECT  42.96 19.237 46.056 20.531 ;
     RECT  28.272 20.099 31.608 20.579 ;
     RECT  61.587 19.813 62.808 20.579 ;
     RECT  72.048 19.283 73.224 20.579 ;
     RECT  47.088 19.523 47.592 20.677 ;
     RECT  21.072 19.813 21.816 20.819 ;
     RECT  72.048 20.579 72.912 20.867 ;
     RECT  63.792 19.427 63.816 20.869 ;
     RECT  77.184 19.285 82.104 20.869 ;
     RECT  52.656 19.379 53.064 20.917 ;
     RECT  40.08 19.859 41.448 20.965 ;
     RECT  21.792 20.819 21.816 21.061 ;
     RECT  24 20.435 24.789 21.061 ;
     RECT  39.36 20.965 41.448 21.061 ;
     RECT  56.4 20.485 58.68 21.061 ;
     RECT  23.232 21.061 24.789 21.107 ;
     RECT  29.4 20.579 31.608 21.109 ;
     RECT  38.448 21.061 41.448 21.109 ;
     RECT  52.416 20.917 53.064 21.109 ;
     RECT  54.144 19.523 55.272 21.109 ;
     RECT  63.168 20.869 63.816 21.155 ;
     RECT  69.6 20.051 69.624 21.155 ;
     RECT  29.4 21.109 31.752 21.251 ;
     RECT  43.296 20.531 46.056 21.251 ;
     RECT  34.08 20.387 36.792 21.253 ;
     RECT  33.936 21.253 36.792 21.299 ;
     RECT  60.096 21.301 60.12 21.349 ;
     RECT  21.792 21.061 22.248 21.395 ;
     RECT  33.936 21.299 35.208 21.445 ;
     RECT  43.296 21.251 45.912 21.541 ;
     RECT  33.648 21.445 35.208 21.637 ;
     RECT  0.24 20.483 19.848 21.683 ;
     RECT  43.056 21.541 45.912 21.683 ;
     RECT  47.088 20.677 47.88 21.683 ;
     RECT  49.248 19.813 51.312 21.683 ;
     RECT  70.992 20.485 71.016 21.683 ;
     RECT  36.432 21.299 36.792 21.731 ;
     RECT  52.416 21.109 55.272 21.731 ;
     RECT  77.04 20.869 82.104 21.779 ;
     RECT  28.272 20.579 28.296 21.781 ;
     RECT  67.2 20.147 67.512 21.925 ;
     RECT  47.088 21.683 47.544 21.973 ;
     RECT  60.096 21.349 60.312 22.165 ;
     RECT  43.056 21.683 44.136 22.211 ;
     RECT  21.792 21.395 21.816 22.213 ;
     RECT  29.4 21.251 31.704 22.213 ;
     RECT  56.4 21.061 58.776 22.259 ;
     RECT  77.04 21.779 82.056 22.309 ;
     RECT  83.4 18.227 83.712 22.405 ;
     RECT  26.784 22.117 26.808 22.453 ;
     RECT  27.888 21.781 28.296 22.453 ;
     RECT  26.784 22.453 28.296 22.499 ;
     RECT  50.688 21.683 51.312 22.499 ;
     RECT  20.976 22.213 21.816 22.595 ;
     RECT  36.768 21.731 36.792 22.597 ;
     RECT  23.235 21.107 24.789 22.693 ;
     RECT  52.656 21.731 55.272 22.693 ;
     RECT  29.4 22.213 31.944 22.739 ;
     RECT  38.448 21.109 42.072 22.739 ;
     RECT  43.488 22.211 44.136 22.739 ;
     RECT  40.2 22.739 42.072 22.741 ;
     RECT  47.04 21.973 47.544 22.741 ;
     RECT  49.248 21.683 49.272 22.741 ;
     RECT  75.216 19.907 75.24 22.741 ;
     RECT  73.968 22.741 75.24 22.787 ;
     RECT  83.4 22.405 83.832 22.787 ;
     RECT  29.4 22.739 31.704 22.883 ;
     RECT  56.4 22.259 58.584 23.269 ;
     RECT  59.808 22.165 60.312 23.269 ;
     RECT  66.96 21.925 67.512 23.269 ;
     RECT  33.024 21.637 35.208 23.317 ;
     RECT  36.768 22.597 37.368 23.317 ;
     RECT  45.504 21.683 45.912 23.317 ;
     RECT  46.944 22.741 47.544 23.317 ;
     RECT  65.856 22.789 65.88 23.363 ;
     RECT  27.072 22.499 28.296 23.411 ;
     RECT  33.024 23.317 37.368 23.411 ;
     RECT  33.024 23.411 35.928 23.507 ;
     RECT  49.248 22.741 49.368 23.701 ;
     RECT  51 22.499 51.312 23.701 ;
     RECT  38.448 22.739 38.472 23.845 ;
     RECT  76.944 22.309 82.056 23.987 ;
     RECT  29.4 22.883 31.656 24.037 ;
     RECT  27.072 23.411 28.2 24.131 ;
     RECT  40.2 22.741 42.168 24.131 ;
     RECT  23.235 22.693 25.704 24.227 ;
     RECT  52.464 22.693 55.272 24.323 ;
     RECT  29.4 24.037 31.752 24.373 ;
     RECT  33.648 23.507 35.928 24.419 ;
     RECT  38.448 23.845 38.808 24.419 ;
     RECT  44.112 22.739 44.136 24.419 ;
     RECT  21.792 22.595 21.816 24.469 ;
     RECT  29.28 24.373 31.752 24.469 ;
     RECT  45.504 23.317 47.544 24.469 ;
     RECT  49.248 23.701 51.312 24.469 ;
     RECT  34.08 24.419 35.928 24.515 ;
     RECT  72.336 20.867 72.912 24.517 ;
     RECT  73.968 22.787 74.904 24.517 ;
     RECT  0.24 21.683 19.704 24.563 ;
     RECT  76.944 23.987 81.96 24.563 ;
     RECT  27.216 24.131 28.2 24.565 ;
     RECT  29.232 24.469 31.752 24.565 ;
     RECT  56.4 23.269 60.312 24.611 ;
     RECT  69.456 21.205 69.48 24.611 ;
     RECT  37.056 23.411 37.368 24.613 ;
     RECT  0.384 24.563 19.704 24.661 ;
     RECT  34.08 24.515 35.352 24.851 ;
     RECT  38.784 24.419 38.808 24.899 ;
     RECT  0.384 24.661 20.424 24.947 ;
     RECT  36.864 24.613 37.368 24.995 ;
     RECT  44.064 24.469 44.088 25.045 ;
     RECT  60.096 24.611 60.312 25.045 ;
     RECT  61.587 20.579 62.112 25.045 ;
     RECT  65.52 24.997 65.544 25.045 ;
     RECT  72.336 24.517 74.904 25.091 ;
     RECT  27.216 24.565 31.752 25.139 ;
     RECT  45.504 24.469 51.312 25.139 ;
     RECT  34.08 24.851 35.256 25.187 ;
     RECT  76.944 24.563 81.864 25.283 ;
     RECT  27.888 25.139 31.752 25.285 ;
     RECT  40.2 24.131 41.88 25.285 ;
     RECT  23.235 24.227 25.32 25.475 ;
     RECT  27.888 25.285 32.664 25.571 ;
     RECT  37.344 24.995 37.368 25.621 ;
     RECT  60.096 25.045 62.112 25.669 ;
     RECT  56.4 24.611 58.92 25.717 ;
     RECT  59.904 25.669 62.112 25.717 ;
     RECT  65.232 25.045 65.544 25.763 ;
     RECT  40.2 25.285 42.552 25.765 ;
     RECT  49.248 25.139 51.312 25.765 ;
     RECT  65.52 25.763 65.544 25.907 ;
     RECT  45.504 25.139 47.64 25.909 ;
     RECT  29.4 25.571 32.664 25.957 ;
     RECT  40.08 25.765 42.552 26.003 ;
     RECT  0.384 24.947 19.608 26.005 ;
     RECT  49.248 25.765 51.48 26.051 ;
     RECT  43.92 25.045 44.088 26.149 ;
     RECT  52.464 24.323 54.984 26.149 ;
     RECT  56.4 25.717 62.112 26.149 ;
     RECT  45.216 25.909 47.64 26.195 ;
     RECT  23.235 25.475 24.789 26.197 ;
     RECT  45.216 26.195 47.544 26.243 ;
     RECT  56.064 26.149 62.112 26.243 ;
     RECT  72.336 25.091 72.912 26.243 ;
     RECT  37.344 25.621 37.416 26.483 ;
     RECT  21.792 24.469 22.056 26.485 ;
     RECT  29.4 25.957 32.904 26.533 ;
     RECT  34.08 25.187 35.112 26.533 ;
     RECT  20.976 26.485 22.056 26.627 ;
     RECT  56.064 26.243 60.312 26.627 ;
     RECT  27.888 25.571 28.296 26.629 ;
     RECT  70.704 26.293 70.728 26.675 ;
     RECT  45.216 26.243 46.968 26.677 ;
     RECT  37.344 26.483 37.368 26.725 ;
     RECT  0.336 26.005 19.608 26.819 ;
     RECT  23.136 26.197 24.789 26.819 ;
     RECT  43.872 26.149 44.088 26.819 ;
     RECT  76.944 25.283 81.72 26.821 ;
     RECT  0.336 26.819 19.272 26.867 ;
     RECT  56.4 26.627 60.312 27.299 ;
     RECT  66.96 23.269 67.896 27.301 ;
     RECT  49.248 26.051 51.312 27.443 ;
     RECT  37.296 26.725 37.368 27.587 ;
     RECT  73.968 25.091 74.904 27.731 ;
     RECT  0.336 26.867 18.912 27.877 ;
     RECT  38.496 25.765 38.52 27.877 ;
     RECT  40.08 26.003 42.264 27.877 ;
     RECT  45.168 26.677 46.968 27.877 ;
     RECT  74.208 27.731 74.904 27.877 ;
     RECT  57.888 27.299 60.312 27.925 ;
     RECT  61.587 26.243 62.112 27.925 ;
     RECT  74.208 27.877 75.24 27.925 ;
     RECT  76.32 26.821 81.72 27.925 ;
     RECT  0.336 27.877 19.848 28.019 ;
     RECT  45.168 27.877 47.352 28.115 ;
     RECT  26.64 27.157 26.664 28.163 ;
     RECT  52.416 26.149 54.984 28.163 ;
     RECT  21.84 26.627 22.056 28.165 ;
     RECT  27.888 26.629 28.344 28.211 ;
     RECT  45.216 28.115 47.352 28.213 ;
     RECT  28.032 28.211 28.344 28.261 ;
     RECT  29.4 26.533 35.112 28.261 ;
     RECT  21.696 28.165 22.056 28.307 ;
     RECT  74.208 27.925 81.72 28.355 ;
     RECT  70.8 28.213 70.824 28.357 ;
     RECT  37.344 27.587 37.368 28.405 ;
     RECT  38.496 27.877 42.264 28.405 ;
     RECT  28.032 28.261 35.112 28.451 ;
     RECT  37.344 28.405 42.264 28.451 ;
     RECT  57.888 27.925 62.112 28.451 ;
     RECT  52.464 28.163 54.984 28.499 ;
     RECT  70.704 28.357 70.824 28.499 ;
     RECT  37.584 28.451 42.264 28.547 ;
     RECT  0.336 28.019 13.512 28.595 ;
     RECT  14.544 28.019 19.848 28.595 ;
     RECT  14.88 28.595 19.848 28.645 ;
     RECT  64.992 28.453 65.016 28.693 ;
     RECT  66.96 27.301 67.992 28.741 ;
     RECT  66.672 28.741 67.992 28.787 ;
     RECT  64.8 28.693 65.016 28.835 ;
     RECT  66.672 28.787 67.512 28.837 ;
     RECT  29.4 28.451 35.112 28.979 ;
     RECT  31.056 28.979 35.112 28.981 ;
     RECT  36.144 27.877 36.168 28.981 ;
     RECT  44.064 26.819 44.088 29.029 ;
     RECT  45.216 28.213 48.12 29.029 ;
     RECT  49.584 27.443 51.312 29.029 ;
     RECT  64.992 28.835 65.016 29.029 ;
     RECT  66.576 28.837 67.512 29.029 ;
     RECT  58.56 28.451 62.112 29.075 ;
     RECT  74.496 28.355 81.72 29.123 ;
     RECT  14.88 28.645 20.52 29.171 ;
     RECT  29.4 28.979 30.024 29.171 ;
     RECT  31.056 28.981 36.168 29.171 ;
     RECT  58.56 29.075 58.632 29.171 ;
     RECT  38.496 28.547 42.264 29.221 ;
     RECT  43.68 29.029 44.088 29.221 ;
     RECT  31.056 29.171 35.544 29.267 ;
     RECT  64.992 29.029 67.512 29.267 ;
     RECT  45.216 29.029 51.312 29.315 ;
     RECT  28.032 28.451 28.344 29.413 ;
     RECT  29.4 29.171 29.712 29.413 ;
     RECT  14.88 29.171 18.912 29.555 ;
     RECT  31.056 29.267 31.416 29.555 ;
     RECT  26.736 28.213 26.76 29.605 ;
     RECT  63.168 21.155 63.192 29.605 ;
     RECT  65.856 29.267 67.512 29.651 ;
     RECT  14.88 29.555 16.248 29.699 ;
     RECT  59.856 29.075 62.112 29.795 ;
     RECT  56.4 27.299 56.712 29.797 ;
     RECT  26.352 29.605 26.808 29.843 ;
     RECT  66.576 29.651 67.512 29.941 ;
     RECT  54.96 28.499 54.984 30.035 ;
     RECT  66.576 29.941 67.752 30.037 ;
     RECT  76.032 29.123 81.72 30.083 ;
     RECT  76.032 30.083 76.2 30.085 ;
     RECT  63.168 29.605 63.768 30.131 ;
     RECT  74.496 29.123 74.52 30.131 ;
     RECT  52.464 28.499 53.448 30.133 ;
     RECT  52.464 30.133 54.888 30.179 ;
     RECT  77.232 30.083 81.72 30.179 ;
     RECT  23.235 26.819 24.789 30.181 ;
     RECT  45.6 29.315 51.312 30.275 ;
     RECT  70.08 29.557 70.104 30.275 ;
     RECT  77.328 30.179 81.72 30.275 ;
     RECT  48.672 30.275 51.312 30.371 ;
     RECT  38.496 29.221 44.088 30.419 ;
     RECT  15.408 29.699 16.248 30.565 ;
     RECT  17.664 29.555 18.912 30.659 ;
     RECT  75.504 30.085 76.2 30.659 ;
     RECT  32.784 29.267 35.544 30.707 ;
     RECT  83.4 22.787 83.712 30.757 ;
     RECT  58.56 29.171 58.584 30.803 ;
     RECT  59.904 29.795 62.112 30.803 ;
     RECT  71.184 30.085 71.208 30.805 ;
     RECT  72.48 26.243 72.912 30.805 ;
     RECT  38.688 30.419 44.088 30.851 ;
     RECT  66.576 30.037 67.944 30.851 ;
     RECT  77.328 30.275 81.48 30.851 ;
     RECT  0.336 28.595 11.832 30.997 ;
     RECT  12.816 28.595 13.512 30.997 ;
     RECT  20.496 29.171 20.52 30.997 ;
     RECT  21.84 28.307 22.056 30.997 ;
     RECT  31.392 29.555 31.416 30.997 ;
     RECT  32.784 30.707 35.112 30.997 ;
     RECT  71.184 30.805 72.912 30.997 ;
     RECT  82.608 30.757 83.712 31.091 ;
     RECT  18.6 30.659 18.912 31.093 ;
     RECT  20.496 30.997 22.056 31.093 ;
     RECT  23.235 30.181 25.08 31.093 ;
     RECT  71.184 30.997 73.032 31.187 ;
     RECT  20.496 31.093 25.08 31.235 ;
     RECT  49.44 30.371 51.312 31.333 ;
     RECT  77.328 30.851 81.336 31.333 ;
     RECT  0.336 30.997 13.512 31.379 ;
     RECT  20.496 31.235 22.056 31.379 ;
     RECT  54.048 30.179 54.888 31.379 ;
     RECT  56.4 29.797 57.24 31.379 ;
     RECT  58.272 31.093 58.296 31.379 ;
     RECT  37.248 30.373 37.272 31.381 ;
     RECT  12.576 31.379 13.512 31.427 ;
     RECT  23.232 31.235 25.08 31.427 ;
     RECT  71.184 31.187 72.912 31.427 ;
     RECT  28.032 29.413 29.712 31.429 ;
     RECT  15.408 30.565 16.584 31.475 ;
     RECT  60 30.803 62.112 31.475 ;
     RECT  76.56 31.333 81.336 31.475 ;
     RECT  18.6 31.093 19.032 31.523 ;
     RECT  61.488 31.475 62.112 31.619 ;
     RECT  54.048 31.379 54.072 31.667 ;
     RECT  32.496 30.997 35.112 31.765 ;
     RECT  36.288 31.381 37.272 31.765 ;
     RECT  48.96 31.333 51.312 31.765 ;
     RECT  52.464 30.179 52.92 31.765 ;
     RECT  26.352 29.843 26.376 31.813 ;
     RECT  32.496 31.765 37.272 31.861 ;
     RECT  38.688 30.851 42.744 31.861 ;
     RECT  48.96 31.765 52.92 31.907 ;
     RECT  32.496 31.861 42.744 31.955 ;
     RECT  52.464 31.907 52.92 31.955 ;
     RECT  66.576 30.851 67.8 31.955 ;
     RECT  71.712 31.427 72.912 31.955 ;
     RECT  52.896 31.955 52.92 31.957 ;
     RECT  54 31.813 54.024 31.957 ;
     RECT  52.896 31.957 54.024 32.003 ;
     RECT  26.352 31.813 26.808 32.005 ;
     RECT  67.2 31.955 67.8 32.051 ;
     RECT  44.064 30.851 44.088 32.195 ;
     RECT  56.4 31.379 56.808 32.195 ;
     RECT  45.6 30.275 46.92 32.245 ;
     RECT  60 31.475 60.024 32.245 ;
     RECT  26.352 32.005 26.904 32.291 ;
     RECT  36.384 31.955 42.744 32.291 ;
     RECT  61.632 31.619 62.112 32.293 ;
     RECT  63.168 30.131 63.192 32.293 ;
     RECT  39.552 32.291 42.744 32.339 ;
     RECT  23.232 31.427 24.888 32.437 ;
     RECT  30.72 30.997 31.416 32.437 ;
     RECT  32.496 31.955 35.352 32.437 ;
     RECT  56.4 32.195 56.712 32.437 ;
     RECT  59.664 32.245 60.024 32.437 ;
     RECT  22.992 32.437 24.888 32.483 ;
     RECT  42.192 32.339 42.744 32.483 ;
     RECT  83.4 31.091 83.712 32.485 ;
     RECT  77.28 31.475 81.336 32.531 ;
     RECT  27.984 31.429 29.712 32.533 ;
     RECT  82.752 32.485 83.712 32.533 ;
     RECT  30.72 32.437 35.352 32.579 ;
     RECT  82.752 32.533 83.832 32.677 ;
     RECT  59.616 32.437 60.024 32.725 ;
     RECT  61.632 32.293 63.192 32.725 ;
     RECT  15.648 31.475 16.584 32.771 ;
     RECT  75.504 30.659 75.528 32.773 ;
     RECT  82.656 32.677 83.832 32.773 ;
     RECT  75.504 32.773 75.72 32.869 ;
     RECT  81.936 32.773 83.832 32.915 ;
     RECT  18.6 31.523 18.912 32.965 ;
     RECT  20.544 31.379 21.864 33.011 ;
     RECT  82.656 32.915 83.832 33.011 ;
     RECT  53.568 32.003 54.024 33.013 ;
     RECT  58.032 32.917 58.056 33.013 ;
     RECT  77.28 32.531 80.952 33.013 ;
     RECT  48.96 31.907 51.432 33.059 ;
     RECT  75.504 32.869 75.816 33.059 ;
     RECT  49.44 33.059 51.432 33.155 ;
     RECT  72.6 31.955 72.912 33.157 ;
     RECT  59.616 32.725 63.192 33.203 ;
     RECT  76.992 33.013 80.952 33.253 ;
     RECT  83.4 33.011 83.832 33.299 ;
     RECT  0.336 31.379 11.112 33.301 ;
     RECT  27.936 32.533 29.712 33.397 ;
     RECT  30.72 32.579 33.288 33.397 ;
     RECT  52.512 33.013 54.024 33.397 ;
     RECT  27.936 33.397 33.288 33.539 ;
     RECT  69.792 33.013 69.816 33.637 ;
     RECT  15.648 32.771 15.672 33.683 ;
     RECT  26.352 32.291 26.376 33.683 ;
     RECT  27.936 33.539 33 33.683 ;
     RECT  36.384 32.291 37.848 33.683 ;
     RECT  45.6 32.245 47.064 33.685 ;
     RECT  37.584 33.683 37.848 33.779 ;
     RECT  44.544 33.541 44.568 33.829 ;
     RECT  56.208 32.437 56.712 33.829 ;
     RECT  57.696 33.013 58.056 33.829 ;
     RECT  56.208 33.829 58.056 33.923 ;
     RECT  76.944 33.253 80.952 33.925 ;
     RECT  68.976 33.637 69.816 33.971 ;
     RECT  0.336 33.301 11.88 33.973 ;
     RECT  13.2 31.427 13.512 33.973 ;
     RECT  42.192 32.483 42.552 34.021 ;
     RECT  72.6 33.157 73.032 34.021 ;
     RECT  20.544 33.011 21.192 34.069 ;
     RECT  72.6 34.021 73.32 34.069 ;
     RECT  75.504 33.059 75.528 34.069 ;
     RECT  14.832 33.877 14.856 34.115 ;
     RECT  52.512 33.397 54.12 34.117 ;
     RECT  42.192 34.021 42.888 34.163 ;
     RECT  52.464 34.117 54.12 34.163 ;
     RECT  27.936 33.683 30.84 34.165 ;
     RECT  72.336 34.069 73.32 34.165 ;
     RECT  74.64 34.069 75.528 34.165 ;
     RECT  34.416 32.579 35.352 34.213 ;
     RECT  36.384 33.683 36.408 34.213 ;
     RECT  72.336 34.165 75.528 34.307 ;
     RECT  45.6 33.685 47.976 34.355 ;
     RECT  72.336 34.307 72.912 34.357 ;
     RECT  56.304 33.923 58.056 34.403 ;
     RECT  71.376 34.357 72.912 34.403 ;
     RECT  17.184 34.405 17.208 34.549 ;
     RECT  12.912 33.973 13.512 34.597 ;
     RECT  59.616 33.203 62.952 34.597 ;
     RECT  24 32.483 24.888 34.645 ;
     RECT  34.416 34.213 36.408 34.645 ;
     RECT  39.552 32.339 41.208 34.645 ;
     RECT  42.192 34.163 42.696 34.645 ;
     RECT  17.088 34.549 17.208 34.691 ;
     RECT  0.288 33.973 11.88 34.741 ;
     RECT  27.6 34.165 30.84 34.741 ;
     RECT  32.496 33.683 33 34.741 ;
     RECT  34.08 34.645 36.408 34.741 ;
     RECT  12.912 34.597 14.136 34.787 ;
     RECT  24 34.645 25.464 34.787 ;
     RECT  32.496 34.741 36.408 34.787 ;
     RECT  71.376 34.403 71.4 34.787 ;
     RECT  34.8 34.787 36.408 34.883 ;
     RECT  45.6 34.355 47.256 34.883 ;
     RECT  17.088 34.691 17.112 34.931 ;
     RECT  47.136 34.883 47.256 35.027 ;
     RECT  0.24 34.741 11.88 35.173 ;
     RECT  12.912 34.787 13.512 35.173 ;
     RECT  49.44 33.155 51.312 35.219 ;
     RECT  84.912 33.541 84.936 35.219 ;
     RECT  56.4 34.403 58.056 35.221 ;
     RECT  14.784 35.173 14.952 35.315 ;
     RECT  39.552 34.645 42.696 35.317 ;
     RECT  74.064 34.307 74.088 35.317 ;
     RECT  43.872 33.829 44.568 35.363 ;
     RECT  52.464 34.163 52.536 35.363 ;
     RECT  39.504 35.317 42.696 35.413 ;
     RECT  72.6 34.403 72.912 35.413 ;
     RECT  74.016 35.317 74.088 35.413 ;
     RECT  53.664 34.163 54.12 35.459 ;
     RECT  75.408 34.307 75.528 35.461 ;
     RECT  76.944 33.925 81.384 35.461 ;
     RECT  27.168 34.741 30.84 35.653 ;
     RECT  32.496 34.787 33.816 35.653 ;
     RECT  14.784 35.315 14.808 35.747 ;
     RECT  59.424 34.597 62.952 35.747 ;
     RECT  27.168 35.653 33.816 35.795 ;
     RECT  54 35.459 54.12 35.845 ;
     RECT  72.6 35.413 74.088 35.893 ;
     RECT  75.408 35.461 81.384 35.893 ;
     RECT  52.464 35.363 52.488 35.941 ;
     RECT  72.6 35.893 81.384 35.989 ;
     RECT  20.304 34.069 21.192 36.275 ;
     RECT  45.6 34.883 45.912 36.277 ;
     RECT  67.2 32.051 67.512 36.277 ;
     RECT  27.168 35.795 30.84 36.371 ;
     RECT  0.24 35.173 13.512 36.373 ;
     RECT  45.6 36.277 46.2 36.419 ;
     RECT  47.28 35.605 47.304 36.515 ;
     RECT  72.384 35.989 81.384 36.515 ;
     RECT  39.504 35.413 42.792 36.517 ;
     RECT  54 35.845 55.08 36.563 ;
     RECT  60.384 35.747 62.952 36.563 ;
     RECT  32.496 35.795 33.816 36.757 ;
     RECT  32.112 36.757 33.816 36.805 ;
     RECT  36.384 34.883 36.408 36.947 ;
     RECT  56.4 35.221 58.296 36.949 ;
     RECT  49.824 35.219 51.312 36.997 ;
     RECT  52.416 35.941 52.488 36.997 ;
     RECT  60.624 36.563 62.952 36.997 ;
     RECT  67.2 36.277 67.608 36.997 ;
     RECT  72.384 36.515 74.04 36.997 ;
     RECT  76.992 36.515 81.384 36.997 ;
     RECT  34.8 34.883 35.352 37.091 ;
     RECT  49.824 36.997 52.488 37.091 ;
     RECT  28.416 36.371 30.84 37.093 ;
     RECT  31.824 36.805 33.816 37.093 ;
     RECT  27.168 36.371 27.288 37.139 ;
     RECT  72.144 36.997 74.04 37.139 ;
     RECT  56.4 36.949 58.68 37.235 ;
     RECT  18.48 32.965 18.912 37.333 ;
     RECT  24 34.787 24.984 37.429 ;
     RECT  26.016 36.853 26.04 37.429 ;
     RECT  27.264 37.139 27.288 37.429 ;
     RECT  54 36.563 54.936 37.475 ;
     RECT  50.4 37.091 52.488 37.571 ;
     RECT  0.192 36.373 13.512 37.573 ;
     RECT  37.584 33.779 37.608 37.573 ;
     RECT  69.792 33.971 69.816 37.573 ;
     RECT  66.384 36.997 67.608 37.619 ;
     RECT  45.6 36.419 46.056 37.715 ;
     RECT  76.992 36.997 81.48 37.715 ;
     RECT  36.192 37.285 36.36 37.859 ;
     RECT  47.52 36.901 47.544 37.859 ;
     RECT  72.144 37.139 73.272 37.861 ;
     RECT  75.408 36.515 75.528 37.861 ;
     RECT  49.248 37.669 49.272 37.955 ;
     RECT  66.048 37.669 66.072 37.955 ;
     RECT  54.576 37.475 54.936 38.005 ;
     RECT  56.4 37.235 58.632 38.005 ;
     RECT  16.8 37.381 16.824 38.053 ;
     RECT  60.624 36.997 63.864 38.149 ;
     RECT  15.936 38.053 16.824 38.339 ;
     RECT  14.832 38.245 14.856 38.435 ;
     RECT  59.76 38.149 63.864 38.437 ;
     RECT  74.688 37.861 75.528 38.579 ;
     RECT  76.992 37.715 81.384 38.629 ;
     RECT  37.536 37.573 37.608 38.675 ;
     RECT  20.304 36.275 20.328 38.677 ;
     RECT  59.76 38.437 63.912 38.677 ;
     RECT  76.944 38.629 81.384 38.771 ;
     RECT  27.264 37.429 27.432 38.773 ;
     RECT  28.416 37.093 33.816 38.773 ;
     RECT  27.264 38.773 33.816 38.819 ;
     RECT  38.592 36.517 42.792 38.819 ;
     RECT  54.576 38.005 58.632 38.963 ;
     RECT  71.76 37.861 73.272 39.011 ;
     RECT  59.76 38.677 64.488 39.013 ;
     RECT  76.992 38.771 81.384 39.013 ;
     RECT  0.192 37.573 13.848 39.157 ;
     RECT  20.304 38.677 20.856 39.395 ;
     RECT  59.472 39.013 64.488 39.395 ;
     RECT  59.472 39.395 63.912 39.443 ;
     RECT  24 37.429 26.04 39.491 ;
     RECT  47.76 38.773 47.784 39.493 ;
     RECT  67.2 37.619 67.608 39.493 ;
     RECT  41.856 38.819 42.6 39.539 ;
     RECT  66.432 39.493 67.608 39.589 ;
     RECT  41.856 39.539 42.408 39.635 ;
     RECT  47.472 39.493 47.784 39.637 ;
     RECT  50.4 37.571 52.44 39.637 ;
     RECT  50.4 39.637 52.776 39.733 ;
     RECT  74.688 38.579 75.288 39.733 ;
     RECT  76.992 39.013 81.48 39.733 ;
     RECT  59.472 39.443 63.576 39.779 ;
     RECT  26.016 39.491 26.04 39.781 ;
     RECT  27.264 38.819 27.72 39.781 ;
     RECT  28.8 38.819 33.816 39.829 ;
     RECT  34.8 37.091 35.112 39.829 ;
     RECT  36.48 39.253 36.504 39.877 ;
     RECT  37.584 38.675 37.608 39.877 ;
     RECT  72.384 39.011 73.272 39.877 ;
     RECT  74.448 39.733 75.288 39.877 ;
     RECT  76.944 39.733 81.48 39.877 ;
     RECT  28.8 39.829 35.112 39.973 ;
     RECT  36.48 39.877 37.608 39.973 ;
     RECT  28.8 39.973 37.608 40.019 ;
     RECT  16.272 38.339 16.824 40.021 ;
     RECT  28.8 40.019 35.544 40.067 ;
     RECT  26.016 39.781 27.72 40.309 ;
     RECT  28.8 40.067 30.264 40.309 ;
     RECT  72.384 39.877 75.288 40.355 ;
     RECT  44.544 35.363 44.568 40.357 ;
     RECT  31.68 40.067 35.544 40.403 ;
     RECT  54.576 38.963 58.152 40.403 ;
     RECT  37.392 40.019 37.608 40.405 ;
     RECT  38.592 38.819 40.872 40.405 ;
     RECT  44.448 40.357 44.568 40.405 ;
     RECT  66.336 39.589 67.608 40.405 ;
     RECT  24 39.491 24.984 40.499 ;
     RECT  66.336 40.405 68.136 40.595 ;
     RECT  69.792 37.573 70.296 40.645 ;
     RECT  50.256 39.733 52.776 40.693 ;
     RECT  33.792 40.403 35.544 40.835 ;
     RECT  54.912 40.403 58.152 40.835 ;
     RECT  44.16 40.405 44.568 40.837 ;
     RECT  45.6 37.715 46.008 40.837 ;
     RECT  44.16 40.837 46.008 40.883 ;
     RECT  69.648 40.645 70.296 40.931 ;
     RECT  74.688 40.355 75.288 40.931 ;
     RECT  69.744 40.931 70.296 40.979 ;
     RECT  70.272 40.979 70.296 40.981 ;
     RECT  75.264 40.931 75.288 41.029 ;
     RECT  76.416 39.877 81.48 41.029 ;
     RECT  18.24 37.333 18.912 41.075 ;
     RECT  26.016 40.309 30.264 41.075 ;
     RECT  28.944 41.075 30.264 41.077 ;
     RECT  31.68 40.403 32.76 41.077 ;
     RECT  34.8 40.835 35.544 41.123 ;
     RECT  54.912 40.835 57.816 41.123 ;
     RECT  59.472 39.779 62.952 41.171 ;
     RECT  75.264 41.029 81.48 41.171 ;
     RECT  20.304 39.395 20.328 41.173 ;
     RECT  28.944 41.077 32.76 41.219 ;
     RECT  37.392 40.405 40.872 41.315 ;
     RECT  20.304 41.173 20.424 41.411 ;
     RECT  55.296 41.123 57.816 41.411 ;
     RECT  31.68 41.219 32.76 41.413 ;
     RECT  33.792 40.835 33.816 41.413 ;
     RECT  44.16 40.883 45.912 41.509 ;
     RECT  38.592 41.315 40.872 41.651 ;
     RECT  47.472 39.637 47.832 41.651 ;
     RECT  76.416 41.171 81.48 41.651 ;
     RECT  50.256 40.693 53.592 41.749 ;
     RECT  22.992 32.483 23.016 41.797 ;
     RECT  24 40.499 24.696 41.797 ;
     RECT  39.936 41.651 40.872 41.893 ;
     RECT  42.144 39.635 42.408 41.893 ;
     RECT  43.872 41.509 45.912 41.893 ;
     RECT  50.112 41.749 53.592 41.939 ;
     RECT  43.872 41.893 46.2 42.035 ;
     RECT  18.6 41.075 18.912 42.037 ;
     RECT  70.272 40.981 70.776 42.083 ;
     RECT  64.944 40.981 64.968 42.131 ;
     RECT  26.016 41.075 27.912 42.133 ;
     RECT  28.944 41.219 30.264 42.133 ;
     RECT  31.68 41.413 33.816 42.227 ;
     RECT  59.472 41.171 59.496 42.227 ;
     RECT  26.016 42.133 30.264 42.275 ;
     RECT  22.992 41.797 24.696 42.325 ;
     RECT  26.016 42.275 28.392 42.325 ;
     RECT  37.392 41.315 37.608 42.467 ;
     RECT  55.344 41.411 57.816 42.467 ;
     RECT  83.4 33.299 83.712 42.517 ;
     RECT  22.992 42.325 28.392 42.563 ;
     RECT  39.936 41.893 42.408 42.563 ;
     RECT  76.416 41.651 81.432 42.563 ;
     RECT  78 42.563 81.432 42.661 ;
     RECT  34.8 41.123 35.112 42.709 ;
     RECT  60.624 41.171 62.952 42.709 ;
     RECT  78 42.661 81.768 42.709 ;
     RECT  83.184 42.517 83.712 42.709 ;
     RECT  18.24 42.037 18.912 42.803 ;
     RECT  43.872 42.035 45.912 42.851 ;
     RECT  75.264 41.171 75.288 42.947 ;
     RECT  52.416 41.939 53.592 42.995 ;
     RECT  70.272 42.083 70.584 43.043 ;
     RECT  48.912 40.837 48.936 43.045 ;
     RECT  52.416 42.995 52.776 43.139 ;
     RECT  29.4 42.275 30.264 43.141 ;
     RECT  22.992 42.563 24.696 43.189 ;
     RECT  52.608 43.139 52.776 43.331 ;
     RECT  50.112 41.939 51.312 43.379 ;
     RECT  20.304 41.411 20.328 43.381 ;
     RECT  33.792 42.227 33.816 43.381 ;
     RECT  34.8 42.709 35.832 43.381 ;
     RECT  33.792 43.381 35.832 43.427 ;
     RECT  18.6 42.803 18.912 43.573 ;
     RECT  19.92 43.381 20.328 43.573 ;
     RECT  38.592 41.651 38.616 43.573 ;
     RECT  39.936 42.563 40.872 43.573 ;
     RECT  59.808 42.709 62.952 43.573 ;
     RECT  42 42.563 42.408 43.667 ;
     RECT  42.384 43.667 42.408 43.813 ;
     RECT  72.384 40.355 73.272 43.813 ;
     RECT  75.024 42.997 75.048 43.813 ;
     RECT  26.016 42.563 28.392 43.859 ;
     RECT  34.464 43.427 35.832 43.859 ;
     RECT  59.808 43.573 63.816 43.859 ;
     RECT  59.808 43.859 63.144 43.861 ;
     RECT  31.68 42.227 32.76 43.909 ;
     RECT  38.592 43.573 40.872 43.909 ;
     RECT  18.6 43.573 20.328 43.955 ;
     RECT  38.592 43.909 40.92 43.955 ;
     RECT  59.232 43.861 63.144 44.003 ;
     RECT  59.232 44.003 59.256 44.099 ;
     RECT  60.288 44.003 63.144 44.099 ;
     RECT  76.416 42.563 77.016 44.195 ;
     RECT  29.4 43.141 30.36 44.243 ;
     RECT  26.736 43.859 28.392 44.389 ;
     RECT  29.4 44.243 30.264 44.389 ;
     RECT  70.56 43.043 70.584 44.389 ;
     RECT  15.936 40.021 16.824 44.437 ;
     RECT  37.584 42.467 37.608 44.437 ;
     RECT  40.2 43.955 40.92 44.437 ;
     RECT  42.384 43.813 43.128 44.437 ;
     RECT  72.384 43.813 75.048 44.437 ;
     RECT  47.808 41.651 47.832 44.483 ;
     RECT  48.912 43.045 49.128 44.483 ;
     RECT  50.88 43.379 51.312 44.579 ;
     RECT  34.464 43.859 35.208 44.581 ;
     RECT  20.88 44.101 20.952 44.675 ;
     RECT  37.536 44.437 37.608 44.675 ;
     RECT  40.2 44.437 40.968 44.675 ;
     RECT  22.656 43.189 24.696 44.677 ;
     RECT  65.232 44.389 65.256 44.677 ;
     RECT  42.384 44.437 43.224 44.723 ;
     RECT  71.904 44.437 75.048 44.725 ;
     RECT  76.416 44.195 76.44 44.725 ;
     RECT  52.752 43.331 52.776 44.773 ;
     RECT  70.368 44.389 70.584 44.773 ;
     RECT  71.904 44.725 76.44 44.773 ;
     RECT  65.232 44.677 65.832 44.819 ;
     RECT  0.192 39.157 14.184 44.869 ;
     RECT  40.2 44.675 40.872 44.915 ;
     RECT  52.368 44.773 52.776 44.915 ;
     RECT  22.656 44.677 25.56 44.917 ;
     RECT  37.584 44.675 37.608 44.917 ;
     RECT  38.592 43.955 39.048 44.917 ;
     RECT  43.104 44.723 43.224 44.963 ;
     RECT  0.144 44.869 14.184 44.965 ;
     RECT  15.648 44.437 16.824 44.965 ;
     RECT  18.6 43.955 19.896 44.965 ;
     RECT  44.736 42.851 45.912 44.965 ;
     RECT  67.2 40.595 68.136 45.013 ;
     RECT  33.744 44.581 35.208 45.059 ;
     RECT  37.584 44.917 39.048 45.059 ;
     RECT  49.008 44.483 49.128 45.059 ;
     RECT  0.096 44.965 16.824 45.061 ;
     RECT  65.232 44.819 65.688 45.155 ;
     RECT  0.048 45.061 16.824 45.157 ;
     RECT  18.48 44.965 19.896 45.157 ;
     RECT  20.928 44.675 20.952 45.157 ;
     RECT  49.104 45.059 49.128 45.253 ;
     RECT  40.2 44.915 40.824 45.395 ;
     RECT  55.344 42.467 57.336 45.395 ;
     RECT  20.928 45.157 21.24 45.491 ;
     RECT  67.2 45.013 68.712 45.493 ;
     RECT  33.744 45.059 33.768 45.539 ;
     RECT  22.224 44.917 25.56 45.541 ;
     RECT  26.736 44.389 30.264 45.541 ;
     RECT  47.424 44.581 47.448 45.541 ;
     RECT  47.424 45.541 47.88 45.587 ;
     RECT  52.464 44.915 52.776 45.587 ;
     RECT  31.584 43.909 32.76 45.589 ;
     RECT  0.048 45.157 19.896 45.635 ;
     RECT  22.224 45.541 30.264 45.635 ;
     RECT  43.2 44.963 43.224 45.635 ;
     RECT  49.104 45.253 49.416 45.635 ;
     RECT  55.344 45.395 57.096 45.635 ;
     RECT  70.368 44.773 76.44 45.635 ;
     RECT  60.624 44.099 63.144 45.683 ;
     RECT  34.8 45.059 35.208 45.731 ;
     RECT  71.808 45.635 76.44 45.733 ;
     RECT  78 42.709 83.712 45.733 ;
     RECT  54 45.541 54.024 45.829 ;
     RECT  55.344 45.635 57 45.829 ;
     RECT  34.8 45.731 35.112 46.069 ;
     RECT  51 44.579 51.312 46.069 ;
     RECT  52.464 45.587 52.488 46.069 ;
     RECT  37.632 45.059 38.664 46.115 ;
     RECT  67.2 45.493 69.048 46.117 ;
     RECT  70.368 45.635 70.584 46.117 ;
     RECT  65.472 45.155 65.688 46.165 ;
     RECT  47.856 45.587 47.88 46.211 ;
     RECT  64.992 46.165 65.688 46.211 ;
     RECT  67.2 46.117 70.584 46.213 ;
     RECT  44.208 44.965 45.912 46.259 ;
     RECT  71.808 45.733 83.712 46.259 ;
     RECT  37.632 46.115 37.752 46.307 ;
     RECT  60.624 45.683 62.112 46.405 ;
     RECT  20.928 45.491 20.952 46.501 ;
     RECT  0.048 45.635 14.664 46.645 ;
     RECT  15.648 45.635 19.896 46.645 ;
     RECT  22.656 45.635 30.264 46.645 ;
     RECT  31.584 45.589 32.808 46.645 ;
     RECT  40.2 45.395 40.512 46.645 ;
     RECT  36.48 44.725 36.504 46.691 ;
     RECT  66.672 46.213 70.584 46.691 ;
     RECT  22.656 46.645 32.808 46.787 ;
     RECT  49.392 45.635 49.416 46.787 ;
     RECT  54 45.829 57 46.787 ;
     RECT  63.12 45.683 63.144 46.787 ;
     RECT  66.672 46.691 69.048 46.787 ;
     RECT  71.808 46.259 73.224 46.787 ;
     RECT  74.352 46.259 83.712 46.787 ;
     RECT  40.2 46.645 40.728 46.837 ;
     RECT  74.352 46.787 78.504 46.883 ;
     RECT  20.928 46.501 21.048 46.979 ;
     RECT  38.784 46.789 38.808 46.979 ;
     RECT  54.624 46.787 57 47.075 ;
     RECT  37.728 46.307 37.752 47.125 ;
     RECT  37.728 47.125 37.944 47.171 ;
     RECT  64.992 46.211 65.496 47.173 ;
     RECT  55.344 47.075 57 47.219 ;
     RECT  40.2 46.837 40.92 47.269 ;
     RECT  44.736 46.259 45.912 47.269 ;
     RECT  55.44 47.219 57 47.269 ;
     RECT  72 46.787 73.224 47.269 ;
     RECT  74.352 46.883 75.24 47.269 ;
     RECT  34.656 46.069 35.112 47.317 ;
     RECT  76.224 46.883 78.312 47.363 ;
     RECT  0.048 46.645 19.896 47.365 ;
     RECT  27.84 46.787 32.808 47.413 ;
     RECT  34.656 47.317 35.208 47.459 ;
     RECT  22.656 46.787 26.76 47.555 ;
     RECT  59.808 46.405 62.112 47.651 ;
     RECT  44.256 47.269 45.912 47.699 ;
     RECT  70.032 46.691 70.584 47.797 ;
     RECT  26.736 47.555 26.76 47.845 ;
     RECT  27.84 47.413 33.432 47.845 ;
     RECT  39.216 47.269 40.92 47.845 ;
     RECT  44.256 47.699 44.28 47.845 ;
     RECT  61.8 47.651 62.112 47.845 ;
     RECT  67.2 46.787 69.048 47.845 ;
     RECT  70.032 47.797 70.872 47.845 ;
     RECT  72 47.269 75.24 47.845 ;
     RECT  43.92 47.845 44.28 47.891 ;
     RECT  26.736 47.845 33.432 47.939 ;
     RECT  34.8 47.459 35.208 47.939 ;
     RECT  39.216 47.845 41.784 47.939 ;
     RECT  36.432 47.317 36.456 47.987 ;
     RECT  79.488 46.787 83.712 48.229 ;
     RECT  67.2 47.845 75.24 48.277 ;
     RECT  76.224 47.363 76.44 48.277 ;
     RECT  39.216 47.939 40.512 48.371 ;
     RECT  37.92 47.171 37.944 48.421 ;
     RECT  51 46.069 52.488 48.421 ;
     RECT  77.76 47.363 78.312 48.421 ;
     RECT  58.128 46.261 58.152 48.469 ;
     RECT  77.568 48.421 78.312 48.469 ;
     RECT  79.488 48.229 83.832 48.469 ;
     RECT  46.992 47.749 47.016 48.707 ;
     RECT  51 48.421 53.448 48.707 ;
     RECT  67.2 48.277 76.44 48.755 ;
     RECT  37.872 48.421 37.944 48.805 ;
     RECT  64.992 47.173 65.736 48.805 ;
     RECT  67.2 48.755 68.376 48.805 ;
     RECT  52.464 48.707 53.448 48.901 ;
     RECT  58.128 48.469 58.248 48.901 ;
     RECT  58.032 48.901 58.248 48.947 ;
     RECT  26.736 47.939 27.72 48.949 ;
     RECT  28.752 47.939 30.072 48.949 ;
     RECT  55.44 47.269 57.048 48.949 ;
     RECT  58.032 48.947 58.056 48.949 ;
     RECT  61.8 47.845 62.616 48.949 ;
     RECT  26.736 48.949 30.072 48.995 ;
     RECT  59.808 47.651 60.648 48.995 ;
     RECT  22.656 47.555 25.56 48.997 ;
     RECT  40.2 48.371 40.512 48.997 ;
     RECT  41.52 47.939 41.784 48.997 ;
     RECT  45.6 47.699 45.912 48.997 ;
     RECT  37.008 48.805 37.944 49.043 ;
     RECT  52.464 48.901 54.168 49.043 ;
     RECT  77.568 48.469 83.832 49.043 ;
     RECT  59.808 48.995 59.832 49.045 ;
     RECT  61.8 48.949 62.808 49.045 ;
     RECT  61.584 49.045 62.808 49.091 ;
     RECT  22.608 48.997 25.56 49.187 ;
     RECT  55.44 48.949 58.056 49.187 ;
     RECT  59.136 49.045 59.832 49.235 ;
     RECT  31.2 47.939 33.432 49.237 ;
     RECT  34.8 47.939 35.112 49.237 ;
     RECT  69.36 48.755 76.44 49.283 ;
     RECT  48.96 49.045 48.984 49.331 ;
     RECT  43.92 47.891 43.944 49.333 ;
     RECT  44.928 48.997 45.912 49.333 ;
     RECT  43.92 49.333 45.912 49.379 ;
     RECT  75.936 49.283 76.44 49.475 ;
     RECT  64.944 48.805 68.376 49.477 ;
     RECT  77.568 49.043 83.712 49.571 ;
     RECT  22.656 49.187 25.56 49.619 ;
     RECT  26.736 48.995 29.712 49.715 ;
     RECT  64.032 49.477 68.376 49.765 ;
     RECT  69.36 49.283 74.952 49.765 ;
     RECT  22.656 49.619 24.6 49.811 ;
     RECT  40.2 48.997 41.784 49.861 ;
     RECT  47.04 49.765 47.064 49.861 ;
     RECT  46.944 49.861 47.064 49.907 ;
     RECT  40.2 49.861 42.072 50.005 ;
     RECT  59.808 49.235 59.832 50.005 ;
     RECT  26.736 49.715 27.72 50.101 ;
     RECT  44.112 49.379 45.912 50.101 ;
     RECT  46.944 49.907 46.968 50.101 ;
     RECT  52.464 49.043 53.064 50.101 ;
     RECT  54.144 49.043 54.168 50.101 ;
     RECT  44.112 50.101 46.968 50.147 ;
     RECT  52.464 50.101 54.168 50.147 ;
     RECT  59.808 50.005 59.976 50.147 ;
     RECT  31.2 49.237 35.112 50.149 ;
     RECT  37.872 49.043 37.944 50.149 ;
     RECT  55.44 49.187 57.624 50.195 ;
     RECT  64.032 49.765 74.952 50.195 ;
     RECT  39.504 50.005 42.072 50.245 ;
     RECT  0.048 47.365 20.424 50.291 ;
     RECT  21.6 49.573 21.624 50.291 ;
     RECT  64.944 50.195 74.952 50.291 ;
     RECT  37.872 50.149 38.184 50.339 ;
     RECT  69.216 50.291 74.952 50.339 ;
     RECT  76.368 49.475 76.44 50.339 ;
     RECT  64.944 50.291 68.136 50.387 ;
     RECT  44.112 50.147 46.872 50.579 ;
     RECT  26.688 50.101 27.72 50.629 ;
     RECT  0.048 50.291 20.184 50.675 ;
     RECT  22.656 49.811 24.408 50.675 ;
     RECT  59.808 50.147 59.832 50.677 ;
     RECT  70.704 50.339 74.952 50.723 ;
     RECT  23.328 50.675 24.408 50.771 ;
     RECT  61.584 49.091 62.664 50.771 ;
     RECT  70.704 50.723 73.272 50.771 ;
     RECT  31.2 50.149 35.688 50.819 ;
     RECT  39.216 50.245 42.072 50.819 ;
     RECT  61.584 50.771 62.232 50.819 ;
     RECT  64.944 50.387 64.968 50.819 ;
     RECT  74.352 50.723 74.952 50.819 ;
     RECT  55.536 50.195 57.624 51.109 ;
     RECT  51 48.707 51.312 51.157 ;
     RECT  52.464 50.147 53.208 51.157 ;
     RECT  59.232 50.677 59.832 51.205 ;
     RECT  19.92 50.675 20.184 51.251 ;
     RECT  25.92 50.629 27.72 51.253 ;
     RECT  28.752 49.715 29.712 51.253 ;
     RECT  49.344 50.341 49.368 51.253 ;
     RECT  51 51.157 53.208 51.253 ;
     RECT  0.048 50.675 18.912 51.347 ;
     RECT  61.8 50.819 62.232 51.347 ;
     RECT  66.288 50.387 68.136 51.347 ;
     RECT  69.216 50.339 69.432 51.347 ;
     RECT  74.928 50.819 74.952 51.349 ;
     RECT  76.416 50.339 76.44 51.349 ;
     RECT  25.92 51.253 29.712 51.395 ;
     RECT  55.536 51.109 57.816 51.443 ;
     RECT  0.144 51.347 18.912 51.491 ;
     RECT  77.712 49.571 83.712 51.491 ;
     RECT  31.584 50.819 35.688 51.493 ;
     RECT  42.048 50.819 42.072 51.635 ;
     RECT  20.16 51.251 20.184 51.637 ;
     RECT  0.144 51.491 14.184 51.683 ;
     RECT  49.344 51.253 53.208 51.827 ;
     RECT  74.928 51.349 76.44 51.827 ;
     RECT  37.872 50.339 37.896 51.829 ;
     RECT  39.216 50.819 41.064 51.829 ;
     RECT  61.8 51.347 62.112 51.829 ;
     RECT  31.584 51.493 36.072 51.875 ;
     RECT  20.16 51.637 20.328 51.923 ;
     RECT  23.616 50.771 24.408 51.923 ;
     RECT  56.4 51.443 57.816 51.923 ;
     RECT  59.232 51.205 60.024 51.923 ;
     RECT  70.752 50.771 73.272 51.923 ;
     RECT  72 51.923 73.272 51.973 ;
     RECT  49.344 51.827 52.872 52.211 ;
     RECT  77.904 51.491 83.712 52.211 ;
     RECT  20.16 51.923 20.28 52.213 ;
     RECT  15.648 51.491 18.912 52.259 ;
     RECT  70.752 51.923 70.776 52.261 ;
     RECT  61.296 51.829 62.112 52.309 ;
     RECT  44.112 50.579 44.136 52.405 ;
     RECT  67.104 51.347 68.136 52.405 ;
     RECT  72 51.973 73.56 52.453 ;
     RECT  49.344 52.211 49.368 52.499 ;
     RECT  75.216 51.827 76.44 52.501 ;
     RECT  29.4 51.395 29.712 52.549 ;
     RECT  43.92 52.405 44.136 52.595 ;
     RECT  59.52 51.923 60.024 52.693 ;
     RECT  33.072 51.875 36.072 52.739 ;
     RECT  51 52.211 52.872 52.739 ;
     RECT  22.416 52.405 22.44 52.741 ;
     RECT  23.616 51.923 24.312 52.741 ;
     RECT  0.24 51.683 14.184 52.885 ;
     RECT  69.216 51.347 69.24 52.933 ;
     RECT  70.368 52.261 70.776 52.933 ;
     RECT  72 52.453 74.232 52.933 ;
     RECT  61.296 52.309 62.232 52.979 ;
     RECT  69.216 52.933 74.232 52.979 ;
     RECT  22.416 52.741 24.312 52.981 ;
     RECT  25.92 51.395 28.296 52.981 ;
     RECT  29.4 52.549 30.312 52.981 ;
     RECT  31.584 51.875 31.992 52.981 ;
     RECT  61.8 52.979 62.232 52.981 ;
     RECT  77.904 52.211 81.672 53.027 ;
     RECT  52.464 52.739 52.872 53.075 ;
     RECT  71.424 52.979 73.56 53.075 ;
     RECT  20.016 52.213 20.28 53.077 ;
     RECT  22.416 52.981 24.696 53.171 ;
     RECT  16.032 52.259 18.912 53.221 ;
     RECT  59.52 52.693 60.216 53.267 ;
     RECT  20.016 53.077 20.568 53.269 ;
     RECT  33.888 52.739 36.072 53.269 ;
     RECT  25.92 52.981 31.992 53.317 ;
     RECT  55.344 52.981 55.368 53.317 ;
     RECT  16.032 53.221 19.032 53.365 ;
     RECT  23.616 53.171 24.696 53.365 ;
     RECT  25.92 53.317 32.856 53.365 ;
     RECT  59.52 53.267 59.832 53.365 ;
     RECT  81.36 53.027 81.672 53.365 ;
     RECT  33.888 53.269 36.696 53.411 ;
     RECT  77.904 53.027 79.992 53.411 ;
     RECT  77.904 53.411 79.944 53.413 ;
     RECT  20.016 53.269 20.856 53.509 ;
     RECT  22.416 53.171 22.584 53.509 ;
     RECT  37.872 51.829 41.064 53.509 ;
     RECT  20.016 53.509 22.584 53.555 ;
     RECT  23.616 53.365 32.856 53.555 ;
     RECT  37.872 53.509 41.64 53.555 ;
     RECT  55.056 53.317 55.368 53.557 ;
     RECT  75.216 52.501 76.632 53.557 ;
     RECT  77.616 53.413 79.944 53.557 ;
     RECT  31.584 53.555 32.856 53.603 ;
     RECT  37.872 53.555 40.512 53.603 ;
     RECT  61.8 52.981 62.76 53.603 ;
     RECT  64.944 52.405 64.968 53.603 ;
     RECT  33.888 53.411 36.072 53.651 ;
     RECT  0.24 52.885 14.712 53.699 ;
     RECT  31.968 53.603 32.856 53.795 ;
     RECT  43.92 52.595 43.944 54.035 ;
     RECT  25.92 53.555 30.312 54.083 ;
     RECT  47.904 52.981 47.928 54.083 ;
     RECT  23.616 53.555 24.552 54.131 ;
     RECT  58.752 53.365 59.832 54.179 ;
     RECT  0.24 53.699 14.424 54.227 ;
     RECT  66.144 52.405 68.136 54.325 ;
     RECT  0.24 54.227 11.4 54.419 ;
     RECT  12.48 54.227 14.424 54.419 ;
     RECT  33.888 53.651 35.448 54.467 ;
     RECT  15.888 53.365 19.032 54.515 ;
     RECT  65.568 54.325 68.136 54.611 ;
     RECT  39.264 53.603 40.512 54.661 ;
     RECT  41.616 53.555 41.64 54.661 ;
     RECT  45.6 50.579 46.872 54.661 ;
     RECT  69.216 52.979 70.392 54.661 ;
     RECT  72 53.075 73.56 54.661 ;
     RECT  54.384 53.557 55.368 54.707 ;
     RECT  0.24 54.419 0.36 54.755 ;
     RECT  56.4 51.923 57.288 54.755 ;
     RECT  75.216 53.557 79.944 54.755 ;
     RECT  69.216 54.661 73.752 54.853 ;
     RECT  75.216 54.755 79.896 54.853 ;
     RECT  55.056 54.707 55.368 54.995 ;
     RECT  25.92 54.083 29.712 55.187 ;
     RECT  58.752 54.179 58.776 55.237 ;
     RECT  59.808 54.179 59.832 55.237 ;
     RECT  1.392 54.419 11.4 55.283 ;
     RECT  25.92 55.187 27.912 55.283 ;
     RECT  69.216 54.853 79.896 55.283 ;
     RECT  61.8 53.603 62.112 55.285 ;
     RECT  63.744 55.141 63.768 55.285 ;
     RECT  9.696 55.283 11.4 55.331 ;
     RECT  33.888 54.467 35.352 55.331 ;
     RECT  70.128 55.283 79.896 55.427 ;
     RECT  37.872 53.603 38.04 55.429 ;
     RECT  39.216 54.661 40.512 55.477 ;
     RECT  41.568 54.661 41.64 55.477 ;
     RECT  81.36 53.365 82.008 55.525 ;
     RECT  0.24 54.755 0.264 55.571 ;
     RECT  37.056 55.429 38.04 55.619 ;
     RECT  9.744 55.331 11.4 55.669 ;
     RECT  12.528 54.419 14.424 55.669 ;
     RECT  24 54.131 24.552 55.669 ;
     RECT  25.92 55.283 27.72 55.669 ;
     RECT  45.6 54.661 47.304 55.669 ;
     RECT  65.568 54.611 65.592 55.669 ;
     RECT  20.016 53.555 21.48 55.717 ;
     RECT  22.56 53.555 22.584 55.717 ;
     RECT  38.016 55.619 38.04 55.717 ;
     RECT  70.368 55.427 79.896 55.811 ;
     RECT  31.2 55.189 31.224 55.813 ;
     RECT  32.256 53.795 32.856 55.813 ;
     RECT  56.4 54.755 57.24 55.813 ;
     RECT  58.56 55.237 58.776 55.813 ;
     RECT  81.264 55.525 82.008 55.813 ;
     RECT  67.104 54.611 68.136 55.861 ;
     RECT  31.2 55.813 32.856 55.907 ;
     RECT  48.432 54.997 48.456 55.907 ;
     RECT  52.464 53.075 52.824 55.907 ;
     RECT  55.344 54.995 55.368 55.907 ;
     RECT  70.416 55.811 79.896 55.907 ;
     RECT  20.016 55.717 22.584 55.955 ;
     RECT  61.8 55.285 63.768 55.955 ;
     RECT  75.408 55.907 79.896 55.955 ;
     RECT  45.024 55.669 47.304 56.003 ;
     RECT  75.408 55.955 75.432 56.003 ;
     RECT  9.744 55.669 14.424 56.053 ;
     RECT  15.984 54.515 19.032 56.053 ;
     RECT  1.392 55.283 8.664 56.291 ;
     RECT  43.728 54.085 43.752 56.293 ;
     RECT  43.728 56.293 44.472 56.339 ;
     RECT  67.104 55.861 68.376 56.341 ;
     RECT  21.024 55.955 22.584 56.387 ;
     RECT  52.512 55.907 52.824 56.389 ;
     RECT  33.984 55.331 35.112 56.437 ;
     RECT  31.2 55.907 32.328 56.483 ;
     RECT  61.8 55.955 62.856 56.483 ;
     RECT  59.808 55.237 59.976 56.485 ;
     RECT  9.744 56.053 14.904 56.531 ;
     RECT  59.808 56.485 60.12 56.531 ;
     RECT  65.376 55.669 65.592 56.531 ;
     RECT  1.632 56.291 8.664 56.581 ;
     RECT  9.744 56.531 10.872 56.581 ;
     RECT  76.416 55.955 79.896 56.627 ;
     RECT  52.512 56.389 52.872 56.723 ;
     RECT  51 52.739 51.312 56.725 ;
     RECT  70.416 55.907 74.136 56.819 ;
     RECT  38.016 55.717 38.184 56.869 ;
     RECT  39.216 55.477 41.64 56.869 ;
     RECT  11.952 56.531 14.904 56.965 ;
     RECT  15.936 56.053 19.032 56.965 ;
     RECT  76.416 56.627 79.752 56.965 ;
     RECT  45.504 56.003 47.304 57.011 ;
     RECT  60.096 56.531 60.12 57.013 ;
     RECT  11.952 56.965 19.032 57.059 ;
     RECT  29.04 55.187 29.712 57.059 ;
     RECT  31.44 56.483 32.328 57.059 ;
     RECT  76.368 56.965 79.752 57.059 ;
     RECT  20.016 55.955 20.04 57.107 ;
     RECT  76.368 57.059 76.632 57.107 ;
     RECT  56.4 55.813 58.776 57.155 ;
     RECT  76.368 57.107 76.392 57.205 ;
     RECT  44.448 56.339 44.472 57.299 ;
     RECT  29.4 57.059 29.712 57.301 ;
     RECT  55.104 57.157 55.128 57.395 ;
     RECT  50.16 56.725 51.312 57.445 ;
     RECT  61.8 56.483 62.112 57.541 ;
     RECT  65.376 56.531 65.4 57.541 ;
     RECT  21.024 56.387 21.672 57.589 ;
     RECT  29.4 57.301 30.36 57.589 ;
     RECT  66.912 56.341 68.376 57.589 ;
     RECT  45.6 57.011 47.304 57.635 ;
     RECT  66.912 57.589 69.048 57.635 ;
     RECT  13.056 57.059 18.912 57.683 ;
     RECT  33.6 56.437 35.112 57.875 ;
     RECT  50.16 57.445 51.72 57.875 ;
     RECT  71.424 56.819 74.136 57.875 ;
     RECT  51 57.875 51.72 57.973 ;
     RECT  52.704 56.723 52.872 57.973 ;
     RECT  58.752 57.155 58.776 57.973 ;
     RECT  60.096 57.013 60.552 57.973 ;
     RECT  58.752 57.973 60.552 58.019 ;
     RECT  67.104 57.635 69.048 58.019 ;
     RECT  21.024 57.589 21.96 58.117 ;
     RECT  24 55.669 27.72 58.117 ;
     RECT  29.4 57.589 31.032 58.117 ;
     RECT  64.8 57.541 65.4 58.117 ;
     RECT  81.264 55.813 82.104 58.117 ;
     RECT  83.232 52.211 83.712 58.117 ;
     RECT  38.016 56.869 41.64 58.163 ;
     RECT  59.232 58.019 60.552 58.163 ;
     RECT  70.416 56.819 70.44 58.163 ;
     RECT  56.4 57.155 57.24 58.211 ;
     RECT  75.408 57.205 76.392 58.259 ;
     RECT  13.056 57.683 14.76 58.355 ;
     RECT  71.424 57.875 73.752 58.403 ;
     RECT  1.632 56.581 10.872 58.451 ;
     RECT  5.904 58.451 10.872 58.501 ;
     RECT  11.952 57.059 11.976 58.501 ;
     RECT  13.056 58.355 13.512 58.501 ;
     RECT  15.744 57.683 18.912 58.595 ;
     RECT  81.264 58.117 83.712 58.595 ;
     RECT  32.256 57.059 32.328 58.597 ;
     RECT  14.496 58.355 14.76 58.645 ;
     RECT  15.744 58.595 16.344 58.645 ;
     RECT  17.424 58.595 18.912 58.645 ;
     RECT  61.8 57.541 62.664 58.645 ;
     RECT  5.904 58.501 11.976 58.691 ;
     RECT  14.496 58.645 16.344 58.691 ;
     RECT  24 58.117 31.032 58.691 ;
     RECT  81.408 58.595 83.712 58.691 ;
     RECT  9.696 58.691 11.976 58.739 ;
     RECT  34.272 57.875 35.112 58.739 ;
     RECT  39.264 58.163 41.64 58.787 ;
     RECT  43.632 57.541 43.656 58.837 ;
     RECT  81.408 58.691 82.2 58.979 ;
     RECT  32.256 58.597 32.472 59.027 ;
     RECT  38.016 58.163 38.04 59.027 ;
     RECT  61.8 58.645 63.144 59.027 ;
     RECT  34.704 58.739 35.112 59.029 ;
     RECT  76.368 58.259 76.392 59.075 ;
     RECT  17.424 58.645 19.416 59.219 ;
     RECT  34.704 59.029 36.696 59.221 ;
     RECT  51 57.973 52.872 59.221 ;
     RECT  56.4 58.211 56.712 59.221 ;
     RECT  72 58.403 73.752 59.221 ;
     RECT  5.904 58.691 8.568 59.267 ;
     RECT  20.976 58.117 21.96 59.267 ;
     RECT  1.632 58.451 4.824 59.315 ;
     RECT  9.696 58.739 11.736 59.315 ;
     RECT  17.424 59.219 17.448 59.315 ;
     RECT  43.632 58.837 44.472 59.315 ;
     RECT  45.6 57.635 46.872 59.315 ;
     RECT  67.104 58.019 68.136 59.315 ;
     RECT  72 59.221 74.04 59.315 ;
     RECT  78 57.059 79.752 59.315 ;
     RECT  2.4 59.315 3.336 59.363 ;
     RECT  64.8 58.117 65.88 59.363 ;
     RECT  6.048 59.267 8.568 59.411 ;
     RECT  20.976 59.267 21.528 59.459 ;
     RECT  12.96 58.501 13.512 59.557 ;
     RECT  14.496 58.691 15.96 59.557 ;
     RECT  83.232 58.691 83.712 59.603 ;
     RECT  34.704 59.221 37.08 59.651 ;
     RECT  12.96 59.557 15.96 59.699 ;
     RECT  39.264 58.787 40.512 59.701 ;
     RECT  41.568 58.787 41.64 59.701 ;
     RECT  9.696 59.315 9.96 59.747 ;
     RECT  64.8 59.363 65.4 59.747 ;
     RECT  9.936 59.747 9.96 59.795 ;
     RECT  50.88 59.221 52.872 59.797 ;
     RECT  38.64 59.701 40.512 59.843 ;
     RECT  24 58.691 30.264 59.845 ;
     RECT  59.232 58.163 60.264 59.845 ;
     RECT  4.8 59.315 4.824 59.891 ;
     RECT  20.976 59.459 21.144 59.891 ;
     RECT  65.376 59.747 65.4 59.891 ;
     RECT  67.2 59.315 68.136 59.891 ;
     RECT  78 59.315 79.656 59.891 ;
     RECT  23.376 59.845 30.264 59.989 ;
     RECT  34.704 59.651 35.112 59.989 ;
     RECT  50.88 59.797 53.016 59.989 ;
     RECT  12.96 59.699 14.712 60.035 ;
     RECT  50.688 59.989 53.016 60.035 ;
     RECT  59.184 59.845 60.264 60.035 ;
     RECT  23.376 59.989 30.792 60.131 ;
     RECT  83.28 59.603 83.712 60.131 ;
     RECT  70.08 59.029 70.104 60.229 ;
     RECT  23.376 60.131 30.264 60.323 ;
     RECT  45.6 59.315 46.632 60.325 ;
     RECT  52.368 60.035 53.016 60.325 ;
     RECT  78 59.891 78.552 60.373 ;
     RECT  14.496 60.035 14.712 60.419 ;
     RECT  77.376 60.373 78.552 60.419 ;
     RECT  81.792 58.979 82.2 60.419 ;
     RECT  39.264 59.843 40.512 60.467 ;
     RECT  63.12 59.027 63.144 60.515 ;
     RECT  80.736 59.797 80.76 60.515 ;
     RECT  81.792 60.419 81.816 60.515 ;
     RECT  6.768 59.411 8.568 60.563 ;
     RECT  23.376 60.323 29.712 60.563 ;
     RECT  33.84 59.989 35.112 60.563 ;
     RECT  23.376 60.563 24.696 60.611 ;
     RECT  25.68 60.563 29.712 60.611 ;
     RECT  41.568 59.701 41.688 60.613 ;
     RECT  25.68 60.611 27.576 60.659 ;
     RECT  39.312 60.467 40.512 60.661 ;
     RECT  41.568 60.613 42.312 60.661 ;
     RECT  23.376 60.611 24.6 60.803 ;
     RECT  67.2 59.891 68.088 60.803 ;
     RECT  6.864 60.563 8.568 60.851 ;
     RECT  15.744 59.699 15.96 60.851 ;
     RECT  34.704 60.563 35.112 60.851 ;
     RECT  39.312 60.661 42.312 60.851 ;
     RECT  72.6 59.315 74.04 60.851 ;
     RECT  6.864 60.851 8.112 60.947 ;
     RECT  79.536 59.891 79.656 60.947 ;
     RECT  50.688 60.035 51.312 60.949 ;
     RECT  56.4 59.221 57.384 60.949 ;
     RECT  49.824 60.949 51.312 61.043 ;
     RECT  70.08 60.229 70.344 61.043 ;
     RECT  36.432 59.651 37.08 61.091 ;
     RECT  39.312 60.851 41.688 61.091 ;
     RECT  11.184 59.315 11.736 61.139 ;
     RECT  26.112 60.659 27.576 61.187 ;
     RECT  23.808 60.803 24.6 61.235 ;
     RECT  39.888 61.091 41.688 61.235 ;
     RECT  41.616 61.235 41.688 61.379 ;
     RECT  79.632 60.947 79.656 61.379 ;
     RECT  15.744 60.851 15.816 61.475 ;
     RECT  18.48 59.219 19.416 61.571 ;
     RECT  21.12 59.891 21.144 61.571 ;
     RECT  52.368 60.325 53.16 61.571 ;
     RECT  11.712 61.139 11.736 61.619 ;
     RECT  37.056 61.091 37.08 61.619 ;
     RECT  44.448 59.315 44.472 61.619 ;
     RECT  52.368 61.571 52.44 61.619 ;
     RECT  59.184 60.035 59.88 61.619 ;
     RECT  65.52 60.949 65.544 61.619 ;
     RECT  74.016 60.851 74.04 61.619 ;
     RECT  77.376 60.419 78.312 61.619 ;
     RECT  55.392 61.525 55.416 61.763 ;
     RECT  26.112 61.187 26.136 61.859 ;
     RECT  27.552 61.187 27.576 61.859 ;
     RECT  15.792 61.475 15.816 61.907 ;
     RECT  23.808 61.235 24.504 61.907 ;
     RECT  45.6 60.325 46.776 61.907 ;
     RECT  49.824 61.043 49.848 61.907 ;
     RECT  7.2 60.947 8.112 62.003 ;
     RECT  32.448 59.027 32.472 62.003 ;
     RECT  41.616 61.379 41.64 62.003 ;
     RECT  14.688 60.419 14.712 62.195 ;
     RECT  22.656 60.949 22.68 62.195 ;
     RECT  24 61.907 24.504 62.195 ;
     RECT  28.848 60.611 29.712 62.195 ;
     RECT  39.888 61.235 40.512 62.195 ;
     RECT  52.368 61.619 52.392 62.195 ;
     RECT  56.4 60.949 57.528 62.195 ;
     RECT  70.08 61.043 70.104 62.195 ;
     RECT  18.48 61.571 18.912 62.243 ;
     RECT  59.184 61.619 59.208 62.243 ;
     RECT  2.4 59.363 2.712 62.379 ;
     RECT  7.8 62.003 8.112 62.379 ;
     RECT  13.2 60.035 13.512 62.379 ;
     RECT  18.6 62.243 18.912 62.379 ;
     RECT  24 62.195 24.312 62.379 ;
     RECT  29.4 62.195 29.712 62.379 ;
     RECT  34.8 60.851 35.112 62.379 ;
     RECT  40.2 62.195 40.512 62.379 ;
     RECT  45.6 61.907 45.912 62.379 ;
     RECT  51 61.043 51.312 62.379 ;
     RECT  56.4 62.195 56.712 62.379 ;
     RECT  61.8 59.027 62.112 62.379 ;
     RECT  67.2 60.803 67.512 62.379 ;
     RECT  72.6 60.851 72.912 62.379 ;
     RECT  78 61.619 78.312 62.379 ;
     RECT  83.4 60.131 83.712 62.379 ;
     RECT  2.592 62.379 2.712 62.393 ;
     RECT  7.992 62.379 8.112 62.393 ;
     RECT  13.392 62.379 13.512 62.393 ;
     RECT  18.792 62.379 18.912 62.393 ;
     RECT  24.192 62.379 24.312 62.393 ;
     RECT  29.592 62.379 29.712 62.393 ;
     RECT  34.992 62.379 35.112 62.393 ;
     RECT  40.392 62.379 40.512 62.393 ;
     RECT  45.792 62.379 45.912 62.393 ;
     RECT  51.192 62.379 51.312 62.393 ;
     RECT  56.592 62.379 56.712 62.393 ;
     RECT  61.992 62.379 62.112 62.393 ;
     RECT  67.392 62.379 67.512 62.393 ;
     RECT  72.792 62.379 72.912 62.393 ;
     RECT  78.192 62.379 78.312 62.393 ;
     RECT  83.592 62.379 83.712 62.393 ;
     RECT  22.728 2.245 24 3.349 ;
     RECT  27.912 2.245 29.4 3.443 ;
     RECT  51.312 2.245 52.32 4.501 ;
     RECT  52.344 2.245 53.376 2.821 ;
     RECT  26.184 2.677 27.264 3.443 ;
     RECT  18.912 2.725 20.016 2.867 ;
     RECT  24.312 2.773 25.44 5.125 ;
     RECT  13.608 2.821 14.64 3.059 ;
     RECT  18.912 2.867 20.16 2.869 ;
     RECT  19.08 2.869 20.16 5.029 ;
     RECT  13.608 3.059 15.408 3.587 ;
     RECT  8.112 3.061 9.456 5.221 ;
     RECT  11.496 3.107 12.48 4.019 ;
     RECT  35.112 3.109 36.576 4.067 ;
     RECT  36.6 3.109 37.632 3.349 ;
     RECT  20.568 3.157 21.648 4.117 ;
     RECT  21.672 3.157 22.704 4.979 ;
     RECT  73.032 3.203 74.112 6.037 ;
     RECT  26.184 3.443 29.4 3.925 ;
     RECT  58.92 3.445 59.952 4.019 ;
     RECT  31.416 3.541 32.64 4.021 ;
     RECT  32.664 3.541 34.128 4.213 ;
     RECT  39 3.541 40.08 4.693 ;
     RECT  13.608 3.587 15.456 3.829 ;
     RECT  46.152 3.637 47.664 3.925 ;
     RECT  9.96 3.733 11.472 3.925 ;
     RECT  75.768 3.733 77.232 3.829 ;
     RECT  37.656 3.827 38.688 5.123 ;
     RECT  14.424 3.829 15.456 6.181 ;
     RECT  75.768 3.829 77.136 5.555 ;
     RECT  79.224 3.877 80.64 4.261 ;
     RECT  9.96 3.925 11.136 4.547 ;
     RECT  27.096 3.925 29.4 4.117 ;
     RECT  11.496 4.019 13.2 5.029 ;
     RECT  15.96 4.019 16.152 4.067 ;
     RECT  59.808 4.019 59.952 4.115 ;
     RECT  15.48 4.067 16.152 4.453 ;
     RECT  35.112 4.067 37.056 4.595 ;
     RECT  59.808 4.115 59.976 5.125 ;
     RECT  67.512 4.115 67.752 5.557 ;
     RECT  27.096 4.117 28.464 4.501 ;
     RECT  79.224 4.261 80.4 5.077 ;
     RECT  15.48 4.453 17.28 4.933 ;
     RECT  17.304 4.453 18.336 4.645 ;
     RECT  27.288 4.501 28.464 5.797 ;
     RECT  42.936 4.501 44.448 4.741 ;
     RECT  9.96 4.547 11.472 4.931 ;
     RECT  42.768 4.547 42.912 5.749 ;
     RECT  35.112 4.595 37.632 5.077 ;
     RECT  5.112 4.645 6.48 4.981 ;
     RECT  6.504 4.645 7.68 5.171 ;
     RECT  42.936 4.741 44.112 5.365 ;
     RECT  49.32 4.837 50.496 5.267 ;
     RECT  64.44 4.837 65.472 4.883 ;
     RECT  63.624 4.883 65.472 5.125 ;
     RECT  9.72 4.931 11.472 6.229 ;
     RECT  15.48 4.933 16.992 5.221 ;
     RECT  21.672 4.979 23.328 5.171 ;
     RECT  11.496 5.029 13.104 5.077 ;
     RECT  19.128 5.029 20.16 5.795 ;
     RECT  11.736 5.077 13.104 5.893 ;
     RECT  35.208 5.077 37.632 5.123 ;
     RECT  79.368 5.077 80.4 5.747 ;
     RECT  35.208 5.123 38.688 5.509 ;
     RECT  59.808 5.125 59.856 5.509 ;
     RECT  59.88 5.125 59.976 5.413 ;
     RECT  63.624 5.125 64.8 5.267 ;
     RECT  5.736 5.171 7.68 5.269 ;
     RECT  21.672 5.171 22.344 5.749 ;
     RECT  53.016 5.171 53.064 5.989 ;
     RECT  78.312 5.219 79.344 6.323 ;
     RECT  8.376 5.221 9.456 6.373 ;
     RECT  16.008 5.221 16.992 5.509 ;
     RECT  65.64 5.221 66.672 6.613 ;
     RECT  46.872 5.267 48.192 6.517 ;
     RECT  49.32 5.267 50.688 7.619 ;
     RECT  5.736 5.269 6.864 6.229 ;
     RECT  70.68 5.365 71.712 5.603 ;
     RECT  59.88 5.413 60.96 5.555 ;
     RECT  35.64 5.509 38.688 5.605 ;
     RECT  61.536 5.555 61.8 6.565 ;
     RECT  70.104 5.603 71.712 5.795 ;
     RECT  35.64 5.605 38.496 5.845 ;
     RECT  16.056 5.651 17.04 6.323 ;
     RECT  25.464 5.747 26.928 6.323 ;
     RECT  79.368 5.747 79.752 5.845 ;
     RECT  41.208 5.749 42.624 7.475 ;
     RECT  19.128 5.795 20.208 6.371 ;
     RECT  39.144 5.795 40.2 7.381 ;
     RECT  70.008 5.795 71.712 6.325 ;
     RECT  27.336 5.797 28.464 6.037 ;
     RECT  35.64 5.845 37.2 6.037 ;
     RECT  37.224 5.845 38.496 6.899 ;
     RECT  32.76 5.891 34.224 7.045 ;
     RECT  11.736 5.893 12.816 6.229 ;
     RECT  53.016 5.989 54.144 6.323 ;
     RECT  42.936 6.035 43.968 6.707 ;
     RECT  35.64 6.037 36.72 6.661 ;
     RECT  20.568 6.179 21.648 6.323 ;
     RECT  9.72 6.229 11.136 7.621 ;
     RECT  16.056 6.323 17.376 6.853 ;
     RECT  20.328 6.323 21.648 7.285 ;
     RECT  24.696 6.323 26.928 6.805 ;
     RECT  48.216 6.323 49.296 7.619 ;
     RECT  52.44 6.323 54.144 6.611 ;
     RECT  78.312 6.323 79.632 7.381 ;
     RECT  70.008 6.325 71.088 7.285 ;
     RECT  18.912 6.371 20.208 7.715 ;
     RECT  8.376 6.373 9.36 7.765 ;
     RECT  52.44 6.611 53.016 7.381 ;
     RECT  65.64 6.613 66.624 7.427 ;
     RECT  47.112 6.659 48.192 7.619 ;
     RECT  42.648 6.707 43.968 7.475 ;
     RECT  24.696 6.805 26.64 6.901 ;
     RECT  16.248 6.853 17.376 7.333 ;
     RECT  24.696 6.901 25.872 7.091 ;
     RECT  32.904 7.045 34.224 7.187 ;
     RECT  24.696 7.091 24.792 8.245 ;
     RECT  32.76 7.187 34.224 7.379 ;
     RECT  20.568 7.285 21.648 7.333 ;
     RECT  35.208 7.331 36.72 8.291 ;
     RECT  68.376 7.333 69.792 8.003 ;
     RECT  32.76 7.379 32.808 8.293 ;
     RECT  61.44 7.379 61.536 7.381 ;
     RECT  60.36 7.381 61.536 7.861 ;
     RECT  65.64 7.427 66.672 8.339 ;
     RECT  27.912 7.475 28.992 8.003 ;
     RECT  41.208 7.475 43.968 7.619 ;
     RECT  56.712 7.475 56.808 8.437 ;
     RECT  41.208 7.619 44.016 7.909 ;
     RECT  47.112 7.619 49.296 7.909 ;
     RECT  49.32 7.619 51 7.955 ;
     RECT  76.488 7.621 77.472 8.531 ;
     RECT  18.912 7.715 20.304 9.155 ;
     RECT  60.408 7.861 61.536 8.725 ;
     RECT  42.456 7.909 44.016 9.013 ;
     RECT  47.112 7.909 49.056 8.771 ;
     RECT  63.864 7.909 64.992 8.101 ;
     RECT  49.128 7.955 51 8.821 ;
     RECT  0.84 7.957 1.872 8.437 ;
     RECT  27.912 8.003 29.4 9.253 ;
     RECT  44.472 8.003 45.504 8.579 ;
     RECT  67.704 8.003 69.792 8.005 ;
     RECT  67.704 8.005 68.928 8.243 ;
     RECT  71.616 8.195 71.76 9.109 ;
     RECT  35.208 8.291 35.544 8.437 ;
     RECT  65.64 8.339 67.008 8.867 ;
     RECT  10.68 8.483 11.712 10.069 ;
     RECT  76.464 8.531 77.472 9.013 ;
     RECT  38.52 8.579 39.792 8.867 ;
     RECT  44.376 8.579 45.504 9.347 ;
     RECT  47.112 8.771 49.104 9.109 ;
     RECT  49.128 8.821 50.112 10.067 ;
     RECT  38.52 8.867 40.2 9.925 ;
     RECT  65.016 8.867 67.008 9.155 ;
     RECT  42.456 9.013 43.92 9.973 ;
     RECT  76.248 9.013 77.472 9.731 ;
     RECT  47.928 9.109 49.104 9.779 ;
     RECT  70.728 9.109 71.76 10.595 ;
     RECT  18.912 9.155 20.544 9.589 ;
     RECT  66.144 9.155 67.008 9.925 ;
     RECT  55.272 9.205 56.4 11.509 ;
     RECT  14.088 9.251 14.424 9.971 ;
     RECT  63.744 9.251 64.08 9.925 ;
     RECT  27.912 9.253 28.896 9.397 ;
     RECT  37.272 9.253 38.496 10.213 ;
     RECT  44.04 9.347 45.504 11.459 ;
     RECT  34.608 9.443 34.704 10.789 ;
     RECT  72.912 9.541 73.92 10.643 ;
     RECT  19.464 9.589 20.544 10.165 ;
     RECT  76.248 9.731 77.52 11.699 ;
     RECT  47.112 9.779 49.104 11.125 ;
     RECT  69.792 9.779 69.984 10.117 ;
     RECT  20.712 9.875 21.192 11.365 ;
     RECT  62.712 9.925 64.08 11.317 ;
     RECT  13.656 9.971 14.424 10.213 ;
     RECT  42.456 9.973 43.488 11.411 ;
     RECT  49.128 10.067 50.688 11.365 ;
     RECT  16.032 10.115 16.368 10.213 ;
     RECT  67.704 10.117 68.928 10.883 ;
     RECT  68.952 10.117 69.984 10.883 ;
     RECT  36.264 10.165 37.248 11.459 ;
     RECT  13.656 10.213 15.36 11.269 ;
     RECT  15.384 10.213 16.368 11.125 ;
     RECT  37.272 10.213 38.256 10.883 ;
     RECT  75 10.645 76.224 12.035 ;
     RECT  57.624 10.789 59.04 11.651 ;
     RECT  37.272 10.883 38.496 11.893 ;
     RECT  67.704 10.883 67.8 11.221 ;
     RECT  8.424 10.931 9.456 11.893 ;
     RECT  47.112 11.125 48.24 14.773 ;
     RECT  52.248 11.125 53.712 11.413 ;
     RECT  10.872 11.171 11.856 12.613 ;
     RECT  14.136 11.269 15.36 11.365 ;
     RECT  62.712 11.317 63.936 11.411 ;
     RECT  21.432 11.365 22.752 12.227 ;
     RECT  22.776 11.365 24 11.941 ;
     RECT  29.712 11.365 30.912 12.517 ;
     RECT  49.128 11.365 50.64 12.371 ;
     RECT  81.912 11.365 83.28 11.941 ;
     RECT  44.04 11.459 45.6 11.701 ;
     RECT  31.896 11.461 33.072 12.613 ;
     RECT  33.096 11.461 34.224 11.797 ;
     RECT  55.32 11.509 56.4 12.757 ;
     RECT  38.52 11.555 39.792 12.805 ;
     RECT  57.624 11.651 58.008 12.757 ;
     RECT  76.248 11.699 77.568 12.611 ;
     RECT  44.328 11.701 45.6 11.891 ;
     RECT  33.192 11.797 34.224 12.181 ;
     RECT  53.064 11.843 54.576 13.045 ;
     RECT  37.416 11.893 38.496 12.469 ;
     RECT  26.088 11.941 27.312 12.371 ;
     RECT  21.144 12.227 22.752 12.659 ;
     RECT  40.776 12.227 42.432 13.525 ;
     RECT  26.088 12.371 27.888 12.757 ;
     RECT  16.392 12.467 17.424 12.611 ;
     RECT  22.776 12.563 23.856 12.659 ;
     RECT  16.392 12.611 17.568 13.429 ;
     RECT  21.144 12.659 23.856 12.853 ;
     RECT  31.896 12.755 33.168 13.091 ;
     RECT  26.424 12.757 27.888 12.899 ;
     RECT  38.76 12.805 39.792 13.621 ;
     RECT  21.144 12.853 22.608 12.899 ;
     RECT  22.632 12.853 23.856 12.995 ;
     RECT  21.096 12.899 22.608 14.197 ;
     RECT  26.328 12.899 27.888 14.197 ;
     RECT  57.624 12.899 58.008 13.331 ;
     RECT  22.632 12.995 24 13.909 ;
     RECT  53.592 13.045 54.576 13.429 ;
     RECT  62.112 13.045 63.408 14.197 ;
     RECT  79.464 13.045 80.832 14.389 ;
     RECT  25.176 13.091 26.304 14.485 ;
     RECT  31.896 13.091 33.936 13.331 ;
     RECT  73.512 13.093 74.688 13.379 ;
     RECT  31.896 13.331 34.32 13.619 ;
     RECT  57.528 13.331 58.008 13.333 ;
     RECT  57.528 13.333 58.704 13.667 ;
     RECT  73.512 13.379 74.376 14.485 ;
     RECT  16.44 13.429 17.568 13.573 ;
     RECT  41.064 13.525 42.432 14.101 ;
     RECT  31.896 13.619 33.24 14.197 ;
     RECT  44.04 13.621 45.36 17.605 ;
     RECT  55.32 13.667 56.4 15.443 ;
     RECT  57.528 13.667 57.576 14.773 ;
     RECT  51.864 13.715 53.04 14.915 ;
     RECT  37.416 13.859 38.496 15.443 ;
     RECT  53.4 13.859 54.528 16.307 ;
     RECT  22.92 13.909 24 14.821 ;
     RECT  49.8 14.005 51 14.485 ;
     RECT  38.52 14.147 39.696 15.443 ;
     RECT  21.096 14.197 22.512 14.245 ;
     RECT  26.328 14.197 27.744 14.867 ;
     RECT  31.896 14.197 33.12 14.435 ;
     RECT  33.144 14.197 33.24 15.013 ;
     RECT  42.456 14.389 43.92 15.347 ;
     RECT  79.8 14.389 80.832 14.773 ;
     RECT  31.848 14.435 33.12 14.917 ;
     RECT  48.648 14.435 49.776 14.531 ;
     RECT  74.136 14.485 74.376 14.773 ;
     RECT  48.264 14.531 49.776 14.867 ;
     RECT  60.912 14.771 61.8 14.917 ;
     RECT  62.664 14.771 63.792 16.019 ;
     RECT  25.944 14.867 27.744 15.061 ;
     RECT  21.672 14.915 22.656 15.731 ;
     RECT  51.864 14.915 53.376 16.117 ;
     RECT  81.912 14.915 83.232 15.155 ;
     RECT  31.848 14.917 33.072 15.445 ;
     RECT  59.688 14.917 61.8 15.157 ;
     RECT  65.928 14.965 67.104 15.061 ;
     RECT  25.944 15.061 27.36 16.309 ;
     RECT  65.904 15.107 66.336 16.501 ;
     RECT  81.912 15.155 83.4 15.779 ;
     RECT  60.648 15.157 61.8 17.125 ;
     RECT  74.376 15.157 75.84 16.595 ;
     RECT  42.312 15.347 43.92 16.645 ;
     RECT  63.816 15.395 63.912 16.501 ;
     RECT  54.6 15.443 56.4 16.693 ;
     RECT  21.48 15.731 22.656 16.595 ;
     RECT  81.816 15.779 83.4 16.309 ;
     RECT  35.88 15.829 37.392 16.355 ;
     RECT  22.824 16.019 24 16.403 ;
     RECT  62.112 16.019 63.792 16.645 ;
     RECT  70.728 16.021 71.76 16.549 ;
     RECT  51.864 16.117 52.896 16.261 ;
     RECT  32.52 16.211 32.664 17.413 ;
     RECT  52.68 16.307 54.528 16.357 ;
     RECT  26.136 16.309 27.36 16.595 ;
     RECT  81.816 16.309 83.28 16.933 ;
     RECT  35.832 16.355 37.392 16.357 ;
     RECT  35.832 16.357 36.96 16.981 ;
     RECT  52.68 16.357 53.712 17.605 ;
     RECT  22.68 16.403 24 17.653 ;
     RECT  47.448 16.403 47.928 16.645 ;
     RECT  63.816 16.501 64.992 18.419 ;
     RECT  65.016 16.501 66.336 18.419 ;
     RECT  21.456 16.595 22.656 16.981 ;
     RECT  41.016 16.595 42.288 17.651 ;
     RECT  74.376 16.595 75.864 17.077 ;
     RECT  42.312 16.645 43.44 17.509 ;
     RECT  47.448 16.645 49.248 17.509 ;
     RECT  62.112 16.645 63.552 17.077 ;
     RECT  70.728 16.691 71.76 18.227 ;
     RECT  54.744 16.693 56.4 16.789 ;
     RECT  27.912 16.787 29.4 17.171 ;
     RECT  55.08 16.789 56.4 17.605 ;
     RECT  45.912 16.835 47.088 19.237 ;
     RECT  49.272 16.931 50.736 19.813 ;
     RECT  82.152 16.933 83.28 17.747 ;
     RECT  21.456 16.981 21.648 17.653 ;
     RECT  21.672 16.981 22.656 17.699 ;
     RECT  35.832 16.981 36.912 17.123 ;
     RECT  62.376 17.077 63.552 19.093 ;
     RECT  74.376 17.077 76.368 17.365 ;
     RECT  76.392 17.077 77.568 18.421 ;
     RECT  57.48 17.123 57.576 18.517 ;
     RECT  29.28 17.171 29.4 18.181 ;
     RECT  75.288 17.365 76.368 17.605 ;
     RECT  42.312 17.509 43.296 17.651 ;
     RECT  47.88 17.509 49.248 19.523 ;
     RECT  44.04 17.605 45.216 18.469 ;
     RECT  55.32 17.605 56.4 19.523 ;
     RECT  67.512 17.605 69.024 18.181 ;
     RECT  41.016 17.651 43.296 18.565 ;
     RECT  19.848 17.653 20.88 19.283 ;
     RECT  22.68 17.653 23.904 17.699 ;
     RECT  21.672 17.699 23.904 19.045 ;
     RECT  82.104 17.747 83.28 18.227 ;
     RECT  70.68 18.227 71.76 19.283 ;
     RECT  82.104 18.227 83.4 21.779 ;
     RECT  69.624 18.275 70.656 19.285 ;
     RECT  24.312 18.323 25.632 18.851 ;
     RECT  73.224 18.323 74.688 18.851 ;
     RECT  76.392 18.421 77.52 18.899 ;
     RECT  41.016 18.565 42.96 18.709 ;
     RECT  57.624 18.613 58.704 18.803 ;
     RECT  53.064 18.707 54.144 21.109 ;
     RECT  28.104 18.709 29.28 19.525 ;
     RECT  41.064 18.709 42.96 18.757 ;
     RECT  41.448 18.757 42.96 20.531 ;
     RECT  57.624 18.803 59.28 19.427 ;
     RECT  24.312 18.851 24.888 19.765 ;
     RECT  75.816 18.899 77.52 19.285 ;
     RECT  31.848 18.995 33.312 19.139 ;
     RECT  21.672 19.045 23.136 19.475 ;
     RECT  62.52 19.093 63.552 19.427 ;
     RECT  67.512 19.139 68.88 19.379 ;
     RECT  35.832 19.237 37.296 19.717 ;
     RECT  46.056 19.237 47.088 21.251 ;
     RECT  19.848 19.283 21.072 20.819 ;
     RECT  70.68 19.283 72.048 19.331 ;
     RECT  75.816 19.285 77.184 19.427 ;
     RECT  69.72 19.331 72.048 19.715 ;
     RECT  51.312 19.379 52.656 20.917 ;
     RECT  57.624 19.427 58.68 20.293 ;
     RECT  62.52 19.427 63.792 19.813 ;
     RECT  77.04 19.427 77.184 20.869 ;
     RECT  21.672 19.475 21.816 19.813 ;
     RECT  47.592 19.523 49.248 20.677 ;
     RECT  55.272 19.523 56.4 24.323 ;
     RECT  69.624 19.715 72.048 20.485 ;
     RECT  36.216 19.717 37.296 19.909 ;
     RECT  24.792 19.765 24.888 20.149 ;
     RECT  62.808 19.813 63.792 20.579 ;
     RECT  39.36 19.859 40.08 20.965 ;
     RECT  23.904 20.003 24 21.061 ;
     RECT  33.648 20.003 34.08 21.253 ;
     RECT  69.456 20.051 69.6 21.155 ;
     RECT  58.44 20.293 58.68 20.485 ;
     RECT  69.624 20.485 70.992 21.155 ;
     RECT  71.016 20.485 72.048 20.867 ;
     RECT  41.448 20.531 43.296 21.109 ;
     RECT  28.296 20.579 29.4 23.411 ;
     RECT  62.112 20.579 63.792 20.869 ;
     RECT  47.88 20.677 49.248 21.683 ;
     RECT  19.848 20.819 21.792 21.683 ;
     RECT  71.016 20.867 72.336 21.683 ;
     RECT  62.112 20.869 63.168 32.293 ;
     RECT  51.312 20.917 52.416 21.731 ;
     RECT  22.248 21.061 23.232 21.107 ;
     RECT  22.248 21.107 23.235 21.395 ;
     RECT  42.072 21.109 43.296 21.541 ;
     RECT  69.456 21.155 70.992 21.205 ;
     RECT  69.48 21.205 70.992 21.683 ;
     RECT  31.704 21.251 31.752 21.637 ;
     RECT  45.912 21.251 47.088 21.973 ;
     RECT  33.648 21.253 33.936 21.445 ;
     RECT  35.208 21.299 36.432 21.731 ;
     RECT  58.776 21.301 60.096 22.165 ;
     RECT  60.12 21.301 61.587 21.349 ;
     RECT  60.312 21.349 61.587 25.045 ;
     RECT  21.816 21.395 23.235 24.469 ;
     RECT  42.072 21.541 43.056 22.211 ;
     RECT  31.704 21.637 33.024 22.213 ;
     RECT  19.704 21.683 21.792 22.213 ;
     RECT  44.136 21.683 45.504 24.419 ;
     RECT  49.272 21.683 50.688 22.499 ;
     RECT  51.312 21.731 52.656 22.693 ;
     RECT  82.056 21.779 83.4 23.987 ;
     RECT  45.912 21.973 47.04 22.741 ;
     RECT  26.808 22.117 27.888 22.453 ;
     RECT  58.776 22.165 59.808 22.259 ;
     RECT  42.072 22.211 43.488 22.739 ;
     RECT  19.704 22.213 20.976 22.595 ;
     RECT  31.944 22.213 33.024 22.739 ;
     RECT  58.584 22.259 59.808 23.269 ;
     RECT  26.784 22.499 27.072 22.693 ;
     RECT  49.272 22.499 51 22.741 ;
     RECT  37.368 22.597 38.448 24.419 ;
     RECT  25.704 22.693 27.072 24.131 ;
     RECT  51.312 22.693 52.464 25.765 ;
     RECT  31.704 22.739 33.024 22.883 ;
     RECT  38.472 22.739 40.2 23.845 ;
     RECT  42.072 22.739 42.168 22.741 ;
     RECT  45.912 22.741 46.944 23.317 ;
     RECT  49.368 22.741 51 23.701 ;
     RECT  72.912 22.741 73.968 24.517 ;
     RECT  65.88 22.789 66.96 23.363 ;
     RECT  31.656 22.883 33.024 23.507 ;
     RECT  28.2 23.411 29.4 24.373 ;
     RECT  35.928 23.411 37.056 24.515 ;
     RECT  31.656 23.507 31.752 24.037 ;
     RECT  38.808 23.845 40.2 24.899 ;
     RECT  81.96 23.987 83.4 24.563 ;
     RECT  25.704 24.131 27.216 24.227 ;
     RECT  41.88 24.131 42.168 25.285 ;
     RECT  54.984 24.323 56.4 26.149 ;
     RECT  28.2 24.373 29.28 24.469 ;
     RECT  33.648 24.419 34.08 25.285 ;
     RECT  37.368 24.419 38.784 24.899 ;
     RECT  44.112 24.419 45.504 24.469 ;
     RECT  22.056 24.469 23.235 26.197 ;
     RECT  28.2 24.469 29.232 24.565 ;
     RECT  44.088 24.469 45.504 25.909 ;
     RECT  35.352 24.515 37.056 24.613 ;
     RECT  0.336 24.563 0.384 26.005 ;
     RECT  58.92 24.611 60.096 25.669 ;
     RECT  35.352 24.613 36.864 24.851 ;
     RECT  20.424 24.661 21.792 24.947 ;
     RECT  37.368 24.899 38.52 25.621 ;
     RECT  40.08 24.899 40.2 25.765 ;
     RECT  65.544 24.997 66.96 25.907 ;
     RECT  72.912 25.091 73.968 27.731 ;
     RECT  32.664 25.285 34.08 25.957 ;
     RECT  42.552 25.285 43.92 26.003 ;
     RECT  28.296 25.571 29.4 26.629 ;
     RECT  37.416 25.621 38.52 25.765 ;
     RECT  58.92 25.669 59.904 25.717 ;
     RECT  37.416 25.765 38.496 26.483 ;
     RECT  51.48 25.765 52.464 26.051 ;
     RECT  44.088 25.909 45.216 26.677 ;
     RECT  32.904 25.957 34.08 26.533 ;
     RECT  43.872 26.003 43.92 26.149 ;
     RECT  51.312 26.051 52.464 26.149 ;
     RECT  51.312 26.149 52.416 28.163 ;
     RECT  54.984 26.149 56.064 26.627 ;
     RECT  22.056 26.197 23.136 26.819 ;
     RECT  60.312 26.243 61.587 27.925 ;
     RECT  37.368 26.483 38.496 28.405 ;
     RECT  19.608 26.485 20.976 26.627 ;
     RECT  19.608 26.627 19.848 26.819 ;
     RECT  54.984 26.627 56.4 30.035 ;
     RECT  28.344 26.629 29.4 28.261 ;
     RECT  44.088 26.677 45.168 28.115 ;
     RECT  19.272 26.819 19.848 26.867 ;
     RECT  22.056 26.819 23.235 31.093 ;
     RECT  74.904 26.821 76.32 27.877 ;
     RECT  18.912 26.867 19.848 27.877 ;
     RECT  26.664 27.157 27.888 28.163 ;
     RECT  56.712 27.299 57.888 28.451 ;
     RECT  49.248 27.443 49.584 28.213 ;
     RECT  37.296 27.587 37.344 27.877 ;
     RECT  72.912 27.731 74.208 28.355 ;
     RECT  35.112 27.877 36.144 28.981 ;
     RECT  36.168 27.877 37.344 28.451 ;
     RECT  75.24 27.877 76.32 27.925 ;
     RECT  13.512 28.019 14.544 28.595 ;
     RECT  44.088 28.115 45.216 29.315 ;
     RECT  26.64 28.163 27.888 28.211 ;
     RECT  51.312 28.163 52.464 31.765 ;
     RECT  26.64 28.211 28.032 28.213 ;
     RECT  26.64 28.213 26.736 29.605 ;
     RECT  26.76 28.213 28.032 29.605 ;
     RECT  48.12 28.213 49.584 29.029 ;
     RECT  21.696 28.307 21.84 28.645 ;
     RECT  28.344 28.451 29.4 29.413 ;
     RECT  36.168 28.451 37.584 28.547 ;
     RECT  56.712 28.451 58.56 29.797 ;
     RECT  53.448 28.499 54.96 30.035 ;
     RECT  11.832 28.595 12.816 30.997 ;
     RECT  13.512 28.595 14.88 29.699 ;
     RECT  20.52 28.645 21.84 30.997 ;
     RECT  67.512 28.787 67.944 29.941 ;
     RECT  30.024 28.979 31.056 29.171 ;
     RECT  42.264 29.029 43.68 29.221 ;
     RECT  58.632 29.075 59.856 29.171 ;
     RECT  74.52 29.123 76.032 30.085 ;
     RECT  29.712 29.171 31.056 29.555 ;
     RECT  58.584 29.171 59.856 29.795 ;
     RECT  31.416 29.267 32.784 30.997 ;
     RECT  44.088 29.315 45.6 32.195 ;
     RECT  16.248 29.555 17.664 30.565 ;
     RECT  29.712 29.555 31.392 30.997 ;
     RECT  26.808 29.605 28.032 29.843 ;
     RECT  58.584 29.795 59.904 30.803 ;
     RECT  57.24 29.797 58.56 30.803 ;
     RECT  67.752 29.941 67.944 30.037 ;
     RECT  53.448 30.035 56.4 30.133 ;
     RECT  76.2 30.083 77.232 30.179 ;
     RECT  70.104 30.085 71.184 30.275 ;
     RECT  71.208 30.085 72.48 30.805 ;
     RECT  74.52 30.085 75.504 30.131 ;
     RECT  54.888 30.133 56.4 31.379 ;
     RECT  52.92 30.179 54.048 31.667 ;
     RECT  76.2 30.179 77.328 30.659 ;
     RECT  25.08 30.181 26.352 31.427 ;
     RECT  81.48 30.275 81.72 30.757 ;
     RECT  48.96 30.371 49.44 31.333 ;
     RECT  37.272 30.373 38.496 30.419 ;
     RECT  37.272 30.419 38.688 31.861 ;
     RECT  16.584 30.565 17.664 30.659 ;
     RECT  75.528 30.659 77.328 31.333 ;
     RECT  35.112 30.707 35.544 31.381 ;
     RECT  81.48 30.757 82.608 30.851 ;
     RECT  57.24 30.803 60 31.093 ;
     RECT  42.744 30.851 44.064 32.195 ;
     RECT  81.336 30.851 82.608 31.091 ;
     RECT  29.712 30.997 30.72 33.397 ;
     RECT  31.416 30.997 32.496 32.437 ;
     RECT  81.336 31.091 83.4 32.485 ;
     RECT  19.032 31.093 20.496 31.379 ;
     RECT  57.24 31.093 58.272 31.379 ;
     RECT  58.296 31.093 60 31.379 ;
     RECT  22.056 31.235 23.232 31.379 ;
     RECT  75.528 31.333 76.56 31.475 ;
     RECT  11.112 31.379 12.576 31.427 ;
     RECT  19.032 31.379 20.544 31.523 ;
     RECT  21.864 31.379 23.232 32.437 ;
     RECT  56.208 31.379 56.4 32.437 ;
     RECT  59.616 31.379 60 32.245 ;
     RECT  35.112 31.381 36.288 31.765 ;
     RECT  24.888 31.427 26.352 33.683 ;
     RECT  60.024 31.475 61.488 31.619 ;
     RECT  75.528 31.475 77.28 32.773 ;
     RECT  60.024 31.619 61.632 32.725 ;
     RECT  52.92 31.667 54.024 31.813 ;
     RECT  26.808 31.813 27.984 32.005 ;
     RECT  52.92 31.813 54 31.957 ;
     RECT  51.432 31.907 52.464 31.955 ;
     RECT  35.352 31.955 36.384 34.213 ;
     RECT  51.432 31.955 52.896 32.003 ;
     RECT  51.432 32.003 53.568 33.013 ;
     RECT  26.904 32.005 27.984 32.291 ;
     RECT  44.544 32.195 45.6 33.541 ;
     RECT  56.712 32.195 56.808 32.917 ;
     RECT  59.616 32.245 59.664 32.437 ;
     RECT  27.936 32.291 27.984 32.533 ;
     RECT  41.208 32.339 42.192 34.645 ;
     RECT  21.864 32.437 22.992 33.011 ;
     RECT  23.016 32.483 24 41.797 ;
     RECT  42.552 32.483 42.744 33.829 ;
     RECT  81.336 32.485 82.752 32.531 ;
     RECT  80.952 32.531 82.752 32.677 ;
     RECT  33.288 32.579 34.416 33.539 ;
     RECT  80.952 32.677 82.656 32.773 ;
     RECT  75.72 32.773 77.28 32.869 ;
     RECT  80.952 32.773 81.936 32.915 ;
     RECT  75.816 32.869 77.28 33.013 ;
     RECT  80.952 32.915 82.656 33.011 ;
     RECT  56.712 32.917 58.032 33.013 ;
     RECT  80.952 33.011 81.384 33.925 ;
     RECT  51.432 33.013 52.512 33.155 ;
     RECT  56.712 33.013 57.696 33.829 ;
     RECT  75.816 33.013 76.992 33.059 ;
     RECT  48.96 33.059 49.44 33.685 ;
     RECT  75.528 33.059 76.992 33.253 ;
     RECT  51.312 33.155 52.512 34.117 ;
     RECT  75.528 33.253 76.944 35.461 ;
     RECT  83.712 33.299 83.832 33.541 ;
     RECT  11.88 33.301 13.2 33.973 ;
     RECT  33 33.539 34.416 34.645 ;
     RECT  44.568 33.541 45.6 40.837 ;
     RECT  83.712 33.541 84.912 35.219 ;
     RECT  67.512 33.637 68.976 33.971 ;
     RECT  24.888 33.683 25.464 34.645 ;
     RECT  36.408 33.683 37.584 36.947 ;
     RECT  47.976 33.685 49.44 34.355 ;
     RECT  42.552 33.829 43.872 34.021 ;
     RECT  13.512 33.877 14.832 34.115 ;
     RECT  11.88 33.973 12.912 35.173 ;
     RECT  42.888 34.021 43.872 34.163 ;
     RECT  18.912 34.069 20.304 43.381 ;
     RECT  73.32 34.069 74.64 34.165 ;
     RECT  13.512 34.115 14.856 34.597 ;
     RECT  51.312 34.117 52.464 35.941 ;
     RECT  42.696 34.163 43.872 35.363 ;
     RECT  52.536 34.163 53.664 35.363 ;
     RECT  72.912 34.307 74.064 35.317 ;
     RECT  74.088 34.307 75.408 35.893 ;
     RECT  47.256 34.355 47.304 35.027 ;
     RECT  56.304 34.403 56.4 35.845 ;
     RECT  71.4 34.403 72.6 34.787 ;
     RECT  17.208 34.405 18.48 34.691 ;
     RECT  14.136 34.597 14.856 34.787 ;
     RECT  58.056 34.597 59.424 35.221 ;
     RECT  33 34.645 34.08 34.741 ;
     RECT  17.112 34.691 18.48 34.931 ;
     RECT  13.512 34.787 14.856 35.173 ;
     RECT  33.816 34.787 34.8 39.829 ;
     RECT  72.384 34.787 72.6 35.989 ;
     RECT  35.352 34.883 36.384 36.947 ;
     RECT  45.912 34.883 47.136 35.027 ;
     RECT  45.912 35.027 47.304 35.605 ;
     RECT  13.512 35.173 14.784 35.747 ;
     RECT  58.296 35.221 59.424 35.747 ;
     RECT  72.912 35.317 74.016 35.413 ;
     RECT  42.696 35.363 42.792 35.413 ;
     RECT  52.488 35.363 53.664 35.459 ;
     RECT  52.488 35.459 54 37.475 ;
     RECT  45.912 35.605 47.28 36.277 ;
     RECT  58.296 35.747 58.68 36.949 ;
     RECT  30.84 35.795 32.496 36.757 ;
     RECT  55.08 35.845 56.4 36.563 ;
     RECT  51.312 35.941 52.416 36.997 ;
     RECT  46.2 36.277 47.28 36.419 ;
     RECT  27.288 36.371 28.416 37.429 ;
     RECT  46.056 36.419 47.28 36.515 ;
     RECT  46.056 36.515 47.304 36.901 ;
     RECT  74.04 36.515 75.408 37.139 ;
     RECT  75.528 36.515 76.992 38.579 ;
     RECT  37.608 36.517 38.592 40.405 ;
     RECT  54.936 36.563 56.4 38.005 ;
     RECT  30.84 36.757 32.112 36.805 ;
     RECT  30.84 36.805 31.824 37.093 ;
     RECT  24.984 36.853 26.016 37.429 ;
     RECT  26.04 36.853 27.168 37.139 ;
     RECT  46.056 36.901 47.52 37.715 ;
     RECT  35.352 36.947 37.584 37.091 ;
     RECT  35.112 37.091 37.584 37.285 ;
     RECT  49.824 37.091 50.4 37.669 ;
     RECT  26.04 37.139 27.264 39.781 ;
     RECT  73.272 37.139 75.408 37.861 ;
     RECT  58.632 37.235 58.68 38.149 ;
     RECT  35.112 37.285 36.192 37.859 ;
     RECT  36.36 37.285 37.584 37.573 ;
     RECT  16.824 37.381 18.24 41.075 ;
     RECT  27.432 37.429 28.416 38.773 ;
     RECT  36.36 37.573 37.536 37.859 ;
     RECT  66.384 37.619 67.2 37.669 ;
     RECT  49.272 37.669 50.4 37.955 ;
     RECT  66.072 37.669 67.2 37.955 ;
     RECT  46.008 37.715 47.52 37.859 ;
     RECT  81.384 37.715 81.48 39.013 ;
     RECT  35.112 37.859 37.536 38.675 ;
     RECT  70.296 37.861 71.76 39.011 ;
     RECT  73.272 37.861 74.688 39.733 ;
     RECT  58.632 38.149 59.76 38.963 ;
     RECT  13.848 38.245 14.832 38.435 ;
     RECT  14.856 38.245 15.936 38.339 ;
     RECT  14.856 38.339 16.272 38.435 ;
     RECT  13.848 38.435 14.184 39.157 ;
     RECT  75.288 38.579 76.992 38.629 ;
     RECT  75.288 38.629 76.944 38.771 ;
     RECT  35.112 38.675 37.584 39.253 ;
     RECT  75.288 38.771 76.992 39.733 ;
     RECT  27.72 38.819 28.8 40.309 ;
     RECT  40.872 38.819 41.856 39.635 ;
     RECT  58.152 38.963 59.76 39.013 ;
     RECT  58.152 39.013 59.472 40.835 ;
     RECT  35.112 39.253 36.48 39.973 ;
     RECT  36.504 39.253 37.584 39.877 ;
     RECT  24.984 39.491 26.016 40.499 ;
     RECT  46.008 39.493 47.472 40.883 ;
     RECT  40.872 39.635 42.144 41.893 ;
     RECT  73.272 39.733 74.448 39.877 ;
     RECT  75.288 39.733 76.944 39.877 ;
     RECT  75.288 39.877 76.416 41.029 ;
     RECT  30.264 40.067 31.68 41.077 ;
     RECT  73.272 40.355 74.688 40.931 ;
     RECT  32.76 40.403 33.792 41.413 ;
     RECT  54.576 40.403 54.912 40.693 ;
     RECT  24.696 40.499 26.016 42.325 ;
     RECT  68.136 40.645 69.648 40.931 ;
     RECT  53.592 40.693 54.912 41.123 ;
     RECT  33.816 40.835 34.8 43.381 ;
     RECT  47.832 40.837 48.912 44.483 ;
     RECT  48.936 40.837 50.256 41.749 ;
     RECT  45.912 40.883 47.472 41.651 ;
     RECT  16.824 41.075 18.6 42.037 ;
     RECT  27.912 41.075 28.944 42.133 ;
     RECT  59.496 41.171 60.624 42.227 ;
     RECT  75.288 41.171 76.416 42.947 ;
     RECT  30.264 41.219 31.68 43.141 ;
     RECT  37.608 41.315 38.592 44.917 ;
     RECT  42.408 41.509 43.872 42.851 ;
     RECT  38.616 41.651 39.936 43.573 ;
     RECT  45.912 41.651 46.2 41.893 ;
     RECT  81.432 41.651 81.48 42.661 ;
     RECT  48.936 41.749 50.112 43.045 ;
     RECT  51.312 41.939 52.416 43.139 ;
     RECT  16.824 42.037 18.24 42.803 ;
     RECT  32.76 42.227 33.792 43.427 ;
     RECT  59.808 42.227 60.624 42.709 ;
     RECT  28.392 42.275 29.4 44.389 ;
     RECT  24.696 42.563 26.016 43.859 ;
     RECT  40.872 42.563 42 43.667 ;
     RECT  77.016 42.563 78 44.195 ;
     RECT  81.768 42.661 83.184 42.709 ;
     RECT  42.408 42.851 43.128 43.813 ;
     RECT  75.264 42.947 76.416 42.997 ;
     RECT  75.048 42.997 76.416 44.725 ;
     RECT  70.368 43.043 70.56 44.389 ;
     RECT  49.128 43.045 50.112 43.379 ;
     RECT  51.312 43.139 52.608 43.331 ;
     RECT  30.36 43.141 31.68 43.909 ;
     RECT  51.312 43.331 52.752 44.773 ;
     RECT  18.912 43.381 19.92 43.573 ;
     RECT  32.76 43.427 34.464 44.581 ;
     RECT  40.872 43.667 42.384 43.909 ;
     RECT  24.696 43.859 26.736 44.677 ;
     RECT  35.208 43.859 35.832 44.725 ;
     RECT  30.36 43.909 31.584 44.243 ;
     RECT  40.92 43.909 42.384 44.437 ;
     RECT  19.896 43.955 20.328 44.101 ;
     RECT  39.048 43.955 40.2 45.059 ;
     RECT  59.256 44.003 60.288 44.099 ;
     RECT  19.896 44.101 20.88 44.675 ;
     RECT  30.264 44.243 31.584 46.645 ;
     RECT  14.184 44.437 15.648 44.965 ;
     RECT  40.968 44.437 42.384 44.675 ;
     RECT  43.224 44.437 44.736 44.965 ;
     RECT  70.584 44.437 71.904 44.773 ;
     RECT  47.808 44.483 49.008 44.581 ;
     RECT  32.76 44.581 33.744 45.539 ;
     RECT  45.912 44.581 47.424 45.587 ;
     RECT  47.448 44.581 49.008 45.059 ;
     RECT  19.896 44.675 20.928 46.979 ;
     RECT  37.536 44.675 37.584 44.725 ;
     RECT  40.872 44.675 42.384 44.723 ;
     RECT  25.56 44.677 26.736 45.541 ;
     RECT  65.832 44.677 67.2 44.819 ;
     RECT  35.208 44.725 36.48 45.731 ;
     RECT  36.504 44.725 37.584 45.059 ;
     RECT  51.312 44.773 52.368 44.915 ;
     RECT  65.688 44.819 67.2 46.211 ;
     RECT  51.312 44.915 52.464 46.069 ;
     RECT  20.952 44.917 22.224 45.157 ;
     RECT  43.224 44.965 44.208 45.635 ;
     RECT  33.768 45.059 34.8 45.539 ;
     RECT  36.504 45.059 37.632 46.307 ;
     RECT  47.448 45.059 49.104 45.541 ;
     RECT  65.232 45.155 65.472 46.165 ;
     RECT  21.24 45.157 22.224 45.491 ;
     RECT  40.512 45.395 40.824 46.645 ;
     RECT  57.096 45.395 57.336 45.635 ;
     RECT  20.952 45.491 22.224 45.635 ;
     RECT  69.048 45.493 70.368 46.117 ;
     RECT  32.76 45.539 32.808 45.589 ;
     RECT  34.656 45.539 34.8 46.069 ;
     RECT  47.88 45.541 49.104 45.635 ;
     RECT  52.776 45.541 54 45.587 ;
     RECT  54.024 45.541 55.344 45.829 ;
     RECT  52.488 45.587 54 46.787 ;
     RECT  14.664 45.635 15.648 46.645 ;
     RECT  20.952 45.635 21.048 46.501 ;
     RECT  47.88 45.635 49.392 46.211 ;
     RECT  57 45.635 57.336 46.261 ;
     RECT  70.584 45.635 71.808 46.787 ;
     RECT  62.112 45.683 63.12 46.787 ;
     RECT  35.112 45.731 36.48 46.691 ;
     RECT  37.752 46.115 38.664 46.789 ;
     RECT  65.496 46.211 67.2 46.213 ;
     RECT  65.496 46.213 66.672 46.787 ;
     RECT  44.256 46.259 44.736 47.269 ;
     RECT  73.224 46.259 74.352 47.269 ;
     RECT  57 46.261 58.128 47.269 ;
     RECT  36.504 46.307 37.728 46.691 ;
     RECT  40.728 46.645 40.824 46.837 ;
     RECT  35.112 46.691 37.728 47.171 ;
     RECT  69.048 46.691 70.032 47.845 ;
     RECT  26.76 46.787 27.84 47.845 ;
     RECT  62.112 46.787 62.616 47.845 ;
     RECT  65.496 46.787 67.2 47.173 ;
     RECT  70.584 46.787 72 47.797 ;
     RECT  78.504 46.787 79.488 46.883 ;
     RECT  37.752 46.789 38.784 46.979 ;
     RECT  38.808 46.789 40.2 46.979 ;
     RECT  75.24 46.883 76.224 48.277 ;
     RECT  78.312 46.883 79.488 48.469 ;
     RECT  19.896 46.979 20.424 47.365 ;
     RECT  37.752 46.979 40.2 47.125 ;
     RECT  37.944 47.125 40.2 47.269 ;
     RECT  35.112 47.171 37.92 47.317 ;
     RECT  65.736 47.173 67.2 48.805 ;
     RECT  37.944 47.269 39.216 48.371 ;
     RECT  57.048 47.269 58.128 48.901 ;
     RECT  35.208 47.317 36.432 47.939 ;
     RECT  36.456 47.317 37.92 47.987 ;
     RECT  76.44 47.363 77.76 48.421 ;
     RECT  33.432 47.413 34.656 47.459 ;
     RECT  33.432 47.459 34.8 49.237 ;
     RECT  25.56 47.555 26.736 49.619 ;
     RECT  60.648 47.651 61.8 48.995 ;
     RECT  44.28 47.699 45.6 47.891 ;
     RECT  45.912 47.749 46.992 48.707 ;
     RECT  70.872 47.797 72 47.845 ;
     RECT  43.944 47.891 45.6 48.997 ;
     RECT  27.72 47.939 28.752 48.949 ;
     RECT  30.072 47.939 31.2 48.995 ;
     RECT  35.112 47.939 36.432 47.987 ;
     RECT  40.512 47.939 41.52 48.997 ;
     RECT  37.008 47.987 37.92 48.421 ;
     RECT  37.008 48.421 37.872 48.805 ;
     RECT  76.44 48.421 77.568 49.571 ;
     RECT  45.912 48.707 47.016 49.765 ;
     RECT  51.312 48.707 52.464 51.157 ;
     RECT  68.376 48.755 69.36 49.765 ;
     RECT  54.168 48.901 55.44 50.147 ;
     RECT  57.048 48.901 58.032 48.949 ;
     RECT  58.056 48.947 58.248 49.045 ;
     RECT  29.712 48.995 31.2 50.819 ;
     RECT  59.832 48.995 59.976 50.005 ;
     RECT  61.584 48.995 61.8 49.045 ;
     RECT  43.944 48.997 44.928 49.333 ;
     RECT  53.064 49.043 54.144 50.101 ;
     RECT  58.056 49.045 59.136 49.187 ;
     RECT  62.664 49.091 62.808 49.477 ;
     RECT  22.608 49.187 22.656 49.573 ;
     RECT  57.624 49.187 59.136 49.235 ;
     RECT  59.232 49.235 59.808 50.677 ;
     RECT  74.952 49.283 75.936 49.475 ;
     RECT  74.952 49.475 76.368 50.339 ;
     RECT  62.664 49.477 64.032 50.195 ;
     RECT  76.44 49.571 77.712 51.491 ;
     RECT  20.424 49.573 21.6 50.291 ;
     RECT  21.624 49.573 22.656 50.291 ;
     RECT  24.6 49.619 26.736 49.811 ;
     RECT  27.72 49.715 28.752 51.253 ;
     RECT  45.912 49.765 47.04 49.861 ;
     RECT  24.408 49.811 26.736 50.101 ;
     RECT  45.912 49.861 46.944 50.101 ;
     RECT  24.408 50.101 26.688 50.629 ;
     RECT  59.832 50.147 59.976 51.205 ;
     RECT  38.184 50.149 39.504 50.245 ;
     RECT  38.184 50.245 39.216 50.339 ;
     RECT  20.184 50.291 20.328 51.637 ;
     RECT  68.136 50.291 69.216 55.283 ;
     RECT  37.896 50.339 39.216 51.829 ;
     RECT  69.432 50.339 70.704 50.771 ;
     RECT  74.952 50.339 76.416 51.349 ;
     RECT  64.968 50.387 66.288 50.819 ;
     RECT  44.136 50.579 45.6 52.595 ;
     RECT  24.408 50.629 25.92 51.923 ;
     RECT  18.912 50.675 19.92 51.251 ;
     RECT  73.272 50.723 74.352 50.819 ;
     RECT  69.432 50.771 70.752 51.347 ;
     RECT  41.064 50.819 42.048 51.635 ;
     RECT  61.584 50.819 61.8 51.829 ;
     RECT  73.272 50.819 74.928 51.827 ;
     RECT  57.816 51.109 59.232 51.923 ;
     RECT  18.912 51.251 20.16 52.213 ;
     RECT  62.112 51.347 62.232 52.309 ;
     RECT  66.288 51.347 67.104 52.405 ;
     RECT  69.24 51.347 70.752 52.261 ;
     RECT  28.296 51.395 29.4 52.981 ;
     RECT  14.184 51.491 15.648 52.259 ;
     RECT  76.44 51.491 77.904 52.501 ;
     RECT  73.272 51.827 75.216 51.973 ;
     RECT  60.024 51.829 61.296 52.693 ;
     RECT  31.992 51.875 33.072 52.739 ;
     RECT  20.28 51.923 20.328 53.077 ;
     RECT  24.312 51.923 25.92 52.981 ;
     RECT  57.288 51.923 59.52 53.365 ;
     RECT  70.776 51.923 72 52.933 ;
     RECT  73.56 51.973 75.216 52.453 ;
     RECT  81.672 52.211 83.232 53.365 ;
     RECT  18.912 52.213 20.016 53.221 ;
     RECT  14.184 52.259 16.032 52.885 ;
     RECT  69.24 52.261 70.368 52.933 ;
     RECT  22.44 52.405 23.616 52.741 ;
     RECT  64.968 52.405 66.144 53.603 ;
     RECT  74.232 52.453 75.216 52.979 ;
     RECT  76.632 52.501 77.904 53.413 ;
     RECT  30.312 52.549 31.584 52.981 ;
     RECT  60.216 52.693 61.296 52.979 ;
     RECT  31.992 52.739 33.888 53.317 ;
     RECT  51.312 52.739 52.464 55.907 ;
     RECT  14.712 52.885 16.032 53.365 ;
     RECT  70.392 52.979 71.424 53.075 ;
     RECT  24.696 52.981 25.92 53.365 ;
     RECT  46.872 52.981 47.904 54.083 ;
     RECT  55.368 52.981 56.4 55.907 ;
     RECT  79.992 53.027 81.36 53.411 ;
     RECT  22.584 53.171 23.616 54.131 ;
     RECT  19.032 53.221 20.016 57.059 ;
     RECT  36.696 53.269 37.872 53.411 ;
     RECT  32.856 53.317 33.888 55.331 ;
     RECT  14.712 53.365 15.888 53.699 ;
     RECT  57.288 53.365 58.752 54.755 ;
     RECT  82.008 53.365 83.232 55.813 ;
     RECT  79.944 53.411 81.36 54.755 ;
     RECT  76.632 53.413 77.616 53.557 ;
     RECT  21.48 53.555 22.56 55.717 ;
     RECT  24.552 53.555 25.92 55.669 ;
     RECT  30.312 53.555 31.584 53.603 ;
     RECT  40.512 53.555 41.616 54.661 ;
     RECT  38.04 53.603 39.264 54.661 ;
     RECT  65.568 53.603 66.144 54.325 ;
     RECT  14.424 53.699 15.888 54.515 ;
     RECT  31.968 53.795 32.256 55.189 ;
     RECT  29.712 54.083 30.312 55.189 ;
     RECT  46.872 54.083 47.928 54.661 ;
     RECT  22.584 54.131 24 56.387 ;
     RECT  58.776 54.179 59.808 56.531 ;
     RECT  11.4 54.227 12.48 54.419 ;
     RECT  0.36 54.419 1.392 54.755 ;
     RECT  11.4 54.419 12.528 55.669 ;
     RECT  65.592 54.611 67.104 56.341 ;
     RECT  38.04 54.661 39.216 55.717 ;
     RECT  40.512 54.661 41.568 55.477 ;
     RECT  47.304 54.661 47.928 54.997 ;
     RECT  73.752 54.661 75.216 54.853 ;
     RECT  0.264 54.755 1.392 55.571 ;
     RECT  57.24 54.755 58.752 55.237 ;
     RECT  79.896 54.755 81.36 55.525 ;
     RECT  47.304 54.997 48.432 55.907 ;
     RECT  27.912 55.187 29.04 55.283 ;
     RECT  29.712 55.189 31.2 56.483 ;
     RECT  31.224 55.189 32.256 55.813 ;
     RECT  57.24 55.237 58.56 55.813 ;
     RECT  8.664 55.283 9.696 55.331 ;
     RECT  27.72 55.283 29.04 57.059 ;
     RECT  68.136 55.283 68.376 55.861 ;
     RECT  8.664 55.331 9.744 56.581 ;
     RECT  32.856 55.331 33.984 55.907 ;
     RECT  79.896 55.525 81.264 56.627 ;
     RECT  43.752 55.669 45.024 56.003 ;
     RECT  38.184 55.717 39.216 56.869 ;
     RECT  82.104 55.813 83.232 58.117 ;
     RECT  32.328 55.907 33.984 56.437 ;
     RECT  51.312 55.907 52.512 56.723 ;
     RECT  55.344 55.907 56.4 57.157 ;
     RECT  74.136 55.907 75.408 56.003 ;
     RECT  20.04 55.955 21.024 57.107 ;
     RECT  75.432 55.955 76.416 56.003 ;
     RECT  43.752 56.003 45.504 56.293 ;
     RECT  74.136 56.003 76.416 56.965 ;
     RECT  14.904 56.053 15.936 56.965 ;
     RECT  44.472 56.293 45.504 57.011 ;
     RECT  65.592 56.341 66.912 56.531 ;
     RECT  21.672 56.387 21.96 57.589 ;
     RECT  32.328 56.437 33.6 57.875 ;
     RECT  29.712 56.483 31.44 57.059 ;
     RECT  62.112 56.483 62.664 57.541 ;
     RECT  10.872 56.531 11.952 58.501 ;
     RECT  58.776 56.531 60.096 57.973 ;
     RECT  65.4 56.531 66.912 57.635 ;
     RECT  79.752 56.627 81.264 58.595 ;
     RECT  51.312 56.723 52.704 57.445 ;
     RECT  70.44 56.819 71.424 58.163 ;
     RECT  74.136 56.965 76.368 57.205 ;
     RECT  44.472 57.011 45.6 57.299 ;
     RECT  60.552 57.013 61.8 58.163 ;
     RECT  11.976 57.059 13.056 58.501 ;
     RECT  18.912 57.059 20.016 57.107 ;
     RECT  27.72 57.059 29.4 58.117 ;
     RECT  29.712 57.059 32.256 57.301 ;
     RECT  76.632 57.059 78 57.107 ;
     RECT  20.976 57.107 21.024 58.117 ;
     RECT  57.24 57.155 58.752 58.019 ;
     RECT  55.128 57.157 56.4 57.395 ;
     RECT  74.136 57.205 75.408 57.875 ;
     RECT  30.36 57.301 32.256 57.589 ;
     RECT  51.72 57.445 52.704 57.973 ;
     RECT  31.032 57.589 32.256 58.691 ;
     RECT  69.048 57.589 70.416 58.019 ;
     RECT  65.4 57.635 67.104 58.117 ;
     RECT  14.76 57.683 15.744 58.645 ;
     RECT  32.328 57.875 32.472 58.597 ;
     RECT  50.88 57.875 51 59.221 ;
     RECT  73.752 57.875 75.408 58.259 ;
     RECT  57.24 58.019 57.384 58.211 ;
     RECT  70.08 58.019 70.416 58.163 ;
     RECT  65.88 58.117 67.104 59.315 ;
     RECT  38.04 58.163 39.264 59.027 ;
     RECT  70.08 58.163 71.424 58.403 ;
     RECT  56.712 58.211 57.384 59.221 ;
     RECT  73.752 58.259 74.04 59.221 ;
     RECT  13.512 58.355 14.496 59.557 ;
     RECT  70.08 58.403 70.104 59.029 ;
     RECT  4.824 58.451 5.904 59.267 ;
     RECT  11.976 58.501 12.96 58.739 ;
     RECT  16.344 58.595 17.424 58.691 ;
     RECT  79.752 58.595 81.408 58.979 ;
     RECT  8.568 58.691 9.696 59.747 ;
     RECT  15.96 58.691 17.424 59.315 ;
     RECT  30.264 58.691 32.256 59.027 ;
     RECT  82.2 58.691 83.232 59.603 ;
     RECT  11.736 58.739 12.96 60.035 ;
     RECT  34.272 58.739 34.704 59.989 ;
     RECT  40.512 58.787 41.568 60.661 ;
     RECT  44.472 58.837 45.6 61.619 ;
     RECT  79.752 58.979 81.792 59.315 ;
     RECT  30.264 59.027 30.792 59.989 ;
     RECT  38.64 59.027 39.264 59.701 ;
     RECT  62.112 59.027 63.12 60.515 ;
     RECT  17.448 59.219 18.48 59.315 ;
     RECT  4.824 59.267 6.048 59.411 ;
     RECT  3.336 59.315 4.8 59.363 ;
     RECT  9.96 59.315 11.184 59.795 ;
     RECT  46.632 59.315 46.776 60.325 ;
     RECT  65.88 59.315 67.2 59.363 ;
     RECT  79.656 59.315 81.792 59.797 ;
     RECT  21.144 59.459 21.528 60.949 ;
     RECT  82.2 59.603 83.28 60.131 ;
     RECT  35.112 59.651 36.432 61.091 ;
     RECT  14.712 59.699 15.744 61.475 ;
     RECT  8.568 59.747 9.936 59.795 ;
     RECT  79.656 59.797 80.736 60.515 ;
     RECT  80.76 59.797 81.792 60.515 ;
     RECT  78.552 59.891 79.536 60.419 ;
     RECT  32.472 59.989 33.84 60.563 ;
     RECT  11.736 60.035 13.2 61.619 ;
     RECT  13.512 60.035 14.496 60.419 ;
     RECT  51.312 60.035 52.368 62.195 ;
     RECT  82.2 60.131 83.4 60.419 ;
     RECT  13.512 60.419 14.688 62.195 ;
     RECT  78.312 60.419 79.536 60.947 ;
     RECT  24.696 60.563 25.68 60.611 ;
     RECT  24.6 60.611 25.68 60.659 ;
     RECT  27.576 60.611 28.848 61.859 ;
     RECT  24.6 60.659 26.112 61.235 ;
     RECT  23.376 60.803 23.808 60.949 ;
     RECT  72.912 60.851 74.016 61.619 ;
     RECT  78.312 60.947 79.632 61.379 ;
     RECT  21.144 60.949 22.656 61.571 ;
     RECT  22.68 60.949 23.808 61.907 ;
     RECT  49.848 61.043 51 61.907 ;
     RECT  26.136 61.187 27.552 61.859 ;
     RECT  40.512 61.235 41.616 62.003 ;
     RECT  14.712 61.475 15.792 61.907 ;
     RECT  55.416 61.525 56.4 61.763 ;
     RECT  22.68 61.907 24 62.195 ;
  END
END dsfd_r2l_vr_512x1__hsel
END LIBRARY
